VERSION 5.8 ;
BUSBITCHARS "[]" ;
DIVIDERCHAR "/" ;
UNITS
    DATABASE MICRONS 1000 ;
END UNITS

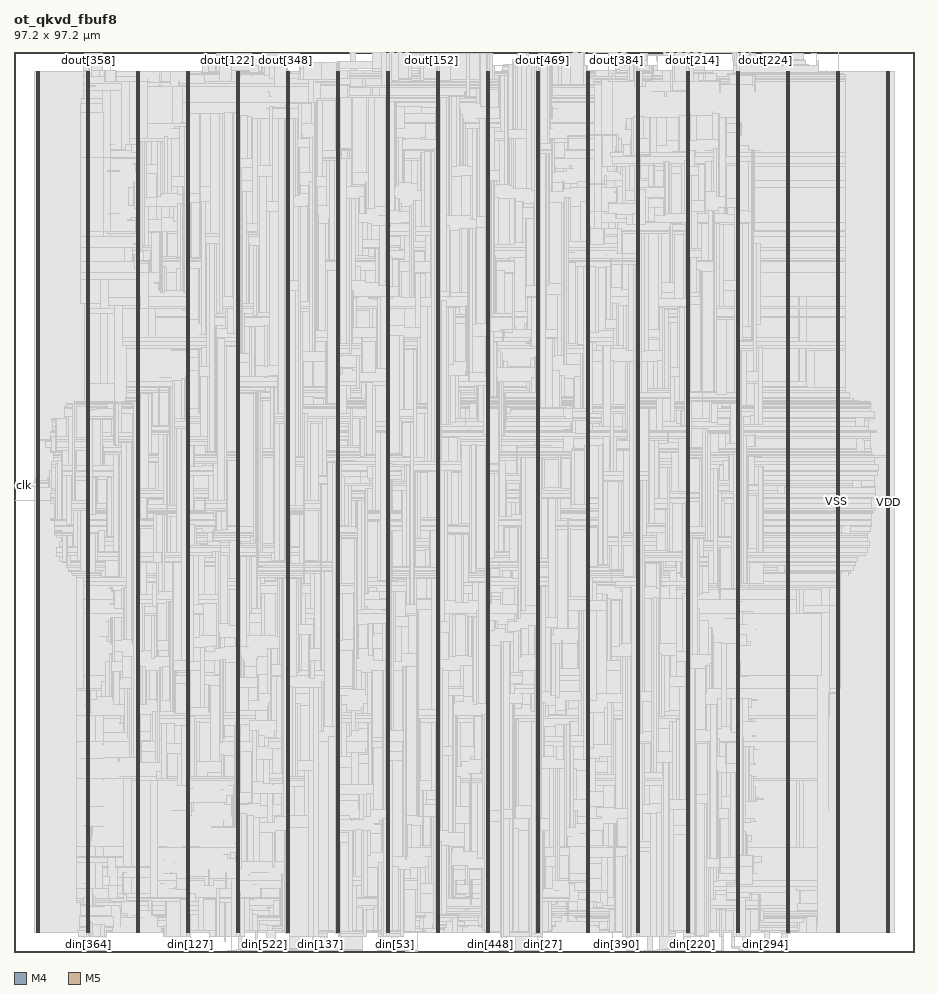
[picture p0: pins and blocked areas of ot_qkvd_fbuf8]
MACRO ot_qkvd_fbuf8
  FOREIGN ot_qkvd_fbuf8 0 0 ;
  CLASS BLOCK ;
  SIZE 97.2 BY 97.2 ;
  PIN clk
    DIRECTION INPUT ;
    USE SIGNAL ;
    PORT
      LAYER M4 ;
        RECT  0 50.352 0.084 50.376 ;
    END
  END clk
  PIN din[0]
    DIRECTION INPUT ;
    USE SIGNAL ;
    PORT
      LAYER M5 ;
        RECT  54.48 0 54.504 0.084 ;
    END
  END din[0]
  PIN din[100]
    DIRECTION INPUT ;
    USE SIGNAL ;
    PORT
      LAYER M5 ;
        RECT  16.464 0 16.488 0.084 ;
    END
  END din[100]
  PIN din[101]
    DIRECTION INPUT ;
    USE SIGNAL ;
    PORT
      LAYER M5 ;
        RECT  16.56 0 16.584 0.084 ;
    END
  END din[101]
  PIN din[102]
    DIRECTION INPUT ;
    USE SIGNAL ;
    PORT
      LAYER M5 ;
        RECT  16.656 0 16.68 0.084 ;
    END
  END din[102]
  PIN din[103]
    DIRECTION INPUT ;
    USE SIGNAL ;
    PORT
      LAYER M5 ;
        RECT  16.752 0 16.776 0.084 ;
    END
  END din[103]
  PIN din[104]
    DIRECTION INPUT ;
    USE SIGNAL ;
    PORT
      LAYER M5 ;
        RECT  16.848 0 16.872 0.084 ;
    END
  END din[104]
  PIN din[105]
    DIRECTION INPUT ;
    USE SIGNAL ;
    PORT
      LAYER M5 ;
        RECT  16.944 0 16.968 0.084 ;
    END
  END din[105]
  PIN din[106]
    DIRECTION INPUT ;
    USE SIGNAL ;
    PORT
      LAYER M5 ;
        RECT  17.04 0 17.064 0.084 ;
    END
  END din[106]
  PIN din[107]
    DIRECTION INPUT ;
    USE SIGNAL ;
    PORT
      LAYER M5 ;
        RECT  17.136 0 17.16 0.084 ;
    END
  END din[107]
  PIN din[108]
    DIRECTION INPUT ;
    USE SIGNAL ;
    PORT
      LAYER M5 ;
        RECT  17.232 0 17.256 0.084 ;
    END
  END din[108]
  PIN din[109]
    DIRECTION INPUT ;
    USE SIGNAL ;
    PORT
      LAYER M5 ;
        RECT  17.328 0 17.352 0.084 ;
    END
  END din[109]
  PIN din[10]
    DIRECTION INPUT ;
    USE SIGNAL ;
    PORT
      LAYER M5 ;
        RECT  55.44 0 55.464 0.084 ;
    END
  END din[10]
  PIN din[110]
    DIRECTION INPUT ;
    USE SIGNAL ;
    PORT
      LAYER M5 ;
        RECT  17.424 0 17.448 0.084 ;
    END
  END din[110]
  PIN din[111]
    DIRECTION INPUT ;
    USE SIGNAL ;
    PORT
      LAYER M5 ;
        RECT  17.52 0 17.544 0.084 ;
    END
  END din[111]
  PIN din[112]
    DIRECTION INPUT ;
    USE SIGNAL ;
    PORT
      LAYER M5 ;
        RECT  17.616 0 17.64 0.084 ;
    END
  END din[112]
  PIN din[113]
    DIRECTION INPUT ;
    USE SIGNAL ;
    PORT
      LAYER M5 ;
        RECT  17.712 0 17.736 0.084 ;
    END
  END din[113]
  PIN din[114]
    DIRECTION INPUT ;
    USE SIGNAL ;
    PORT
      LAYER M5 ;
        RECT  17.808 0 17.832 0.084 ;
    END
  END din[114]
  PIN din[115]
    DIRECTION INPUT ;
    USE SIGNAL ;
    PORT
      LAYER M5 ;
        RECT  17.904 0 17.928 0.084 ;
    END
  END din[115]
  PIN din[116]
    DIRECTION INPUT ;
    USE SIGNAL ;
    PORT
      LAYER M5 ;
        RECT  18 0 18.024 0.084 ;
    END
  END din[116]
  PIN din[117]
    DIRECTION INPUT ;
    USE SIGNAL ;
    PORT
      LAYER M5 ;
        RECT  18.096 0 18.12 0.084 ;
    END
  END din[117]
  PIN din[118]
    DIRECTION INPUT ;
    USE SIGNAL ;
    PORT
      LAYER M5 ;
        RECT  18.192 0 18.216 0.084 ;
    END
  END din[118]
  PIN din[119]
    DIRECTION INPUT ;
    USE SIGNAL ;
    PORT
      LAYER M5 ;
        RECT  18.288 0 18.312 0.084 ;
    END
  END din[119]
  PIN din[11]
    DIRECTION INPUT ;
    USE SIGNAL ;
    PORT
      LAYER M5 ;
        RECT  55.536 0 55.56 0.084 ;
    END
  END din[11]
  PIN din[120]
    DIRECTION INPUT ;
    USE SIGNAL ;
    PORT
      LAYER M5 ;
        RECT  18.384 0 18.408 0.084 ;
    END
  END din[120]
  PIN din[121]
    DIRECTION INPUT ;
    USE SIGNAL ;
    PORT
      LAYER M5 ;
        RECT  18.48 0 18.504 0.084 ;
    END
  END din[121]
  PIN din[122]
    DIRECTION INPUT ;
    USE SIGNAL ;
    PORT
      LAYER M5 ;
        RECT  18.576 0 18.6 0.084 ;
    END
  END din[122]
  PIN din[123]
    DIRECTION INPUT ;
    USE SIGNAL ;
    PORT
      LAYER M5 ;
        RECT  18.672 0 18.696 0.084 ;
    END
  END din[123]
  PIN din[124]
    DIRECTION INPUT ;
    USE SIGNAL ;
    PORT
      LAYER M5 ;
        RECT  18.768 0 18.792 0.084 ;
    END
  END din[124]
  PIN din[125]
    DIRECTION INPUT ;
    USE SIGNAL ;
    PORT
      LAYER M5 ;
        RECT  18.864 0 18.888 0.084 ;
    END
  END din[125]
  PIN din[126]
    DIRECTION INPUT ;
    USE SIGNAL ;
    PORT
      LAYER M5 ;
        RECT  18.96 0 18.984 0.084 ;
    END
  END din[126]
  PIN din[127]
    DIRECTION INPUT ;
    USE SIGNAL ;
    PORT
      LAYER M5 ;
        RECT  19.056 0 19.08 0.084 ;
    END
  END din[127]
  PIN din[128]
    DIRECTION INPUT ;
    USE SIGNAL ;
    PORT
      LAYER M5 ;
        RECT  32.208 0 32.232 0.084 ;
    END
  END din[128]
  PIN din[129]
    DIRECTION INPUT ;
    USE SIGNAL ;
    PORT
      LAYER M5 ;
        RECT  32.304 0 32.328 0.084 ;
    END
  END din[129]
  PIN din[12]
    DIRECTION INPUT ;
    USE SIGNAL ;
    PORT
      LAYER M5 ;
        RECT  55.632 0 55.656 0.084 ;
    END
  END din[12]
  PIN din[130]
    DIRECTION INPUT ;
    USE SIGNAL ;
    PORT
      LAYER M5 ;
        RECT  32.4 0 32.424 0.084 ;
    END
  END din[130]
  PIN din[131]
    DIRECTION INPUT ;
    USE SIGNAL ;
    PORT
      LAYER M5 ;
        RECT  32.496 0 32.52 0.084 ;
    END
  END din[131]
  PIN din[132]
    DIRECTION INPUT ;
    USE SIGNAL ;
    PORT
      LAYER M5 ;
        RECT  32.592 0 32.616 0.084 ;
    END
  END din[132]
  PIN din[133]
    DIRECTION INPUT ;
    USE SIGNAL ;
    PORT
      LAYER M5 ;
        RECT  32.688 0 32.712 0.084 ;
    END
  END din[133]
  PIN din[134]
    DIRECTION INPUT ;
    USE SIGNAL ;
    PORT
      LAYER M5 ;
        RECT  32.784 0 32.808 0.084 ;
    END
  END din[134]
  PIN din[135]
    DIRECTION INPUT ;
    USE SIGNAL ;
    PORT
      LAYER M5 ;
        RECT  32.88 0 32.904 0.084 ;
    END
  END din[135]
  PIN din[136]
    DIRECTION INPUT ;
    USE SIGNAL ;
    PORT
      LAYER M5 ;
        RECT  32.976 0 33 0.084 ;
    END
  END din[136]
  PIN din[137]
    DIRECTION INPUT ;
    USE SIGNAL ;
    PORT
      LAYER M5 ;
        RECT  33.072 0 33.096 0.084 ;
    END
  END din[137]
  PIN din[138]
    DIRECTION INPUT ;
    USE SIGNAL ;
    PORT
      LAYER M5 ;
        RECT  33.168 0 33.192 0.084 ;
    END
  END din[138]
  PIN din[139]
    DIRECTION INPUT ;
    USE SIGNAL ;
    PORT
      LAYER M5 ;
        RECT  33.264 0 33.288 0.084 ;
    END
  END din[139]
  PIN din[13]
    DIRECTION INPUT ;
    USE SIGNAL ;
    PORT
      LAYER M5 ;
        RECT  55.728 0 55.752 0.084 ;
    END
  END din[13]
  PIN din[140]
    DIRECTION INPUT ;
    USE SIGNAL ;
    PORT
      LAYER M5 ;
        RECT  33.36 0 33.384 0.084 ;
    END
  END din[140]
  PIN din[141]
    DIRECTION INPUT ;
    USE SIGNAL ;
    PORT
      LAYER M5 ;
        RECT  33.456 0 33.48 0.084 ;
    END
  END din[141]
  PIN din[142]
    DIRECTION INPUT ;
    USE SIGNAL ;
    PORT
      LAYER M5 ;
        RECT  33.552 0 33.576 0.084 ;
    END
  END din[142]
  PIN din[143]
    DIRECTION INPUT ;
    USE SIGNAL ;
    PORT
      LAYER M5 ;
        RECT  33.648 0 33.672 0.084 ;
    END
  END din[143]
  PIN din[144]
    DIRECTION INPUT ;
    USE SIGNAL ;
    PORT
      LAYER M5 ;
        RECT  33.744 0 33.768 0.084 ;
    END
  END din[144]
  PIN din[145]
    DIRECTION INPUT ;
    USE SIGNAL ;
    PORT
      LAYER M5 ;
        RECT  33.84 0 33.864 0.084 ;
    END
  END din[145]
  PIN din[146]
    DIRECTION INPUT ;
    USE SIGNAL ;
    PORT
      LAYER M5 ;
        RECT  33.936 0 33.96 0.084 ;
    END
  END din[146]
  PIN din[147]
    DIRECTION INPUT ;
    USE SIGNAL ;
    PORT
      LAYER M5 ;
        RECT  34.032 0 34.056 0.084 ;
    END
  END din[147]
  PIN din[148]
    DIRECTION INPUT ;
    USE SIGNAL ;
    PORT
      LAYER M5 ;
        RECT  34.128 0 34.152 0.084 ;
    END
  END din[148]
  PIN din[149]
    DIRECTION INPUT ;
    USE SIGNAL ;
    PORT
      LAYER M5 ;
        RECT  34.224 0 34.248 0.084 ;
    END
  END din[149]
  PIN din[14]
    DIRECTION INPUT ;
    USE SIGNAL ;
    PORT
      LAYER M5 ;
        RECT  55.824 0 55.848 0.084 ;
    END
  END din[14]
  PIN din[150]
    DIRECTION INPUT ;
    USE SIGNAL ;
    PORT
      LAYER M5 ;
        RECT  34.32 0 34.344 0.084 ;
    END
  END din[150]
  PIN din[151]
    DIRECTION INPUT ;
    USE SIGNAL ;
    PORT
      LAYER M5 ;
        RECT  34.416 0 34.44 0.084 ;
    END
  END din[151]
  PIN din[152]
    DIRECTION INPUT ;
    USE SIGNAL ;
    PORT
      LAYER M5 ;
        RECT  34.512 0 34.536 0.084 ;
    END
  END din[152]
  PIN din[153]
    DIRECTION INPUT ;
    USE SIGNAL ;
    PORT
      LAYER M5 ;
        RECT  34.608 0 34.632 0.084 ;
    END
  END din[153]
  PIN din[154]
    DIRECTION INPUT ;
    USE SIGNAL ;
    PORT
      LAYER M5 ;
        RECT  34.704 0 34.728 0.084 ;
    END
  END din[154]
  PIN din[155]
    DIRECTION INPUT ;
    USE SIGNAL ;
    PORT
      LAYER M5 ;
        RECT  34.8 0 34.824 0.084 ;
    END
  END din[155]
  PIN din[156]
    DIRECTION INPUT ;
    USE SIGNAL ;
    PORT
      LAYER M5 ;
        RECT  34.896 0 34.92 0.084 ;
    END
  END din[156]
  PIN din[157]
    DIRECTION INPUT ;
    USE SIGNAL ;
    PORT
      LAYER M5 ;
        RECT  34.992 0 35.016 0.084 ;
    END
  END din[157]
  PIN din[158]
    DIRECTION INPUT ;
    USE SIGNAL ;
    PORT
      LAYER M5 ;
        RECT  35.088 0 35.112 0.084 ;
    END
  END din[158]
  PIN din[159]
    DIRECTION INPUT ;
    USE SIGNAL ;
    PORT
      LAYER M5 ;
        RECT  35.184 0 35.208 0.084 ;
    END
  END din[159]
  PIN din[15]
    DIRECTION INPUT ;
    USE SIGNAL ;
    PORT
      LAYER M5 ;
        RECT  55.92 0 55.944 0.084 ;
    END
  END din[15]
  PIN din[160]
    DIRECTION INPUT ;
    USE SIGNAL ;
    PORT
      LAYER M5 ;
        RECT  19.92 0 19.944 0.084 ;
    END
  END din[160]
  PIN din[161]
    DIRECTION INPUT ;
    USE SIGNAL ;
    PORT
      LAYER M5 ;
        RECT  20.016 0 20.04 0.084 ;
    END
  END din[161]
  PIN din[162]
    DIRECTION INPUT ;
    USE SIGNAL ;
    PORT
      LAYER M5 ;
        RECT  20.112 0 20.136 0.084 ;
    END
  END din[162]
  PIN din[163]
    DIRECTION INPUT ;
    USE SIGNAL ;
    PORT
      LAYER M5 ;
        RECT  20.208 0 20.232 0.084 ;
    END
  END din[163]
  PIN din[164]
    DIRECTION INPUT ;
    USE SIGNAL ;
    PORT
      LAYER M5 ;
        RECT  20.304 0 20.328 0.084 ;
    END
  END din[164]
  PIN din[165]
    DIRECTION INPUT ;
    USE SIGNAL ;
    PORT
      LAYER M5 ;
        RECT  20.4 0 20.424 0.084 ;
    END
  END din[165]
  PIN din[166]
    DIRECTION INPUT ;
    USE SIGNAL ;
    PORT
      LAYER M5 ;
        RECT  20.496 0 20.52 0.084 ;
    END
  END din[166]
  PIN din[167]
    DIRECTION INPUT ;
    USE SIGNAL ;
    PORT
      LAYER M5 ;
        RECT  20.592 0 20.616 0.084 ;
    END
  END din[167]
  PIN din[168]
    DIRECTION INPUT ;
    USE SIGNAL ;
    PORT
      LAYER M5 ;
        RECT  20.688 0 20.712 0.084 ;
    END
  END din[168]
  PIN din[169]
    DIRECTION INPUT ;
    USE SIGNAL ;
    PORT
      LAYER M5 ;
        RECT  20.784 0 20.808 0.084 ;
    END
  END din[169]
  PIN din[16]
    DIRECTION INPUT ;
    USE SIGNAL ;
    PORT
      LAYER M5 ;
        RECT  56.016 0 56.04 0.084 ;
    END
  END din[16]
  PIN din[170]
    DIRECTION INPUT ;
    USE SIGNAL ;
    PORT
      LAYER M5 ;
        RECT  20.88 0 20.904 0.084 ;
    END
  END din[170]
  PIN din[171]
    DIRECTION INPUT ;
    USE SIGNAL ;
    PORT
      LAYER M5 ;
        RECT  20.976 0 21 0.084 ;
    END
  END din[171]
  PIN din[172]
    DIRECTION INPUT ;
    USE SIGNAL ;
    PORT
      LAYER M5 ;
        RECT  21.072 0 21.096 0.084 ;
    END
  END din[172]
  PIN din[173]
    DIRECTION INPUT ;
    USE SIGNAL ;
    PORT
      LAYER M5 ;
        RECT  21.168 0 21.192 0.084 ;
    END
  END din[173]
  PIN din[174]
    DIRECTION INPUT ;
    USE SIGNAL ;
    PORT
      LAYER M5 ;
        RECT  21.264 0 21.288 0.084 ;
    END
  END din[174]
  PIN din[175]
    DIRECTION INPUT ;
    USE SIGNAL ;
    PORT
      LAYER M5 ;
        RECT  21.36 0 21.384 0.084 ;
    END
  END din[175]
  PIN din[176]
    DIRECTION INPUT ;
    USE SIGNAL ;
    PORT
      LAYER M5 ;
        RECT  21.456 0 21.48 0.084 ;
    END
  END din[176]
  PIN din[177]
    DIRECTION INPUT ;
    USE SIGNAL ;
    PORT
      LAYER M5 ;
        RECT  21.552 0 21.576 0.084 ;
    END
  END din[177]
  PIN din[178]
    DIRECTION INPUT ;
    USE SIGNAL ;
    PORT
      LAYER M5 ;
        RECT  21.648 0 21.672 0.084 ;
    END
  END din[178]
  PIN din[179]
    DIRECTION INPUT ;
    USE SIGNAL ;
    PORT
      LAYER M5 ;
        RECT  21.744 0 21.768 0.084 ;
    END
  END din[179]
  PIN din[17]
    DIRECTION INPUT ;
    USE SIGNAL ;
    PORT
      LAYER M5 ;
        RECT  56.112 0 56.136 0.084 ;
    END
  END din[17]
  PIN din[180]
    DIRECTION INPUT ;
    USE SIGNAL ;
    PORT
      LAYER M5 ;
        RECT  21.84 0 21.864 0.084 ;
    END
  END din[180]
  PIN din[181]
    DIRECTION INPUT ;
    USE SIGNAL ;
    PORT
      LAYER M5 ;
        RECT  21.936 0 21.96 0.084 ;
    END
  END din[181]
  PIN din[182]
    DIRECTION INPUT ;
    USE SIGNAL ;
    PORT
      LAYER M5 ;
        RECT  22.032 0 22.056 0.084 ;
    END
  END din[182]
  PIN din[183]
    DIRECTION INPUT ;
    USE SIGNAL ;
    PORT
      LAYER M5 ;
        RECT  22.128 0 22.152 0.084 ;
    END
  END din[183]
  PIN din[184]
    DIRECTION INPUT ;
    USE SIGNAL ;
    PORT
      LAYER M5 ;
        RECT  22.224 0 22.248 0.084 ;
    END
  END din[184]
  PIN din[185]
    DIRECTION INPUT ;
    USE SIGNAL ;
    PORT
      LAYER M5 ;
        RECT  22.32 0 22.344 0.084 ;
    END
  END din[185]
  PIN din[186]
    DIRECTION INPUT ;
    USE SIGNAL ;
    PORT
      LAYER M5 ;
        RECT  22.416 0 22.44 0.084 ;
    END
  END din[186]
  PIN din[187]
    DIRECTION INPUT ;
    USE SIGNAL ;
    PORT
      LAYER M5 ;
        RECT  22.512 0 22.536 0.084 ;
    END
  END din[187]
  PIN din[188]
    DIRECTION INPUT ;
    USE SIGNAL ;
    PORT
      LAYER M5 ;
        RECT  22.608 0 22.632 0.084 ;
    END
  END din[188]
  PIN din[189]
    DIRECTION INPUT ;
    USE SIGNAL ;
    PORT
      LAYER M5 ;
        RECT  22.704 0 22.728 0.084 ;
    END
  END din[189]
  PIN din[18]
    DIRECTION INPUT ;
    USE SIGNAL ;
    PORT
      LAYER M5 ;
        RECT  56.208 0 56.232 0.084 ;
    END
  END din[18]
  PIN din[190]
    DIRECTION INPUT ;
    USE SIGNAL ;
    PORT
      LAYER M5 ;
        RECT  22.8 0 22.824 0.084 ;
    END
  END din[190]
  PIN din[191]
    DIRECTION INPUT ;
    USE SIGNAL ;
    PORT
      LAYER M5 ;
        RECT  22.896 0 22.92 0.084 ;
    END
  END din[191]
  PIN din[192]
    DIRECTION INPUT ;
    USE SIGNAL ;
    PORT
      LAYER M5 ;
        RECT  70.608 0 70.632 0.084 ;
    END
  END din[192]
  PIN din[193]
    DIRECTION INPUT ;
    USE SIGNAL ;
    PORT
      LAYER M5 ;
        RECT  70.704 0 70.728 0.084 ;
    END
  END din[193]
  PIN din[194]
    DIRECTION INPUT ;
    USE SIGNAL ;
    PORT
      LAYER M5 ;
        RECT  70.8 0 70.824 0.084 ;
    END
  END din[194]
  PIN din[195]
    DIRECTION INPUT ;
    USE SIGNAL ;
    PORT
      LAYER M5 ;
        RECT  70.896 0 70.92 0.084 ;
    END
  END din[195]
  PIN din[196]
    DIRECTION INPUT ;
    USE SIGNAL ;
    PORT
      LAYER M5 ;
        RECT  70.992 0 71.016 0.084 ;
    END
  END din[196]
  PIN din[197]
    DIRECTION INPUT ;
    USE SIGNAL ;
    PORT
      LAYER M5 ;
        RECT  71.088 0 71.112 0.084 ;
    END
  END din[197]
  PIN din[198]
    DIRECTION INPUT ;
    USE SIGNAL ;
    PORT
      LAYER M5 ;
        RECT  71.184 0 71.208 0.084 ;
    END
  END din[198]
  PIN din[199]
    DIRECTION INPUT ;
    USE SIGNAL ;
    PORT
      LAYER M5 ;
        RECT  71.28 0 71.304 0.084 ;
    END
  END din[199]
  PIN din[19]
    DIRECTION INPUT ;
    USE SIGNAL ;
    PORT
      LAYER M5 ;
        RECT  56.304 0 56.328 0.084 ;
    END
  END din[19]
  PIN din[1]
    DIRECTION INPUT ;
    USE SIGNAL ;
    PORT
      LAYER M5 ;
        RECT  54.576 0 54.6 0.084 ;
    END
  END din[1]
  PIN din[200]
    DIRECTION INPUT ;
    USE SIGNAL ;
    PORT
      LAYER M5 ;
        RECT  71.376 0 71.4 0.084 ;
    END
  END din[200]
  PIN din[201]
    DIRECTION INPUT ;
    USE SIGNAL ;
    PORT
      LAYER M5 ;
        RECT  71.472 0 71.496 0.084 ;
    END
  END din[201]
  PIN din[202]
    DIRECTION INPUT ;
    USE SIGNAL ;
    PORT
      LAYER M5 ;
        RECT  71.568 0 71.592 0.084 ;
    END
  END din[202]
  PIN din[203]
    DIRECTION INPUT ;
    USE SIGNAL ;
    PORT
      LAYER M5 ;
        RECT  71.664 0 71.688 0.084 ;
    END
  END din[203]
  PIN din[204]
    DIRECTION INPUT ;
    USE SIGNAL ;
    PORT
      LAYER M5 ;
        RECT  71.76 0 71.784 0.084 ;
    END
  END din[204]
  PIN din[205]
    DIRECTION INPUT ;
    USE SIGNAL ;
    PORT
      LAYER M5 ;
        RECT  71.856 0 71.88 0.084 ;
    END
  END din[205]
  PIN din[206]
    DIRECTION INPUT ;
    USE SIGNAL ;
    PORT
      LAYER M5 ;
        RECT  71.952 0 71.976 0.084 ;
    END
  END din[206]
  PIN din[207]
    DIRECTION INPUT ;
    USE SIGNAL ;
    PORT
      LAYER M5 ;
        RECT  72.048 0 72.072 0.084 ;
    END
  END din[207]
  PIN din[208]
    DIRECTION INPUT ;
    USE SIGNAL ;
    PORT
      LAYER M5 ;
        RECT  72.144 0 72.168 0.084 ;
    END
  END din[208]
  PIN din[209]
    DIRECTION INPUT ;
    USE SIGNAL ;
    PORT
      LAYER M5 ;
        RECT  72.24 0 72.264 0.084 ;
    END
  END din[209]
  PIN din[20]
    DIRECTION INPUT ;
    USE SIGNAL ;
    PORT
      LAYER M5 ;
        RECT  56.4 0 56.424 0.084 ;
    END
  END din[20]
  PIN din[210]
    DIRECTION INPUT ;
    USE SIGNAL ;
    PORT
      LAYER M5 ;
        RECT  72.336 0 72.36 0.084 ;
    END
  END din[210]
  PIN din[211]
    DIRECTION INPUT ;
    USE SIGNAL ;
    PORT
      LAYER M5 ;
        RECT  72.432 0 72.456 0.084 ;
    END
  END din[211]
  PIN din[212]
    DIRECTION INPUT ;
    USE SIGNAL ;
    PORT
      LAYER M5 ;
        RECT  72.528 0 72.552 0.084 ;
    END
  END din[212]
  PIN din[213]
    DIRECTION INPUT ;
    USE SIGNAL ;
    PORT
      LAYER M5 ;
        RECT  72.624 0 72.648 0.084 ;
    END
  END din[213]
  PIN din[214]
    DIRECTION INPUT ;
    USE SIGNAL ;
    PORT
      LAYER M5 ;
        RECT  72.72 0 72.744 0.084 ;
    END
  END din[214]
  PIN din[215]
    DIRECTION INPUT ;
    USE SIGNAL ;
    PORT
      LAYER M5 ;
        RECT  72.816 0 72.84 0.084 ;
    END
  END din[215]
  PIN din[216]
    DIRECTION INPUT ;
    USE SIGNAL ;
    PORT
      LAYER M5 ;
        RECT  72.912 0 72.936 0.084 ;
    END
  END din[216]
  PIN din[217]
    DIRECTION INPUT ;
    USE SIGNAL ;
    PORT
      LAYER M5 ;
        RECT  73.008 0 73.032 0.084 ;
    END
  END din[217]
  PIN din[218]
    DIRECTION INPUT ;
    USE SIGNAL ;
    PORT
      LAYER M5 ;
        RECT  73.104 0 73.128 0.084 ;
    END
  END din[218]
  PIN din[219]
    DIRECTION INPUT ;
    USE SIGNAL ;
    PORT
      LAYER M5 ;
        RECT  73.2 0 73.224 0.084 ;
    END
  END din[219]
  PIN din[21]
    DIRECTION INPUT ;
    USE SIGNAL ;
    PORT
      LAYER M5 ;
        RECT  56.496 0 56.52 0.084 ;
    END
  END din[21]
  PIN din[220]
    DIRECTION INPUT ;
    USE SIGNAL ;
    PORT
      LAYER M5 ;
        RECT  73.296 0 73.32 0.084 ;
    END
  END din[220]
  PIN din[221]
    DIRECTION INPUT ;
    USE SIGNAL ;
    PORT
      LAYER M5 ;
        RECT  73.392 0 73.416 0.084 ;
    END
  END din[221]
  PIN din[222]
    DIRECTION INPUT ;
    USE SIGNAL ;
    PORT
      LAYER M5 ;
        RECT  73.488 0 73.512 0.084 ;
    END
  END din[222]
  PIN din[223]
    DIRECTION INPUT ;
    USE SIGNAL ;
    PORT
      LAYER M5 ;
        RECT  73.584 0 73.608 0.084 ;
    END
  END din[223]
  PIN din[224]
    DIRECTION INPUT ;
    USE SIGNAL ;
    PORT
      LAYER M5 ;
        RECT  77.52 0 77.544 0.084 ;
    END
  END din[224]
  PIN din[225]
    DIRECTION INPUT ;
    USE SIGNAL ;
    PORT
      LAYER M5 ;
        RECT  77.616 0 77.64 0.084 ;
    END
  END din[225]
  PIN din[226]
    DIRECTION INPUT ;
    USE SIGNAL ;
    PORT
      LAYER M5 ;
        RECT  77.712 0 77.736 0.084 ;
    END
  END din[226]
  PIN din[227]
    DIRECTION INPUT ;
    USE SIGNAL ;
    PORT
      LAYER M5 ;
        RECT  77.808 0 77.832 0.084 ;
    END
  END din[227]
  PIN din[228]
    DIRECTION INPUT ;
    USE SIGNAL ;
    PORT
      LAYER M5 ;
        RECT  77.904 0 77.928 0.084 ;
    END
  END din[228]
  PIN din[229]
    DIRECTION INPUT ;
    USE SIGNAL ;
    PORT
      LAYER M5 ;
        RECT  78 0 78.024 0.084 ;
    END
  END din[229]
  PIN din[22]
    DIRECTION INPUT ;
    USE SIGNAL ;
    PORT
      LAYER M5 ;
        RECT  56.592 0 56.616 0.084 ;
    END
  END din[22]
  PIN din[230]
    DIRECTION INPUT ;
    USE SIGNAL ;
    PORT
      LAYER M5 ;
        RECT  78.096 0 78.12 0.084 ;
    END
  END din[230]
  PIN din[231]
    DIRECTION INPUT ;
    USE SIGNAL ;
    PORT
      LAYER M5 ;
        RECT  78.192 0 78.216 0.084 ;
    END
  END din[231]
  PIN din[232]
    DIRECTION INPUT ;
    USE SIGNAL ;
    PORT
      LAYER M5 ;
        RECT  78.288 0 78.312 0.084 ;
    END
  END din[232]
  PIN din[233]
    DIRECTION INPUT ;
    USE SIGNAL ;
    PORT
      LAYER M5 ;
        RECT  78.384 0 78.408 0.084 ;
    END
  END din[233]
  PIN din[234]
    DIRECTION INPUT ;
    USE SIGNAL ;
    PORT
      LAYER M5 ;
        RECT  78.48 0 78.504 0.084 ;
    END
  END din[234]
  PIN din[235]
    DIRECTION INPUT ;
    USE SIGNAL ;
    PORT
      LAYER M5 ;
        RECT  78.576 0 78.6 0.084 ;
    END
  END din[235]
  PIN din[236]
    DIRECTION INPUT ;
    USE SIGNAL ;
    PORT
      LAYER M5 ;
        RECT  78.672 0 78.696 0.084 ;
    END
  END din[236]
  PIN din[237]
    DIRECTION INPUT ;
    USE SIGNAL ;
    PORT
      LAYER M5 ;
        RECT  78.768 0 78.792 0.084 ;
    END
  END din[237]
  PIN din[238]
    DIRECTION INPUT ;
    USE SIGNAL ;
    PORT
      LAYER M5 ;
        RECT  78.864 0 78.888 0.084 ;
    END
  END din[238]
  PIN din[239]
    DIRECTION INPUT ;
    USE SIGNAL ;
    PORT
      LAYER M5 ;
        RECT  78.96 0 78.984 0.084 ;
    END
  END din[239]
  PIN din[23]
    DIRECTION INPUT ;
    USE SIGNAL ;
    PORT
      LAYER M5 ;
        RECT  56.688 0 56.712 0.084 ;
    END
  END din[23]
  PIN din[240]
    DIRECTION INPUT ;
    USE SIGNAL ;
    PORT
      LAYER M5 ;
        RECT  79.056 0 79.08 0.084 ;
    END
  END din[240]
  PIN din[241]
    DIRECTION INPUT ;
    USE SIGNAL ;
    PORT
      LAYER M5 ;
        RECT  79.152 0 79.176 0.084 ;
    END
  END din[241]
  PIN din[242]
    DIRECTION INPUT ;
    USE SIGNAL ;
    PORT
      LAYER M5 ;
        RECT  79.248 0 79.272 0.084 ;
    END
  END din[242]
  PIN din[243]
    DIRECTION INPUT ;
    USE SIGNAL ;
    PORT
      LAYER M5 ;
        RECT  79.344 0 79.368 0.084 ;
    END
  END din[243]
  PIN din[244]
    DIRECTION INPUT ;
    USE SIGNAL ;
    PORT
      LAYER M5 ;
        RECT  79.44 0 79.464 0.084 ;
    END
  END din[244]
  PIN din[245]
    DIRECTION INPUT ;
    USE SIGNAL ;
    PORT
      LAYER M5 ;
        RECT  79.536 0 79.56 0.084 ;
    END
  END din[245]
  PIN din[246]
    DIRECTION INPUT ;
    USE SIGNAL ;
    PORT
      LAYER M5 ;
        RECT  79.632 0 79.656 0.084 ;
    END
  END din[246]
  PIN din[247]
    DIRECTION INPUT ;
    USE SIGNAL ;
    PORT
      LAYER M5 ;
        RECT  79.728 0 79.752 0.084 ;
    END
  END din[247]
  PIN din[248]
    DIRECTION INPUT ;
    USE SIGNAL ;
    PORT
      LAYER M5 ;
        RECT  79.824 0 79.848 0.084 ;
    END
  END din[248]
  PIN din[249]
    DIRECTION INPUT ;
    USE SIGNAL ;
    PORT
      LAYER M5 ;
        RECT  79.92 0 79.944 0.084 ;
    END
  END din[249]
  PIN din[24]
    DIRECTION INPUT ;
    USE SIGNAL ;
    PORT
      LAYER M5 ;
        RECT  56.784 0 56.808 0.084 ;
    END
  END din[24]
  PIN din[250]
    DIRECTION INPUT ;
    USE SIGNAL ;
    PORT
      LAYER M5 ;
        RECT  80.016 0 80.04 0.084 ;
    END
  END din[250]
  PIN din[251]
    DIRECTION INPUT ;
    USE SIGNAL ;
    PORT
      LAYER M5 ;
        RECT  80.112 0 80.136 0.084 ;
    END
  END din[251]
  PIN din[252]
    DIRECTION INPUT ;
    USE SIGNAL ;
    PORT
      LAYER M5 ;
        RECT  80.208 0 80.232 0.084 ;
    END
  END din[252]
  PIN din[253]
    DIRECTION INPUT ;
    USE SIGNAL ;
    PORT
      LAYER M5 ;
        RECT  80.304 0 80.328 0.084 ;
    END
  END din[253]
  PIN din[254]
    DIRECTION INPUT ;
    USE SIGNAL ;
    PORT
      LAYER M5 ;
        RECT  80.4 0 80.424 0.084 ;
    END
  END din[254]
  PIN din[255]
    DIRECTION INPUT ;
    USE SIGNAL ;
    PORT
      LAYER M5 ;
        RECT  80.496 0 80.52 0.084 ;
    END
  END din[255]
  PIN din[256]
    DIRECTION INPUT ;
    USE SIGNAL ;
    PORT
      LAYER M5 ;
        RECT  73.68 0 73.704 0.084 ;
    END
  END din[256]
  PIN din[257]
    DIRECTION INPUT ;
    USE SIGNAL ;
    PORT
      LAYER M5 ;
        RECT  73.776 0 73.8 0.084 ;
    END
  END din[257]
  PIN din[258]
    DIRECTION INPUT ;
    USE SIGNAL ;
    PORT
      LAYER M5 ;
        RECT  73.872 0 73.896 0.084 ;
    END
  END din[258]
  PIN din[259]
    DIRECTION INPUT ;
    USE SIGNAL ;
    PORT
      LAYER M5 ;
        RECT  73.968 0 73.992 0.084 ;
    END
  END din[259]
  PIN din[25]
    DIRECTION INPUT ;
    USE SIGNAL ;
    PORT
      LAYER M5 ;
        RECT  56.88 0 56.904 0.084 ;
    END
  END din[25]
  PIN din[260]
    DIRECTION INPUT ;
    USE SIGNAL ;
    PORT
      LAYER M5 ;
        RECT  74.064 0 74.088 0.084 ;
    END
  END din[260]
  PIN din[261]
    DIRECTION INPUT ;
    USE SIGNAL ;
    PORT
      LAYER M5 ;
        RECT  74.16 0 74.184 0.084 ;
    END
  END din[261]
  PIN din[262]
    DIRECTION INPUT ;
    USE SIGNAL ;
    PORT
      LAYER M5 ;
        RECT  74.256 0 74.28 0.084 ;
    END
  END din[262]
  PIN din[263]
    DIRECTION INPUT ;
    USE SIGNAL ;
    PORT
      LAYER M5 ;
        RECT  74.352 0 74.376 0.084 ;
    END
  END din[263]
  PIN din[264]
    DIRECTION INPUT ;
    USE SIGNAL ;
    PORT
      LAYER M5 ;
        RECT  74.448 0 74.472 0.084 ;
    END
  END din[264]
  PIN din[265]
    DIRECTION INPUT ;
    USE SIGNAL ;
    PORT
      LAYER M5 ;
        RECT  74.544 0 74.568 0.084 ;
    END
  END din[265]
  PIN din[266]
    DIRECTION INPUT ;
    USE SIGNAL ;
    PORT
      LAYER M5 ;
        RECT  74.64 0 74.664 0.084 ;
    END
  END din[266]
  PIN din[267]
    DIRECTION INPUT ;
    USE SIGNAL ;
    PORT
      LAYER M5 ;
        RECT  74.736 0 74.76 0.084 ;
    END
  END din[267]
  PIN din[268]
    DIRECTION INPUT ;
    USE SIGNAL ;
    PORT
      LAYER M5 ;
        RECT  74.832 0 74.856 0.084 ;
    END
  END din[268]
  PIN din[269]
    DIRECTION INPUT ;
    USE SIGNAL ;
    PORT
      LAYER M5 ;
        RECT  74.928 0 74.952 0.084 ;
    END
  END din[269]
  PIN din[26]
    DIRECTION INPUT ;
    USE SIGNAL ;
    PORT
      LAYER M5 ;
        RECT  56.976 0 57 0.084 ;
    END
  END din[26]
  PIN din[270]
    DIRECTION INPUT ;
    USE SIGNAL ;
    PORT
      LAYER M5 ;
        RECT  75.024 0 75.048 0.084 ;
    END
  END din[270]
  PIN din[271]
    DIRECTION INPUT ;
    USE SIGNAL ;
    PORT
      LAYER M5 ;
        RECT  75.12 0 75.144 0.084 ;
    END
  END din[271]
  PIN din[272]
    DIRECTION INPUT ;
    USE SIGNAL ;
    PORT
      LAYER M5 ;
        RECT  75.216 0 75.24 0.084 ;
    END
  END din[272]
  PIN din[273]
    DIRECTION INPUT ;
    USE SIGNAL ;
    PORT
      LAYER M5 ;
        RECT  75.312 0 75.336 0.084 ;
    END
  END din[273]
  PIN din[274]
    DIRECTION INPUT ;
    USE SIGNAL ;
    PORT
      LAYER M5 ;
        RECT  75.408 0 75.432 0.084 ;
    END
  END din[274]
  PIN din[275]
    DIRECTION INPUT ;
    USE SIGNAL ;
    PORT
      LAYER M5 ;
        RECT  75.504 0 75.528 0.084 ;
    END
  END din[275]
  PIN din[276]
    DIRECTION INPUT ;
    USE SIGNAL ;
    PORT
      LAYER M5 ;
        RECT  75.6 0 75.624 0.084 ;
    END
  END din[276]
  PIN din[277]
    DIRECTION INPUT ;
    USE SIGNAL ;
    PORT
      LAYER M5 ;
        RECT  75.696 0 75.72 0.084 ;
    END
  END din[277]
  PIN din[278]
    DIRECTION INPUT ;
    USE SIGNAL ;
    PORT
      LAYER M5 ;
        RECT  75.792 0 75.816 0.084 ;
    END
  END din[278]
  PIN din[279]
    DIRECTION INPUT ;
    USE SIGNAL ;
    PORT
      LAYER M5 ;
        RECT  75.888 0 75.912 0.084 ;
    END
  END din[279]
  PIN din[27]
    DIRECTION INPUT ;
    USE SIGNAL ;
    PORT
      LAYER M5 ;
        RECT  57.072 0 57.096 0.084 ;
    END
  END din[27]
  PIN din[280]
    DIRECTION INPUT ;
    USE SIGNAL ;
    PORT
      LAYER M5 ;
        RECT  75.984 0 76.008 0.084 ;
    END
  END din[280]
  PIN din[281]
    DIRECTION INPUT ;
    USE SIGNAL ;
    PORT
      LAYER M5 ;
        RECT  76.08 0 76.104 0.084 ;
    END
  END din[281]
  PIN din[282]
    DIRECTION INPUT ;
    USE SIGNAL ;
    PORT
      LAYER M5 ;
        RECT  76.176 0 76.2 0.084 ;
    END
  END din[282]
  PIN din[283]
    DIRECTION INPUT ;
    USE SIGNAL ;
    PORT
      LAYER M5 ;
        RECT  76.272 0 76.296 0.084 ;
    END
  END din[283]
  PIN din[284]
    DIRECTION INPUT ;
    USE SIGNAL ;
    PORT
      LAYER M5 ;
        RECT  76.368 0 76.392 0.084 ;
    END
  END din[284]
  PIN din[285]
    DIRECTION INPUT ;
    USE SIGNAL ;
    PORT
      LAYER M5 ;
        RECT  76.464 0 76.488 0.084 ;
    END
  END din[285]
  PIN din[286]
    DIRECTION INPUT ;
    USE SIGNAL ;
    PORT
      LAYER M5 ;
        RECT  76.56 0 76.584 0.084 ;
    END
  END din[286]
  PIN din[287]
    DIRECTION INPUT ;
    USE SIGNAL ;
    PORT
      LAYER M5 ;
        RECT  76.656 0 76.68 0.084 ;
    END
  END din[287]
  PIN din[288]
    DIRECTION INPUT ;
    USE SIGNAL ;
    PORT
      LAYER M5 ;
        RECT  80.592 0 80.616 0.084 ;
    END
  END din[288]
  PIN din[289]
    DIRECTION INPUT ;
    USE SIGNAL ;
    PORT
      LAYER M5 ;
        RECT  80.688 0 80.712 0.084 ;
    END
  END din[289]
  PIN din[28]
    DIRECTION INPUT ;
    USE SIGNAL ;
    PORT
      LAYER M5 ;
        RECT  57.168 0 57.192 0.084 ;
    END
  END din[28]
  PIN din[290]
    DIRECTION INPUT ;
    USE SIGNAL ;
    PORT
      LAYER M5 ;
        RECT  80.784 0 80.808 0.084 ;
    END
  END din[290]
  PIN din[291]
    DIRECTION INPUT ;
    USE SIGNAL ;
    PORT
      LAYER M5 ;
        RECT  80.88 0 80.904 0.084 ;
    END
  END din[291]
  PIN din[292]
    DIRECTION INPUT ;
    USE SIGNAL ;
    PORT
      LAYER M5 ;
        RECT  80.976 0 81 0.084 ;
    END
  END din[292]
  PIN din[293]
    DIRECTION INPUT ;
    USE SIGNAL ;
    PORT
      LAYER M5 ;
        RECT  81.072 0 81.096 0.084 ;
    END
  END din[293]
  PIN din[294]
    DIRECTION INPUT ;
    USE SIGNAL ;
    PORT
      LAYER M5 ;
        RECT  81.168 0 81.192 0.084 ;
    END
  END din[294]
  PIN din[295]
    DIRECTION INPUT ;
    USE SIGNAL ;
    PORT
      LAYER M5 ;
        RECT  81.264 0 81.288 0.084 ;
    END
  END din[295]
  PIN din[296]
    DIRECTION INPUT ;
    USE SIGNAL ;
    PORT
      LAYER M5 ;
        RECT  81.36 0 81.384 0.084 ;
    END
  END din[296]
  PIN din[297]
    DIRECTION INPUT ;
    USE SIGNAL ;
    PORT
      LAYER M5 ;
        RECT  81.456 0 81.48 0.084 ;
    END
  END din[297]
  PIN din[298]
    DIRECTION INPUT ;
    USE SIGNAL ;
    PORT
      LAYER M5 ;
        RECT  81.552 0 81.576 0.084 ;
    END
  END din[298]
  PIN din[299]
    DIRECTION INPUT ;
    USE SIGNAL ;
    PORT
      LAYER M5 ;
        RECT  81.648 0 81.672 0.084 ;
    END
  END din[299]
  PIN din[29]
    DIRECTION INPUT ;
    USE SIGNAL ;
    PORT
      LAYER M5 ;
        RECT  57.264 0 57.288 0.084 ;
    END
  END din[29]
  PIN din[2]
    DIRECTION INPUT ;
    USE SIGNAL ;
    PORT
      LAYER M5 ;
        RECT  54.672 0 54.696 0.084 ;
    END
  END din[2]
  PIN din[300]
    DIRECTION INPUT ;
    USE SIGNAL ;
    PORT
      LAYER M5 ;
        RECT  81.744 0 81.768 0.084 ;
    END
  END din[300]
  PIN din[301]
    DIRECTION INPUT ;
    USE SIGNAL ;
    PORT
      LAYER M5 ;
        RECT  81.84 0 81.864 0.084 ;
    END
  END din[301]
  PIN din[302]
    DIRECTION INPUT ;
    USE SIGNAL ;
    PORT
      LAYER M5 ;
        RECT  81.936 0 81.96 0.084 ;
    END
  END din[302]
  PIN din[303]
    DIRECTION INPUT ;
    USE SIGNAL ;
    PORT
      LAYER M5 ;
        RECT  82.032 0 82.056 0.084 ;
    END
  END din[303]
  PIN din[304]
    DIRECTION INPUT ;
    USE SIGNAL ;
    PORT
      LAYER M5 ;
        RECT  82.128 0 82.152 0.084 ;
    END
  END din[304]
  PIN din[305]
    DIRECTION INPUT ;
    USE SIGNAL ;
    PORT
      LAYER M5 ;
        RECT  82.224 0 82.248 0.084 ;
    END
  END din[305]
  PIN din[306]
    DIRECTION INPUT ;
    USE SIGNAL ;
    PORT
      LAYER M5 ;
        RECT  82.32 0 82.344 0.084 ;
    END
  END din[306]
  PIN din[307]
    DIRECTION INPUT ;
    USE SIGNAL ;
    PORT
      LAYER M5 ;
        RECT  82.416 0 82.44 0.084 ;
    END
  END din[307]
  PIN din[308]
    DIRECTION INPUT ;
    USE SIGNAL ;
    PORT
      LAYER M5 ;
        RECT  82.512 0 82.536 0.084 ;
    END
  END din[308]
  PIN din[309]
    DIRECTION INPUT ;
    USE SIGNAL ;
    PORT
      LAYER M5 ;
        RECT  82.608 0 82.632 0.084 ;
    END
  END din[309]
  PIN din[30]
    DIRECTION INPUT ;
    USE SIGNAL ;
    PORT
      LAYER M5 ;
        RECT  57.36 0 57.384 0.084 ;
    END
  END din[30]
  PIN din[310]
    DIRECTION INPUT ;
    USE SIGNAL ;
    PORT
      LAYER M5 ;
        RECT  82.704 0 82.728 0.084 ;
    END
  END din[310]
  PIN din[311]
    DIRECTION INPUT ;
    USE SIGNAL ;
    PORT
      LAYER M5 ;
        RECT  82.8 0 82.824 0.084 ;
    END
  END din[311]
  PIN din[312]
    DIRECTION INPUT ;
    USE SIGNAL ;
    PORT
      LAYER M5 ;
        RECT  82.896 0 82.92 0.084 ;
    END
  END din[312]
  PIN din[313]
    DIRECTION INPUT ;
    USE SIGNAL ;
    PORT
      LAYER M5 ;
        RECT  82.992 0 83.016 0.084 ;
    END
  END din[313]
  PIN din[314]
    DIRECTION INPUT ;
    USE SIGNAL ;
    PORT
      LAYER M5 ;
        RECT  83.088 0 83.112 0.084 ;
    END
  END din[314]
  PIN din[315]
    DIRECTION INPUT ;
    USE SIGNAL ;
    PORT
      LAYER M5 ;
        RECT  83.184 0 83.208 0.084 ;
    END
  END din[315]
  PIN din[316]
    DIRECTION INPUT ;
    USE SIGNAL ;
    PORT
      LAYER M5 ;
        RECT  83.28 0 83.304 0.084 ;
    END
  END din[316]
  PIN din[317]
    DIRECTION INPUT ;
    USE SIGNAL ;
    PORT
      LAYER M5 ;
        RECT  83.376 0 83.4 0.084 ;
    END
  END din[317]
  PIN din[318]
    DIRECTION INPUT ;
    USE SIGNAL ;
    PORT
      LAYER M5 ;
        RECT  83.472 0 83.496 0.084 ;
    END
  END din[318]
  PIN din[319]
    DIRECTION INPUT ;
    USE SIGNAL ;
    PORT
      LAYER M5 ;
        RECT  83.568 0 83.592 0.084 ;
    END
  END din[319]
  PIN din[31]
    DIRECTION INPUT ;
    USE SIGNAL ;
    PORT
      LAYER M5 ;
        RECT  57.456 0 57.48 0.084 ;
    END
  END din[31]
  PIN din[320]
    DIRECTION INPUT ;
    USE SIGNAL ;
    PORT
      LAYER M5 ;
        RECT  22.992 0 23.016 0.084 ;
    END
  END din[320]
  PIN din[321]
    DIRECTION INPUT ;
    USE SIGNAL ;
    PORT
      LAYER M5 ;
        RECT  23.088 0 23.112 0.084 ;
    END
  END din[321]
  PIN din[322]
    DIRECTION INPUT ;
    USE SIGNAL ;
    PORT
      LAYER M5 ;
        RECT  23.184 0 23.208 0.084 ;
    END
  END din[322]
  PIN din[323]
    DIRECTION INPUT ;
    USE SIGNAL ;
    PORT
      LAYER M5 ;
        RECT  23.28 0 23.304 0.084 ;
    END
  END din[323]
  PIN din[324]
    DIRECTION INPUT ;
    USE SIGNAL ;
    PORT
      LAYER M5 ;
        RECT  23.376 0 23.4 0.084 ;
    END
  END din[324]
  PIN din[325]
    DIRECTION INPUT ;
    USE SIGNAL ;
    PORT
      LAYER M5 ;
        RECT  23.472 0 23.496 0.084 ;
    END
  END din[325]
  PIN din[326]
    DIRECTION INPUT ;
    USE SIGNAL ;
    PORT
      LAYER M5 ;
        RECT  23.568 0 23.592 0.084 ;
    END
  END din[326]
  PIN din[327]
    DIRECTION INPUT ;
    USE SIGNAL ;
    PORT
      LAYER M5 ;
        RECT  23.664 0 23.688 0.084 ;
    END
  END din[327]
  PIN din[328]
    DIRECTION INPUT ;
    USE SIGNAL ;
    PORT
      LAYER M5 ;
        RECT  23.76 0 23.784 0.084 ;
    END
  END din[328]
  PIN din[329]
    DIRECTION INPUT ;
    USE SIGNAL ;
    PORT
      LAYER M5 ;
        RECT  23.856 0 23.88 0.084 ;
    END
  END din[329]
  PIN din[32]
    DIRECTION INPUT ;
    USE SIGNAL ;
    PORT
      LAYER M5 ;
        RECT  39.12 0 39.144 0.084 ;
    END
  END din[32]
  PIN din[330]
    DIRECTION INPUT ;
    USE SIGNAL ;
    PORT
      LAYER M5 ;
        RECT  23.952 0 23.976 0.084 ;
    END
  END din[330]
  PIN din[331]
    DIRECTION INPUT ;
    USE SIGNAL ;
    PORT
      LAYER M5 ;
        RECT  24.048 0 24.072 0.084 ;
    END
  END din[331]
  PIN din[332]
    DIRECTION INPUT ;
    USE SIGNAL ;
    PORT
      LAYER M5 ;
        RECT  24.144 0 24.168 0.084 ;
    END
  END din[332]
  PIN din[333]
    DIRECTION INPUT ;
    USE SIGNAL ;
    PORT
      LAYER M5 ;
        RECT  24.24 0 24.264 0.084 ;
    END
  END din[333]
  PIN din[334]
    DIRECTION INPUT ;
    USE SIGNAL ;
    PORT
      LAYER M5 ;
        RECT  24.336 0 24.36 0.084 ;
    END
  END din[334]
  PIN din[335]
    DIRECTION INPUT ;
    USE SIGNAL ;
    PORT
      LAYER M5 ;
        RECT  24.432 0 24.456 0.084 ;
    END
  END din[335]
  PIN din[336]
    DIRECTION INPUT ;
    USE SIGNAL ;
    PORT
      LAYER M5 ;
        RECT  24.528 0 24.552 0.084 ;
    END
  END din[336]
  PIN din[337]
    DIRECTION INPUT ;
    USE SIGNAL ;
    PORT
      LAYER M5 ;
        RECT  24.624 0 24.648 0.084 ;
    END
  END din[337]
  PIN din[338]
    DIRECTION INPUT ;
    USE SIGNAL ;
    PORT
      LAYER M5 ;
        RECT  24.72 0 24.744 0.084 ;
    END
  END din[338]
  PIN din[339]
    DIRECTION INPUT ;
    USE SIGNAL ;
    PORT
      LAYER M5 ;
        RECT  24.816 0 24.84 0.084 ;
    END
  END din[339]
  PIN din[33]
    DIRECTION INPUT ;
    USE SIGNAL ;
    PORT
      LAYER M5 ;
        RECT  39.216 0 39.24 0.084 ;
    END
  END din[33]
  PIN din[340]
    DIRECTION INPUT ;
    USE SIGNAL ;
    PORT
      LAYER M5 ;
        RECT  24.912 0 24.936 0.084 ;
    END
  END din[340]
  PIN din[341]
    DIRECTION INPUT ;
    USE SIGNAL ;
    PORT
      LAYER M5 ;
        RECT  25.008 0 25.032 0.084 ;
    END
  END din[341]
  PIN din[342]
    DIRECTION INPUT ;
    USE SIGNAL ;
    PORT
      LAYER M5 ;
        RECT  25.104 0 25.128 0.084 ;
    END
  END din[342]
  PIN din[343]
    DIRECTION INPUT ;
    USE SIGNAL ;
    PORT
      LAYER M5 ;
        RECT  25.2 0 25.224 0.084 ;
    END
  END din[343]
  PIN din[344]
    DIRECTION INPUT ;
    USE SIGNAL ;
    PORT
      LAYER M5 ;
        RECT  25.296 0 25.32 0.084 ;
    END
  END din[344]
  PIN din[345]
    DIRECTION INPUT ;
    USE SIGNAL ;
    PORT
      LAYER M5 ;
        RECT  25.392 0 25.416 0.084 ;
    END
  END din[345]
  PIN din[346]
    DIRECTION INPUT ;
    USE SIGNAL ;
    PORT
      LAYER M5 ;
        RECT  25.488 0 25.512 0.084 ;
    END
  END din[346]
  PIN din[347]
    DIRECTION INPUT ;
    USE SIGNAL ;
    PORT
      LAYER M5 ;
        RECT  25.584 0 25.608 0.084 ;
    END
  END din[347]
  PIN din[348]
    DIRECTION INPUT ;
    USE SIGNAL ;
    PORT
      LAYER M5 ;
        RECT  25.68 0 25.704 0.084 ;
    END
  END din[348]
  PIN din[349]
    DIRECTION INPUT ;
    USE SIGNAL ;
    PORT
      LAYER M5 ;
        RECT  25.776 0 25.8 0.084 ;
    END
  END din[349]
  PIN din[34]
    DIRECTION INPUT ;
    USE SIGNAL ;
    PORT
      LAYER M5 ;
        RECT  39.312 0 39.336 0.084 ;
    END
  END din[34]
  PIN din[350]
    DIRECTION INPUT ;
    USE SIGNAL ;
    PORT
      LAYER M5 ;
        RECT  25.872 0 25.896 0.084 ;
    END
  END din[350]
  PIN din[351]
    DIRECTION INPUT ;
    USE SIGNAL ;
    PORT
      LAYER M5 ;
        RECT  25.968 0 25.992 0.084 ;
    END
  END din[351]
  PIN din[352]
    DIRECTION INPUT ;
    USE SIGNAL ;
    PORT
      LAYER M5 ;
        RECT  6.864 0 6.888 0.084 ;
    END
  END din[352]
  PIN din[353]
    DIRECTION INPUT ;
    USE SIGNAL ;
    PORT
      LAYER M5 ;
        RECT  6.96 0 6.984 0.084 ;
    END
  END din[353]
  PIN din[354]
    DIRECTION INPUT ;
    USE SIGNAL ;
    PORT
      LAYER M5 ;
        RECT  7.056 0 7.08 0.084 ;
    END
  END din[354]
  PIN din[355]
    DIRECTION INPUT ;
    USE SIGNAL ;
    PORT
      LAYER M5 ;
        RECT  7.152 0 7.176 0.084 ;
    END
  END din[355]
  PIN din[356]
    DIRECTION INPUT ;
    USE SIGNAL ;
    PORT
      LAYER M5 ;
        RECT  7.248 0 7.272 0.084 ;
    END
  END din[356]
  PIN din[357]
    DIRECTION INPUT ;
    USE SIGNAL ;
    PORT
      LAYER M5 ;
        RECT  7.344 0 7.368 0.084 ;
    END
  END din[357]
  PIN din[358]
    DIRECTION INPUT ;
    USE SIGNAL ;
    PORT
      LAYER M5 ;
        RECT  7.44 0 7.464 0.084 ;
    END
  END din[358]
  PIN din[359]
    DIRECTION INPUT ;
    USE SIGNAL ;
    PORT
      LAYER M5 ;
        RECT  7.536 0 7.56 0.084 ;
    END
  END din[359]
  PIN din[35]
    DIRECTION INPUT ;
    USE SIGNAL ;
    PORT
      LAYER M5 ;
        RECT  39.408 0 39.432 0.084 ;
    END
  END din[35]
  PIN din[360]
    DIRECTION INPUT ;
    USE SIGNAL ;
    PORT
      LAYER M5 ;
        RECT  7.632 0 7.656 0.084 ;
    END
  END din[360]
  PIN din[361]
    DIRECTION INPUT ;
    USE SIGNAL ;
    PORT
      LAYER M5 ;
        RECT  7.728 0 7.752 0.084 ;
    END
  END din[361]
  PIN din[362]
    DIRECTION INPUT ;
    USE SIGNAL ;
    PORT
      LAYER M5 ;
        RECT  7.824 0 7.848 0.084 ;
    END
  END din[362]
  PIN din[363]
    DIRECTION INPUT ;
    USE SIGNAL ;
    PORT
      LAYER M5 ;
        RECT  7.92 0 7.944 0.084 ;
    END
  END din[363]
  PIN din[364]
    DIRECTION INPUT ;
    USE SIGNAL ;
    PORT
      LAYER M5 ;
        RECT  8.016 0 8.04 0.084 ;
    END
  END din[364]
  PIN din[365]
    DIRECTION INPUT ;
    USE SIGNAL ;
    PORT
      LAYER M5 ;
        RECT  8.112 0 8.136 0.084 ;
    END
  END din[365]
  PIN din[366]
    DIRECTION INPUT ;
    USE SIGNAL ;
    PORT
      LAYER M5 ;
        RECT  8.208 0 8.232 0.084 ;
    END
  END din[366]
  PIN din[367]
    DIRECTION INPUT ;
    USE SIGNAL ;
    PORT
      LAYER M5 ;
        RECT  8.304 0 8.328 0.084 ;
    END
  END din[367]
  PIN din[368]
    DIRECTION INPUT ;
    USE SIGNAL ;
    PORT
      LAYER M5 ;
        RECT  8.4 0 8.424 0.084 ;
    END
  END din[368]
  PIN din[369]
    DIRECTION INPUT ;
    USE SIGNAL ;
    PORT
      LAYER M5 ;
        RECT  8.496 0 8.52 0.084 ;
    END
  END din[369]
  PIN din[36]
    DIRECTION INPUT ;
    USE SIGNAL ;
    PORT
      LAYER M5 ;
        RECT  39.504 0 39.528 0.084 ;
    END
  END din[36]
  PIN din[370]
    DIRECTION INPUT ;
    USE SIGNAL ;
    PORT
      LAYER M5 ;
        RECT  8.592 0 8.616 0.084 ;
    END
  END din[370]
  PIN din[371]
    DIRECTION INPUT ;
    USE SIGNAL ;
    PORT
      LAYER M5 ;
        RECT  8.688 0 8.712 0.084 ;
    END
  END din[371]
  PIN din[372]
    DIRECTION INPUT ;
    USE SIGNAL ;
    PORT
      LAYER M5 ;
        RECT  8.784 0 8.808 0.084 ;
    END
  END din[372]
  PIN din[373]
    DIRECTION INPUT ;
    USE SIGNAL ;
    PORT
      LAYER M5 ;
        RECT  8.88 0 8.904 0.084 ;
    END
  END din[373]
  PIN din[374]
    DIRECTION INPUT ;
    USE SIGNAL ;
    PORT
      LAYER M5 ;
        RECT  8.976 0 9 0.084 ;
    END
  END din[374]
  PIN din[375]
    DIRECTION INPUT ;
    USE SIGNAL ;
    PORT
      LAYER M5 ;
        RECT  9.072 0 9.096 0.084 ;
    END
  END din[375]
  PIN din[376]
    DIRECTION INPUT ;
    USE SIGNAL ;
    PORT
      LAYER M5 ;
        RECT  9.168 0 9.192 0.084 ;
    END
  END din[376]
  PIN din[377]
    DIRECTION INPUT ;
    USE SIGNAL ;
    PORT
      LAYER M5 ;
        RECT  9.264 0 9.288 0.084 ;
    END
  END din[377]
  PIN din[378]
    DIRECTION INPUT ;
    USE SIGNAL ;
    PORT
      LAYER M5 ;
        RECT  9.36 0 9.384 0.084 ;
    END
  END din[378]
  PIN din[379]
    DIRECTION INPUT ;
    USE SIGNAL ;
    PORT
      LAYER M5 ;
        RECT  9.456 0 9.48 0.084 ;
    END
  END din[379]
  PIN din[37]
    DIRECTION INPUT ;
    USE SIGNAL ;
    PORT
      LAYER M5 ;
        RECT  39.6 0 39.624 0.084 ;
    END
  END din[37]
  PIN din[380]
    DIRECTION INPUT ;
    USE SIGNAL ;
    PORT
      LAYER M5 ;
        RECT  9.552 0 9.576 0.084 ;
    END
  END din[380]
  PIN din[381]
    DIRECTION INPUT ;
    USE SIGNAL ;
    PORT
      LAYER M5 ;
        RECT  9.648 0 9.672 0.084 ;
    END
  END din[381]
  PIN din[382]
    DIRECTION INPUT ;
    USE SIGNAL ;
    PORT
      LAYER M5 ;
        RECT  9.744 0 9.768 0.084 ;
    END
  END din[382]
  PIN din[383]
    DIRECTION INPUT ;
    USE SIGNAL ;
    PORT
      LAYER M5 ;
        RECT  9.84 0 9.864 0.084 ;
    END
  END din[383]
  PIN din[384]
    DIRECTION INPUT ;
    USE SIGNAL ;
    PORT
      LAYER M5 ;
        RECT  64.464 0 64.488 0.084 ;
    END
  END din[384]
  PIN din[385]
    DIRECTION INPUT ;
    USE SIGNAL ;
    PORT
      LAYER M5 ;
        RECT  64.56 0 64.584 0.084 ;
    END
  END din[385]
  PIN din[386]
    DIRECTION INPUT ;
    USE SIGNAL ;
    PORT
      LAYER M5 ;
        RECT  64.656 0 64.68 0.084 ;
    END
  END din[386]
  PIN din[387]
    DIRECTION INPUT ;
    USE SIGNAL ;
    PORT
      LAYER M5 ;
        RECT  64.752 0 64.776 0.084 ;
    END
  END din[387]
  PIN din[388]
    DIRECTION INPUT ;
    USE SIGNAL ;
    PORT
      LAYER M5 ;
        RECT  64.848 0 64.872 0.084 ;
    END
  END din[388]
  PIN din[389]
    DIRECTION INPUT ;
    USE SIGNAL ;
    PORT
      LAYER M5 ;
        RECT  64.944 0 64.968 0.084 ;
    END
  END din[389]
  PIN din[38]
    DIRECTION INPUT ;
    USE SIGNAL ;
    PORT
      LAYER M5 ;
        RECT  39.696 0 39.72 0.084 ;
    END
  END din[38]
  PIN din[390]
    DIRECTION INPUT ;
    USE SIGNAL ;
    PORT
      LAYER M5 ;
        RECT  65.04 0 65.064 0.084 ;
    END
  END din[390]
  PIN din[391]
    DIRECTION INPUT ;
    USE SIGNAL ;
    PORT
      LAYER M5 ;
        RECT  65.136 0 65.16 0.084 ;
    END
  END din[391]
  PIN din[392]
    DIRECTION INPUT ;
    USE SIGNAL ;
    PORT
      LAYER M5 ;
        RECT  65.232 0 65.256 0.084 ;
    END
  END din[392]
  PIN din[393]
    DIRECTION INPUT ;
    USE SIGNAL ;
    PORT
      LAYER M5 ;
        RECT  65.328 0 65.352 0.084 ;
    END
  END din[393]
  PIN din[394]
    DIRECTION INPUT ;
    USE SIGNAL ;
    PORT
      LAYER M5 ;
        RECT  65.424 0 65.448 0.084 ;
    END
  END din[394]
  PIN din[395]
    DIRECTION INPUT ;
    USE SIGNAL ;
    PORT
      LAYER M5 ;
        RECT  65.52 0 65.544 0.084 ;
    END
  END din[395]
  PIN din[396]
    DIRECTION INPUT ;
    USE SIGNAL ;
    PORT
      LAYER M5 ;
        RECT  65.616 0 65.64 0.084 ;
    END
  END din[396]
  PIN din[397]
    DIRECTION INPUT ;
    USE SIGNAL ;
    PORT
      LAYER M5 ;
        RECT  65.712 0 65.736 0.084 ;
    END
  END din[397]
  PIN din[398]
    DIRECTION INPUT ;
    USE SIGNAL ;
    PORT
      LAYER M5 ;
        RECT  65.808 0 65.832 0.084 ;
    END
  END din[398]
  PIN din[399]
    DIRECTION INPUT ;
    USE SIGNAL ;
    PORT
      LAYER M5 ;
        RECT  65.904 0 65.928 0.084 ;
    END
  END din[399]
  PIN din[39]
    DIRECTION INPUT ;
    USE SIGNAL ;
    PORT
      LAYER M5 ;
        RECT  39.792 0 39.816 0.084 ;
    END
  END din[39]
  PIN din[3]
    DIRECTION INPUT ;
    USE SIGNAL ;
    PORT
      LAYER M5 ;
        RECT  54.768 0 54.792 0.084 ;
    END
  END din[3]
  PIN din[400]
    DIRECTION INPUT ;
    USE SIGNAL ;
    PORT
      LAYER M5 ;
        RECT  66 0 66.024 0.084 ;
    END
  END din[400]
  PIN din[401]
    DIRECTION INPUT ;
    USE SIGNAL ;
    PORT
      LAYER M5 ;
        RECT  66.096 0 66.12 0.084 ;
    END
  END din[401]
  PIN din[402]
    DIRECTION INPUT ;
    USE SIGNAL ;
    PORT
      LAYER M5 ;
        RECT  66.192 0 66.216 0.084 ;
    END
  END din[402]
  PIN din[403]
    DIRECTION INPUT ;
    USE SIGNAL ;
    PORT
      LAYER M5 ;
        RECT  66.288 0 66.312 0.084 ;
    END
  END din[403]
  PIN din[404]
    DIRECTION INPUT ;
    USE SIGNAL ;
    PORT
      LAYER M5 ;
        RECT  66.384 0 66.408 0.084 ;
    END
  END din[404]
  PIN din[405]
    DIRECTION INPUT ;
    USE SIGNAL ;
    PORT
      LAYER M5 ;
        RECT  66.48 0 66.504 0.084 ;
    END
  END din[405]
  PIN din[406]
    DIRECTION INPUT ;
    USE SIGNAL ;
    PORT
      LAYER M5 ;
        RECT  66.576 0 66.6 0.084 ;
    END
  END din[406]
  PIN din[407]
    DIRECTION INPUT ;
    USE SIGNAL ;
    PORT
      LAYER M5 ;
        RECT  66.672 0 66.696 0.084 ;
    END
  END din[407]
  PIN din[408]
    DIRECTION INPUT ;
    USE SIGNAL ;
    PORT
      LAYER M5 ;
        RECT  66.768 0 66.792 0.084 ;
    END
  END din[408]
  PIN din[409]
    DIRECTION INPUT ;
    USE SIGNAL ;
    PORT
      LAYER M5 ;
        RECT  66.864 0 66.888 0.084 ;
    END
  END din[409]
  PIN din[40]
    DIRECTION INPUT ;
    USE SIGNAL ;
    PORT
      LAYER M5 ;
        RECT  39.888 0 39.912 0.084 ;
    END
  END din[40]
  PIN din[410]
    DIRECTION INPUT ;
    USE SIGNAL ;
    PORT
      LAYER M5 ;
        RECT  66.96 0 66.984 0.084 ;
    END
  END din[410]
  PIN din[411]
    DIRECTION INPUT ;
    USE SIGNAL ;
    PORT
      LAYER M5 ;
        RECT  67.056 0 67.08 0.084 ;
    END
  END din[411]
  PIN din[412]
    DIRECTION INPUT ;
    USE SIGNAL ;
    PORT
      LAYER M5 ;
        RECT  67.152 0 67.176 0.084 ;
    END
  END din[412]
  PIN din[413]
    DIRECTION INPUT ;
    USE SIGNAL ;
    PORT
      LAYER M5 ;
        RECT  67.248 0 67.272 0.084 ;
    END
  END din[413]
  PIN din[414]
    DIRECTION INPUT ;
    USE SIGNAL ;
    PORT
      LAYER M5 ;
        RECT  67.344 0 67.368 0.084 ;
    END
  END din[414]
  PIN din[415]
    DIRECTION INPUT ;
    USE SIGNAL ;
    PORT
      LAYER M5 ;
        RECT  67.44 0 67.464 0.084 ;
    END
  END din[415]
  PIN din[416]
    DIRECTION INPUT ;
    USE SIGNAL ;
    PORT
      LAYER M5 ;
        RECT  67.536 0 67.56 0.084 ;
    END
  END din[416]
  PIN din[417]
    DIRECTION INPUT ;
    USE SIGNAL ;
    PORT
      LAYER M5 ;
        RECT  67.632 0 67.656 0.084 ;
    END
  END din[417]
  PIN din[418]
    DIRECTION INPUT ;
    USE SIGNAL ;
    PORT
      LAYER M5 ;
        RECT  67.728 0 67.752 0.084 ;
    END
  END din[418]
  PIN din[419]
    DIRECTION INPUT ;
    USE SIGNAL ;
    PORT
      LAYER M5 ;
        RECT  67.824 0 67.848 0.084 ;
    END
  END din[419]
  PIN din[41]
    DIRECTION INPUT ;
    USE SIGNAL ;
    PORT
      LAYER M5 ;
        RECT  39.984 0 40.008 0.084 ;
    END
  END din[41]
  PIN din[420]
    DIRECTION INPUT ;
    USE SIGNAL ;
    PORT
      LAYER M5 ;
        RECT  67.92 0 67.944 0.084 ;
    END
  END din[420]
  PIN din[421]
    DIRECTION INPUT ;
    USE SIGNAL ;
    PORT
      LAYER M5 ;
        RECT  68.016 0 68.04 0.084 ;
    END
  END din[421]
  PIN din[422]
    DIRECTION INPUT ;
    USE SIGNAL ;
    PORT
      LAYER M5 ;
        RECT  68.112 0 68.136 0.084 ;
    END
  END din[422]
  PIN din[423]
    DIRECTION INPUT ;
    USE SIGNAL ;
    PORT
      LAYER M5 ;
        RECT  68.208 0 68.232 0.084 ;
    END
  END din[423]
  PIN din[424]
    DIRECTION INPUT ;
    USE SIGNAL ;
    PORT
      LAYER M5 ;
        RECT  68.304 0 68.328 0.084 ;
    END
  END din[424]
  PIN din[425]
    DIRECTION INPUT ;
    USE SIGNAL ;
    PORT
      LAYER M5 ;
        RECT  68.4 0 68.424 0.084 ;
    END
  END din[425]
  PIN din[426]
    DIRECTION INPUT ;
    USE SIGNAL ;
    PORT
      LAYER M5 ;
        RECT  68.496 0 68.52 0.084 ;
    END
  END din[426]
  PIN din[427]
    DIRECTION INPUT ;
    USE SIGNAL ;
    PORT
      LAYER M5 ;
        RECT  68.592 0 68.616 0.084 ;
    END
  END din[427]
  PIN din[428]
    DIRECTION INPUT ;
    USE SIGNAL ;
    PORT
      LAYER M5 ;
        RECT  68.688 0 68.712 0.084 ;
    END
  END din[428]
  PIN din[429]
    DIRECTION INPUT ;
    USE SIGNAL ;
    PORT
      LAYER M5 ;
        RECT  68.784 0 68.808 0.084 ;
    END
  END din[429]
  PIN din[42]
    DIRECTION INPUT ;
    USE SIGNAL ;
    PORT
      LAYER M5 ;
        RECT  40.08 0 40.104 0.084 ;
    END
  END din[42]
  PIN din[430]
    DIRECTION INPUT ;
    USE SIGNAL ;
    PORT
      LAYER M5 ;
        RECT  68.88 0 68.904 0.084 ;
    END
  END din[430]
  PIN din[431]
    DIRECTION INPUT ;
    USE SIGNAL ;
    PORT
      LAYER M5 ;
        RECT  68.976 0 69 0.084 ;
    END
  END din[431]
  PIN din[432]
    DIRECTION INPUT ;
    USE SIGNAL ;
    PORT
      LAYER M5 ;
        RECT  69.072 0 69.096 0.084 ;
    END
  END din[432]
  PIN din[433]
    DIRECTION INPUT ;
    USE SIGNAL ;
    PORT
      LAYER M5 ;
        RECT  69.168 0 69.192 0.084 ;
    END
  END din[433]
  PIN din[434]
    DIRECTION INPUT ;
    USE SIGNAL ;
    PORT
      LAYER M5 ;
        RECT  69.264 0 69.288 0.084 ;
    END
  END din[434]
  PIN din[435]
    DIRECTION INPUT ;
    USE SIGNAL ;
    PORT
      LAYER M5 ;
        RECT  69.36 0 69.384 0.084 ;
    END
  END din[435]
  PIN din[436]
    DIRECTION INPUT ;
    USE SIGNAL ;
    PORT
      LAYER M5 ;
        RECT  69.456 0 69.48 0.084 ;
    END
  END din[436]
  PIN din[437]
    DIRECTION INPUT ;
    USE SIGNAL ;
    PORT
      LAYER M5 ;
        RECT  69.552 0 69.576 0.084 ;
    END
  END din[437]
  PIN din[438]
    DIRECTION INPUT ;
    USE SIGNAL ;
    PORT
      LAYER M5 ;
        RECT  69.648 0 69.672 0.084 ;
    END
  END din[438]
  PIN din[439]
    DIRECTION INPUT ;
    USE SIGNAL ;
    PORT
      LAYER M5 ;
        RECT  69.744 0 69.768 0.084 ;
    END
  END din[439]
  PIN din[43]
    DIRECTION INPUT ;
    USE SIGNAL ;
    PORT
      LAYER M5 ;
        RECT  40.176 0 40.2 0.084 ;
    END
  END din[43]
  PIN din[440]
    DIRECTION INPUT ;
    USE SIGNAL ;
    PORT
      LAYER M5 ;
        RECT  69.84 0 69.864 0.084 ;
    END
  END din[440]
  PIN din[441]
    DIRECTION INPUT ;
    USE SIGNAL ;
    PORT
      LAYER M5 ;
        RECT  69.936 0 69.96 0.084 ;
    END
  END din[441]
  PIN din[442]
    DIRECTION INPUT ;
    USE SIGNAL ;
    PORT
      LAYER M5 ;
        RECT  70.032 0 70.056 0.084 ;
    END
  END din[442]
  PIN din[443]
    DIRECTION INPUT ;
    USE SIGNAL ;
    PORT
      LAYER M5 ;
        RECT  70.128 0 70.152 0.084 ;
    END
  END din[443]
  PIN din[444]
    DIRECTION INPUT ;
    USE SIGNAL ;
    PORT
      LAYER M5 ;
        RECT  70.224 0 70.248 0.084 ;
    END
  END din[444]
  PIN din[445]
    DIRECTION INPUT ;
    USE SIGNAL ;
    PORT
      LAYER M5 ;
        RECT  70.32 0 70.344 0.084 ;
    END
  END din[445]
  PIN din[446]
    DIRECTION INPUT ;
    USE SIGNAL ;
    PORT
      LAYER M5 ;
        RECT  70.416 0 70.44 0.084 ;
    END
  END din[446]
  PIN din[447]
    DIRECTION INPUT ;
    USE SIGNAL ;
    PORT
      LAYER M5 ;
        RECT  70.512 0 70.536 0.084 ;
    END
  END din[447]
  PIN din[448]
    DIRECTION INPUT ;
    USE SIGNAL ;
    PORT
      LAYER M5 ;
        RECT  51.408 0 51.432 0.084 ;
    END
  END din[448]
  PIN din[449]
    DIRECTION INPUT ;
    USE SIGNAL ;
    PORT
      LAYER M5 ;
        RECT  51.504 0 51.528 0.084 ;
    END
  END din[449]
  PIN din[44]
    DIRECTION INPUT ;
    USE SIGNAL ;
    PORT
      LAYER M5 ;
        RECT  40.272 0 40.296 0.084 ;
    END
  END din[44]
  PIN din[450]
    DIRECTION INPUT ;
    USE SIGNAL ;
    PORT
      LAYER M5 ;
        RECT  51.6 0 51.624 0.084 ;
    END
  END din[450]
  PIN din[451]
    DIRECTION INPUT ;
    USE SIGNAL ;
    PORT
      LAYER M5 ;
        RECT  51.696 0 51.72 0.084 ;
    END
  END din[451]
  PIN din[452]
    DIRECTION INPUT ;
    USE SIGNAL ;
    PORT
      LAYER M5 ;
        RECT  51.792 0 51.816 0.084 ;
    END
  END din[452]
  PIN din[453]
    DIRECTION INPUT ;
    USE SIGNAL ;
    PORT
      LAYER M5 ;
        RECT  51.888 0 51.912 0.084 ;
    END
  END din[453]
  PIN din[454]
    DIRECTION INPUT ;
    USE SIGNAL ;
    PORT
      LAYER M5 ;
        RECT  51.984 0 52.008 0.084 ;
    END
  END din[454]
  PIN din[455]
    DIRECTION INPUT ;
    USE SIGNAL ;
    PORT
      LAYER M5 ;
        RECT  52.08 0 52.104 0.084 ;
    END
  END din[455]
  PIN din[456]
    DIRECTION INPUT ;
    USE SIGNAL ;
    PORT
      LAYER M5 ;
        RECT  52.176 0 52.2 0.084 ;
    END
  END din[456]
  PIN din[457]
    DIRECTION INPUT ;
    USE SIGNAL ;
    PORT
      LAYER M5 ;
        RECT  52.272 0 52.296 0.084 ;
    END
  END din[457]
  PIN din[458]
    DIRECTION INPUT ;
    USE SIGNAL ;
    PORT
      LAYER M5 ;
        RECT  52.368 0 52.392 0.084 ;
    END
  END din[458]
  PIN din[459]
    DIRECTION INPUT ;
    USE SIGNAL ;
    PORT
      LAYER M5 ;
        RECT  52.464 0 52.488 0.084 ;
    END
  END din[459]
  PIN din[45]
    DIRECTION INPUT ;
    USE SIGNAL ;
    PORT
      LAYER M5 ;
        RECT  40.368 0 40.392 0.084 ;
    END
  END din[45]
  PIN din[460]
    DIRECTION INPUT ;
    USE SIGNAL ;
    PORT
      LAYER M5 ;
        RECT  52.56 0 52.584 0.084 ;
    END
  END din[460]
  PIN din[461]
    DIRECTION INPUT ;
    USE SIGNAL ;
    PORT
      LAYER M5 ;
        RECT  52.656 0 52.68 0.084 ;
    END
  END din[461]
  PIN din[462]
    DIRECTION INPUT ;
    USE SIGNAL ;
    PORT
      LAYER M5 ;
        RECT  52.752 0 52.776 0.084 ;
    END
  END din[462]
  PIN din[463]
    DIRECTION INPUT ;
    USE SIGNAL ;
    PORT
      LAYER M5 ;
        RECT  52.848 0 52.872 0.084 ;
    END
  END din[463]
  PIN din[464]
    DIRECTION INPUT ;
    USE SIGNAL ;
    PORT
      LAYER M5 ;
        RECT  52.944 0 52.968 0.084 ;
    END
  END din[464]
  PIN din[465]
    DIRECTION INPUT ;
    USE SIGNAL ;
    PORT
      LAYER M5 ;
        RECT  53.04 0 53.064 0.084 ;
    END
  END din[465]
  PIN din[466]
    DIRECTION INPUT ;
    USE SIGNAL ;
    PORT
      LAYER M5 ;
        RECT  53.136 0 53.16 0.084 ;
    END
  END din[466]
  PIN din[467]
    DIRECTION INPUT ;
    USE SIGNAL ;
    PORT
      LAYER M5 ;
        RECT  53.232 0 53.256 0.084 ;
    END
  END din[467]
  PIN din[468]
    DIRECTION INPUT ;
    USE SIGNAL ;
    PORT
      LAYER M5 ;
        RECT  53.328 0 53.352 0.084 ;
    END
  END din[468]
  PIN din[469]
    DIRECTION INPUT ;
    USE SIGNAL ;
    PORT
      LAYER M5 ;
        RECT  53.424 0 53.448 0.084 ;
    END
  END din[469]
  PIN din[46]
    DIRECTION INPUT ;
    USE SIGNAL ;
    PORT
      LAYER M5 ;
        RECT  40.464 0 40.488 0.084 ;
    END
  END din[46]
  PIN din[470]
    DIRECTION INPUT ;
    USE SIGNAL ;
    PORT
      LAYER M5 ;
        RECT  53.52 0 53.544 0.084 ;
    END
  END din[470]
  PIN din[471]
    DIRECTION INPUT ;
    USE SIGNAL ;
    PORT
      LAYER M5 ;
        RECT  53.616 0 53.64 0.084 ;
    END
  END din[471]
  PIN din[472]
    DIRECTION INPUT ;
    USE SIGNAL ;
    PORT
      LAYER M5 ;
        RECT  53.712 0 53.736 0.084 ;
    END
  END din[472]
  PIN din[473]
    DIRECTION INPUT ;
    USE SIGNAL ;
    PORT
      LAYER M5 ;
        RECT  53.808 0 53.832 0.084 ;
    END
  END din[473]
  PIN din[474]
    DIRECTION INPUT ;
    USE SIGNAL ;
    PORT
      LAYER M5 ;
        RECT  53.904 0 53.928 0.084 ;
    END
  END din[474]
  PIN din[475]
    DIRECTION INPUT ;
    USE SIGNAL ;
    PORT
      LAYER M5 ;
        RECT  54 0 54.024 0.084 ;
    END
  END din[475]
  PIN din[476]
    DIRECTION INPUT ;
    USE SIGNAL ;
    PORT
      LAYER M5 ;
        RECT  54.096 0 54.12 0.084 ;
    END
  END din[476]
  PIN din[477]
    DIRECTION INPUT ;
    USE SIGNAL ;
    PORT
      LAYER M5 ;
        RECT  54.192 0 54.216 0.084 ;
    END
  END din[477]
  PIN din[478]
    DIRECTION INPUT ;
    USE SIGNAL ;
    PORT
      LAYER M5 ;
        RECT  54.288 0 54.312 0.084 ;
    END
  END din[478]
  PIN din[479]
    DIRECTION INPUT ;
    USE SIGNAL ;
    PORT
      LAYER M5 ;
        RECT  54.384 0 54.408 0.084 ;
    END
  END din[479]
  PIN din[47]
    DIRECTION INPUT ;
    USE SIGNAL ;
    PORT
      LAYER M5 ;
        RECT  40.56 0 40.584 0.084 ;
    END
  END din[47]
  PIN din[480]
    DIRECTION INPUT ;
    USE SIGNAL ;
    PORT
      LAYER M5 ;
        RECT  29.136 0 29.16 0.084 ;
    END
  END din[480]
  PIN din[481]
    DIRECTION INPUT ;
    USE SIGNAL ;
    PORT
      LAYER M5 ;
        RECT  29.232 0 29.256 0.084 ;
    END
  END din[481]
  PIN din[482]
    DIRECTION INPUT ;
    USE SIGNAL ;
    PORT
      LAYER M5 ;
        RECT  29.328 0 29.352 0.084 ;
    END
  END din[482]
  PIN din[483]
    DIRECTION INPUT ;
    USE SIGNAL ;
    PORT
      LAYER M5 ;
        RECT  29.424 0 29.448 0.084 ;
    END
  END din[483]
  PIN din[484]
    DIRECTION INPUT ;
    USE SIGNAL ;
    PORT
      LAYER M5 ;
        RECT  29.52 0 29.544 0.084 ;
    END
  END din[484]
  PIN din[485]
    DIRECTION INPUT ;
    USE SIGNAL ;
    PORT
      LAYER M5 ;
        RECT  29.616 0 29.64 0.084 ;
    END
  END din[485]
  PIN din[486]
    DIRECTION INPUT ;
    USE SIGNAL ;
    PORT
      LAYER M5 ;
        RECT  29.712 0 29.736 0.084 ;
    END
  END din[486]
  PIN din[487]
    DIRECTION INPUT ;
    USE SIGNAL ;
    PORT
      LAYER M5 ;
        RECT  29.808 0 29.832 0.084 ;
    END
  END din[487]
  PIN din[488]
    DIRECTION INPUT ;
    USE SIGNAL ;
    PORT
      LAYER M5 ;
        RECT  29.904 0 29.928 0.084 ;
    END
  END din[488]
  PIN din[489]
    DIRECTION INPUT ;
    USE SIGNAL ;
    PORT
      LAYER M5 ;
        RECT  30 0 30.024 0.084 ;
    END
  END din[489]
  PIN din[48]
    DIRECTION INPUT ;
    USE SIGNAL ;
    PORT
      LAYER M5 ;
        RECT  40.656 0 40.68 0.084 ;
    END
  END din[48]
  PIN din[490]
    DIRECTION INPUT ;
    USE SIGNAL ;
    PORT
      LAYER M5 ;
        RECT  30.096 0 30.12 0.084 ;
    END
  END din[490]
  PIN din[491]
    DIRECTION INPUT ;
    USE SIGNAL ;
    PORT
      LAYER M5 ;
        RECT  30.192 0 30.216 0.084 ;
    END
  END din[491]
  PIN din[492]
    DIRECTION INPUT ;
    USE SIGNAL ;
    PORT
      LAYER M5 ;
        RECT  30.288 0 30.312 0.084 ;
    END
  END din[492]
  PIN din[493]
    DIRECTION INPUT ;
    USE SIGNAL ;
    PORT
      LAYER M5 ;
        RECT  30.384 0 30.408 0.084 ;
    END
  END din[493]
  PIN din[494]
    DIRECTION INPUT ;
    USE SIGNAL ;
    PORT
      LAYER M5 ;
        RECT  30.48 0 30.504 0.084 ;
    END
  END din[494]
  PIN din[495]
    DIRECTION INPUT ;
    USE SIGNAL ;
    PORT
      LAYER M5 ;
        RECT  30.576 0 30.6 0.084 ;
    END
  END din[495]
  PIN din[496]
    DIRECTION INPUT ;
    USE SIGNAL ;
    PORT
      LAYER M5 ;
        RECT  30.672 0 30.696 0.084 ;
    END
  END din[496]
  PIN din[497]
    DIRECTION INPUT ;
    USE SIGNAL ;
    PORT
      LAYER M5 ;
        RECT  30.768 0 30.792 0.084 ;
    END
  END din[497]
  PIN din[498]
    DIRECTION INPUT ;
    USE SIGNAL ;
    PORT
      LAYER M5 ;
        RECT  30.864 0 30.888 0.084 ;
    END
  END din[498]
  PIN din[499]
    DIRECTION INPUT ;
    USE SIGNAL ;
    PORT
      LAYER M5 ;
        RECT  30.96 0 30.984 0.084 ;
    END
  END din[499]
  PIN din[49]
    DIRECTION INPUT ;
    USE SIGNAL ;
    PORT
      LAYER M5 ;
        RECT  40.752 0 40.776 0.084 ;
    END
  END din[49]
  PIN din[4]
    DIRECTION INPUT ;
    USE SIGNAL ;
    PORT
      LAYER M5 ;
        RECT  54.864 0 54.888 0.084 ;
    END
  END din[4]
  PIN din[500]
    DIRECTION INPUT ;
    USE SIGNAL ;
    PORT
      LAYER M5 ;
        RECT  31.056 0 31.08 0.084 ;
    END
  END din[500]
  PIN din[501]
    DIRECTION INPUT ;
    USE SIGNAL ;
    PORT
      LAYER M5 ;
        RECT  31.152 0 31.176 0.084 ;
    END
  END din[501]
  PIN din[502]
    DIRECTION INPUT ;
    USE SIGNAL ;
    PORT
      LAYER M5 ;
        RECT  31.248 0 31.272 0.084 ;
    END
  END din[502]
  PIN din[503]
    DIRECTION INPUT ;
    USE SIGNAL ;
    PORT
      LAYER M5 ;
        RECT  31.344 0 31.368 0.084 ;
    END
  END din[503]
  PIN din[504]
    DIRECTION INPUT ;
    USE SIGNAL ;
    PORT
      LAYER M5 ;
        RECT  31.44 0 31.464 0.084 ;
    END
  END din[504]
  PIN din[505]
    DIRECTION INPUT ;
    USE SIGNAL ;
    PORT
      LAYER M5 ;
        RECT  31.536 0 31.56 0.084 ;
    END
  END din[505]
  PIN din[506]
    DIRECTION INPUT ;
    USE SIGNAL ;
    PORT
      LAYER M5 ;
        RECT  31.632 0 31.656 0.084 ;
    END
  END din[506]
  PIN din[507]
    DIRECTION INPUT ;
    USE SIGNAL ;
    PORT
      LAYER M5 ;
        RECT  31.728 0 31.752 0.084 ;
    END
  END din[507]
  PIN din[508]
    DIRECTION INPUT ;
    USE SIGNAL ;
    PORT
      LAYER M5 ;
        RECT  31.824 0 31.848 0.084 ;
    END
  END din[508]
  PIN din[509]
    DIRECTION INPUT ;
    USE SIGNAL ;
    PORT
      LAYER M5 ;
        RECT  31.92 0 31.944 0.084 ;
    END
  END din[509]
  PIN din[50]
    DIRECTION INPUT ;
    USE SIGNAL ;
    PORT
      LAYER M5 ;
        RECT  40.848 0 40.872 0.084 ;
    END
  END din[50]
  PIN din[510]
    DIRECTION INPUT ;
    USE SIGNAL ;
    PORT
      LAYER M5 ;
        RECT  32.016 0 32.04 0.084 ;
    END
  END din[510]
  PIN din[511]
    DIRECTION INPUT ;
    USE SIGNAL ;
    PORT
      LAYER M5 ;
        RECT  32.112 0 32.136 0.084 ;
    END
  END din[511]
  PIN din[512]
    DIRECTION INPUT ;
    USE SIGNAL ;
    PORT
      LAYER M5 ;
        RECT  26.064 0 26.088 0.084 ;
    END
  END din[512]
  PIN din[513]
    DIRECTION INPUT ;
    USE SIGNAL ;
    PORT
      LAYER M5 ;
        RECT  26.16 0 26.184 0.084 ;
    END
  END din[513]
  PIN din[514]
    DIRECTION INPUT ;
    USE SIGNAL ;
    PORT
      LAYER M5 ;
        RECT  26.256 0 26.28 0.084 ;
    END
  END din[514]
  PIN din[515]
    DIRECTION INPUT ;
    USE SIGNAL ;
    PORT
      LAYER M5 ;
        RECT  26.352 0 26.376 0.084 ;
    END
  END din[515]
  PIN din[516]
    DIRECTION INPUT ;
    USE SIGNAL ;
    PORT
      LAYER M5 ;
        RECT  26.448 0 26.472 0.084 ;
    END
  END din[516]
  PIN din[517]
    DIRECTION INPUT ;
    USE SIGNAL ;
    PORT
      LAYER M5 ;
        RECT  26.544 0 26.568 0.084 ;
    END
  END din[517]
  PIN din[518]
    DIRECTION INPUT ;
    USE SIGNAL ;
    PORT
      LAYER M5 ;
        RECT  26.64 0 26.664 0.084 ;
    END
  END din[518]
  PIN din[519]
    DIRECTION INPUT ;
    USE SIGNAL ;
    PORT
      LAYER M5 ;
        RECT  26.736 0 26.76 0.084 ;
    END
  END din[519]
  PIN din[51]
    DIRECTION INPUT ;
    USE SIGNAL ;
    PORT
      LAYER M5 ;
        RECT  40.944 0 40.968 0.084 ;
    END
  END din[51]
  PIN din[520]
    DIRECTION INPUT ;
    USE SIGNAL ;
    PORT
      LAYER M5 ;
        RECT  26.832 0 26.856 0.084 ;
    END
  END din[520]
  PIN din[521]
    DIRECTION INPUT ;
    USE SIGNAL ;
    PORT
      LAYER M5 ;
        RECT  26.928 0 26.952 0.084 ;
    END
  END din[521]
  PIN din[522]
    DIRECTION INPUT ;
    USE SIGNAL ;
    PORT
      LAYER M5 ;
        RECT  27.024 0 27.048 0.084 ;
    END
  END din[522]
  PIN din[523]
    DIRECTION INPUT ;
    USE SIGNAL ;
    PORT
      LAYER M5 ;
        RECT  27.12 0 27.144 0.084 ;
    END
  END din[523]
  PIN din[524]
    DIRECTION INPUT ;
    USE SIGNAL ;
    PORT
      LAYER M5 ;
        RECT  27.216 0 27.24 0.084 ;
    END
  END din[524]
  PIN din[525]
    DIRECTION INPUT ;
    USE SIGNAL ;
    PORT
      LAYER M5 ;
        RECT  27.312 0 27.336 0.084 ;
    END
  END din[525]
  PIN din[526]
    DIRECTION INPUT ;
    USE SIGNAL ;
    PORT
      LAYER M5 ;
        RECT  27.408 0 27.432 0.084 ;
    END
  END din[526]
  PIN din[527]
    DIRECTION INPUT ;
    USE SIGNAL ;
    PORT
      LAYER M5 ;
        RECT  27.504 0 27.528 0.084 ;
    END
  END din[527]
  PIN din[52]
    DIRECTION INPUT ;
    USE SIGNAL ;
    PORT
      LAYER M5 ;
        RECT  41.04 0 41.064 0.084 ;
    END
  END din[52]
  PIN din[53]
    DIRECTION INPUT ;
    USE SIGNAL ;
    PORT
      LAYER M5 ;
        RECT  41.136 0 41.16 0.084 ;
    END
  END din[53]
  PIN din[54]
    DIRECTION INPUT ;
    USE SIGNAL ;
    PORT
      LAYER M5 ;
        RECT  41.232 0 41.256 0.084 ;
    END
  END din[54]
  PIN din[55]
    DIRECTION INPUT ;
    USE SIGNAL ;
    PORT
      LAYER M5 ;
        RECT  41.328 0 41.352 0.084 ;
    END
  END din[55]
  PIN din[56]
    DIRECTION INPUT ;
    USE SIGNAL ;
    PORT
      LAYER M5 ;
        RECT  41.424 0 41.448 0.084 ;
    END
  END din[56]
  PIN din[57]
    DIRECTION INPUT ;
    USE SIGNAL ;
    PORT
      LAYER M5 ;
        RECT  41.52 0 41.544 0.084 ;
    END
  END din[57]
  PIN din[58]
    DIRECTION INPUT ;
    USE SIGNAL ;
    PORT
      LAYER M5 ;
        RECT  41.616 0 41.64 0.084 ;
    END
  END din[58]
  PIN din[59]
    DIRECTION INPUT ;
    USE SIGNAL ;
    PORT
      LAYER M5 ;
        RECT  41.712 0 41.736 0.084 ;
    END
  END din[59]
  PIN din[5]
    DIRECTION INPUT ;
    USE SIGNAL ;
    PORT
      LAYER M5 ;
        RECT  54.96 0 54.984 0.084 ;
    END
  END din[5]
  PIN din[60]
    DIRECTION INPUT ;
    USE SIGNAL ;
    PORT
      LAYER M5 ;
        RECT  41.808 0 41.832 0.084 ;
    END
  END din[60]
  PIN din[61]
    DIRECTION INPUT ;
    USE SIGNAL ;
    PORT
      LAYER M5 ;
        RECT  41.904 0 41.928 0.084 ;
    END
  END din[61]
  PIN din[62]
    DIRECTION INPUT ;
    USE SIGNAL ;
    PORT
      LAYER M5 ;
        RECT  42 0 42.024 0.084 ;
    END
  END din[62]
  PIN din[63]
    DIRECTION INPUT ;
    USE SIGNAL ;
    PORT
      LAYER M5 ;
        RECT  42.096 0 42.12 0.084 ;
    END
  END din[63]
  PIN din[64]
    DIRECTION INPUT ;
    USE SIGNAL ;
    PORT
      LAYER M5 ;
        RECT  35.28 0 35.304 0.084 ;
    END
  END din[64]
  PIN din[65]
    DIRECTION INPUT ;
    USE SIGNAL ;
    PORT
      LAYER M5 ;
        RECT  35.376 0 35.4 0.084 ;
    END
  END din[65]
  PIN din[66]
    DIRECTION INPUT ;
    USE SIGNAL ;
    PORT
      LAYER M5 ;
        RECT  35.472 0 35.496 0.084 ;
    END
  END din[66]
  PIN din[67]
    DIRECTION INPUT ;
    USE SIGNAL ;
    PORT
      LAYER M5 ;
        RECT  35.568 0 35.592 0.084 ;
    END
  END din[67]
  PIN din[68]
    DIRECTION INPUT ;
    USE SIGNAL ;
    PORT
      LAYER M5 ;
        RECT  35.664 0 35.688 0.084 ;
    END
  END din[68]
  PIN din[69]
    DIRECTION INPUT ;
    USE SIGNAL ;
    PORT
      LAYER M5 ;
        RECT  35.76 0 35.784 0.084 ;
    END
  END din[69]
  PIN din[6]
    DIRECTION INPUT ;
    USE SIGNAL ;
    PORT
      LAYER M5 ;
        RECT  55.056 0 55.08 0.084 ;
    END
  END din[6]
  PIN din[70]
    DIRECTION INPUT ;
    USE SIGNAL ;
    PORT
      LAYER M5 ;
        RECT  35.856 0 35.88 0.084 ;
    END
  END din[70]
  PIN din[71]
    DIRECTION INPUT ;
    USE SIGNAL ;
    PORT
      LAYER M5 ;
        RECT  35.952 0 35.976 0.084 ;
    END
  END din[71]
  PIN din[72]
    DIRECTION INPUT ;
    USE SIGNAL ;
    PORT
      LAYER M5 ;
        RECT  36.048 0 36.072 0.084 ;
    END
  END din[72]
  PIN din[73]
    DIRECTION INPUT ;
    USE SIGNAL ;
    PORT
      LAYER M5 ;
        RECT  36.144 0 36.168 0.084 ;
    END
  END din[73]
  PIN din[74]
    DIRECTION INPUT ;
    USE SIGNAL ;
    PORT
      LAYER M5 ;
        RECT  36.24 0 36.264 0.084 ;
    END
  END din[74]
  PIN din[75]
    DIRECTION INPUT ;
    USE SIGNAL ;
    PORT
      LAYER M5 ;
        RECT  36.336 0 36.36 0.084 ;
    END
  END din[75]
  PIN din[76]
    DIRECTION INPUT ;
    USE SIGNAL ;
    PORT
      LAYER M5 ;
        RECT  36.432 0 36.456 0.084 ;
    END
  END din[76]
  PIN din[77]
    DIRECTION INPUT ;
    USE SIGNAL ;
    PORT
      LAYER M5 ;
        RECT  36.528 0 36.552 0.084 ;
    END
  END din[77]
  PIN din[78]
    DIRECTION INPUT ;
    USE SIGNAL ;
    PORT
      LAYER M5 ;
        RECT  36.624 0 36.648 0.084 ;
    END
  END din[78]
  PIN din[79]
    DIRECTION INPUT ;
    USE SIGNAL ;
    PORT
      LAYER M5 ;
        RECT  36.72 0 36.744 0.084 ;
    END
  END din[79]
  PIN din[7]
    DIRECTION INPUT ;
    USE SIGNAL ;
    PORT
      LAYER M5 ;
        RECT  55.152 0 55.176 0.084 ;
    END
  END din[7]
  PIN din[80]
    DIRECTION INPUT ;
    USE SIGNAL ;
    PORT
      LAYER M5 ;
        RECT  36.816 0 36.84 0.084 ;
    END
  END din[80]
  PIN din[81]
    DIRECTION INPUT ;
    USE SIGNAL ;
    PORT
      LAYER M5 ;
        RECT  36.912 0 36.936 0.084 ;
    END
  END din[81]
  PIN din[82]
    DIRECTION INPUT ;
    USE SIGNAL ;
    PORT
      LAYER M5 ;
        RECT  37.008 0 37.032 0.084 ;
    END
  END din[82]
  PIN din[83]
    DIRECTION INPUT ;
    USE SIGNAL ;
    PORT
      LAYER M5 ;
        RECT  37.104 0 37.128 0.084 ;
    END
  END din[83]
  PIN din[84]
    DIRECTION INPUT ;
    USE SIGNAL ;
    PORT
      LAYER M5 ;
        RECT  37.2 0 37.224 0.084 ;
    END
  END din[84]
  PIN din[85]
    DIRECTION INPUT ;
    USE SIGNAL ;
    PORT
      LAYER M5 ;
        RECT  37.296 0 37.32 0.084 ;
    END
  END din[85]
  PIN din[86]
    DIRECTION INPUT ;
    USE SIGNAL ;
    PORT
      LAYER M5 ;
        RECT  37.392 0 37.416 0.084 ;
    END
  END din[86]
  PIN din[87]
    DIRECTION INPUT ;
    USE SIGNAL ;
    PORT
      LAYER M5 ;
        RECT  37.488 0 37.512 0.084 ;
    END
  END din[87]
  PIN din[88]
    DIRECTION INPUT ;
    USE SIGNAL ;
    PORT
      LAYER M5 ;
        RECT  37.584 0 37.608 0.084 ;
    END
  END din[88]
  PIN din[89]
    DIRECTION INPUT ;
    USE SIGNAL ;
    PORT
      LAYER M5 ;
        RECT  37.68 0 37.704 0.084 ;
    END
  END din[89]
  PIN din[8]
    DIRECTION INPUT ;
    USE SIGNAL ;
    PORT
      LAYER M5 ;
        RECT  55.248 0 55.272 0.084 ;
    END
  END din[8]
  PIN din[90]
    DIRECTION INPUT ;
    USE SIGNAL ;
    PORT
      LAYER M5 ;
        RECT  37.776 0 37.8 0.084 ;
    END
  END din[90]
  PIN din[91]
    DIRECTION INPUT ;
    USE SIGNAL ;
    PORT
      LAYER M5 ;
        RECT  37.872 0 37.896 0.084 ;
    END
  END din[91]
  PIN din[92]
    DIRECTION INPUT ;
    USE SIGNAL ;
    PORT
      LAYER M5 ;
        RECT  37.968 0 37.992 0.084 ;
    END
  END din[92]
  PIN din[93]
    DIRECTION INPUT ;
    USE SIGNAL ;
    PORT
      LAYER M5 ;
        RECT  38.064 0 38.088 0.084 ;
    END
  END din[93]
  PIN din[94]
    DIRECTION INPUT ;
    USE SIGNAL ;
    PORT
      LAYER M5 ;
        RECT  38.16 0 38.184 0.084 ;
    END
  END din[94]
  PIN din[95]
    DIRECTION INPUT ;
    USE SIGNAL ;
    PORT
      LAYER M5 ;
        RECT  38.256 0 38.28 0.084 ;
    END
  END din[95]
  PIN din[96]
    DIRECTION INPUT ;
    USE SIGNAL ;
    PORT
      LAYER M5 ;
        RECT  16.08 0 16.104 0.084 ;
    END
  END din[96]
  PIN din[97]
    DIRECTION INPUT ;
    USE SIGNAL ;
    PORT
      LAYER M5 ;
        RECT  16.176 0 16.2 0.084 ;
    END
  END din[97]
  PIN din[98]
    DIRECTION INPUT ;
    USE SIGNAL ;
    PORT
      LAYER M5 ;
        RECT  16.272 0 16.296 0.084 ;
    END
  END din[98]
  PIN din[99]
    DIRECTION INPUT ;
    USE SIGNAL ;
    PORT
      LAYER M5 ;
        RECT  16.368 0 16.392 0.084 ;
    END
  END din[99]
  PIN din[9]
    DIRECTION INPUT ;
    USE SIGNAL ;
    PORT
      LAYER M5 ;
        RECT  55.344 0 55.368 0.084 ;
    END
  END din[9]
  PIN dout[0]
    DIRECTION OUTPUT ;
    USE SIGNAL ;
    PORT
      LAYER M5 ;
        RECT  58.896 97.116 58.92 97.2 ;
    END
  END dout[0]
  PIN dout[100]
    DIRECTION OUTPUT ;
    USE SIGNAL ;
    PORT
      LAYER M5 ;
        RECT  20.88 97.116 20.904 97.2 ;
    END
  END dout[100]
  PIN dout[101]
    DIRECTION OUTPUT ;
    USE SIGNAL ;
    PORT
      LAYER M5 ;
        RECT  20.976 97.116 21 97.2 ;
    END
  END dout[101]
  PIN dout[102]
    DIRECTION OUTPUT ;
    USE SIGNAL ;
    PORT
      LAYER M5 ;
        RECT  21.072 97.116 21.096 97.2 ;
    END
  END dout[102]
  PIN dout[103]
    DIRECTION OUTPUT ;
    USE SIGNAL ;
    PORT
      LAYER M5 ;
        RECT  21.168 97.116 21.192 97.2 ;
    END
  END dout[103]
  PIN dout[104]
    DIRECTION OUTPUT ;
    USE SIGNAL ;
    PORT
      LAYER M5 ;
        RECT  21.264 97.116 21.288 97.2 ;
    END
  END dout[104]
  PIN dout[105]
    DIRECTION OUTPUT ;
    USE SIGNAL ;
    PORT
      LAYER M5 ;
        RECT  21.36 97.116 21.384 97.2 ;
    END
  END dout[105]
  PIN dout[106]
    DIRECTION OUTPUT ;
    USE SIGNAL ;
    PORT
      LAYER M5 ;
        RECT  21.456 97.116 21.48 97.2 ;
    END
  END dout[106]
  PIN dout[107]
    DIRECTION OUTPUT ;
    USE SIGNAL ;
    PORT
      LAYER M5 ;
        RECT  21.552 97.116 21.576 97.2 ;
    END
  END dout[107]
  PIN dout[108]
    DIRECTION OUTPUT ;
    USE SIGNAL ;
    PORT
      LAYER M5 ;
        RECT  21.648 97.116 21.672 97.2 ;
    END
  END dout[108]
  PIN dout[109]
    DIRECTION OUTPUT ;
    USE SIGNAL ;
    PORT
      LAYER M5 ;
        RECT  21.744 97.116 21.768 97.2 ;
    END
  END dout[109]
  PIN dout[10]
    DIRECTION OUTPUT ;
    USE SIGNAL ;
    PORT
      LAYER M5 ;
        RECT  59.856 97.116 59.88 97.2 ;
    END
  END dout[10]
  PIN dout[110]
    DIRECTION OUTPUT ;
    USE SIGNAL ;
    PORT
      LAYER M5 ;
        RECT  21.84 97.116 21.864 97.2 ;
    END
  END dout[110]
  PIN dout[111]
    DIRECTION OUTPUT ;
    USE SIGNAL ;
    PORT
      LAYER M5 ;
        RECT  21.936 97.116 21.96 97.2 ;
    END
  END dout[111]
  PIN dout[112]
    DIRECTION OUTPUT ;
    USE SIGNAL ;
    PORT
      LAYER M5 ;
        RECT  22.032 97.116 22.056 97.2 ;
    END
  END dout[112]
  PIN dout[113]
    DIRECTION OUTPUT ;
    USE SIGNAL ;
    PORT
      LAYER M5 ;
        RECT  22.128 97.116 22.152 97.2 ;
    END
  END dout[113]
  PIN dout[114]
    DIRECTION OUTPUT ;
    USE SIGNAL ;
    PORT
      LAYER M5 ;
        RECT  22.224 97.116 22.248 97.2 ;
    END
  END dout[114]
  PIN dout[115]
    DIRECTION OUTPUT ;
    USE SIGNAL ;
    PORT
      LAYER M5 ;
        RECT  22.32 97.116 22.344 97.2 ;
    END
  END dout[115]
  PIN dout[116]
    DIRECTION OUTPUT ;
    USE SIGNAL ;
    PORT
      LAYER M5 ;
        RECT  22.416 97.116 22.44 97.2 ;
    END
  END dout[116]
  PIN dout[117]
    DIRECTION OUTPUT ;
    USE SIGNAL ;
    PORT
      LAYER M5 ;
        RECT  22.512 97.116 22.536 97.2 ;
    END
  END dout[117]
  PIN dout[118]
    DIRECTION OUTPUT ;
    USE SIGNAL ;
    PORT
      LAYER M5 ;
        RECT  22.608 97.116 22.632 97.2 ;
    END
  END dout[118]
  PIN dout[119]
    DIRECTION OUTPUT ;
    USE SIGNAL ;
    PORT
      LAYER M5 ;
        RECT  22.704 97.116 22.728 97.2 ;
    END
  END dout[119]
  PIN dout[11]
    DIRECTION OUTPUT ;
    USE SIGNAL ;
    PORT
      LAYER M5 ;
        RECT  59.952 97.116 59.976 97.2 ;
    END
  END dout[11]
  PIN dout[120]
    DIRECTION OUTPUT ;
    USE SIGNAL ;
    PORT
      LAYER M5 ;
        RECT  22.8 97.116 22.824 97.2 ;
    END
  END dout[120]
  PIN dout[121]
    DIRECTION OUTPUT ;
    USE SIGNAL ;
    PORT
      LAYER M5 ;
        RECT  22.896 97.116 22.92 97.2 ;
    END
  END dout[121]
  PIN dout[122]
    DIRECTION OUTPUT ;
    USE SIGNAL ;
    PORT
      LAYER M5 ;
        RECT  22.992 97.116 23.016 97.2 ;
    END
  END dout[122]
  PIN dout[123]
    DIRECTION OUTPUT ;
    USE SIGNAL ;
    PORT
      LAYER M5 ;
        RECT  23.088 97.116 23.112 97.2 ;
    END
  END dout[123]
  PIN dout[124]
    DIRECTION OUTPUT ;
    USE SIGNAL ;
    PORT
      LAYER M5 ;
        RECT  23.184 97.116 23.208 97.2 ;
    END
  END dout[124]
  PIN dout[125]
    DIRECTION OUTPUT ;
    USE SIGNAL ;
    PORT
      LAYER M5 ;
        RECT  23.28 97.116 23.304 97.2 ;
    END
  END dout[125]
  PIN dout[126]
    DIRECTION OUTPUT ;
    USE SIGNAL ;
    PORT
      LAYER M5 ;
        RECT  23.376 97.116 23.4 97.2 ;
    END
  END dout[126]
  PIN dout[127]
    DIRECTION OUTPUT ;
    USE SIGNAL ;
    PORT
      LAYER M5 ;
        RECT  23.472 97.116 23.496 97.2 ;
    END
  END dout[127]
  PIN dout[128]
    DIRECTION OUTPUT ;
    USE SIGNAL ;
    PORT
      LAYER M5 ;
        RECT  42.768 97.116 42.792 97.2 ;
    END
  END dout[128]
  PIN dout[129]
    DIRECTION OUTPUT ;
    USE SIGNAL ;
    PORT
      LAYER M5 ;
        RECT  42.864 97.116 42.888 97.2 ;
    END
  END dout[129]
  PIN dout[12]
    DIRECTION OUTPUT ;
    USE SIGNAL ;
    PORT
      LAYER M5 ;
        RECT  60.048 97.116 60.072 97.2 ;
    END
  END dout[12]
  PIN dout[130]
    DIRECTION OUTPUT ;
    USE SIGNAL ;
    PORT
      LAYER M5 ;
        RECT  42.96 97.116 42.984 97.2 ;
    END
  END dout[130]
  PIN dout[131]
    DIRECTION OUTPUT ;
    USE SIGNAL ;
    PORT
      LAYER M5 ;
        RECT  43.056 97.116 43.08 97.2 ;
    END
  END dout[131]
  PIN dout[132]
    DIRECTION OUTPUT ;
    USE SIGNAL ;
    PORT
      LAYER M5 ;
        RECT  43.152 97.116 43.176 97.2 ;
    END
  END dout[132]
  PIN dout[133]
    DIRECTION OUTPUT ;
    USE SIGNAL ;
    PORT
      LAYER M5 ;
        RECT  43.248 97.116 43.272 97.2 ;
    END
  END dout[133]
  PIN dout[134]
    DIRECTION OUTPUT ;
    USE SIGNAL ;
    PORT
      LAYER M5 ;
        RECT  43.344 97.116 43.368 97.2 ;
    END
  END dout[134]
  PIN dout[135]
    DIRECTION OUTPUT ;
    USE SIGNAL ;
    PORT
      LAYER M5 ;
        RECT  43.44 97.116 43.464 97.2 ;
    END
  END dout[135]
  PIN dout[136]
    DIRECTION OUTPUT ;
    USE SIGNAL ;
    PORT
      LAYER M5 ;
        RECT  43.536 97.116 43.56 97.2 ;
    END
  END dout[136]
  PIN dout[137]
    DIRECTION OUTPUT ;
    USE SIGNAL ;
    PORT
      LAYER M5 ;
        RECT  43.632 97.116 43.656 97.2 ;
    END
  END dout[137]
  PIN dout[138]
    DIRECTION OUTPUT ;
    USE SIGNAL ;
    PORT
      LAYER M5 ;
        RECT  43.728 97.116 43.752 97.2 ;
    END
  END dout[138]
  PIN dout[139]
    DIRECTION OUTPUT ;
    USE SIGNAL ;
    PORT
      LAYER M5 ;
        RECT  43.824 97.116 43.848 97.2 ;
    END
  END dout[139]
  PIN dout[13]
    DIRECTION OUTPUT ;
    USE SIGNAL ;
    PORT
      LAYER M5 ;
        RECT  60.144 97.116 60.168 97.2 ;
    END
  END dout[13]
  PIN dout[140]
    DIRECTION OUTPUT ;
    USE SIGNAL ;
    PORT
      LAYER M5 ;
        RECT  43.92 97.116 43.944 97.2 ;
    END
  END dout[140]
  PIN dout[141]
    DIRECTION OUTPUT ;
    USE SIGNAL ;
    PORT
      LAYER M5 ;
        RECT  44.016 97.116 44.04 97.2 ;
    END
  END dout[141]
  PIN dout[142]
    DIRECTION OUTPUT ;
    USE SIGNAL ;
    PORT
      LAYER M5 ;
        RECT  44.112 97.116 44.136 97.2 ;
    END
  END dout[142]
  PIN dout[143]
    DIRECTION OUTPUT ;
    USE SIGNAL ;
    PORT
      LAYER M5 ;
        RECT  44.208 97.116 44.232 97.2 ;
    END
  END dout[143]
  PIN dout[144]
    DIRECTION OUTPUT ;
    USE SIGNAL ;
    PORT
      LAYER M5 ;
        RECT  44.304 97.116 44.328 97.2 ;
    END
  END dout[144]
  PIN dout[145]
    DIRECTION OUTPUT ;
    USE SIGNAL ;
    PORT
      LAYER M5 ;
        RECT  44.4 97.116 44.424 97.2 ;
    END
  END dout[145]
  PIN dout[146]
    DIRECTION OUTPUT ;
    USE SIGNAL ;
    PORT
      LAYER M5 ;
        RECT  44.496 97.116 44.52 97.2 ;
    END
  END dout[146]
  PIN dout[147]
    DIRECTION OUTPUT ;
    USE SIGNAL ;
    PORT
      LAYER M5 ;
        RECT  44.592 97.116 44.616 97.2 ;
    END
  END dout[147]
  PIN dout[148]
    DIRECTION OUTPUT ;
    USE SIGNAL ;
    PORT
      LAYER M5 ;
        RECT  44.688 97.116 44.712 97.2 ;
    END
  END dout[148]
  PIN dout[149]
    DIRECTION OUTPUT ;
    USE SIGNAL ;
    PORT
      LAYER M5 ;
        RECT  44.784 97.116 44.808 97.2 ;
    END
  END dout[149]
  PIN dout[14]
    DIRECTION OUTPUT ;
    USE SIGNAL ;
    PORT
      LAYER M5 ;
        RECT  60.24 97.116 60.264 97.2 ;
    END
  END dout[14]
  PIN dout[150]
    DIRECTION OUTPUT ;
    USE SIGNAL ;
    PORT
      LAYER M5 ;
        RECT  44.88 97.116 44.904 97.2 ;
    END
  END dout[150]
  PIN dout[151]
    DIRECTION OUTPUT ;
    USE SIGNAL ;
    PORT
      LAYER M5 ;
        RECT  44.976 97.116 45 97.2 ;
    END
  END dout[151]
  PIN dout[152]
    DIRECTION OUTPUT ;
    USE SIGNAL ;
    PORT
      LAYER M5 ;
        RECT  45.072 97.116 45.096 97.2 ;
    END
  END dout[152]
  PIN dout[153]
    DIRECTION OUTPUT ;
    USE SIGNAL ;
    PORT
      LAYER M5 ;
        RECT  45.168 97.116 45.192 97.2 ;
    END
  END dout[153]
  PIN dout[154]
    DIRECTION OUTPUT ;
    USE SIGNAL ;
    PORT
      LAYER M5 ;
        RECT  45.264 97.116 45.288 97.2 ;
    END
  END dout[154]
  PIN dout[155]
    DIRECTION OUTPUT ;
    USE SIGNAL ;
    PORT
      LAYER M5 ;
        RECT  45.36 97.116 45.384 97.2 ;
    END
  END dout[155]
  PIN dout[156]
    DIRECTION OUTPUT ;
    USE SIGNAL ;
    PORT
      LAYER M5 ;
        RECT  45.456 97.116 45.48 97.2 ;
    END
  END dout[156]
  PIN dout[157]
    DIRECTION OUTPUT ;
    USE SIGNAL ;
    PORT
      LAYER M5 ;
        RECT  45.552 97.116 45.576 97.2 ;
    END
  END dout[157]
  PIN dout[158]
    DIRECTION OUTPUT ;
    USE SIGNAL ;
    PORT
      LAYER M5 ;
        RECT  45.648 97.116 45.672 97.2 ;
    END
  END dout[158]
  PIN dout[159]
    DIRECTION OUTPUT ;
    USE SIGNAL ;
    PORT
      LAYER M5 ;
        RECT  45.744 97.116 45.768 97.2 ;
    END
  END dout[159]
  PIN dout[15]
    DIRECTION OUTPUT ;
    USE SIGNAL ;
    PORT
      LAYER M5 ;
        RECT  60.336 97.116 60.36 97.2 ;
    END
  END dout[15]
  PIN dout[160]
    DIRECTION OUTPUT ;
    USE SIGNAL ;
    PORT
      LAYER M5 ;
        RECT  23.568 97.116 23.592 97.2 ;
    END
  END dout[160]
  PIN dout[161]
    DIRECTION OUTPUT ;
    USE SIGNAL ;
    PORT
      LAYER M5 ;
        RECT  23.664 97.116 23.688 97.2 ;
    END
  END dout[161]
  PIN dout[162]
    DIRECTION OUTPUT ;
    USE SIGNAL ;
    PORT
      LAYER M5 ;
        RECT  23.76 97.116 23.784 97.2 ;
    END
  END dout[162]
  PIN dout[163]
    DIRECTION OUTPUT ;
    USE SIGNAL ;
    PORT
      LAYER M5 ;
        RECT  23.856 97.116 23.88 97.2 ;
    END
  END dout[163]
  PIN dout[164]
    DIRECTION OUTPUT ;
    USE SIGNAL ;
    PORT
      LAYER M5 ;
        RECT  23.952 97.116 23.976 97.2 ;
    END
  END dout[164]
  PIN dout[165]
    DIRECTION OUTPUT ;
    USE SIGNAL ;
    PORT
      LAYER M5 ;
        RECT  24.048 97.116 24.072 97.2 ;
    END
  END dout[165]
  PIN dout[166]
    DIRECTION OUTPUT ;
    USE SIGNAL ;
    PORT
      LAYER M5 ;
        RECT  24.144 97.116 24.168 97.2 ;
    END
  END dout[166]
  PIN dout[167]
    DIRECTION OUTPUT ;
    USE SIGNAL ;
    PORT
      LAYER M5 ;
        RECT  24.24 97.116 24.264 97.2 ;
    END
  END dout[167]
  PIN dout[168]
    DIRECTION OUTPUT ;
    USE SIGNAL ;
    PORT
      LAYER M5 ;
        RECT  24.336 97.116 24.36 97.2 ;
    END
  END dout[168]
  PIN dout[169]
    DIRECTION OUTPUT ;
    USE SIGNAL ;
    PORT
      LAYER M5 ;
        RECT  24.432 97.116 24.456 97.2 ;
    END
  END dout[169]
  PIN dout[16]
    DIRECTION OUTPUT ;
    USE SIGNAL ;
    PORT
      LAYER M5 ;
        RECT  60.432 97.116 60.456 97.2 ;
    END
  END dout[16]
  PIN dout[170]
    DIRECTION OUTPUT ;
    USE SIGNAL ;
    PORT
      LAYER M5 ;
        RECT  24.528 97.116 24.552 97.2 ;
    END
  END dout[170]
  PIN dout[171]
    DIRECTION OUTPUT ;
    USE SIGNAL ;
    PORT
      LAYER M5 ;
        RECT  24.624 97.116 24.648 97.2 ;
    END
  END dout[171]
  PIN dout[172]
    DIRECTION OUTPUT ;
    USE SIGNAL ;
    PORT
      LAYER M5 ;
        RECT  24.72 97.116 24.744 97.2 ;
    END
  END dout[172]
  PIN dout[173]
    DIRECTION OUTPUT ;
    USE SIGNAL ;
    PORT
      LAYER M5 ;
        RECT  24.816 97.116 24.84 97.2 ;
    END
  END dout[173]
  PIN dout[174]
    DIRECTION OUTPUT ;
    USE SIGNAL ;
    PORT
      LAYER M5 ;
        RECT  24.912 97.116 24.936 97.2 ;
    END
  END dout[174]
  PIN dout[175]
    DIRECTION OUTPUT ;
    USE SIGNAL ;
    PORT
      LAYER M5 ;
        RECT  25.008 97.116 25.032 97.2 ;
    END
  END dout[175]
  PIN dout[176]
    DIRECTION OUTPUT ;
    USE SIGNAL ;
    PORT
      LAYER M5 ;
        RECT  25.104 97.116 25.128 97.2 ;
    END
  END dout[176]
  PIN dout[177]
    DIRECTION OUTPUT ;
    USE SIGNAL ;
    PORT
      LAYER M5 ;
        RECT  25.2 97.116 25.224 97.2 ;
    END
  END dout[177]
  PIN dout[178]
    DIRECTION OUTPUT ;
    USE SIGNAL ;
    PORT
      LAYER M5 ;
        RECT  25.296 97.116 25.32 97.2 ;
    END
  END dout[178]
  PIN dout[179]
    DIRECTION OUTPUT ;
    USE SIGNAL ;
    PORT
      LAYER M5 ;
        RECT  25.392 97.116 25.416 97.2 ;
    END
  END dout[179]
  PIN dout[17]
    DIRECTION OUTPUT ;
    USE SIGNAL ;
    PORT
      LAYER M5 ;
        RECT  60.528 97.116 60.552 97.2 ;
    END
  END dout[17]
  PIN dout[180]
    DIRECTION OUTPUT ;
    USE SIGNAL ;
    PORT
      LAYER M5 ;
        RECT  25.488 97.116 25.512 97.2 ;
    END
  END dout[180]
  PIN dout[181]
    DIRECTION OUTPUT ;
    USE SIGNAL ;
    PORT
      LAYER M5 ;
        RECT  25.584 97.116 25.608 97.2 ;
    END
  END dout[181]
  PIN dout[182]
    DIRECTION OUTPUT ;
    USE SIGNAL ;
    PORT
      LAYER M5 ;
        RECT  25.68 97.116 25.704 97.2 ;
    END
  END dout[182]
  PIN dout[183]
    DIRECTION OUTPUT ;
    USE SIGNAL ;
    PORT
      LAYER M5 ;
        RECT  25.776 97.116 25.8 97.2 ;
    END
  END dout[183]
  PIN dout[184]
    DIRECTION OUTPUT ;
    USE SIGNAL ;
    PORT
      LAYER M5 ;
        RECT  25.872 97.116 25.896 97.2 ;
    END
  END dout[184]
  PIN dout[185]
    DIRECTION OUTPUT ;
    USE SIGNAL ;
    PORT
      LAYER M5 ;
        RECT  25.968 97.116 25.992 97.2 ;
    END
  END dout[185]
  PIN dout[186]
    DIRECTION OUTPUT ;
    USE SIGNAL ;
    PORT
      LAYER M5 ;
        RECT  26.064 97.116 26.088 97.2 ;
    END
  END dout[186]
  PIN dout[187]
    DIRECTION OUTPUT ;
    USE SIGNAL ;
    PORT
      LAYER M5 ;
        RECT  26.16 97.116 26.184 97.2 ;
    END
  END dout[187]
  PIN dout[188]
    DIRECTION OUTPUT ;
    USE SIGNAL ;
    PORT
      LAYER M5 ;
        RECT  26.256 97.116 26.28 97.2 ;
    END
  END dout[188]
  PIN dout[189]
    DIRECTION OUTPUT ;
    USE SIGNAL ;
    PORT
      LAYER M5 ;
        RECT  26.352 97.116 26.376 97.2 ;
    END
  END dout[189]
  PIN dout[18]
    DIRECTION OUTPUT ;
    USE SIGNAL ;
    PORT
      LAYER M5 ;
        RECT  60.624 97.116 60.648 97.2 ;
    END
  END dout[18]
  PIN dout[190]
    DIRECTION OUTPUT ;
    USE SIGNAL ;
    PORT
      LAYER M5 ;
        RECT  26.448 97.116 26.472 97.2 ;
    END
  END dout[190]
  PIN dout[191]
    DIRECTION OUTPUT ;
    USE SIGNAL ;
    PORT
      LAYER M5 ;
        RECT  26.544 97.116 26.568 97.2 ;
    END
  END dout[191]
  PIN dout[192]
    DIRECTION OUTPUT ;
    USE SIGNAL ;
    PORT
      LAYER M5 ;
        RECT  71.184 97.116 71.208 97.2 ;
    END
  END dout[192]
  PIN dout[193]
    DIRECTION OUTPUT ;
    USE SIGNAL ;
    PORT
      LAYER M5 ;
        RECT  71.28 97.116 71.304 97.2 ;
    END
  END dout[193]
  PIN dout[194]
    DIRECTION OUTPUT ;
    USE SIGNAL ;
    PORT
      LAYER M5 ;
        RECT  71.376 97.116 71.4 97.2 ;
    END
  END dout[194]
  PIN dout[195]
    DIRECTION OUTPUT ;
    USE SIGNAL ;
    PORT
      LAYER M5 ;
        RECT  71.472 97.116 71.496 97.2 ;
    END
  END dout[195]
  PIN dout[196]
    DIRECTION OUTPUT ;
    USE SIGNAL ;
    PORT
      LAYER M5 ;
        RECT  71.568 97.116 71.592 97.2 ;
    END
  END dout[196]
  PIN dout[197]
    DIRECTION OUTPUT ;
    USE SIGNAL ;
    PORT
      LAYER M5 ;
        RECT  71.664 97.116 71.688 97.2 ;
    END
  END dout[197]
  PIN dout[198]
    DIRECTION OUTPUT ;
    USE SIGNAL ;
    PORT
      LAYER M5 ;
        RECT  71.76 97.116 71.784 97.2 ;
    END
  END dout[198]
  PIN dout[199]
    DIRECTION OUTPUT ;
    USE SIGNAL ;
    PORT
      LAYER M5 ;
        RECT  71.856 97.116 71.88 97.2 ;
    END
  END dout[199]
  PIN dout[19]
    DIRECTION OUTPUT ;
    USE SIGNAL ;
    PORT
      LAYER M5 ;
        RECT  60.72 97.116 60.744 97.2 ;
    END
  END dout[19]
  PIN dout[1]
    DIRECTION OUTPUT ;
    USE SIGNAL ;
    PORT
      LAYER M5 ;
        RECT  58.992 97.116 59.016 97.2 ;
    END
  END dout[1]
  PIN dout[200]
    DIRECTION OUTPUT ;
    USE SIGNAL ;
    PORT
      LAYER M5 ;
        RECT  71.952 97.116 71.976 97.2 ;
    END
  END dout[200]
  PIN dout[201]
    DIRECTION OUTPUT ;
    USE SIGNAL ;
    PORT
      LAYER M5 ;
        RECT  72.048 97.116 72.072 97.2 ;
    END
  END dout[201]
  PIN dout[202]
    DIRECTION OUTPUT ;
    USE SIGNAL ;
    PORT
      LAYER M5 ;
        RECT  72.144 97.116 72.168 97.2 ;
    END
  END dout[202]
  PIN dout[203]
    DIRECTION OUTPUT ;
    USE SIGNAL ;
    PORT
      LAYER M5 ;
        RECT  72.24 97.116 72.264 97.2 ;
    END
  END dout[203]
  PIN dout[204]
    DIRECTION OUTPUT ;
    USE SIGNAL ;
    PORT
      LAYER M5 ;
        RECT  72.336 97.116 72.36 97.2 ;
    END
  END dout[204]
  PIN dout[205]
    DIRECTION OUTPUT ;
    USE SIGNAL ;
    PORT
      LAYER M5 ;
        RECT  72.432 97.116 72.456 97.2 ;
    END
  END dout[205]
  PIN dout[206]
    DIRECTION OUTPUT ;
    USE SIGNAL ;
    PORT
      LAYER M5 ;
        RECT  72.528 97.116 72.552 97.2 ;
    END
  END dout[206]
  PIN dout[207]
    DIRECTION OUTPUT ;
    USE SIGNAL ;
    PORT
      LAYER M5 ;
        RECT  72.624 97.116 72.648 97.2 ;
    END
  END dout[207]
  PIN dout[208]
    DIRECTION OUTPUT ;
    USE SIGNAL ;
    PORT
      LAYER M5 ;
        RECT  72.72 97.116 72.744 97.2 ;
    END
  END dout[208]
  PIN dout[209]
    DIRECTION OUTPUT ;
    USE SIGNAL ;
    PORT
      LAYER M5 ;
        RECT  72.816 97.116 72.84 97.2 ;
    END
  END dout[209]
  PIN dout[20]
    DIRECTION OUTPUT ;
    USE SIGNAL ;
    PORT
      LAYER M5 ;
        RECT  60.816 97.116 60.84 97.2 ;
    END
  END dout[20]
  PIN dout[210]
    DIRECTION OUTPUT ;
    USE SIGNAL ;
    PORT
      LAYER M5 ;
        RECT  72.912 97.116 72.936 97.2 ;
    END
  END dout[210]
  PIN dout[211]
    DIRECTION OUTPUT ;
    USE SIGNAL ;
    PORT
      LAYER M5 ;
        RECT  73.008 97.116 73.032 97.2 ;
    END
  END dout[211]
  PIN dout[212]
    DIRECTION OUTPUT ;
    USE SIGNAL ;
    PORT
      LAYER M5 ;
        RECT  73.104 97.116 73.128 97.2 ;
    END
  END dout[212]
  PIN dout[213]
    DIRECTION OUTPUT ;
    USE SIGNAL ;
    PORT
      LAYER M5 ;
        RECT  73.2 97.116 73.224 97.2 ;
    END
  END dout[213]
  PIN dout[214]
    DIRECTION OUTPUT ;
    USE SIGNAL ;
    PORT
      LAYER M5 ;
        RECT  73.296 97.116 73.32 97.2 ;
    END
  END dout[214]
  PIN dout[215]
    DIRECTION OUTPUT ;
    USE SIGNAL ;
    PORT
      LAYER M5 ;
        RECT  73.392 97.116 73.416 97.2 ;
    END
  END dout[215]
  PIN dout[216]
    DIRECTION OUTPUT ;
    USE SIGNAL ;
    PORT
      LAYER M5 ;
        RECT  73.488 97.116 73.512 97.2 ;
    END
  END dout[216]
  PIN dout[217]
    DIRECTION OUTPUT ;
    USE SIGNAL ;
    PORT
      LAYER M5 ;
        RECT  73.584 97.116 73.608 97.2 ;
    END
  END dout[217]
  PIN dout[218]
    DIRECTION OUTPUT ;
    USE SIGNAL ;
    PORT
      LAYER M5 ;
        RECT  73.68 97.116 73.704 97.2 ;
    END
  END dout[218]
  PIN dout[219]
    DIRECTION OUTPUT ;
    USE SIGNAL ;
    PORT
      LAYER M5 ;
        RECT  73.776 97.116 73.8 97.2 ;
    END
  END dout[219]
  PIN dout[21]
    DIRECTION OUTPUT ;
    USE SIGNAL ;
    PORT
      LAYER M5 ;
        RECT  60.912 97.116 60.936 97.2 ;
    END
  END dout[21]
  PIN dout[220]
    DIRECTION OUTPUT ;
    USE SIGNAL ;
    PORT
      LAYER M5 ;
        RECT  73.872 97.116 73.896 97.2 ;
    END
  END dout[220]
  PIN dout[221]
    DIRECTION OUTPUT ;
    USE SIGNAL ;
    PORT
      LAYER M5 ;
        RECT  73.968 97.116 73.992 97.2 ;
    END
  END dout[221]
  PIN dout[222]
    DIRECTION OUTPUT ;
    USE SIGNAL ;
    PORT
      LAYER M5 ;
        RECT  74.064 97.116 74.088 97.2 ;
    END
  END dout[222]
  PIN dout[223]
    DIRECTION OUTPUT ;
    USE SIGNAL ;
    PORT
      LAYER M5 ;
        RECT  74.16 97.116 74.184 97.2 ;
    END
  END dout[223]
  PIN dout[224]
    DIRECTION OUTPUT ;
    USE SIGNAL ;
    PORT
      LAYER M5 ;
        RECT  81.168 97.116 81.192 97.2 ;
    END
  END dout[224]
  PIN dout[225]
    DIRECTION OUTPUT ;
    USE SIGNAL ;
    PORT
      LAYER M5 ;
        RECT  81.264 97.116 81.288 97.2 ;
    END
  END dout[225]
  PIN dout[226]
    DIRECTION OUTPUT ;
    USE SIGNAL ;
    PORT
      LAYER M5 ;
        RECT  81.36 97.116 81.384 97.2 ;
    END
  END dout[226]
  PIN dout[227]
    DIRECTION OUTPUT ;
    USE SIGNAL ;
    PORT
      LAYER M5 ;
        RECT  81.456 97.116 81.48 97.2 ;
    END
  END dout[227]
  PIN dout[228]
    DIRECTION OUTPUT ;
    USE SIGNAL ;
    PORT
      LAYER M5 ;
        RECT  81.552 97.116 81.576 97.2 ;
    END
  END dout[228]
  PIN dout[229]
    DIRECTION OUTPUT ;
    USE SIGNAL ;
    PORT
      LAYER M5 ;
        RECT  81.648 97.116 81.672 97.2 ;
    END
  END dout[229]
  PIN dout[22]
    DIRECTION OUTPUT ;
    USE SIGNAL ;
    PORT
      LAYER M5 ;
        RECT  61.008 97.116 61.032 97.2 ;
    END
  END dout[22]
  PIN dout[230]
    DIRECTION OUTPUT ;
    USE SIGNAL ;
    PORT
      LAYER M5 ;
        RECT  81.744 97.116 81.768 97.2 ;
    END
  END dout[230]
  PIN dout[231]
    DIRECTION OUTPUT ;
    USE SIGNAL ;
    PORT
      LAYER M5 ;
        RECT  81.84 97.116 81.864 97.2 ;
    END
  END dout[231]
  PIN dout[232]
    DIRECTION OUTPUT ;
    USE SIGNAL ;
    PORT
      LAYER M5 ;
        RECT  81.936 97.116 81.96 97.2 ;
    END
  END dout[232]
  PIN dout[233]
    DIRECTION OUTPUT ;
    USE SIGNAL ;
    PORT
      LAYER M5 ;
        RECT  82.032 97.116 82.056 97.2 ;
    END
  END dout[233]
  PIN dout[234]
    DIRECTION OUTPUT ;
    USE SIGNAL ;
    PORT
      LAYER M5 ;
        RECT  82.128 97.116 82.152 97.2 ;
    END
  END dout[234]
  PIN dout[235]
    DIRECTION OUTPUT ;
    USE SIGNAL ;
    PORT
      LAYER M5 ;
        RECT  82.224 97.116 82.248 97.2 ;
    END
  END dout[235]
  PIN dout[236]
    DIRECTION OUTPUT ;
    USE SIGNAL ;
    PORT
      LAYER M5 ;
        RECT  82.32 97.116 82.344 97.2 ;
    END
  END dout[236]
  PIN dout[237]
    DIRECTION OUTPUT ;
    USE SIGNAL ;
    PORT
      LAYER M5 ;
        RECT  82.416 97.116 82.44 97.2 ;
    END
  END dout[237]
  PIN dout[238]
    DIRECTION OUTPUT ;
    USE SIGNAL ;
    PORT
      LAYER M5 ;
        RECT  82.512 97.116 82.536 97.2 ;
    END
  END dout[238]
  PIN dout[239]
    DIRECTION OUTPUT ;
    USE SIGNAL ;
    PORT
      LAYER M5 ;
        RECT  82.608 97.116 82.632 97.2 ;
    END
  END dout[239]
  PIN dout[23]
    DIRECTION OUTPUT ;
    USE SIGNAL ;
    PORT
      LAYER M5 ;
        RECT  61.104 97.116 61.128 97.2 ;
    END
  END dout[23]
  PIN dout[240]
    DIRECTION OUTPUT ;
    USE SIGNAL ;
    PORT
      LAYER M5 ;
        RECT  82.704 97.116 82.728 97.2 ;
    END
  END dout[240]
  PIN dout[241]
    DIRECTION OUTPUT ;
    USE SIGNAL ;
    PORT
      LAYER M5 ;
        RECT  82.8 97.116 82.824 97.2 ;
    END
  END dout[241]
  PIN dout[242]
    DIRECTION OUTPUT ;
    USE SIGNAL ;
    PORT
      LAYER M5 ;
        RECT  82.896 97.116 82.92 97.2 ;
    END
  END dout[242]
  PIN dout[243]
    DIRECTION OUTPUT ;
    USE SIGNAL ;
    PORT
      LAYER M5 ;
        RECT  82.992 97.116 83.016 97.2 ;
    END
  END dout[243]
  PIN dout[244]
    DIRECTION OUTPUT ;
    USE SIGNAL ;
    PORT
      LAYER M5 ;
        RECT  83.088 97.116 83.112 97.2 ;
    END
  END dout[244]
  PIN dout[245]
    DIRECTION OUTPUT ;
    USE SIGNAL ;
    PORT
      LAYER M5 ;
        RECT  83.184 97.116 83.208 97.2 ;
    END
  END dout[245]
  PIN dout[246]
    DIRECTION OUTPUT ;
    USE SIGNAL ;
    PORT
      LAYER M5 ;
        RECT  83.28 97.116 83.304 97.2 ;
    END
  END dout[246]
  PIN dout[247]
    DIRECTION OUTPUT ;
    USE SIGNAL ;
    PORT
      LAYER M5 ;
        RECT  83.376 97.116 83.4 97.2 ;
    END
  END dout[247]
  PIN dout[248]
    DIRECTION OUTPUT ;
    USE SIGNAL ;
    PORT
      LAYER M5 ;
        RECT  83.472 97.116 83.496 97.2 ;
    END
  END dout[248]
  PIN dout[249]
    DIRECTION OUTPUT ;
    USE SIGNAL ;
    PORT
      LAYER M5 ;
        RECT  83.568 97.116 83.592 97.2 ;
    END
  END dout[249]
  PIN dout[24]
    DIRECTION OUTPUT ;
    USE SIGNAL ;
    PORT
      LAYER M5 ;
        RECT  61.2 97.116 61.224 97.2 ;
    END
  END dout[24]
  PIN dout[250]
    DIRECTION OUTPUT ;
    USE SIGNAL ;
    PORT
      LAYER M5 ;
        RECT  83.664 97.116 83.688 97.2 ;
    END
  END dout[250]
  PIN dout[251]
    DIRECTION OUTPUT ;
    USE SIGNAL ;
    PORT
      LAYER M5 ;
        RECT  83.76 97.116 83.784 97.2 ;
    END
  END dout[251]
  PIN dout[252]
    DIRECTION OUTPUT ;
    USE SIGNAL ;
    PORT
      LAYER M5 ;
        RECT  83.856 97.116 83.88 97.2 ;
    END
  END dout[252]
  PIN dout[253]
    DIRECTION OUTPUT ;
    USE SIGNAL ;
    PORT
      LAYER M5 ;
        RECT  83.952 97.116 83.976 97.2 ;
    END
  END dout[253]
  PIN dout[254]
    DIRECTION OUTPUT ;
    USE SIGNAL ;
    PORT
      LAYER M5 ;
        RECT  84.048 97.116 84.072 97.2 ;
    END
  END dout[254]
  PIN dout[255]
    DIRECTION OUTPUT ;
    USE SIGNAL ;
    PORT
      LAYER M5 ;
        RECT  84.144 97.116 84.168 97.2 ;
    END
  END dout[255]
  PIN dout[256]
    DIRECTION OUTPUT ;
    USE SIGNAL ;
    PORT
      LAYER M5 ;
        RECT  78.096 97.116 78.12 97.2 ;
    END
  END dout[256]
  PIN dout[257]
    DIRECTION OUTPUT ;
    USE SIGNAL ;
    PORT
      LAYER M5 ;
        RECT  78.192 97.116 78.216 97.2 ;
    END
  END dout[257]
  PIN dout[258]
    DIRECTION OUTPUT ;
    USE SIGNAL ;
    PORT
      LAYER M5 ;
        RECT  78.288 97.116 78.312 97.2 ;
    END
  END dout[258]
  PIN dout[259]
    DIRECTION OUTPUT ;
    USE SIGNAL ;
    PORT
      LAYER M5 ;
        RECT  78.384 97.116 78.408 97.2 ;
    END
  END dout[259]
  PIN dout[25]
    DIRECTION OUTPUT ;
    USE SIGNAL ;
    PORT
      LAYER M5 ;
        RECT  61.296 97.116 61.32 97.2 ;
    END
  END dout[25]
  PIN dout[260]
    DIRECTION OUTPUT ;
    USE SIGNAL ;
    PORT
      LAYER M5 ;
        RECT  78.48 97.116 78.504 97.2 ;
    END
  END dout[260]
  PIN dout[261]
    DIRECTION OUTPUT ;
    USE SIGNAL ;
    PORT
      LAYER M5 ;
        RECT  78.576 97.116 78.6 97.2 ;
    END
  END dout[261]
  PIN dout[262]
    DIRECTION OUTPUT ;
    USE SIGNAL ;
    PORT
      LAYER M5 ;
        RECT  78.672 97.116 78.696 97.2 ;
    END
  END dout[262]
  PIN dout[263]
    DIRECTION OUTPUT ;
    USE SIGNAL ;
    PORT
      LAYER M5 ;
        RECT  78.768 97.116 78.792 97.2 ;
    END
  END dout[263]
  PIN dout[264]
    DIRECTION OUTPUT ;
    USE SIGNAL ;
    PORT
      LAYER M5 ;
        RECT  78.864 97.116 78.888 97.2 ;
    END
  END dout[264]
  PIN dout[265]
    DIRECTION OUTPUT ;
    USE SIGNAL ;
    PORT
      LAYER M5 ;
        RECT  78.96 97.116 78.984 97.2 ;
    END
  END dout[265]
  PIN dout[266]
    DIRECTION OUTPUT ;
    USE SIGNAL ;
    PORT
      LAYER M5 ;
        RECT  79.056 97.116 79.08 97.2 ;
    END
  END dout[266]
  PIN dout[267]
    DIRECTION OUTPUT ;
    USE SIGNAL ;
    PORT
      LAYER M5 ;
        RECT  79.152 97.116 79.176 97.2 ;
    END
  END dout[267]
  PIN dout[268]
    DIRECTION OUTPUT ;
    USE SIGNAL ;
    PORT
      LAYER M5 ;
        RECT  79.248 97.116 79.272 97.2 ;
    END
  END dout[268]
  PIN dout[269]
    DIRECTION OUTPUT ;
    USE SIGNAL ;
    PORT
      LAYER M5 ;
        RECT  79.344 97.116 79.368 97.2 ;
    END
  END dout[269]
  PIN dout[26]
    DIRECTION OUTPUT ;
    USE SIGNAL ;
    PORT
      LAYER M5 ;
        RECT  61.392 97.116 61.416 97.2 ;
    END
  END dout[26]
  PIN dout[270]
    DIRECTION OUTPUT ;
    USE SIGNAL ;
    PORT
      LAYER M5 ;
        RECT  79.44 97.116 79.464 97.2 ;
    END
  END dout[270]
  PIN dout[271]
    DIRECTION OUTPUT ;
    USE SIGNAL ;
    PORT
      LAYER M5 ;
        RECT  79.536 97.116 79.56 97.2 ;
    END
  END dout[271]
  PIN dout[272]
    DIRECTION OUTPUT ;
    USE SIGNAL ;
    PORT
      LAYER M5 ;
        RECT  79.632 97.116 79.656 97.2 ;
    END
  END dout[272]
  PIN dout[273]
    DIRECTION OUTPUT ;
    USE SIGNAL ;
    PORT
      LAYER M5 ;
        RECT  79.728 97.116 79.752 97.2 ;
    END
  END dout[273]
  PIN dout[274]
    DIRECTION OUTPUT ;
    USE SIGNAL ;
    PORT
      LAYER M5 ;
        RECT  79.824 97.116 79.848 97.2 ;
    END
  END dout[274]
  PIN dout[275]
    DIRECTION OUTPUT ;
    USE SIGNAL ;
    PORT
      LAYER M5 ;
        RECT  79.92 97.116 79.944 97.2 ;
    END
  END dout[275]
  PIN dout[276]
    DIRECTION OUTPUT ;
    USE SIGNAL ;
    PORT
      LAYER M5 ;
        RECT  80.016 97.116 80.04 97.2 ;
    END
  END dout[276]
  PIN dout[277]
    DIRECTION OUTPUT ;
    USE SIGNAL ;
    PORT
      LAYER M5 ;
        RECT  80.112 97.116 80.136 97.2 ;
    END
  END dout[277]
  PIN dout[278]
    DIRECTION OUTPUT ;
    USE SIGNAL ;
    PORT
      LAYER M5 ;
        RECT  80.208 97.116 80.232 97.2 ;
    END
  END dout[278]
  PIN dout[279]
    DIRECTION OUTPUT ;
    USE SIGNAL ;
    PORT
      LAYER M5 ;
        RECT  80.304 97.116 80.328 97.2 ;
    END
  END dout[279]
  PIN dout[27]
    DIRECTION OUTPUT ;
    USE SIGNAL ;
    PORT
      LAYER M5 ;
        RECT  61.488 97.116 61.512 97.2 ;
    END
  END dout[27]
  PIN dout[280]
    DIRECTION OUTPUT ;
    USE SIGNAL ;
    PORT
      LAYER M5 ;
        RECT  80.4 97.116 80.424 97.2 ;
    END
  END dout[280]
  PIN dout[281]
    DIRECTION OUTPUT ;
    USE SIGNAL ;
    PORT
      LAYER M5 ;
        RECT  80.496 97.116 80.52 97.2 ;
    END
  END dout[281]
  PIN dout[282]
    DIRECTION OUTPUT ;
    USE SIGNAL ;
    PORT
      LAYER M5 ;
        RECT  80.592 97.116 80.616 97.2 ;
    END
  END dout[282]
  PIN dout[283]
    DIRECTION OUTPUT ;
    USE SIGNAL ;
    PORT
      LAYER M5 ;
        RECT  80.688 97.116 80.712 97.2 ;
    END
  END dout[283]
  PIN dout[284]
    DIRECTION OUTPUT ;
    USE SIGNAL ;
    PORT
      LAYER M5 ;
        RECT  80.784 97.116 80.808 97.2 ;
    END
  END dout[284]
  PIN dout[285]
    DIRECTION OUTPUT ;
    USE SIGNAL ;
    PORT
      LAYER M5 ;
        RECT  80.88 97.116 80.904 97.2 ;
    END
  END dout[285]
  PIN dout[286]
    DIRECTION OUTPUT ;
    USE SIGNAL ;
    PORT
      LAYER M5 ;
        RECT  80.976 97.116 81 97.2 ;
    END
  END dout[286]
  PIN dout[287]
    DIRECTION OUTPUT ;
    USE SIGNAL ;
    PORT
      LAYER M5 ;
        RECT  81.072 97.116 81.096 97.2 ;
    END
  END dout[287]
  PIN dout[288]
    DIRECTION OUTPUT ;
    USE SIGNAL ;
    PORT
      LAYER M5 ;
        RECT  84.24 97.116 84.264 97.2 ;
    END
  END dout[288]
  PIN dout[289]
    DIRECTION OUTPUT ;
    USE SIGNAL ;
    PORT
      LAYER M5 ;
        RECT  84.336 97.116 84.36 97.2 ;
    END
  END dout[289]
  PIN dout[28]
    DIRECTION OUTPUT ;
    USE SIGNAL ;
    PORT
      LAYER M5 ;
        RECT  61.584 97.116 61.608 97.2 ;
    END
  END dout[28]
  PIN dout[290]
    DIRECTION OUTPUT ;
    USE SIGNAL ;
    PORT
      LAYER M5 ;
        RECT  84.432 97.116 84.456 97.2 ;
    END
  END dout[290]
  PIN dout[291]
    DIRECTION OUTPUT ;
    USE SIGNAL ;
    PORT
      LAYER M5 ;
        RECT  84.528 97.116 84.552 97.2 ;
    END
  END dout[291]
  PIN dout[292]
    DIRECTION OUTPUT ;
    USE SIGNAL ;
    PORT
      LAYER M5 ;
        RECT  84.624 97.116 84.648 97.2 ;
    END
  END dout[292]
  PIN dout[293]
    DIRECTION OUTPUT ;
    USE SIGNAL ;
    PORT
      LAYER M5 ;
        RECT  84.72 97.116 84.744 97.2 ;
    END
  END dout[293]
  PIN dout[294]
    DIRECTION OUTPUT ;
    USE SIGNAL ;
    PORT
      LAYER M5 ;
        RECT  84.816 97.116 84.84 97.2 ;
    END
  END dout[294]
  PIN dout[295]
    DIRECTION OUTPUT ;
    USE SIGNAL ;
    PORT
      LAYER M5 ;
        RECT  84.912 97.116 84.936 97.2 ;
    END
  END dout[295]
  PIN dout[296]
    DIRECTION OUTPUT ;
    USE SIGNAL ;
    PORT
      LAYER M5 ;
        RECT  85.008 97.116 85.032 97.2 ;
    END
  END dout[296]
  PIN dout[297]
    DIRECTION OUTPUT ;
    USE SIGNAL ;
    PORT
      LAYER M5 ;
        RECT  85.104 97.116 85.128 97.2 ;
    END
  END dout[297]
  PIN dout[298]
    DIRECTION OUTPUT ;
    USE SIGNAL ;
    PORT
      LAYER M5 ;
        RECT  85.2 97.116 85.224 97.2 ;
    END
  END dout[298]
  PIN dout[299]
    DIRECTION OUTPUT ;
    USE SIGNAL ;
    PORT
      LAYER M5 ;
        RECT  85.296 97.116 85.32 97.2 ;
    END
  END dout[299]
  PIN dout[29]
    DIRECTION OUTPUT ;
    USE SIGNAL ;
    PORT
      LAYER M5 ;
        RECT  61.68 97.116 61.704 97.2 ;
    END
  END dout[29]
  PIN dout[2]
    DIRECTION OUTPUT ;
    USE SIGNAL ;
    PORT
      LAYER M5 ;
        RECT  59.088 97.116 59.112 97.2 ;
    END
  END dout[2]
  PIN dout[300]
    DIRECTION OUTPUT ;
    USE SIGNAL ;
    PORT
      LAYER M5 ;
        RECT  85.392 97.116 85.416 97.2 ;
    END
  END dout[300]
  PIN dout[301]
    DIRECTION OUTPUT ;
    USE SIGNAL ;
    PORT
      LAYER M5 ;
        RECT  85.488 97.116 85.512 97.2 ;
    END
  END dout[301]
  PIN dout[302]
    DIRECTION OUTPUT ;
    USE SIGNAL ;
    PORT
      LAYER M5 ;
        RECT  85.584 97.116 85.608 97.2 ;
    END
  END dout[302]
  PIN dout[303]
    DIRECTION OUTPUT ;
    USE SIGNAL ;
    PORT
      LAYER M5 ;
        RECT  85.68 97.116 85.704 97.2 ;
    END
  END dout[303]
  PIN dout[304]
    DIRECTION OUTPUT ;
    USE SIGNAL ;
    PORT
      LAYER M5 ;
        RECT  85.776 97.116 85.8 97.2 ;
    END
  END dout[304]
  PIN dout[305]
    DIRECTION OUTPUT ;
    USE SIGNAL ;
    PORT
      LAYER M5 ;
        RECT  85.872 97.116 85.896 97.2 ;
    END
  END dout[305]
  PIN dout[306]
    DIRECTION OUTPUT ;
    USE SIGNAL ;
    PORT
      LAYER M5 ;
        RECT  85.968 97.116 85.992 97.2 ;
    END
  END dout[306]
  PIN dout[307]
    DIRECTION OUTPUT ;
    USE SIGNAL ;
    PORT
      LAYER M5 ;
        RECT  86.064 97.116 86.088 97.2 ;
    END
  END dout[307]
  PIN dout[308]
    DIRECTION OUTPUT ;
    USE SIGNAL ;
    PORT
      LAYER M5 ;
        RECT  86.16 97.116 86.184 97.2 ;
    END
  END dout[308]
  PIN dout[309]
    DIRECTION OUTPUT ;
    USE SIGNAL ;
    PORT
      LAYER M5 ;
        RECT  86.256 97.116 86.28 97.2 ;
    END
  END dout[309]
  PIN dout[30]
    DIRECTION OUTPUT ;
    USE SIGNAL ;
    PORT
      LAYER M5 ;
        RECT  61.776 97.116 61.8 97.2 ;
    END
  END dout[30]
  PIN dout[310]
    DIRECTION OUTPUT ;
    USE SIGNAL ;
    PORT
      LAYER M5 ;
        RECT  86.352 97.116 86.376 97.2 ;
    END
  END dout[310]
  PIN dout[311]
    DIRECTION OUTPUT ;
    USE SIGNAL ;
    PORT
      LAYER M5 ;
        RECT  86.448 97.116 86.472 97.2 ;
    END
  END dout[311]
  PIN dout[312]
    DIRECTION OUTPUT ;
    USE SIGNAL ;
    PORT
      LAYER M5 ;
        RECT  86.544 97.116 86.568 97.2 ;
    END
  END dout[312]
  PIN dout[313]
    DIRECTION OUTPUT ;
    USE SIGNAL ;
    PORT
      LAYER M5 ;
        RECT  86.64 97.116 86.664 97.2 ;
    END
  END dout[313]
  PIN dout[314]
    DIRECTION OUTPUT ;
    USE SIGNAL ;
    PORT
      LAYER M5 ;
        RECT  86.736 97.116 86.76 97.2 ;
    END
  END dout[314]
  PIN dout[315]
    DIRECTION OUTPUT ;
    USE SIGNAL ;
    PORT
      LAYER M5 ;
        RECT  86.832 97.116 86.856 97.2 ;
    END
  END dout[315]
  PIN dout[316]
    DIRECTION OUTPUT ;
    USE SIGNAL ;
    PORT
      LAYER M5 ;
        RECT  86.928 97.116 86.952 97.2 ;
    END
  END dout[316]
  PIN dout[317]
    DIRECTION OUTPUT ;
    USE SIGNAL ;
    PORT
      LAYER M5 ;
        RECT  87.024 97.116 87.048 97.2 ;
    END
  END dout[317]
  PIN dout[318]
    DIRECTION OUTPUT ;
    USE SIGNAL ;
    PORT
      LAYER M5 ;
        RECT  87.12 97.116 87.144 97.2 ;
    END
  END dout[318]
  PIN dout[319]
    DIRECTION OUTPUT ;
    USE SIGNAL ;
    PORT
      LAYER M5 ;
        RECT  87.216 97.116 87.24 97.2 ;
    END
  END dout[319]
  PIN dout[31]
    DIRECTION OUTPUT ;
    USE SIGNAL ;
    PORT
      LAYER M5 ;
        RECT  61.872 97.116 61.896 97.2 ;
    END
  END dout[31]
  PIN dout[320]
    DIRECTION OUTPUT ;
    USE SIGNAL ;
    PORT
      LAYER M5 ;
        RECT  26.64 97.116 26.664 97.2 ;
    END
  END dout[320]
  PIN dout[321]
    DIRECTION OUTPUT ;
    USE SIGNAL ;
    PORT
      LAYER M5 ;
        RECT  26.736 97.116 26.76 97.2 ;
    END
  END dout[321]
  PIN dout[322]
    DIRECTION OUTPUT ;
    USE SIGNAL ;
    PORT
      LAYER M5 ;
        RECT  26.832 97.116 26.856 97.2 ;
    END
  END dout[322]
  PIN dout[323]
    DIRECTION OUTPUT ;
    USE SIGNAL ;
    PORT
      LAYER M5 ;
        RECT  26.928 97.116 26.952 97.2 ;
    END
  END dout[323]
  PIN dout[324]
    DIRECTION OUTPUT ;
    USE SIGNAL ;
    PORT
      LAYER M5 ;
        RECT  27.024 97.116 27.048 97.2 ;
    END
  END dout[324]
  PIN dout[325]
    DIRECTION OUTPUT ;
    USE SIGNAL ;
    PORT
      LAYER M5 ;
        RECT  27.12 97.116 27.144 97.2 ;
    END
  END dout[325]
  PIN dout[326]
    DIRECTION OUTPUT ;
    USE SIGNAL ;
    PORT
      LAYER M5 ;
        RECT  27.216 97.116 27.24 97.2 ;
    END
  END dout[326]
  PIN dout[327]
    DIRECTION OUTPUT ;
    USE SIGNAL ;
    PORT
      LAYER M5 ;
        RECT  27.312 97.116 27.336 97.2 ;
    END
  END dout[327]
  PIN dout[328]
    DIRECTION OUTPUT ;
    USE SIGNAL ;
    PORT
      LAYER M5 ;
        RECT  27.408 97.116 27.432 97.2 ;
    END
  END dout[328]
  PIN dout[329]
    DIRECTION OUTPUT ;
    USE SIGNAL ;
    PORT
      LAYER M5 ;
        RECT  27.504 97.116 27.528 97.2 ;
    END
  END dout[329]
  PIN dout[32]
    DIRECTION OUTPUT ;
    USE SIGNAL ;
    PORT
      LAYER M5 ;
        RECT  45.84 97.116 45.864 97.2 ;
    END
  END dout[32]
  PIN dout[330]
    DIRECTION OUTPUT ;
    USE SIGNAL ;
    PORT
      LAYER M5 ;
        RECT  27.6 97.116 27.624 97.2 ;
    END
  END dout[330]
  PIN dout[331]
    DIRECTION OUTPUT ;
    USE SIGNAL ;
    PORT
      LAYER M5 ;
        RECT  27.696 97.116 27.72 97.2 ;
    END
  END dout[331]
  PIN dout[332]
    DIRECTION OUTPUT ;
    USE SIGNAL ;
    PORT
      LAYER M5 ;
        RECT  27.792 97.116 27.816 97.2 ;
    END
  END dout[332]
  PIN dout[333]
    DIRECTION OUTPUT ;
    USE SIGNAL ;
    PORT
      LAYER M5 ;
        RECT  27.888 97.116 27.912 97.2 ;
    END
  END dout[333]
  PIN dout[334]
    DIRECTION OUTPUT ;
    USE SIGNAL ;
    PORT
      LAYER M5 ;
        RECT  27.984 97.116 28.008 97.2 ;
    END
  END dout[334]
  PIN dout[335]
    DIRECTION OUTPUT ;
    USE SIGNAL ;
    PORT
      LAYER M5 ;
        RECT  28.08 97.116 28.104 97.2 ;
    END
  END dout[335]
  PIN dout[336]
    DIRECTION OUTPUT ;
    USE SIGNAL ;
    PORT
      LAYER M5 ;
        RECT  28.176 97.116 28.2 97.2 ;
    END
  END dout[336]
  PIN dout[337]
    DIRECTION OUTPUT ;
    USE SIGNAL ;
    PORT
      LAYER M5 ;
        RECT  28.272 97.116 28.296 97.2 ;
    END
  END dout[337]
  PIN dout[338]
    DIRECTION OUTPUT ;
    USE SIGNAL ;
    PORT
      LAYER M5 ;
        RECT  28.368 97.116 28.392 97.2 ;
    END
  END dout[338]
  PIN dout[339]
    DIRECTION OUTPUT ;
    USE SIGNAL ;
    PORT
      LAYER M5 ;
        RECT  28.464 97.116 28.488 97.2 ;
    END
  END dout[339]
  PIN dout[33]
    DIRECTION OUTPUT ;
    USE SIGNAL ;
    PORT
      LAYER M5 ;
        RECT  45.936 97.116 45.96 97.2 ;
    END
  END dout[33]
  PIN dout[340]
    DIRECTION OUTPUT ;
    USE SIGNAL ;
    PORT
      LAYER M5 ;
        RECT  28.56 97.116 28.584 97.2 ;
    END
  END dout[340]
  PIN dout[341]
    DIRECTION OUTPUT ;
    USE SIGNAL ;
    PORT
      LAYER M5 ;
        RECT  28.656 97.116 28.68 97.2 ;
    END
  END dout[341]
  PIN dout[342]
    DIRECTION OUTPUT ;
    USE SIGNAL ;
    PORT
      LAYER M5 ;
        RECT  28.752 97.116 28.776 97.2 ;
    END
  END dout[342]
  PIN dout[343]
    DIRECTION OUTPUT ;
    USE SIGNAL ;
    PORT
      LAYER M5 ;
        RECT  28.848 97.116 28.872 97.2 ;
    END
  END dout[343]
  PIN dout[344]
    DIRECTION OUTPUT ;
    USE SIGNAL ;
    PORT
      LAYER M5 ;
        RECT  28.944 97.116 28.968 97.2 ;
    END
  END dout[344]
  PIN dout[345]
    DIRECTION OUTPUT ;
    USE SIGNAL ;
    PORT
      LAYER M5 ;
        RECT  29.04 97.116 29.064 97.2 ;
    END
  END dout[345]
  PIN dout[346]
    DIRECTION OUTPUT ;
    USE SIGNAL ;
    PORT
      LAYER M5 ;
        RECT  29.136 97.116 29.16 97.2 ;
    END
  END dout[346]
  PIN dout[347]
    DIRECTION OUTPUT ;
    USE SIGNAL ;
    PORT
      LAYER M5 ;
        RECT  29.232 97.116 29.256 97.2 ;
    END
  END dout[347]
  PIN dout[348]
    DIRECTION OUTPUT ;
    USE SIGNAL ;
    PORT
      LAYER M5 ;
        RECT  29.328 97.116 29.352 97.2 ;
    END
  END dout[348]
  PIN dout[349]
    DIRECTION OUTPUT ;
    USE SIGNAL ;
    PORT
      LAYER M5 ;
        RECT  29.424 97.116 29.448 97.2 ;
    END
  END dout[349]
  PIN dout[34]
    DIRECTION OUTPUT ;
    USE SIGNAL ;
    PORT
      LAYER M5 ;
        RECT  46.032 97.116 46.056 97.2 ;
    END
  END dout[34]
  PIN dout[350]
    DIRECTION OUTPUT ;
    USE SIGNAL ;
    PORT
      LAYER M5 ;
        RECT  29.52 97.116 29.544 97.2 ;
    END
  END dout[350]
  PIN dout[351]
    DIRECTION OUTPUT ;
    USE SIGNAL ;
    PORT
      LAYER M5 ;
        RECT  29.616 97.116 29.64 97.2 ;
    END
  END dout[351]
  PIN dout[352]
    DIRECTION OUTPUT ;
    USE SIGNAL ;
    PORT
      LAYER M5 ;
        RECT  7.44 97.116 7.464 97.2 ;
    END
  END dout[352]
  PIN dout[353]
    DIRECTION OUTPUT ;
    USE SIGNAL ;
    PORT
      LAYER M5 ;
        RECT  7.536 97.116 7.56 97.2 ;
    END
  END dout[353]
  PIN dout[354]
    DIRECTION OUTPUT ;
    USE SIGNAL ;
    PORT
      LAYER M5 ;
        RECT  7.632 97.116 7.656 97.2 ;
    END
  END dout[354]
  PIN dout[355]
    DIRECTION OUTPUT ;
    USE SIGNAL ;
    PORT
      LAYER M5 ;
        RECT  7.728 97.116 7.752 97.2 ;
    END
  END dout[355]
  PIN dout[356]
    DIRECTION OUTPUT ;
    USE SIGNAL ;
    PORT
      LAYER M5 ;
        RECT  7.824 97.116 7.848 97.2 ;
    END
  END dout[356]
  PIN dout[357]
    DIRECTION OUTPUT ;
    USE SIGNAL ;
    PORT
      LAYER M5 ;
        RECT  7.92 97.116 7.944 97.2 ;
    END
  END dout[357]
  PIN dout[358]
    DIRECTION OUTPUT ;
    USE SIGNAL ;
    PORT
      LAYER M5 ;
        RECT  8.016 97.116 8.04 97.2 ;
    END
  END dout[358]
  PIN dout[359]
    DIRECTION OUTPUT ;
    USE SIGNAL ;
    PORT
      LAYER M5 ;
        RECT  8.112 97.116 8.136 97.2 ;
    END
  END dout[359]
  PIN dout[35]
    DIRECTION OUTPUT ;
    USE SIGNAL ;
    PORT
      LAYER M5 ;
        RECT  46.128 97.116 46.152 97.2 ;
    END
  END dout[35]
  PIN dout[360]
    DIRECTION OUTPUT ;
    USE SIGNAL ;
    PORT
      LAYER M5 ;
        RECT  8.208 97.116 8.232 97.2 ;
    END
  END dout[360]
  PIN dout[361]
    DIRECTION OUTPUT ;
    USE SIGNAL ;
    PORT
      LAYER M5 ;
        RECT  8.304 97.116 8.328 97.2 ;
    END
  END dout[361]
  PIN dout[362]
    DIRECTION OUTPUT ;
    USE SIGNAL ;
    PORT
      LAYER M5 ;
        RECT  8.4 97.116 8.424 97.2 ;
    END
  END dout[362]
  PIN dout[363]
    DIRECTION OUTPUT ;
    USE SIGNAL ;
    PORT
      LAYER M5 ;
        RECT  8.496 97.116 8.52 97.2 ;
    END
  END dout[363]
  PIN dout[364]
    DIRECTION OUTPUT ;
    USE SIGNAL ;
    PORT
      LAYER M5 ;
        RECT  8.592 97.116 8.616 97.2 ;
    END
  END dout[364]
  PIN dout[365]
    DIRECTION OUTPUT ;
    USE SIGNAL ;
    PORT
      LAYER M5 ;
        RECT  8.688 97.116 8.712 97.2 ;
    END
  END dout[365]
  PIN dout[366]
    DIRECTION OUTPUT ;
    USE SIGNAL ;
    PORT
      LAYER M5 ;
        RECT  8.784 97.116 8.808 97.2 ;
    END
  END dout[366]
  PIN dout[367]
    DIRECTION OUTPUT ;
    USE SIGNAL ;
    PORT
      LAYER M5 ;
        RECT  8.88 97.116 8.904 97.2 ;
    END
  END dout[367]
  PIN dout[368]
    DIRECTION OUTPUT ;
    USE SIGNAL ;
    PORT
      LAYER M5 ;
        RECT  8.976 97.116 9 97.2 ;
    END
  END dout[368]
  PIN dout[369]
    DIRECTION OUTPUT ;
    USE SIGNAL ;
    PORT
      LAYER M5 ;
        RECT  9.072 97.116 9.096 97.2 ;
    END
  END dout[369]
  PIN dout[36]
    DIRECTION OUTPUT ;
    USE SIGNAL ;
    PORT
      LAYER M5 ;
        RECT  46.224 97.116 46.248 97.2 ;
    END
  END dout[36]
  PIN dout[370]
    DIRECTION OUTPUT ;
    USE SIGNAL ;
    PORT
      LAYER M5 ;
        RECT  9.168 97.116 9.192 97.2 ;
    END
  END dout[370]
  PIN dout[371]
    DIRECTION OUTPUT ;
    USE SIGNAL ;
    PORT
      LAYER M5 ;
        RECT  9.264 97.116 9.288 97.2 ;
    END
  END dout[371]
  PIN dout[372]
    DIRECTION OUTPUT ;
    USE SIGNAL ;
    PORT
      LAYER M5 ;
        RECT  9.36 97.116 9.384 97.2 ;
    END
  END dout[372]
  PIN dout[373]
    DIRECTION OUTPUT ;
    USE SIGNAL ;
    PORT
      LAYER M5 ;
        RECT  9.456 97.116 9.48 97.2 ;
    END
  END dout[373]
  PIN dout[374]
    DIRECTION OUTPUT ;
    USE SIGNAL ;
    PORT
      LAYER M5 ;
        RECT  9.552 97.116 9.576 97.2 ;
    END
  END dout[374]
  PIN dout[375]
    DIRECTION OUTPUT ;
    USE SIGNAL ;
    PORT
      LAYER M5 ;
        RECT  9.648 97.116 9.672 97.2 ;
    END
  END dout[375]
  PIN dout[376]
    DIRECTION OUTPUT ;
    USE SIGNAL ;
    PORT
      LAYER M5 ;
        RECT  9.744 97.116 9.768 97.2 ;
    END
  END dout[376]
  PIN dout[377]
    DIRECTION OUTPUT ;
    USE SIGNAL ;
    PORT
      LAYER M5 ;
        RECT  9.84 97.116 9.864 97.2 ;
    END
  END dout[377]
  PIN dout[378]
    DIRECTION OUTPUT ;
    USE SIGNAL ;
    PORT
      LAYER M5 ;
        RECT  9.936 97.116 9.96 97.2 ;
    END
  END dout[378]
  PIN dout[379]
    DIRECTION OUTPUT ;
    USE SIGNAL ;
    PORT
      LAYER M5 ;
        RECT  10.032 97.116 10.056 97.2 ;
    END
  END dout[379]
  PIN dout[37]
    DIRECTION OUTPUT ;
    USE SIGNAL ;
    PORT
      LAYER M5 ;
        RECT  46.32 97.116 46.344 97.2 ;
    END
  END dout[37]
  PIN dout[380]
    DIRECTION OUTPUT ;
    USE SIGNAL ;
    PORT
      LAYER M5 ;
        RECT  10.128 97.116 10.152 97.2 ;
    END
  END dout[380]
  PIN dout[381]
    DIRECTION OUTPUT ;
    USE SIGNAL ;
    PORT
      LAYER M5 ;
        RECT  10.224 97.116 10.248 97.2 ;
    END
  END dout[381]
  PIN dout[382]
    DIRECTION OUTPUT ;
    USE SIGNAL ;
    PORT
      LAYER M5 ;
        RECT  10.32 97.116 10.344 97.2 ;
    END
  END dout[382]
  PIN dout[383]
    DIRECTION OUTPUT ;
    USE SIGNAL ;
    PORT
      LAYER M5 ;
        RECT  10.416 97.116 10.44 97.2 ;
    END
  END dout[383]
  PIN dout[384]
    DIRECTION OUTPUT ;
    USE SIGNAL ;
    PORT
      LAYER M5 ;
        RECT  65.04 97.116 65.064 97.2 ;
    END
  END dout[384]
  PIN dout[385]
    DIRECTION OUTPUT ;
    USE SIGNAL ;
    PORT
      LAYER M5 ;
        RECT  65.136 97.116 65.16 97.2 ;
    END
  END dout[385]
  PIN dout[386]
    DIRECTION OUTPUT ;
    USE SIGNAL ;
    PORT
      LAYER M5 ;
        RECT  65.232 97.116 65.256 97.2 ;
    END
  END dout[386]
  PIN dout[387]
    DIRECTION OUTPUT ;
    USE SIGNAL ;
    PORT
      LAYER M5 ;
        RECT  65.328 97.116 65.352 97.2 ;
    END
  END dout[387]
  PIN dout[388]
    DIRECTION OUTPUT ;
    USE SIGNAL ;
    PORT
      LAYER M5 ;
        RECT  65.424 97.116 65.448 97.2 ;
    END
  END dout[388]
  PIN dout[389]
    DIRECTION OUTPUT ;
    USE SIGNAL ;
    PORT
      LAYER M5 ;
        RECT  65.52 97.116 65.544 97.2 ;
    END
  END dout[389]
  PIN dout[38]
    DIRECTION OUTPUT ;
    USE SIGNAL ;
    PORT
      LAYER M5 ;
        RECT  46.416 97.116 46.44 97.2 ;
    END
  END dout[38]
  PIN dout[390]
    DIRECTION OUTPUT ;
    USE SIGNAL ;
    PORT
      LAYER M5 ;
        RECT  65.616 97.116 65.64 97.2 ;
    END
  END dout[390]
  PIN dout[391]
    DIRECTION OUTPUT ;
    USE SIGNAL ;
    PORT
      LAYER M5 ;
        RECT  65.712 97.116 65.736 97.2 ;
    END
  END dout[391]
  PIN dout[392]
    DIRECTION OUTPUT ;
    USE SIGNAL ;
    PORT
      LAYER M5 ;
        RECT  65.808 97.116 65.832 97.2 ;
    END
  END dout[392]
  PIN dout[393]
    DIRECTION OUTPUT ;
    USE SIGNAL ;
    PORT
      LAYER M5 ;
        RECT  65.904 97.116 65.928 97.2 ;
    END
  END dout[393]
  PIN dout[394]
    DIRECTION OUTPUT ;
    USE SIGNAL ;
    PORT
      LAYER M5 ;
        RECT  66 97.116 66.024 97.2 ;
    END
  END dout[394]
  PIN dout[395]
    DIRECTION OUTPUT ;
    USE SIGNAL ;
    PORT
      LAYER M5 ;
        RECT  66.096 97.116 66.12 97.2 ;
    END
  END dout[395]
  PIN dout[396]
    DIRECTION OUTPUT ;
    USE SIGNAL ;
    PORT
      LAYER M5 ;
        RECT  66.192 97.116 66.216 97.2 ;
    END
  END dout[396]
  PIN dout[397]
    DIRECTION OUTPUT ;
    USE SIGNAL ;
    PORT
      LAYER M5 ;
        RECT  66.288 97.116 66.312 97.2 ;
    END
  END dout[397]
  PIN dout[398]
    DIRECTION OUTPUT ;
    USE SIGNAL ;
    PORT
      LAYER M5 ;
        RECT  66.384 97.116 66.408 97.2 ;
    END
  END dout[398]
  PIN dout[399]
    DIRECTION OUTPUT ;
    USE SIGNAL ;
    PORT
      LAYER M5 ;
        RECT  66.48 97.116 66.504 97.2 ;
    END
  END dout[399]
  PIN dout[39]
    DIRECTION OUTPUT ;
    USE SIGNAL ;
    PORT
      LAYER M5 ;
        RECT  46.512 97.116 46.536 97.2 ;
    END
  END dout[39]
  PIN dout[3]
    DIRECTION OUTPUT ;
    USE SIGNAL ;
    PORT
      LAYER M5 ;
        RECT  59.184 97.116 59.208 97.2 ;
    END
  END dout[3]
  PIN dout[400]
    DIRECTION OUTPUT ;
    USE SIGNAL ;
    PORT
      LAYER M5 ;
        RECT  66.576 97.116 66.6 97.2 ;
    END
  END dout[400]
  PIN dout[401]
    DIRECTION OUTPUT ;
    USE SIGNAL ;
    PORT
      LAYER M5 ;
        RECT  66.672 97.116 66.696 97.2 ;
    END
  END dout[401]
  PIN dout[402]
    DIRECTION OUTPUT ;
    USE SIGNAL ;
    PORT
      LAYER M5 ;
        RECT  66.768 97.116 66.792 97.2 ;
    END
  END dout[402]
  PIN dout[403]
    DIRECTION OUTPUT ;
    USE SIGNAL ;
    PORT
      LAYER M5 ;
        RECT  66.864 97.116 66.888 97.2 ;
    END
  END dout[403]
  PIN dout[404]
    DIRECTION OUTPUT ;
    USE SIGNAL ;
    PORT
      LAYER M5 ;
        RECT  66.96 97.116 66.984 97.2 ;
    END
  END dout[404]
  PIN dout[405]
    DIRECTION OUTPUT ;
    USE SIGNAL ;
    PORT
      LAYER M5 ;
        RECT  67.056 97.116 67.08 97.2 ;
    END
  END dout[405]
  PIN dout[406]
    DIRECTION OUTPUT ;
    USE SIGNAL ;
    PORT
      LAYER M5 ;
        RECT  67.152 97.116 67.176 97.2 ;
    END
  END dout[406]
  PIN dout[407]
    DIRECTION OUTPUT ;
    USE SIGNAL ;
    PORT
      LAYER M5 ;
        RECT  67.248 97.116 67.272 97.2 ;
    END
  END dout[407]
  PIN dout[408]
    DIRECTION OUTPUT ;
    USE SIGNAL ;
    PORT
      LAYER M5 ;
        RECT  67.344 97.116 67.368 97.2 ;
    END
  END dout[408]
  PIN dout[409]
    DIRECTION OUTPUT ;
    USE SIGNAL ;
    PORT
      LAYER M5 ;
        RECT  67.44 97.116 67.464 97.2 ;
    END
  END dout[409]
  PIN dout[40]
    DIRECTION OUTPUT ;
    USE SIGNAL ;
    PORT
      LAYER M5 ;
        RECT  46.608 97.116 46.632 97.2 ;
    END
  END dout[40]
  PIN dout[410]
    DIRECTION OUTPUT ;
    USE SIGNAL ;
    PORT
      LAYER M5 ;
        RECT  67.536 97.116 67.56 97.2 ;
    END
  END dout[410]
  PIN dout[411]
    DIRECTION OUTPUT ;
    USE SIGNAL ;
    PORT
      LAYER M5 ;
        RECT  67.632 97.116 67.656 97.2 ;
    END
  END dout[411]
  PIN dout[412]
    DIRECTION OUTPUT ;
    USE SIGNAL ;
    PORT
      LAYER M5 ;
        RECT  67.728 97.116 67.752 97.2 ;
    END
  END dout[412]
  PIN dout[413]
    DIRECTION OUTPUT ;
    USE SIGNAL ;
    PORT
      LAYER M5 ;
        RECT  67.824 97.116 67.848 97.2 ;
    END
  END dout[413]
  PIN dout[414]
    DIRECTION OUTPUT ;
    USE SIGNAL ;
    PORT
      LAYER M5 ;
        RECT  67.92 97.116 67.944 97.2 ;
    END
  END dout[414]
  PIN dout[415]
    DIRECTION OUTPUT ;
    USE SIGNAL ;
    PORT
      LAYER M5 ;
        RECT  68.016 97.116 68.04 97.2 ;
    END
  END dout[415]
  PIN dout[416]
    DIRECTION OUTPUT ;
    USE SIGNAL ;
    PORT
      LAYER M5 ;
        RECT  68.112 97.116 68.136 97.2 ;
    END
  END dout[416]
  PIN dout[417]
    DIRECTION OUTPUT ;
    USE SIGNAL ;
    PORT
      LAYER M5 ;
        RECT  68.208 97.116 68.232 97.2 ;
    END
  END dout[417]
  PIN dout[418]
    DIRECTION OUTPUT ;
    USE SIGNAL ;
    PORT
      LAYER M5 ;
        RECT  68.304 97.116 68.328 97.2 ;
    END
  END dout[418]
  PIN dout[419]
    DIRECTION OUTPUT ;
    USE SIGNAL ;
    PORT
      LAYER M5 ;
        RECT  68.4 97.116 68.424 97.2 ;
    END
  END dout[419]
  PIN dout[41]
    DIRECTION OUTPUT ;
    USE SIGNAL ;
    PORT
      LAYER M5 ;
        RECT  46.704 97.116 46.728 97.2 ;
    END
  END dout[41]
  PIN dout[420]
    DIRECTION OUTPUT ;
    USE SIGNAL ;
    PORT
      LAYER M5 ;
        RECT  68.496 97.116 68.52 97.2 ;
    END
  END dout[420]
  PIN dout[421]
    DIRECTION OUTPUT ;
    USE SIGNAL ;
    PORT
      LAYER M5 ;
        RECT  68.592 97.116 68.616 97.2 ;
    END
  END dout[421]
  PIN dout[422]
    DIRECTION OUTPUT ;
    USE SIGNAL ;
    PORT
      LAYER M5 ;
        RECT  68.688 97.116 68.712 97.2 ;
    END
  END dout[422]
  PIN dout[423]
    DIRECTION OUTPUT ;
    USE SIGNAL ;
    PORT
      LAYER M5 ;
        RECT  68.784 97.116 68.808 97.2 ;
    END
  END dout[423]
  PIN dout[424]
    DIRECTION OUTPUT ;
    USE SIGNAL ;
    PORT
      LAYER M5 ;
        RECT  68.88 97.116 68.904 97.2 ;
    END
  END dout[424]
  PIN dout[425]
    DIRECTION OUTPUT ;
    USE SIGNAL ;
    PORT
      LAYER M5 ;
        RECT  68.976 97.116 69 97.2 ;
    END
  END dout[425]
  PIN dout[426]
    DIRECTION OUTPUT ;
    USE SIGNAL ;
    PORT
      LAYER M5 ;
        RECT  69.072 97.116 69.096 97.2 ;
    END
  END dout[426]
  PIN dout[427]
    DIRECTION OUTPUT ;
    USE SIGNAL ;
    PORT
      LAYER M5 ;
        RECT  69.168 97.116 69.192 97.2 ;
    END
  END dout[427]
  PIN dout[428]
    DIRECTION OUTPUT ;
    USE SIGNAL ;
    PORT
      LAYER M5 ;
        RECT  69.264 97.116 69.288 97.2 ;
    END
  END dout[428]
  PIN dout[429]
    DIRECTION OUTPUT ;
    USE SIGNAL ;
    PORT
      LAYER M5 ;
        RECT  69.36 97.116 69.384 97.2 ;
    END
  END dout[429]
  PIN dout[42]
    DIRECTION OUTPUT ;
    USE SIGNAL ;
    PORT
      LAYER M5 ;
        RECT  46.8 97.116 46.824 97.2 ;
    END
  END dout[42]
  PIN dout[430]
    DIRECTION OUTPUT ;
    USE SIGNAL ;
    PORT
      LAYER M5 ;
        RECT  69.456 97.116 69.48 97.2 ;
    END
  END dout[430]
  PIN dout[431]
    DIRECTION OUTPUT ;
    USE SIGNAL ;
    PORT
      LAYER M5 ;
        RECT  69.552 97.116 69.576 97.2 ;
    END
  END dout[431]
  PIN dout[432]
    DIRECTION OUTPUT ;
    USE SIGNAL ;
    PORT
      LAYER M5 ;
        RECT  69.648 97.116 69.672 97.2 ;
    END
  END dout[432]
  PIN dout[433]
    DIRECTION OUTPUT ;
    USE SIGNAL ;
    PORT
      LAYER M5 ;
        RECT  69.744 97.116 69.768 97.2 ;
    END
  END dout[433]
  PIN dout[434]
    DIRECTION OUTPUT ;
    USE SIGNAL ;
    PORT
      LAYER M5 ;
        RECT  69.84 97.116 69.864 97.2 ;
    END
  END dout[434]
  PIN dout[435]
    DIRECTION OUTPUT ;
    USE SIGNAL ;
    PORT
      LAYER M5 ;
        RECT  69.936 97.116 69.96 97.2 ;
    END
  END dout[435]
  PIN dout[436]
    DIRECTION OUTPUT ;
    USE SIGNAL ;
    PORT
      LAYER M5 ;
        RECT  70.032 97.116 70.056 97.2 ;
    END
  END dout[436]
  PIN dout[437]
    DIRECTION OUTPUT ;
    USE SIGNAL ;
    PORT
      LAYER M5 ;
        RECT  70.128 97.116 70.152 97.2 ;
    END
  END dout[437]
  PIN dout[438]
    DIRECTION OUTPUT ;
    USE SIGNAL ;
    PORT
      LAYER M5 ;
        RECT  70.224 97.116 70.248 97.2 ;
    END
  END dout[438]
  PIN dout[439]
    DIRECTION OUTPUT ;
    USE SIGNAL ;
    PORT
      LAYER M5 ;
        RECT  70.32 97.116 70.344 97.2 ;
    END
  END dout[439]
  PIN dout[43]
    DIRECTION OUTPUT ;
    USE SIGNAL ;
    PORT
      LAYER M5 ;
        RECT  46.896 97.116 46.92 97.2 ;
    END
  END dout[43]
  PIN dout[440]
    DIRECTION OUTPUT ;
    USE SIGNAL ;
    PORT
      LAYER M5 ;
        RECT  70.416 97.116 70.44 97.2 ;
    END
  END dout[440]
  PIN dout[441]
    DIRECTION OUTPUT ;
    USE SIGNAL ;
    PORT
      LAYER M5 ;
        RECT  70.512 97.116 70.536 97.2 ;
    END
  END dout[441]
  PIN dout[442]
    DIRECTION OUTPUT ;
    USE SIGNAL ;
    PORT
      LAYER M5 ;
        RECT  70.608 97.116 70.632 97.2 ;
    END
  END dout[442]
  PIN dout[443]
    DIRECTION OUTPUT ;
    USE SIGNAL ;
    PORT
      LAYER M5 ;
        RECT  70.704 97.116 70.728 97.2 ;
    END
  END dout[443]
  PIN dout[444]
    DIRECTION OUTPUT ;
    USE SIGNAL ;
    PORT
      LAYER M5 ;
        RECT  70.8 97.116 70.824 97.2 ;
    END
  END dout[444]
  PIN dout[445]
    DIRECTION OUTPUT ;
    USE SIGNAL ;
    PORT
      LAYER M5 ;
        RECT  70.896 97.116 70.92 97.2 ;
    END
  END dout[445]
  PIN dout[446]
    DIRECTION OUTPUT ;
    USE SIGNAL ;
    PORT
      LAYER M5 ;
        RECT  70.992 97.116 71.016 97.2 ;
    END
  END dout[446]
  PIN dout[447]
    DIRECTION OUTPUT ;
    USE SIGNAL ;
    PORT
      LAYER M5 ;
        RECT  71.088 97.116 71.112 97.2 ;
    END
  END dout[447]
  PIN dout[448]
    DIRECTION OUTPUT ;
    USE SIGNAL ;
    PORT
      LAYER M5 ;
        RECT  55.056 97.116 55.08 97.2 ;
    END
  END dout[448]
  PIN dout[449]
    DIRECTION OUTPUT ;
    USE SIGNAL ;
    PORT
      LAYER M5 ;
        RECT  55.152 97.116 55.176 97.2 ;
    END
  END dout[449]
  PIN dout[44]
    DIRECTION OUTPUT ;
    USE SIGNAL ;
    PORT
      LAYER M5 ;
        RECT  46.992 97.116 47.016 97.2 ;
    END
  END dout[44]
  PIN dout[450]
    DIRECTION OUTPUT ;
    USE SIGNAL ;
    PORT
      LAYER M5 ;
        RECT  55.248 97.116 55.272 97.2 ;
    END
  END dout[450]
  PIN dout[451]
    DIRECTION OUTPUT ;
    USE SIGNAL ;
    PORT
      LAYER M5 ;
        RECT  55.344 97.116 55.368 97.2 ;
    END
  END dout[451]
  PIN dout[452]
    DIRECTION OUTPUT ;
    USE SIGNAL ;
    PORT
      LAYER M5 ;
        RECT  55.44 97.116 55.464 97.2 ;
    END
  END dout[452]
  PIN dout[453]
    DIRECTION OUTPUT ;
    USE SIGNAL ;
    PORT
      LAYER M5 ;
        RECT  55.536 97.116 55.56 97.2 ;
    END
  END dout[453]
  PIN dout[454]
    DIRECTION OUTPUT ;
    USE SIGNAL ;
    PORT
      LAYER M5 ;
        RECT  55.632 97.116 55.656 97.2 ;
    END
  END dout[454]
  PIN dout[455]
    DIRECTION OUTPUT ;
    USE SIGNAL ;
    PORT
      LAYER M5 ;
        RECT  55.728 97.116 55.752 97.2 ;
    END
  END dout[455]
  PIN dout[456]
    DIRECTION OUTPUT ;
    USE SIGNAL ;
    PORT
      LAYER M5 ;
        RECT  55.824 97.116 55.848 97.2 ;
    END
  END dout[456]
  PIN dout[457]
    DIRECTION OUTPUT ;
    USE SIGNAL ;
    PORT
      LAYER M5 ;
        RECT  55.92 97.116 55.944 97.2 ;
    END
  END dout[457]
  PIN dout[458]
    DIRECTION OUTPUT ;
    USE SIGNAL ;
    PORT
      LAYER M5 ;
        RECT  56.016 97.116 56.04 97.2 ;
    END
  END dout[458]
  PIN dout[459]
    DIRECTION OUTPUT ;
    USE SIGNAL ;
    PORT
      LAYER M5 ;
        RECT  56.112 97.116 56.136 97.2 ;
    END
  END dout[459]
  PIN dout[45]
    DIRECTION OUTPUT ;
    USE SIGNAL ;
    PORT
      LAYER M5 ;
        RECT  47.088 97.116 47.112 97.2 ;
    END
  END dout[45]
  PIN dout[460]
    DIRECTION OUTPUT ;
    USE SIGNAL ;
    PORT
      LAYER M5 ;
        RECT  56.208 97.116 56.232 97.2 ;
    END
  END dout[460]
  PIN dout[461]
    DIRECTION OUTPUT ;
    USE SIGNAL ;
    PORT
      LAYER M5 ;
        RECT  56.304 97.116 56.328 97.2 ;
    END
  END dout[461]
  PIN dout[462]
    DIRECTION OUTPUT ;
    USE SIGNAL ;
    PORT
      LAYER M5 ;
        RECT  56.4 97.116 56.424 97.2 ;
    END
  END dout[462]
  PIN dout[463]
    DIRECTION OUTPUT ;
    USE SIGNAL ;
    PORT
      LAYER M5 ;
        RECT  56.496 97.116 56.52 97.2 ;
    END
  END dout[463]
  PIN dout[464]
    DIRECTION OUTPUT ;
    USE SIGNAL ;
    PORT
      LAYER M5 ;
        RECT  56.592 97.116 56.616 97.2 ;
    END
  END dout[464]
  PIN dout[465]
    DIRECTION OUTPUT ;
    USE SIGNAL ;
    PORT
      LAYER M5 ;
        RECT  56.688 97.116 56.712 97.2 ;
    END
  END dout[465]
  PIN dout[466]
    DIRECTION OUTPUT ;
    USE SIGNAL ;
    PORT
      LAYER M5 ;
        RECT  56.784 97.116 56.808 97.2 ;
    END
  END dout[466]
  PIN dout[467]
    DIRECTION OUTPUT ;
    USE SIGNAL ;
    PORT
      LAYER M5 ;
        RECT  56.88 97.116 56.904 97.2 ;
    END
  END dout[467]
  PIN dout[468]
    DIRECTION OUTPUT ;
    USE SIGNAL ;
    PORT
      LAYER M5 ;
        RECT  56.976 97.116 57 97.2 ;
    END
  END dout[468]
  PIN dout[469]
    DIRECTION OUTPUT ;
    USE SIGNAL ;
    PORT
      LAYER M5 ;
        RECT  57.072 97.116 57.096 97.2 ;
    END
  END dout[469]
  PIN dout[46]
    DIRECTION OUTPUT ;
    USE SIGNAL ;
    PORT
      LAYER M5 ;
        RECT  47.184 97.116 47.208 97.2 ;
    END
  END dout[46]
  PIN dout[470]
    DIRECTION OUTPUT ;
    USE SIGNAL ;
    PORT
      LAYER M5 ;
        RECT  57.168 97.116 57.192 97.2 ;
    END
  END dout[470]
  PIN dout[471]
    DIRECTION OUTPUT ;
    USE SIGNAL ;
    PORT
      LAYER M5 ;
        RECT  57.264 97.116 57.288 97.2 ;
    END
  END dout[471]
  PIN dout[472]
    DIRECTION OUTPUT ;
    USE SIGNAL ;
    PORT
      LAYER M5 ;
        RECT  57.36 97.116 57.384 97.2 ;
    END
  END dout[472]
  PIN dout[473]
    DIRECTION OUTPUT ;
    USE SIGNAL ;
    PORT
      LAYER M5 ;
        RECT  57.456 97.116 57.48 97.2 ;
    END
  END dout[473]
  PIN dout[474]
    DIRECTION OUTPUT ;
    USE SIGNAL ;
    PORT
      LAYER M5 ;
        RECT  57.552 97.116 57.576 97.2 ;
    END
  END dout[474]
  PIN dout[475]
    DIRECTION OUTPUT ;
    USE SIGNAL ;
    PORT
      LAYER M5 ;
        RECT  57.648 97.116 57.672 97.2 ;
    END
  END dout[475]
  PIN dout[476]
    DIRECTION OUTPUT ;
    USE SIGNAL ;
    PORT
      LAYER M5 ;
        RECT  57.744 97.116 57.768 97.2 ;
    END
  END dout[476]
  PIN dout[477]
    DIRECTION OUTPUT ;
    USE SIGNAL ;
    PORT
      LAYER M5 ;
        RECT  57.84 97.116 57.864 97.2 ;
    END
  END dout[477]
  PIN dout[478]
    DIRECTION OUTPUT ;
    USE SIGNAL ;
    PORT
      LAYER M5 ;
        RECT  57.936 97.116 57.96 97.2 ;
    END
  END dout[478]
  PIN dout[479]
    DIRECTION OUTPUT ;
    USE SIGNAL ;
    PORT
      LAYER M5 ;
        RECT  58.032 97.116 58.056 97.2 ;
    END
  END dout[479]
  PIN dout[47]
    DIRECTION OUTPUT ;
    USE SIGNAL ;
    PORT
      LAYER M5 ;
        RECT  47.28 97.116 47.304 97.2 ;
    END
  END dout[47]
  PIN dout[480]
    DIRECTION OUTPUT ;
    USE SIGNAL ;
    PORT
      LAYER M5 ;
        RECT  48.912 97.116 48.936 97.2 ;
    END
  END dout[480]
  PIN dout[481]
    DIRECTION OUTPUT ;
    USE SIGNAL ;
    PORT
      LAYER M5 ;
        RECT  49.008 97.116 49.032 97.2 ;
    END
  END dout[481]
  PIN dout[482]
    DIRECTION OUTPUT ;
    USE SIGNAL ;
    PORT
      LAYER M5 ;
        RECT  49.104 97.116 49.128 97.2 ;
    END
  END dout[482]
  PIN dout[483]
    DIRECTION OUTPUT ;
    USE SIGNAL ;
    PORT
      LAYER M5 ;
        RECT  49.2 97.116 49.224 97.2 ;
    END
  END dout[483]
  PIN dout[484]
    DIRECTION OUTPUT ;
    USE SIGNAL ;
    PORT
      LAYER M5 ;
        RECT  49.296 97.116 49.32 97.2 ;
    END
  END dout[484]
  PIN dout[485]
    DIRECTION OUTPUT ;
    USE SIGNAL ;
    PORT
      LAYER M5 ;
        RECT  49.392 97.116 49.416 97.2 ;
    END
  END dout[485]
  PIN dout[486]
    DIRECTION OUTPUT ;
    USE SIGNAL ;
    PORT
      LAYER M5 ;
        RECT  49.488 97.116 49.512 97.2 ;
    END
  END dout[486]
  PIN dout[487]
    DIRECTION OUTPUT ;
    USE SIGNAL ;
    PORT
      LAYER M5 ;
        RECT  49.584 97.116 49.608 97.2 ;
    END
  END dout[487]
  PIN dout[488]
    DIRECTION OUTPUT ;
    USE SIGNAL ;
    PORT
      LAYER M5 ;
        RECT  49.68 97.116 49.704 97.2 ;
    END
  END dout[488]
  PIN dout[489]
    DIRECTION OUTPUT ;
    USE SIGNAL ;
    PORT
      LAYER M5 ;
        RECT  49.776 97.116 49.8 97.2 ;
    END
  END dout[489]
  PIN dout[48]
    DIRECTION OUTPUT ;
    USE SIGNAL ;
    PORT
      LAYER M5 ;
        RECT  47.376 97.116 47.4 97.2 ;
    END
  END dout[48]
  PIN dout[490]
    DIRECTION OUTPUT ;
    USE SIGNAL ;
    PORT
      LAYER M5 ;
        RECT  49.872 97.116 49.896 97.2 ;
    END
  END dout[490]
  PIN dout[491]
    DIRECTION OUTPUT ;
    USE SIGNAL ;
    PORT
      LAYER M5 ;
        RECT  49.968 97.116 49.992 97.2 ;
    END
  END dout[491]
  PIN dout[492]
    DIRECTION OUTPUT ;
    USE SIGNAL ;
    PORT
      LAYER M5 ;
        RECT  50.064 97.116 50.088 97.2 ;
    END
  END dout[492]
  PIN dout[493]
    DIRECTION OUTPUT ;
    USE SIGNAL ;
    PORT
      LAYER M5 ;
        RECT  50.16 97.116 50.184 97.2 ;
    END
  END dout[493]
  PIN dout[494]
    DIRECTION OUTPUT ;
    USE SIGNAL ;
    PORT
      LAYER M5 ;
        RECT  50.256 97.116 50.28 97.2 ;
    END
  END dout[494]
  PIN dout[495]
    DIRECTION OUTPUT ;
    USE SIGNAL ;
    PORT
      LAYER M5 ;
        RECT  50.352 97.116 50.376 97.2 ;
    END
  END dout[495]
  PIN dout[496]
    DIRECTION OUTPUT ;
    USE SIGNAL ;
    PORT
      LAYER M5 ;
        RECT  50.448 97.116 50.472 97.2 ;
    END
  END dout[496]
  PIN dout[497]
    DIRECTION OUTPUT ;
    USE SIGNAL ;
    PORT
      LAYER M5 ;
        RECT  50.544 97.116 50.568 97.2 ;
    END
  END dout[497]
  PIN dout[498]
    DIRECTION OUTPUT ;
    USE SIGNAL ;
    PORT
      LAYER M5 ;
        RECT  50.64 97.116 50.664 97.2 ;
    END
  END dout[498]
  PIN dout[499]
    DIRECTION OUTPUT ;
    USE SIGNAL ;
    PORT
      LAYER M5 ;
        RECT  50.736 97.116 50.76 97.2 ;
    END
  END dout[499]
  PIN dout[49]
    DIRECTION OUTPUT ;
    USE SIGNAL ;
    PORT
      LAYER M5 ;
        RECT  47.472 97.116 47.496 97.2 ;
    END
  END dout[49]
  PIN dout[4]
    DIRECTION OUTPUT ;
    USE SIGNAL ;
    PORT
      LAYER M5 ;
        RECT  59.28 97.116 59.304 97.2 ;
    END
  END dout[4]
  PIN dout[500]
    DIRECTION OUTPUT ;
    USE SIGNAL ;
    PORT
      LAYER M5 ;
        RECT  50.832 97.116 50.856 97.2 ;
    END
  END dout[500]
  PIN dout[501]
    DIRECTION OUTPUT ;
    USE SIGNAL ;
    PORT
      LAYER M5 ;
        RECT  50.928 97.116 50.952 97.2 ;
    END
  END dout[501]
  PIN dout[502]
    DIRECTION OUTPUT ;
    USE SIGNAL ;
    PORT
      LAYER M5 ;
        RECT  51.024 97.116 51.048 97.2 ;
    END
  END dout[502]
  PIN dout[503]
    DIRECTION OUTPUT ;
    USE SIGNAL ;
    PORT
      LAYER M5 ;
        RECT  51.12 97.116 51.144 97.2 ;
    END
  END dout[503]
  PIN dout[504]
    DIRECTION OUTPUT ;
    USE SIGNAL ;
    PORT
      LAYER M5 ;
        RECT  51.216 97.116 51.24 97.2 ;
    END
  END dout[504]
  PIN dout[505]
    DIRECTION OUTPUT ;
    USE SIGNAL ;
    PORT
      LAYER M5 ;
        RECT  51.312 97.116 51.336 97.2 ;
    END
  END dout[505]
  PIN dout[506]
    DIRECTION OUTPUT ;
    USE SIGNAL ;
    PORT
      LAYER M5 ;
        RECT  51.408 97.116 51.432 97.2 ;
    END
  END dout[506]
  PIN dout[507]
    DIRECTION OUTPUT ;
    USE SIGNAL ;
    PORT
      LAYER M5 ;
        RECT  51.504 97.116 51.528 97.2 ;
    END
  END dout[507]
  PIN dout[508]
    DIRECTION OUTPUT ;
    USE SIGNAL ;
    PORT
      LAYER M5 ;
        RECT  51.6 97.116 51.624 97.2 ;
    END
  END dout[508]
  PIN dout[509]
    DIRECTION OUTPUT ;
    USE SIGNAL ;
    PORT
      LAYER M5 ;
        RECT  51.696 97.116 51.72 97.2 ;
    END
  END dout[509]
  PIN dout[50]
    DIRECTION OUTPUT ;
    USE SIGNAL ;
    PORT
      LAYER M5 ;
        RECT  47.568 97.116 47.592 97.2 ;
    END
  END dout[50]
  PIN dout[510]
    DIRECTION OUTPUT ;
    USE SIGNAL ;
    PORT
      LAYER M5 ;
        RECT  51.792 97.116 51.816 97.2 ;
    END
  END dout[510]
  PIN dout[511]
    DIRECTION OUTPUT ;
    USE SIGNAL ;
    PORT
      LAYER M5 ;
        RECT  51.888 97.116 51.912 97.2 ;
    END
  END dout[511]
  PIN dout[512]
    DIRECTION OUTPUT ;
    USE SIGNAL ;
    PORT
      LAYER M5 ;
        RECT  53.424 97.116 53.448 97.2 ;
    END
  END dout[512]
  PIN dout[513]
    DIRECTION OUTPUT ;
    USE SIGNAL ;
    PORT
      LAYER M5 ;
        RECT  53.52 97.116 53.544 97.2 ;
    END
  END dout[513]
  PIN dout[514]
    DIRECTION OUTPUT ;
    USE SIGNAL ;
    PORT
      LAYER M5 ;
        RECT  53.616 97.116 53.64 97.2 ;
    END
  END dout[514]
  PIN dout[515]
    DIRECTION OUTPUT ;
    USE SIGNAL ;
    PORT
      LAYER M5 ;
        RECT  53.712 97.116 53.736 97.2 ;
    END
  END dout[515]
  PIN dout[516]
    DIRECTION OUTPUT ;
    USE SIGNAL ;
    PORT
      LAYER M5 ;
        RECT  53.808 97.116 53.832 97.2 ;
    END
  END dout[516]
  PIN dout[517]
    DIRECTION OUTPUT ;
    USE SIGNAL ;
    PORT
      LAYER M5 ;
        RECT  53.904 97.116 53.928 97.2 ;
    END
  END dout[517]
  PIN dout[518]
    DIRECTION OUTPUT ;
    USE SIGNAL ;
    PORT
      LAYER M5 ;
        RECT  54 97.116 54.024 97.2 ;
    END
  END dout[518]
  PIN dout[519]
    DIRECTION OUTPUT ;
    USE SIGNAL ;
    PORT
      LAYER M5 ;
        RECT  54.096 97.116 54.12 97.2 ;
    END
  END dout[519]
  PIN dout[51]
    DIRECTION OUTPUT ;
    USE SIGNAL ;
    PORT
      LAYER M5 ;
        RECT  47.664 97.116 47.688 97.2 ;
    END
  END dout[51]
  PIN dout[520]
    DIRECTION OUTPUT ;
    USE SIGNAL ;
    PORT
      LAYER M5 ;
        RECT  54.192 97.116 54.216 97.2 ;
    END
  END dout[520]
  PIN dout[521]
    DIRECTION OUTPUT ;
    USE SIGNAL ;
    PORT
      LAYER M5 ;
        RECT  54.288 97.116 54.312 97.2 ;
    END
  END dout[521]
  PIN dout[522]
    DIRECTION OUTPUT ;
    USE SIGNAL ;
    PORT
      LAYER M5 ;
        RECT  54.384 97.116 54.408 97.2 ;
    END
  END dout[522]
  PIN dout[523]
    DIRECTION OUTPUT ;
    USE SIGNAL ;
    PORT
      LAYER M5 ;
        RECT  54.48 97.116 54.504 97.2 ;
    END
  END dout[523]
  PIN dout[524]
    DIRECTION OUTPUT ;
    USE SIGNAL ;
    PORT
      LAYER M5 ;
        RECT  54.576 97.116 54.6 97.2 ;
    END
  END dout[524]
  PIN dout[525]
    DIRECTION OUTPUT ;
    USE SIGNAL ;
    PORT
      LAYER M5 ;
        RECT  54.672 97.116 54.696 97.2 ;
    END
  END dout[525]
  PIN dout[526]
    DIRECTION OUTPUT ;
    USE SIGNAL ;
    PORT
      LAYER M5 ;
        RECT  54.768 97.116 54.792 97.2 ;
    END
  END dout[526]
  PIN dout[527]
    DIRECTION OUTPUT ;
    USE SIGNAL ;
    PORT
      LAYER M5 ;
        RECT  54.864 97.116 54.888 97.2 ;
    END
  END dout[527]
  PIN dout[52]
    DIRECTION OUTPUT ;
    USE SIGNAL ;
    PORT
      LAYER M5 ;
        RECT  47.76 97.116 47.784 97.2 ;
    END
  END dout[52]
  PIN dout[53]
    DIRECTION OUTPUT ;
    USE SIGNAL ;
    PORT
      LAYER M5 ;
        RECT  47.856 97.116 47.88 97.2 ;
    END
  END dout[53]
  PIN dout[54]
    DIRECTION OUTPUT ;
    USE SIGNAL ;
    PORT
      LAYER M5 ;
        RECT  47.952 97.116 47.976 97.2 ;
    END
  END dout[54]
  PIN dout[55]
    DIRECTION OUTPUT ;
    USE SIGNAL ;
    PORT
      LAYER M5 ;
        RECT  48.048 97.116 48.072 97.2 ;
    END
  END dout[55]
  PIN dout[56]
    DIRECTION OUTPUT ;
    USE SIGNAL ;
    PORT
      LAYER M5 ;
        RECT  48.144 97.116 48.168 97.2 ;
    END
  END dout[56]
  PIN dout[57]
    DIRECTION OUTPUT ;
    USE SIGNAL ;
    PORT
      LAYER M5 ;
        RECT  48.24 97.116 48.264 97.2 ;
    END
  END dout[57]
  PIN dout[58]
    DIRECTION OUTPUT ;
    USE SIGNAL ;
    PORT
      LAYER M5 ;
        RECT  48.336 97.116 48.36 97.2 ;
    END
  END dout[58]
  PIN dout[59]
    DIRECTION OUTPUT ;
    USE SIGNAL ;
    PORT
      LAYER M5 ;
        RECT  48.432 97.116 48.456 97.2 ;
    END
  END dout[59]
  PIN dout[5]
    DIRECTION OUTPUT ;
    USE SIGNAL ;
    PORT
      LAYER M5 ;
        RECT  59.376 97.116 59.4 97.2 ;
    END
  END dout[5]
  PIN dout[60]
    DIRECTION OUTPUT ;
    USE SIGNAL ;
    PORT
      LAYER M5 ;
        RECT  48.528 97.116 48.552 97.2 ;
    END
  END dout[60]
  PIN dout[61]
    DIRECTION OUTPUT ;
    USE SIGNAL ;
    PORT
      LAYER M5 ;
        RECT  48.624 97.116 48.648 97.2 ;
    END
  END dout[61]
  PIN dout[62]
    DIRECTION OUTPUT ;
    USE SIGNAL ;
    PORT
      LAYER M5 ;
        RECT  48.72 97.116 48.744 97.2 ;
    END
  END dout[62]
  PIN dout[63]
    DIRECTION OUTPUT ;
    USE SIGNAL ;
    PORT
      LAYER M5 ;
        RECT  48.816 97.116 48.84 97.2 ;
    END
  END dout[63]
  PIN dout[64]
    DIRECTION OUTPUT ;
    USE SIGNAL ;
    PORT
      LAYER M5 ;
        RECT  39.696 97.116 39.72 97.2 ;
    END
  END dout[64]
  PIN dout[65]
    DIRECTION OUTPUT ;
    USE SIGNAL ;
    PORT
      LAYER M5 ;
        RECT  39.792 97.116 39.816 97.2 ;
    END
  END dout[65]
  PIN dout[66]
    DIRECTION OUTPUT ;
    USE SIGNAL ;
    PORT
      LAYER M5 ;
        RECT  39.888 97.116 39.912 97.2 ;
    END
  END dout[66]
  PIN dout[67]
    DIRECTION OUTPUT ;
    USE SIGNAL ;
    PORT
      LAYER M5 ;
        RECT  39.984 97.116 40.008 97.2 ;
    END
  END dout[67]
  PIN dout[68]
    DIRECTION OUTPUT ;
    USE SIGNAL ;
    PORT
      LAYER M5 ;
        RECT  40.08 97.116 40.104 97.2 ;
    END
  END dout[68]
  PIN dout[69]
    DIRECTION OUTPUT ;
    USE SIGNAL ;
    PORT
      LAYER M5 ;
        RECT  40.176 97.116 40.2 97.2 ;
    END
  END dout[69]
  PIN dout[6]
    DIRECTION OUTPUT ;
    USE SIGNAL ;
    PORT
      LAYER M5 ;
        RECT  59.472 97.116 59.496 97.2 ;
    END
  END dout[6]
  PIN dout[70]
    DIRECTION OUTPUT ;
    USE SIGNAL ;
    PORT
      LAYER M5 ;
        RECT  40.272 97.116 40.296 97.2 ;
    END
  END dout[70]
  PIN dout[71]
    DIRECTION OUTPUT ;
    USE SIGNAL ;
    PORT
      LAYER M5 ;
        RECT  40.368 97.116 40.392 97.2 ;
    END
  END dout[71]
  PIN dout[72]
    DIRECTION OUTPUT ;
    USE SIGNAL ;
    PORT
      LAYER M5 ;
        RECT  40.464 97.116 40.488 97.2 ;
    END
  END dout[72]
  PIN dout[73]
    DIRECTION OUTPUT ;
    USE SIGNAL ;
    PORT
      LAYER M5 ;
        RECT  40.56 97.116 40.584 97.2 ;
    END
  END dout[73]
  PIN dout[74]
    DIRECTION OUTPUT ;
    USE SIGNAL ;
    PORT
      LAYER M5 ;
        RECT  40.656 97.116 40.68 97.2 ;
    END
  END dout[74]
  PIN dout[75]
    DIRECTION OUTPUT ;
    USE SIGNAL ;
    PORT
      LAYER M5 ;
        RECT  40.752 97.116 40.776 97.2 ;
    END
  END dout[75]
  PIN dout[76]
    DIRECTION OUTPUT ;
    USE SIGNAL ;
    PORT
      LAYER M5 ;
        RECT  40.848 97.116 40.872 97.2 ;
    END
  END dout[76]
  PIN dout[77]
    DIRECTION OUTPUT ;
    USE SIGNAL ;
    PORT
      LAYER M5 ;
        RECT  40.944 97.116 40.968 97.2 ;
    END
  END dout[77]
  PIN dout[78]
    DIRECTION OUTPUT ;
    USE SIGNAL ;
    PORT
      LAYER M5 ;
        RECT  41.04 97.116 41.064 97.2 ;
    END
  END dout[78]
  PIN dout[79]
    DIRECTION OUTPUT ;
    USE SIGNAL ;
    PORT
      LAYER M5 ;
        RECT  41.136 97.116 41.16 97.2 ;
    END
  END dout[79]
  PIN dout[7]
    DIRECTION OUTPUT ;
    USE SIGNAL ;
    PORT
      LAYER M5 ;
        RECT  59.568 97.116 59.592 97.2 ;
    END
  END dout[7]
  PIN dout[80]
    DIRECTION OUTPUT ;
    USE SIGNAL ;
    PORT
      LAYER M5 ;
        RECT  41.232 97.116 41.256 97.2 ;
    END
  END dout[80]
  PIN dout[81]
    DIRECTION OUTPUT ;
    USE SIGNAL ;
    PORT
      LAYER M5 ;
        RECT  41.328 97.116 41.352 97.2 ;
    END
  END dout[81]
  PIN dout[82]
    DIRECTION OUTPUT ;
    USE SIGNAL ;
    PORT
      LAYER M5 ;
        RECT  41.424 97.116 41.448 97.2 ;
    END
  END dout[82]
  PIN dout[83]
    DIRECTION OUTPUT ;
    USE SIGNAL ;
    PORT
      LAYER M5 ;
        RECT  41.52 97.116 41.544 97.2 ;
    END
  END dout[83]
  PIN dout[84]
    DIRECTION OUTPUT ;
    USE SIGNAL ;
    PORT
      LAYER M5 ;
        RECT  41.616 97.116 41.64 97.2 ;
    END
  END dout[84]
  PIN dout[85]
    DIRECTION OUTPUT ;
    USE SIGNAL ;
    PORT
      LAYER M5 ;
        RECT  41.712 97.116 41.736 97.2 ;
    END
  END dout[85]
  PIN dout[86]
    DIRECTION OUTPUT ;
    USE SIGNAL ;
    PORT
      LAYER M5 ;
        RECT  41.808 97.116 41.832 97.2 ;
    END
  END dout[86]
  PIN dout[87]
    DIRECTION OUTPUT ;
    USE SIGNAL ;
    PORT
      LAYER M5 ;
        RECT  41.904 97.116 41.928 97.2 ;
    END
  END dout[87]
  PIN dout[88]
    DIRECTION OUTPUT ;
    USE SIGNAL ;
    PORT
      LAYER M5 ;
        RECT  42 97.116 42.024 97.2 ;
    END
  END dout[88]
  PIN dout[89]
    DIRECTION OUTPUT ;
    USE SIGNAL ;
    PORT
      LAYER M5 ;
        RECT  42.096 97.116 42.12 97.2 ;
    END
  END dout[89]
  PIN dout[8]
    DIRECTION OUTPUT ;
    USE SIGNAL ;
    PORT
      LAYER M5 ;
        RECT  59.664 97.116 59.688 97.2 ;
    END
  END dout[8]
  PIN dout[90]
    DIRECTION OUTPUT ;
    USE SIGNAL ;
    PORT
      LAYER M5 ;
        RECT  42.192 97.116 42.216 97.2 ;
    END
  END dout[90]
  PIN dout[91]
    DIRECTION OUTPUT ;
    USE SIGNAL ;
    PORT
      LAYER M5 ;
        RECT  42.288 97.116 42.312 97.2 ;
    END
  END dout[91]
  PIN dout[92]
    DIRECTION OUTPUT ;
    USE SIGNAL ;
    PORT
      LAYER M5 ;
        RECT  42.384 97.116 42.408 97.2 ;
    END
  END dout[92]
  PIN dout[93]
    DIRECTION OUTPUT ;
    USE SIGNAL ;
    PORT
      LAYER M5 ;
        RECT  42.48 97.116 42.504 97.2 ;
    END
  END dout[93]
  PIN dout[94]
    DIRECTION OUTPUT ;
    USE SIGNAL ;
    PORT
      LAYER M5 ;
        RECT  42.576 97.116 42.6 97.2 ;
    END
  END dout[94]
  PIN dout[95]
    DIRECTION OUTPUT ;
    USE SIGNAL ;
    PORT
      LAYER M5 ;
        RECT  42.672 97.116 42.696 97.2 ;
    END
  END dout[95]
  PIN dout[96]
    DIRECTION OUTPUT ;
    USE SIGNAL ;
    PORT
      LAYER M5 ;
        RECT  20.496 97.116 20.52 97.2 ;
    END
  END dout[96]
  PIN dout[97]
    DIRECTION OUTPUT ;
    USE SIGNAL ;
    PORT
      LAYER M5 ;
        RECT  20.592 97.116 20.616 97.2 ;
    END
  END dout[97]
  PIN dout[98]
    DIRECTION OUTPUT ;
    USE SIGNAL ;
    PORT
      LAYER M5 ;
        RECT  20.688 97.116 20.712 97.2 ;
    END
  END dout[98]
  PIN dout[99]
    DIRECTION OUTPUT ;
    USE SIGNAL ;
    PORT
      LAYER M5 ;
        RECT  20.784 97.116 20.808 97.2 ;
    END
  END dout[99]
  PIN dout[9]
    DIRECTION OUTPUT ;
    USE SIGNAL ;
    PORT
      LAYER M5 ;
        RECT  59.76 97.116 59.784 97.2 ;
    END
  END dout[9]
  PIN empty
    DIRECTION OUTPUT ;
    USE SIGNAL ;
    PORT
      LAYER M5 ;
        RECT  54.96 97.116 54.984 97.2 ;
    END
  END empty
  PIN pop
    DIRECTION INPUT ;
    USE SIGNAL ;
    PORT
      LAYER M4 ;
        RECT  0 50.448 0.084 50.472 ;
    END
  END pop
  PIN push
    DIRECTION INPUT ;
    USE SIGNAL ;
    PORT
      LAYER M5 ;
        RECT  27.6 0 27.624 0.084 ;
    END
  END push
  PIN rst_n
    DIRECTION INPUT ;
    USE SIGNAL ;
    PORT
      LAYER M4 ;
        RECT  0 50.544 0.084 50.568 ;
    END
  END rst_n
  PIN VDD
    DIRECTION INOUT ;
    USE POWER ;
    PORT
      LAYER M5 ;
        RECT  94.392 2.151 94.512 95.049 ;
        RECT  88.992 2.151 89.112 95.049 ;
        RECT  83.592 2.151 83.712 95.049 ;
        RECT  78.192 2.151 78.312 95.049 ;
        RECT  72.792 2.151 72.912 95.049 ;
        RECT  67.392 2.151 67.512 95.049 ;
        RECT  61.992 2.151 62.112 95.049 ;
        RECT  56.592 2.151 56.712 95.049 ;
        RECT  51.192 2.151 51.312 95.049 ;
        RECT  45.792 2.151 45.912 95.049 ;
        RECT  40.392 2.151 40.512 95.049 ;
        RECT  34.992 2.151 35.112 95.049 ;
        RECT  29.592 2.151 29.712 95.049 ;
        RECT  24.192 2.151 24.312 95.049 ;
        RECT  18.792 2.151 18.912 95.049 ;
        RECT  13.392 2.151 13.512 95.049 ;
        RECT  7.992 2.151 8.112 95.049 ;
        RECT  2.592 2.151 2.712 95.049 ;
    END
  END VDD
  PIN VSS
    DIRECTION INOUT ;
    USE GROUND ;
    PORT
      LAYER M5 ;
        RECT  94.2 2.137 94.32 95.063 ;
        RECT  88.8 2.137 88.92 95.063 ;
        RECT  83.4 2.137 83.52 95.063 ;
        RECT  78 2.137 78.12 95.063 ;
        RECT  72.6 2.137 72.72 95.063 ;
        RECT  67.2 2.137 67.32 95.063 ;
        RECT  61.8 2.137 61.92 95.063 ;
        RECT  56.4 2.137 56.52 95.063 ;
        RECT  51 2.137 51.12 95.063 ;
        RECT  45.6 2.137 45.72 95.063 ;
        RECT  40.2 2.137 40.32 95.063 ;
        RECT  34.8 2.137 34.92 95.063 ;
        RECT  29.4 2.137 29.52 95.063 ;
        RECT  24 2.137 24.12 95.063 ;
        RECT  18.6 2.137 18.72 95.063 ;
        RECT  13.2 2.137 13.32 95.063 ;
        RECT  7.8 2.137 7.92 95.063 ;
        RECT  2.4 2.137 2.52 95.063 ;
    END
  END VSS
  OBS
    LAYER RVTN ;
     RECT  2.16 2.16 95.04 2.295 ;
     RECT  2.16 2.565 95.04 2.835 ;
     RECT  2.16 3.105 95.04 3.375 ;
     RECT  2.16 3.645 95.04 3.915 ;
     RECT  2.16 4.185 95.04 4.455 ;
     RECT  2.16 4.725 95.04 4.995 ;
     RECT  2.16 5.265 95.04 5.535 ;
     RECT  2.16 5.805 95.04 6.075 ;
     RECT  2.16 6.345 95.04 6.615 ;
     RECT  2.16 6.885 95.04 7.155 ;
     RECT  2.16 7.425 95.04 7.695 ;
     RECT  2.16 7.965 95.04 8.235 ;
     RECT  2.16 8.505 95.04 8.775 ;
     RECT  2.16 9.045 95.04 9.315 ;
     RECT  2.16 9.585 95.04 9.855 ;
     RECT  2.16 10.125 95.04 10.395 ;
     RECT  2.16 10.665 95.04 10.935 ;
     RECT  2.16 11.205 95.04 11.475 ;
     RECT  2.16 11.745 95.04 12.015 ;
     RECT  2.16 12.285 95.04 12.555 ;
     RECT  2.16 12.825 95.04 13.095 ;
     RECT  2.16 13.365 95.04 13.635 ;
     RECT  2.16 13.905 95.04 14.175 ;
     RECT  2.16 14.445 95.04 14.715 ;
     RECT  2.16 14.985 95.04 15.255 ;
     RECT  2.16 15.525 95.04 15.795 ;
     RECT  2.16 16.065 95.04 16.335 ;
     RECT  2.16 16.605 95.04 16.875 ;
     RECT  2.16 17.145 95.04 17.415 ;
     RECT  2.16 17.685 95.04 17.955 ;
     RECT  2.16 18.225 95.04 18.495 ;
     RECT  2.16 18.765 95.04 19.035 ;
     RECT  2.16 19.305 95.04 19.575 ;
     RECT  2.16 19.845 95.04 20.115 ;
     RECT  2.16 20.385 95.04 20.655 ;
     RECT  2.16 20.925 95.04 21.195 ;
     RECT  2.16 21.465 95.04 21.735 ;
     RECT  2.16 22.005 95.04 22.275 ;
     RECT  2.16 22.545 95.04 22.815 ;
     RECT  2.16 23.085 95.04 23.355 ;
     RECT  2.16 23.625 95.04 23.895 ;
     RECT  2.16 24.165 95.04 24.435 ;
     RECT  2.16 24.705 95.04 24.975 ;
     RECT  2.16 25.245 95.04 25.515 ;
     RECT  2.16 25.785 95.04 26.055 ;
     RECT  2.16 26.325 95.04 26.595 ;
     RECT  2.16 26.865 95.04 27.135 ;
     RECT  2.16 27.405 95.04 27.675 ;
     RECT  2.16 27.945 95.04 28.215 ;
     RECT  2.16 28.485 95.04 28.755 ;
     RECT  2.16 29.025 95.04 29.295 ;
     RECT  2.16 29.565 95.04 29.835 ;
     RECT  2.16 30.105 95.04 30.375 ;
     RECT  2.16 30.645 95.04 30.915 ;
     RECT  2.16 31.185 95.04 31.455 ;
     RECT  2.16 31.725 95.04 31.995 ;
     RECT  2.16 32.265 95.04 32.535 ;
     RECT  2.16 32.805 95.04 33.075 ;
     RECT  2.16 33.345 95.04 33.615 ;
     RECT  2.16 33.885 95.04 34.155 ;
     RECT  2.16 34.425 95.04 34.695 ;
     RECT  2.16 34.965 95.04 35.235 ;
     RECT  2.16 35.505 95.04 35.775 ;
     RECT  2.16 36.045 95.04 36.315 ;
     RECT  2.16 36.585 95.04 36.855 ;
     RECT  2.16 37.125 95.04 37.395 ;
     RECT  2.16 37.665 95.04 37.935 ;
     RECT  2.16 38.205 95.04 38.475 ;
     RECT  2.16 38.745 95.04 39.015 ;
     RECT  2.16 39.285 95.04 39.555 ;
     RECT  2.16 39.825 95.04 40.095 ;
     RECT  2.16 40.365 95.04 40.635 ;
     RECT  2.16 40.905 95.04 41.175 ;
     RECT  2.16 41.445 95.04 41.715 ;
     RECT  2.16 41.985 95.04 42.255 ;
     RECT  2.16 42.525 95.04 42.795 ;
     RECT  2.16 43.065 95.04 43.335 ;
     RECT  2.16 43.605 95.04 43.875 ;
     RECT  2.16 44.145 95.04 44.415 ;
     RECT  2.16 44.685 95.04 44.955 ;
     RECT  2.16 45.225 95.04 45.495 ;
     RECT  2.16 45.765 95.04 46.035 ;
     RECT  2.16 46.305 95.04 46.575 ;
     RECT  2.16 46.845 95.04 47.115 ;
     RECT  2.16 47.385 95.04 47.655 ;
     RECT  2.16 47.925 95.04 48.195 ;
     RECT  2.16 48.465 95.04 48.735 ;
     RECT  2.16 49.005 95.04 49.275 ;
     RECT  2.16 49.545 95.04 49.815 ;
     RECT  2.16 50.085 95.04 50.355 ;
     RECT  2.16 50.625 95.04 50.895 ;
     RECT  2.16 51.165 95.04 51.435 ;
     RECT  2.16 51.705 95.04 51.975 ;
     RECT  2.16 52.245 95.04 52.515 ;
     RECT  2.16 52.785 95.04 53.055 ;
     RECT  2.16 53.325 95.04 53.595 ;
     RECT  2.16 53.865 95.04 54.135 ;
     RECT  2.16 54.405 95.04 54.675 ;
     RECT  2.16 54.945 95.04 55.215 ;
     RECT  2.16 55.485 95.04 55.755 ;
     RECT  2.16 56.025 95.04 56.295 ;
     RECT  2.16 56.565 95.04 56.835 ;
     RECT  2.16 57.105 95.04 57.375 ;
     RECT  2.16 57.645 95.04 57.915 ;
     RECT  2.16 58.185 95.04 58.455 ;
     RECT  2.16 58.725 95.04 58.995 ;
     RECT  2.16 59.265 95.04 59.535 ;
     RECT  2.16 59.805 95.04 60.075 ;
     RECT  2.16 60.345 95.04 60.615 ;
     RECT  2.16 60.885 95.04 61.155 ;
     RECT  2.16 61.425 95.04 61.695 ;
     RECT  2.16 61.965 95.04 62.235 ;
     RECT  2.16 62.505 95.04 62.775 ;
     RECT  2.16 63.045 95.04 63.315 ;
     RECT  2.16 63.585 95.04 63.855 ;
     RECT  2.16 64.125 95.04 64.395 ;
     RECT  2.16 64.665 95.04 64.935 ;
     RECT  2.16 65.205 95.04 65.475 ;
     RECT  2.16 65.745 95.04 66.015 ;
     RECT  2.16 66.285 95.04 66.555 ;
     RECT  2.16 66.825 95.04 67.095 ;
     RECT  2.16 67.365 95.04 67.635 ;
     RECT  2.16 67.905 95.04 68.175 ;
     RECT  2.16 68.445 95.04 68.715 ;
     RECT  2.16 68.985 95.04 69.255 ;
     RECT  2.16 69.525 95.04 69.795 ;
     RECT  2.16 70.065 95.04 70.335 ;
     RECT  2.16 70.605 95.04 70.875 ;
     RECT  2.16 71.145 95.04 71.415 ;
     RECT  2.16 71.685 95.04 71.955 ;
     RECT  2.16 72.225 95.04 72.495 ;
     RECT  2.16 72.765 95.04 73.035 ;
     RECT  2.16 73.305 95.04 73.575 ;
     RECT  2.16 73.845 95.04 74.115 ;
     RECT  2.16 74.385 95.04 74.655 ;
     RECT  2.16 74.925 95.04 75.195 ;
     RECT  2.16 75.465 95.04 75.735 ;
     RECT  2.16 76.005 95.04 76.275 ;
     RECT  2.16 76.545 95.04 76.815 ;
     RECT  2.16 77.085 95.04 77.355 ;
     RECT  2.16 77.625 95.04 77.895 ;
     RECT  2.16 78.165 95.04 78.435 ;
     RECT  2.16 78.705 95.04 78.975 ;
     RECT  2.16 79.245 95.04 79.515 ;
     RECT  2.16 79.785 95.04 80.055 ;
     RECT  2.16 80.325 95.04 80.595 ;
     RECT  2.16 80.865 95.04 81.135 ;
     RECT  2.16 81.405 95.04 81.675 ;
     RECT  2.16 81.945 95.04 82.215 ;
     RECT  2.16 82.485 95.04 82.755 ;
     RECT  2.16 83.025 95.04 83.295 ;
     RECT  2.16 83.565 95.04 83.835 ;
     RECT  2.16 84.105 95.04 84.375 ;
     RECT  2.16 84.645 95.04 84.915 ;
     RECT  2.16 85.185 95.04 85.455 ;
     RECT  2.16 85.725 95.04 85.995 ;
     RECT  2.16 86.265 95.04 86.535 ;
     RECT  2.16 86.805 95.04 87.075 ;
     RECT  2.16 87.345 95.04 87.615 ;
     RECT  2.16 87.885 95.04 88.155 ;
     RECT  2.16 88.425 95.04 88.695 ;
     RECT  2.16 88.965 95.04 89.235 ;
     RECT  2.16 89.505 95.04 89.775 ;
     RECT  2.16 90.045 95.04 90.315 ;
     RECT  2.16 90.585 95.04 90.855 ;
     RECT  2.16 91.125 95.04 91.395 ;
     RECT  2.16 91.665 95.04 91.935 ;
     RECT  2.16 92.205 95.04 92.475 ;
     RECT  2.16 92.745 95.04 93.015 ;
     RECT  2.16 93.285 95.04 93.555 ;
     RECT  2.16 93.825 95.04 94.095 ;
     RECT  2.16 94.365 95.04 94.635 ;
     RECT  2.16 94.905 95.04 95.04 ;
    LAYER RVTP ;
     RECT  2.16 2.295 95.04 2.565 ;
     RECT  2.16 2.835 95.04 3.105 ;
     RECT  2.16 3.375 95.04 3.645 ;
     RECT  2.16 3.915 95.04 4.185 ;
     RECT  2.16 4.455 95.04 4.725 ;
     RECT  2.16 4.995 95.04 5.265 ;
     RECT  2.16 5.535 95.04 5.805 ;
     RECT  2.16 6.075 95.04 6.345 ;
     RECT  2.16 6.615 95.04 6.885 ;
     RECT  2.16 7.155 95.04 7.425 ;
     RECT  2.16 7.695 95.04 7.965 ;
     RECT  2.16 8.235 95.04 8.505 ;
     RECT  2.16 8.775 95.04 9.045 ;
     RECT  2.16 9.315 95.04 9.585 ;
     RECT  2.16 9.855 95.04 10.125 ;
     RECT  2.16 10.395 95.04 10.665 ;
     RECT  2.16 10.935 95.04 11.205 ;
     RECT  2.16 11.475 95.04 11.745 ;
     RECT  2.16 12.015 95.04 12.285 ;
     RECT  2.16 12.555 95.04 12.825 ;
     RECT  2.16 13.095 95.04 13.365 ;
     RECT  2.16 13.635 95.04 13.905 ;
     RECT  2.16 14.175 95.04 14.445 ;
     RECT  2.16 14.715 95.04 14.985 ;
     RECT  2.16 15.255 95.04 15.525 ;
     RECT  2.16 15.795 95.04 16.065 ;
     RECT  2.16 16.335 95.04 16.605 ;
     RECT  2.16 16.875 95.04 17.145 ;
     RECT  2.16 17.415 95.04 17.685 ;
     RECT  2.16 17.955 95.04 18.225 ;
     RECT  2.16 18.495 95.04 18.765 ;
     RECT  2.16 19.035 95.04 19.305 ;
     RECT  2.16 19.575 95.04 19.845 ;
     RECT  2.16 20.115 95.04 20.385 ;
     RECT  2.16 20.655 95.04 20.925 ;
     RECT  2.16 21.195 95.04 21.465 ;
     RECT  2.16 21.735 95.04 22.005 ;
     RECT  2.16 22.275 95.04 22.545 ;
     RECT  2.16 22.815 95.04 23.085 ;
     RECT  2.16 23.355 95.04 23.625 ;
     RECT  2.16 23.895 95.04 24.165 ;
     RECT  2.16 24.435 95.04 24.705 ;
     RECT  2.16 24.975 95.04 25.245 ;
     RECT  2.16 25.515 95.04 25.785 ;
     RECT  2.16 26.055 95.04 26.325 ;
     RECT  2.16 26.595 95.04 26.865 ;
     RECT  2.16 27.135 95.04 27.405 ;
     RECT  2.16 27.675 95.04 27.945 ;
     RECT  2.16 28.215 95.04 28.485 ;
     RECT  2.16 28.755 95.04 29.025 ;
     RECT  2.16 29.295 95.04 29.565 ;
     RECT  2.16 29.835 95.04 30.105 ;
     RECT  2.16 30.375 95.04 30.645 ;
     RECT  2.16 30.915 95.04 31.185 ;
     RECT  2.16 31.455 95.04 31.725 ;
     RECT  2.16 31.995 95.04 32.265 ;
     RECT  2.16 32.535 95.04 32.805 ;
     RECT  2.16 33.075 95.04 33.345 ;
     RECT  2.16 33.615 95.04 33.885 ;
     RECT  2.16 34.155 95.04 34.425 ;
     RECT  2.16 34.695 95.04 34.965 ;
     RECT  2.16 35.235 95.04 35.505 ;
     RECT  2.16 35.775 95.04 36.045 ;
     RECT  2.16 36.315 95.04 36.585 ;
     RECT  2.16 36.855 95.04 37.125 ;
     RECT  2.16 37.395 95.04 37.665 ;
     RECT  2.16 37.935 95.04 38.205 ;
     RECT  2.16 38.475 95.04 38.745 ;
     RECT  2.16 39.015 95.04 39.285 ;
     RECT  2.16 39.555 95.04 39.825 ;
     RECT  2.16 40.095 95.04 40.365 ;
     RECT  2.16 40.635 95.04 40.905 ;
     RECT  2.16 41.175 95.04 41.445 ;
     RECT  2.16 41.715 95.04 41.985 ;
     RECT  2.16 42.255 95.04 42.525 ;
     RECT  2.16 42.795 95.04 43.065 ;
     RECT  2.16 43.335 95.04 43.605 ;
     RECT  2.16 43.875 95.04 44.145 ;
     RECT  2.16 44.415 95.04 44.685 ;
     RECT  2.16 44.955 95.04 45.225 ;
     RECT  2.16 45.495 95.04 45.765 ;
     RECT  2.16 46.035 95.04 46.305 ;
     RECT  2.16 46.575 95.04 46.845 ;
     RECT  2.16 47.115 95.04 47.385 ;
     RECT  2.16 47.655 95.04 47.925 ;
     RECT  2.16 48.195 95.04 48.465 ;
     RECT  2.16 48.735 95.04 49.005 ;
     RECT  2.16 49.275 95.04 49.545 ;
     RECT  2.16 49.815 95.04 50.085 ;
     RECT  2.16 50.355 95.04 50.625 ;
     RECT  2.16 50.895 95.04 51.165 ;
     RECT  2.16 51.435 95.04 51.705 ;
     RECT  2.16 51.975 95.04 52.245 ;
     RECT  2.16 52.515 95.04 52.785 ;
     RECT  2.16 53.055 95.04 53.325 ;
     RECT  2.16 53.595 95.04 53.865 ;
     RECT  2.16 54.135 95.04 54.405 ;
     RECT  2.16 54.675 95.04 54.945 ;
     RECT  2.16 55.215 95.04 55.485 ;
     RECT  2.16 55.755 95.04 56.025 ;
     RECT  2.16 56.295 95.04 56.565 ;
     RECT  2.16 56.835 95.04 57.105 ;
     RECT  2.16 57.375 95.04 57.645 ;
     RECT  2.16 57.915 95.04 58.185 ;
     RECT  2.16 58.455 95.04 58.725 ;
     RECT  2.16 58.995 95.04 59.265 ;
     RECT  2.16 59.535 95.04 59.805 ;
     RECT  2.16 60.075 95.04 60.345 ;
     RECT  2.16 60.615 95.04 60.885 ;
     RECT  2.16 61.155 95.04 61.425 ;
     RECT  2.16 61.695 95.04 61.965 ;
     RECT  2.16 62.235 95.04 62.505 ;
     RECT  2.16 62.775 95.04 63.045 ;
     RECT  2.16 63.315 95.04 63.585 ;
     RECT  2.16 63.855 95.04 64.125 ;
     RECT  2.16 64.395 95.04 64.665 ;
     RECT  2.16 64.935 95.04 65.205 ;
     RECT  2.16 65.475 95.04 65.745 ;
     RECT  2.16 66.015 95.04 66.285 ;
     RECT  2.16 66.555 95.04 66.825 ;
     RECT  2.16 67.095 95.04 67.365 ;
     RECT  2.16 67.635 95.04 67.905 ;
     RECT  2.16 68.175 95.04 68.445 ;
     RECT  2.16 68.715 95.04 68.985 ;
     RECT  2.16 69.255 95.04 69.525 ;
     RECT  2.16 69.795 95.04 70.065 ;
     RECT  2.16 70.335 95.04 70.605 ;
     RECT  2.16 70.875 95.04 71.145 ;
     RECT  2.16 71.415 95.04 71.685 ;
     RECT  2.16 71.955 95.04 72.225 ;
     RECT  2.16 72.495 95.04 72.765 ;
     RECT  2.16 73.035 95.04 73.305 ;
     RECT  2.16 73.575 95.04 73.845 ;
     RECT  2.16 74.115 95.04 74.385 ;
     RECT  2.16 74.655 95.04 74.925 ;
     RECT  2.16 75.195 95.04 75.465 ;
     RECT  2.16 75.735 95.04 76.005 ;
     RECT  2.16 76.275 95.04 76.545 ;
     RECT  2.16 76.815 95.04 77.085 ;
     RECT  2.16 77.355 95.04 77.625 ;
     RECT  2.16 77.895 95.04 78.165 ;
     RECT  2.16 78.435 95.04 78.705 ;
     RECT  2.16 78.975 95.04 79.245 ;
     RECT  2.16 79.515 95.04 79.785 ;
     RECT  2.16 80.055 95.04 80.325 ;
     RECT  2.16 80.595 95.04 80.865 ;
     RECT  2.16 81.135 95.04 81.405 ;
     RECT  2.16 81.675 95.04 81.945 ;
     RECT  2.16 82.215 95.04 82.485 ;
     RECT  2.16 82.755 95.04 83.025 ;
     RECT  2.16 83.295 95.04 83.565 ;
     RECT  2.16 83.835 95.04 84.105 ;
     RECT  2.16 84.375 95.04 84.645 ;
     RECT  2.16 84.915 95.04 85.185 ;
     RECT  2.16 85.455 95.04 85.725 ;
     RECT  2.16 85.995 95.04 86.265 ;
     RECT  2.16 86.535 95.04 86.805 ;
     RECT  2.16 87.075 95.04 87.345 ;
     RECT  2.16 87.615 95.04 87.885 ;
     RECT  2.16 88.155 95.04 88.425 ;
     RECT  2.16 88.695 95.04 88.965 ;
     RECT  2.16 89.235 95.04 89.505 ;
     RECT  2.16 89.775 95.04 90.045 ;
     RECT  2.16 90.315 95.04 90.585 ;
     RECT  2.16 90.855 95.04 91.125 ;
     RECT  2.16 91.395 95.04 91.665 ;
     RECT  2.16 91.935 95.04 92.205 ;
     RECT  2.16 92.475 95.04 92.745 ;
     RECT  2.16 93.015 95.04 93.285 ;
     RECT  2.16 93.555 95.04 93.825 ;
     RECT  2.16 94.095 95.04 94.365 ;
     RECT  2.16 94.635 95.04 94.905 ;
    LAYER M1 ;
     RECT  2.16 2.151 95.04 95.049 ;
    LAYER M2 ;
     RECT  2.16 2.151 18.859 95.049 ;
     RECT  18.859 2.151 22.847 95.094 ;
     RECT  22.847 2.151 32.359 95.049 ;
     RECT  32.359 2.151 34.771 95.13 ;
     RECT  34.771 2.151 36.031 95.166 ;
     RECT  36.031 2.106 36.563 95.166 ;
     RECT  36.563 2.151 38.767 95.166 ;
     RECT  38.767 2.151 42.215 95.238 ;
     RECT  42.215 2.151 44.275 95.166 ;
     RECT  44.275 2.106 46.535 95.166 ;
     RECT  46.535 2.151 47.327 95.166 ;
     RECT  47.327 2.151 48.415 95.094 ;
     RECT  48.415 2.151 51.323 95.166 ;
     RECT  51.323 2.151 51.331 95.13 ;
     RECT  51.331 2.106 51.935 95.13 ;
     RECT  51.935 2.106 52.439 95.094 ;
     RECT  52.439 2.151 52.663 95.094 ;
     RECT  52.663 2.151 54.715 95.166 ;
     RECT  54.715 2.106 55.499 95.166 ;
     RECT  55.499 2.151 65.003 95.166 ;
     RECT  65.003 2.151 66.703 95.13 ;
     RECT  66.703 2.151 70.699 95.166 ;
     RECT  70.699 2.151 73.571 95.238 ;
     RECT  73.571 2.151 78.683 95.166 ;
     RECT  78.683 2.151 78.719 95.094 ;
     RECT  78.719 2.151 84.883 95.049 ;
     RECT  84.883 2.151 85.559 95.094 ;
     RECT  85.559 2.151 95.04 95.049 ;
    LAYER M3 ;
     RECT  24.588 0.091 24.606 0.139 ;
     RECT  26.064 0.091 26.082 0.139 ;
     RECT  27.288 0.091 27.522 0.139 ;
     RECT  29.772 0.091 31.158 0.139 ;
     RECT  32.292 0.091 32.31 0.139 ;
     RECT  33.084 0.091 33.102 0.139 ;
     RECT  33.84 0.091 33.858 0.139 ;
     RECT  64.656 0.091 64.674 0.139 ;
     RECT  70.272 0.091 70.29 0.139 ;
     RECT  72.396 0.091 73.098 0.139 ;
     RECT  76.428 0.091 76.446 0.139 ;
     RECT  81.072 0.091 81.63 0.139 ;
     RECT  27.288 0.139 27.594 0.187 ;
     RECT  69.948 0.139 70.29 0.187 ;
     RECT  71.064 0.091 71.334 0.187 ;
     RECT  26.064 0.139 26.298 0.235 ;
     RECT  35.172 0.091 37.602 0.269 ;
     RECT  69.732 0.187 71.334 0.283 ;
     RECT  29.772 0.139 31.266 0.317 ;
     RECT  29.772 0.317 31.086 0.365 ;
     RECT  29.772 0.365 31.014 0.413 ;
     RECT  77.652 0.427 77.67 0.475 ;
     RECT  77.652 0.475 77.778 0.523 ;
     RECT  78.732 0.091 79.254 0.523 ;
     RECT  7.632 0.091 7.65 1.723 ;
     RECT  9.108 0.091 9.126 1.723 ;
     RECT  9.9 0.091 9.918 1.723 ;
     RECT  19.044 0.091 19.062 1.723 ;
     RECT  21.132 0.091 21.15 1.723 ;
     RECT  22.716 1.099 22.734 1.723 ;
     RECT  23.508 0.187 23.526 1.723 ;
     RECT  24.264 0.139 24.606 1.723 ;
     RECT  29.772 0.413 30.978 1.723 ;
     RECT  32.22 0.139 32.31 1.723 ;
     RECT  33.084 0.139 33.858 1.723 ;
     RECT  35.352 0.269 37.602 1.723 ;
     RECT  39.348 0.091 39.366 1.723 ;
     RECT  40.788 0.091 41.454 1.723 ;
     RECT  52.632 0.091 53.19 1.723 ;
     RECT  54.18 0.091 55.422 1.723 ;
     RECT  56.556 0.091 57.078 1.723 ;
     RECT  66.168 0.091 66.726 1.723 ;
     RECT  68.4 0.091 68.994 1.723 ;
     RECT  69.732 0.283 71.442 1.723 ;
     RECT  72.288 0.139 73.098 1.723 ;
     RECT  74.124 0.091 74.142 1.723 ;
     RECT  76.428 0.139 76.662 1.723 ;
     RECT  77.472 0.523 77.778 1.723 ;
     RECT  78.696 0.523 79.254 1.723 ;
     RECT  7.2 1.723 9.954 1.819 ;
     RECT  39.348 1.723 39.798 1.963 ;
     RECT  40.536 1.723 42.066 1.963 ;
     RECT  82.872 0.091 83.574 1.963 ;
     RECT  29.772 1.723 33.858 2.011 ;
     RECT  35.28 1.723 38.07 2.011 ;
     RECT  65.7 1.723 67.374 2.011 ;
     RECT  68.112 1.723 71.442 2.011 ;
     RECT  43.596 0.091 43.614 2.101 ;
     RECT  52.56 1.723 57.114 2.101 ;
     RECT  51.336 2.101 51.354 2.143 ;
     RECT  16.236 1.723 19.062 2.191 ;
     RECT  26.064 0.235 26.334 2.191 ;
     RECT  29.34 2.011 33.858 2.191 ;
     RECT  34.776 2.011 38.07 2.191 ;
     RECT  39.348 1.963 42.066 2.191 ;
     RECT  43.596 2.101 44.298 2.191 ;
     RECT  61.815 2.143 61.905 2.191 ;
     RECT  64.584 0.139 64.674 2.191 ;
     RECT  65.7 2.011 71.442 2.191 ;
     RECT  72.288 1.723 75.006 2.191 ;
     RECT  81 0.139 81.63 2.191 ;
     RECT  82.872 1.963 83.862 2.191 ;
     RECT  29.088 2.191 33.858 2.227 ;
     RECT  34.776 2.191 42.066 2.227 ;
     RECT  43.308 2.191 44.298 2.227 ;
     RECT  52.416 2.101 57.114 2.227 ;
     RECT  64.584 2.191 71.442 2.227 ;
     RECT  82.872 2.191 84.042 2.227 ;
     RECT  51.015 2.143 51.354 2.251 ;
     RECT  52.308 2.227 57.114 2.251 ;
     RECT  58.032 2.191 58.05 2.251 ;
     RECT  7.164 1.819 9.954 2.263 ;
     RECT  51.015 2.251 58.05 2.263 ;
     RECT  7.164 2.263 10.674 2.299 ;
     RECT  15.876 2.191 19.062 2.299 ;
     RECT  21.132 1.723 24.894 2.299 ;
     RECT  26.064 2.191 26.37 2.299 ;
     RECT  27.288 0.187 28.242 2.299 ;
     RECT  50.832 2.263 58.05 2.299 ;
     RECT  63.216 2.227 63.234 2.299 ;
     RECT  64.152 2.227 71.442 2.299 ;
     RECT  72.288 2.191 75.402 2.299 ;
     RECT  76.356 1.723 76.662 2.299 ;
     RECT  77.472 1.723 79.542 2.299 ;
     RECT  80.748 2.191 81.63 2.299 ;
     RECT  82.872 2.227 84.618 2.299 ;
     RECT  28.98 2.227 44.442 2.327 ;
     RECT  50.832 2.299 58.194 2.335 ;
     RECT  6.948 2.299 10.674 2.363 ;
     RECT  15.876 2.299 28.242 2.371 ;
     RECT  28.98 2.327 43.866 2.371 ;
     RECT  2.415 2.143 2.505 2.413 ;
     RECT  13.215 2.143 13.305 2.413 ;
     RECT  45.615 2.143 45.705 2.413 ;
     RECT  46.512 2.101 46.53 2.413 ;
     RECT  61.815 2.191 61.974 2.413 ;
     RECT  88.815 2.143 88.905 2.413 ;
     RECT  94.215 2.143 94.305 2.413 ;
     RECT  45.615 2.413 46.53 2.491 ;
     RECT  15.876 2.371 43.866 2.525 ;
     RECT  50.58 2.335 58.194 2.605 ;
     RECT  63.216 2.299 84.618 2.605 ;
     RECT  7.02 2.363 10.674 2.641 ;
     RECT  45.612 2.491 46.53 2.641 ;
     RECT  15.876 2.525 43.83 2.731 ;
     RECT  47.916 2.227 47.934 2.731 ;
     RECT  48.78 2.641 48.798 2.731 ;
     RECT  50.508 2.605 58.194 2.767 ;
     RECT  7.02 2.641 10.71 2.795 ;
     RECT  50.508 2.767 58.482 2.803 ;
     RECT  86.652 2.191 86.67 2.803 ;
     RECT  45.612 2.641 46.71 2.827 ;
     RECT  47.916 2.731 49.05 2.827 ;
     RECT  50.184 2.803 58.482 2.827 ;
     RECT  63 2.605 84.618 2.911 ;
     RECT  45.18 2.827 46.71 2.939 ;
     RECT  61.815 2.413 62.097 3.145 ;
     RECT  62.82 2.911 84.618 3.145 ;
     RECT  13.215 2.413 13.497 3.181 ;
     RECT  61.815 3.145 84.618 3.181 ;
     RECT  47.916 2.827 58.482 3.271 ;
     RECT  45.36 2.939 46.71 3.343 ;
     RECT  15.48 2.731 43.83 3.379 ;
     RECT  61.815 3.181 85.302 3.595 ;
     RECT  60.732 3.451 60.75 3.649 ;
     RECT  13.215 3.181 13.59 3.685 ;
     RECT  11.484 2.803 11.502 3.691 ;
     RECT  15.48 3.379 43.866 3.721 ;
     RECT  45.36 3.343 47.142 3.721 ;
     RECT  47.916 3.271 59.13 3.721 ;
     RECT  60.66 3.649 60.75 3.721 ;
     RECT  61.815 3.595 85.41 3.721 ;
     RECT  13.215 3.685 13.914 3.725 ;
     RECT  15.48 3.721 44.406 3.811 ;
     RECT  60.66 3.721 85.698 3.811 ;
     RECT  13.215 3.725 13.497 3.847 ;
     RECT  60.444 3.811 85.698 3.847 ;
     RECT  86.652 2.803 86.742 3.847 ;
     RECT  7.092 2.795 10.71 3.875 ;
     RECT  13.032 3.847 13.497 3.917 ;
     RECT  15.264 3.811 44.406 3.979 ;
     RECT  45.36 3.721 59.13 3.979 ;
     RECT  7.092 3.875 10.494 3.983 ;
     RECT  11.484 3.691 12.114 3.991 ;
     RECT  45.36 3.979 59.49 3.991 ;
     RECT  60.444 3.847 86.742 3.991 ;
     RECT  11.484 3.991 12.258 4.109 ;
     RECT  11.484 4.109 11.862 4.145 ;
     RECT  45.36 3.991 86.742 4.145 ;
     RECT  45.36 4.145 45.897 4.261 ;
     RECT  46.692 4.145 86.742 4.415 ;
     RECT  14.904 3.979 44.406 4.507 ;
     RECT  13.215 3.917 13.497 4.531 ;
     RECT  14.508 4.507 44.406 4.531 ;
     RECT  84.564 4.415 86.742 4.531 ;
     RECT  46.692 4.415 83.697 4.685 ;
     RECT  11.484 4.145 11.574 4.801 ;
     RECT  46.692 4.685 60.138 4.919 ;
     RECT  60.912 4.685 83.697 5.027 ;
     RECT  7.164 3.983 10.494 5.071 ;
     RECT  11.34 4.801 11.574 5.071 ;
     RECT  13.215 4.531 44.406 5.071 ;
     RECT  45.144 4.261 45.897 5.071 ;
     RECT  84.564 4.531 86.778 5.189 ;
     RECT  7.164 5.071 11.574 5.341 ;
     RECT  6.732 5.341 11.61 5.611 ;
     RECT  46.692 4.919 59.958 5.737 ;
     RECT  6.732 5.611 12.114 5.741 ;
     RECT  13.215 5.071 45.897 5.755 ;
     RECT  46.656 5.737 59.958 5.755 ;
     RECT  11.124 5.741 12.114 5.881 ;
     RECT  13.215 5.755 59.958 5.881 ;
     RECT  11.124 5.881 59.958 5.909 ;
     RECT  11.124 5.909 14.706 6.269 ;
     RECT  60.912 5.027 63.342 6.421 ;
     RECT  64.08 5.027 83.697 6.421 ;
     RECT  84.924 5.189 86.778 6.691 ;
     RECT  6.732 5.741 10.242 6.845 ;
     RECT  60.912 6.421 83.697 7.123 ;
     RECT  84.492 6.691 86.778 7.123 ;
     RECT  9.576 6.845 10.242 7.195 ;
     RECT  9.576 7.195 10.314 7.229 ;
     RECT  11.124 6.269 11.718 7.231 ;
     RECT  15.48 5.909 59.958 7.771 ;
     RECT  60.912 7.123 86.778 7.771 ;
     RECT  11.124 7.231 11.79 8.041 ;
     RECT  12.636 6.269 14.706 8.041 ;
     RECT  9.576 7.229 10.278 8.195 ;
     RECT  9.576 8.195 10.134 9.121 ;
     RECT  11.124 8.041 14.706 9.121 ;
     RECT  9.576 9.121 10.17 9.239 ;
     RECT  10.908 9.121 14.706 9.239 ;
     RECT  10.908 9.239 11.826 9.275 ;
     RECT  6.732 6.845 8.838 9.661 ;
     RECT  9.576 9.239 10.134 9.661 ;
     RECT  6.732 9.661 10.134 10.201 ;
     RECT  10.908 9.275 11.79 10.201 ;
     RECT  6.732 10.201 11.79 10.355 ;
     RECT  15.48 7.771 86.778 11.273 ;
     RECT  6.732 10.355 8.838 11.371 ;
     RECT  9.648 10.355 11.79 11.371 ;
     RECT  12.636 9.239 14.706 18.571 ;
     RECT  15.48 11.273 84.51 18.571 ;
     RECT  85.284 11.273 86.778 18.571 ;
     RECT  6.732 11.371 11.79 18.769 ;
     RECT  12.636 18.571 86.778 18.769 ;
     RECT  6.732 18.769 86.778 22.775 ;
     RECT  9.648 22.775 86.778 25.169 ;
     RECT  87.984 15.331 88.002 25.321 ;
     RECT  6.732 22.775 8.838 25.591 ;
     RECT  9.648 25.169 86.742 25.591 ;
     RECT  87.984 25.321 88.038 27.949 ;
     RECT  88.815 2.413 89.097 27.949 ;
     RECT  87.984 27.949 89.097 27.977 ;
     RECT  6.732 25.591 86.742 28.409 ;
     RECT  88.02 27.977 89.097 28.417 ;
     RECT  88.02 28.417 89.262 28.445 ;
     RECT  7.488 28.409 86.742 29.911 ;
     RECT  7.488 29.911 87.246 36.545 ;
     RECT  85.284 36.545 87.246 36.661 ;
     RECT  88.02 28.445 88.038 36.661 ;
     RECT  85.284 36.661 88.038 37.469 ;
     RECT  88.02 37.469 88.038 37.471 ;
     RECT  88.815 28.445 89.262 37.471 ;
     RECT  7.488 36.545 84.51 38.039 ;
     RECT  71.496 38.039 84.51 39.181 ;
     RECT  85.284 37.469 87.246 39.181 ;
     RECT  71.496 39.181 87.246 39.355 ;
     RECT  88.02 37.471 89.262 39.355 ;
     RECT  7.488 38.039 70.758 39.595 ;
     RECT  71.496 39.355 89.262 39.595 ;
     RECT  7.488 39.595 89.262 40.019 ;
     RECT  6.732 28.409 6.75 40.405 ;
     RECT  7.488 40.019 70.758 40.405 ;
     RECT  6.732 40.405 70.758 40.711 ;
     RECT  6.264 40.711 70.758 40.837 ;
     RECT  90.144 40.711 90.162 40.837 ;
     RECT  71.496 40.019 89.262 40.909 ;
     RECT  90.144 40.837 90.198 40.909 ;
     RECT  71.496 40.909 89.334 40.981 ;
     RECT  71.496 40.981 89.37 41.009 ;
     RECT  6.192 40.837 70.758 41.071 ;
     RECT  83.232 41.009 89.37 41.143 ;
     RECT  90.144 40.909 90.378 41.143 ;
     RECT  5.868 41.071 70.758 41.251 ;
     RECT  71.496 41.009 82.458 41.251 ;
     RECT  83.232 41.143 90.378 41.251 ;
     RECT  5.868 41.251 82.458 41.485 ;
     RECT  5.688 41.485 82.458 41.791 ;
     RECT  83.232 41.251 90.666 41.791 ;
     RECT  5.652 41.791 90.882 42.025 ;
     RECT  5.22 42.025 90.882 42.053 ;
     RECT  15.876 42.053 90.882 42.151 ;
     RECT  5.22 42.053 15.102 42.187 ;
     RECT  15.876 42.151 91.062 42.601 ;
     RECT  4.968 42.187 15.102 42.715 ;
     RECT  15.876 42.601 91.134 42.871 ;
     RECT  4.536 42.715 15.102 43.105 ;
     RECT  15.876 42.871 91.962 43.105 ;
     RECT  4.536 43.105 91.962 43.141 ;
     RECT  4.536 43.141 92.142 43.673 ;
     RECT  4.896 43.673 92.142 43.681 ;
     RECT  4.896 43.681 92.358 43.853 ;
     RECT  5.112 43.853 92.358 44.339 ;
     RECT  5.112 44.339 92.214 44.761 ;
     RECT  4.572 44.761 92.214 45.031 ;
     RECT  4.32 45.031 92.214 45.221 ;
     RECT  90.36 45.221 92.214 45.229 ;
     RECT  4.32 45.221 89.478 45.257 ;
     RECT  90.36 45.229 92.25 45.391 ;
     RECT  90.36 45.391 92.538 45.931 ;
     RECT  4.32 45.257 89.406 45.979 ;
     RECT  4.32 45.979 89.55 46.039 ;
     RECT  90.36 45.931 92.646 46.039 ;
     RECT  4.32 46.039 92.646 46.615 ;
     RECT  3.924 46.615 92.646 46.685 ;
     RECT  4.356 46.685 92.646 47.323 ;
     RECT  4.356 47.323 92.718 47.425 ;
     RECT  4.356 47.425 92.754 47.461 ;
     RECT  4.356 47.461 92.862 47.615 ;
     RECT  4.86 47.615 92.862 47.731 ;
     RECT  4.86 47.731 93.078 47.921 ;
     RECT  4.86 47.921 92.646 48.397 ;
     RECT  4.14 48.397 92.646 48.475 ;
     RECT  3.924 48.475 92.646 49.009 ;
     RECT  3.924 49.009 92.79 49.081 ;
     RECT  3.924 49.081 93.078 49.085 ;
     RECT  3.924 49.085 5.274 49.505 ;
     RECT  6.084 49.085 93.078 49.517 ;
     RECT  3.996 49.505 5.274 49.819 ;
     RECT  6.084 49.517 82.494 49.819 ;
     RECT  83.232 49.517 93.078 50.141 ;
     RECT  91.512 50.141 93.078 50.279 ;
     RECT  3.996 49.819 82.494 50.359 ;
     RECT  83.232 50.141 90.594 50.359 ;
     RECT  3.996 50.359 90.594 50.395 ;
     RECT  0.252 50.299 0.27 50.477 ;
     RECT  3.6 50.395 90.594 50.549 ;
     RECT  3.6 50.549 37.53 50.573 ;
     RECT  6.228 50.573 37.53 50.621 ;
     RECT  2.415 2.413 2.697 50.701 ;
     RECT  3.6 50.573 5.166 50.701 ;
     RECT  2.415 50.701 5.166 50.731 ;
     RECT  2.304 50.731 5.166 50.891 ;
     RECT  38.376 50.549 90.594 50.971 ;
     RECT  91.512 50.279 92.97 50.971 ;
     RECT  2.304 50.891 2.697 51.125 ;
     RECT  3.6 50.891 5.166 51.269 ;
     RECT  3.78 51.269 5.166 51.293 ;
     RECT  4.068 51.293 5.166 51.331 ;
     RECT  6.228 50.621 37.458 51.331 ;
     RECT  38.376 50.971 92.97 51.499 ;
     RECT  4.068 51.331 37.458 51.871 ;
     RECT  4.068 51.871 37.602 51.883 ;
     RECT  38.376 51.499 93.294 51.883 ;
     RECT  4.068 51.883 93.294 52.015 ;
     RECT  4.032 52.015 93.294 52.051 ;
     RECT  4.032 52.051 93.366 52.619 ;
     RECT  4.032 52.619 92.898 53.015 ;
     RECT  4.284 53.015 92.898 53.401 ;
     RECT  94.215 2.413 94.497 53.401 ;
     RECT  4.284 53.401 94.497 53.597 ;
     RECT  4.284 53.597 93.186 53.627 ;
     RECT  4.284 53.627 92.79 53.699 ;
     RECT  4.284 53.699 92.574 53.941 ;
     RECT  3.96 53.941 92.574 54.095 ;
     RECT  60.228 54.095 91.026 54.239 ;
     RECT  60.264 54.239 91.026 54.329 ;
     RECT  91.8 54.095 92.574 54.401 ;
     RECT  3.96 54.095 59.346 54.445 ;
     RECT  3.42 54.445 59.346 55.139 ;
     RECT  91.8 54.401 92.502 55.219 ;
     RECT  3.672 55.139 59.346 55.325 ;
     RECT  60.372 54.329 91.026 55.417 ;
     RECT  91.764 55.219 92.502 55.417 ;
     RECT  3.924 55.325 59.346 55.651 ;
     RECT  60.372 55.417 92.502 55.651 ;
     RECT  3.924 55.651 92.502 56.101 ;
     RECT  3.924 56.101 93.114 56.255 ;
     RECT  4.14 56.255 93.114 56.327 ;
     RECT  4.14 56.327 92.718 56.363 ;
     RECT  4.14 56.363 92.322 56.795 ;
     RECT  4.14 56.795 90.846 57.299 ;
     RECT  91.8 56.795 92.322 57.415 ;
     RECT  4.932 57.299 90.846 57.569 ;
     RECT  4.032 57.415 4.05 57.581 ;
     RECT  4.932 57.569 59.562 57.605 ;
     RECT  91.8 57.415 92.43 57.649 ;
     RECT  91.8 57.649 92.934 57.685 ;
     RECT  60.3 57.569 90.846 57.721 ;
     RECT  91.764 57.685 92.934 57.721 ;
     RECT  5.472 57.605 59.562 57.839 ;
     RECT  60.3 57.721 92.934 58.379 ;
     RECT  60.3 58.379 92.466 58.651 ;
     RECT  5.472 57.839 59.346 58.699 ;
     RECT  60.156 58.651 92.466 58.699 ;
     RECT  5.472 58.699 92.466 58.829 ;
     RECT  6.408 58.829 92.466 58.919 ;
     RECT  5.472 58.829 5.67 58.955 ;
     RECT  6.48 58.919 92.466 59.161 ;
     RECT  5.652 58.955 5.67 59.213 ;
     RECT  6.48 59.161 92.646 59.213 ;
     RECT  6.48 59.213 92.466 59.369 ;
     RECT  11.916 59.369 92.466 59.459 ;
     RECT  6.48 59.369 11.178 59.495 ;
     RECT  12.024 59.459 92.286 59.495 ;
     RECT  6.48 59.495 6.498 59.567 ;
     RECT  91.98 59.495 91.998 59.567 ;
     RECT  12.024 59.495 91.242 59.603 ;
     RECT  12.024 59.603 90.63 59.729 ;
     RECT  12.024 59.729 90.45 59.765 ;
     RECT  12.024 59.765 90.234 59.837 ;
     RECT  12.096 59.837 90.234 60.413 ;
     RECT  12.096 60.413 89.802 60.647 ;
     RECT  12.132 60.647 89.802 60.953 ;
     RECT  12.132 60.953 85.662 61.115 ;
     RECT  7.56 59.495 10.89 61.385 ;
     RECT  12.132 61.115 85.59 61.655 ;
     RECT  85.428 61.655 85.59 64.939 ;
     RECT  86.436 60.953 89.802 64.939 ;
     RECT  12.132 61.655 84.69 65.137 ;
     RECT  85.428 64.939 89.802 65.137 ;
     RECT  12.132 65.137 89.802 65.515 ;
     RECT  11.664 65.515 89.802 65.939 ;
     RECT  11.664 65.939 84.834 65.975 ;
     RECT  11.664 65.975 84.69 66.353 ;
     RECT  15.3 66.353 84.69 68.485 ;
     RECT  85.572 65.939 89.802 68.485 ;
     RECT  15.3 68.485 89.802 68.639 ;
     RECT  7.56 61.385 9.306 68.989 ;
     RECT  10.08 61.385 10.89 68.989 ;
     RECT  15.3 68.639 84.69 69.451 ;
     RECT  15.3 69.451 84.726 69.457 ;
     RECT  7.56 68.989 10.89 69.485 ;
     RECT  11.664 66.353 14.526 69.493 ;
     RECT  15.3 69.457 84.834 69.493 ;
     RECT  11.664 69.493 84.834 69.499 ;
     RECT  85.572 68.639 89.802 69.499 ;
     RECT  11.664 69.499 89.802 69.521 ;
     RECT  14.508 69.521 89.802 69.719 ;
     RECT  10.224 69.485 10.89 69.871 ;
     RECT  11.664 69.521 13.662 69.871 ;
     RECT  7.56 69.485 9.342 70.069 ;
     RECT  10.224 69.871 13.662 70.709 ;
     RECT  14.508 69.719 84.69 70.807 ;
     RECT  85.572 69.719 89.802 70.807 ;
     RECT  7.2 70.069 9.342 72.661 ;
     RECT  10.224 70.709 13.554 72.661 ;
     RECT  7.2 72.661 13.554 73.387 ;
     RECT  14.508 70.807 89.802 73.387 ;
     RECT  7.2 73.387 89.802 74.615 ;
     RECT  12.708 74.615 89.802 74.651 ;
     RECT  12.708 74.651 13.95 74.669 ;
     RECT  14.688 74.651 89.802 74.849 ;
     RECT  12.78 74.669 13.95 75.739 ;
     RECT  14.724 74.849 89.802 75.739 ;
     RECT  7.2 74.615 11.97 76.081 ;
     RECT  12.78 75.739 89.802 76.081 ;
     RECT  7.2 76.081 89.802 77.315 ;
     RECT  10.404 77.315 89.802 77.855 ;
     RECT  63.432 77.855 89.802 77.963 ;
     RECT  63.432 77.963 64.242 78.781 ;
     RECT  65.16 77.963 89.802 78.781 ;
     RECT  63.432 78.781 89.802 82.517 ;
     RECT  63.432 82.517 63.99 83.371 ;
     RECT  64.836 82.517 89.802 83.371 ;
     RECT  63.432 83.371 89.802 84.839 ;
     RECT  63.432 84.839 63.846 84.845 ;
     RECT  64.62 84.839 89.802 85.109 ;
     RECT  10.404 77.855 62.694 85.685 ;
     RECT  7.2 77.315 9.666 85.801 ;
     RECT  10.404 85.685 35.334 85.801 ;
     RECT  7.2 85.801 35.334 85.853 ;
     RECT  64.656 85.109 89.802 85.963 ;
     RECT  64.404 85.963 89.802 86.333 ;
     RECT  10.404 85.853 35.334 86.575 ;
     RECT  36.18 85.685 62.694 86.575 ;
     RECT  10.404 86.575 62.694 86.639 ;
     RECT  12.456 86.639 62.694 87.845 ;
     RECT  63.432 84.845 63.522 87.989 ;
     RECT  14.364 87.845 62.694 89.429 ;
     RECT  18 89.429 62.694 89.537 ;
     RECT  7.2 85.853 9.666 90.653 ;
     RECT  7.2 90.653 9.594 91.589 ;
     RECT  18.216 89.537 62.694 91.733 ;
     RECT  32.616 91.733 62.694 91.859 ;
     RECT  7.308 91.589 9.594 92.165 ;
     RECT  32.616 91.859 35.097 92.165 ;
     RECT  35.928 91.859 62.694 92.165 ;
     RECT  35.964 92.165 62.694 92.237 ;
     RECT  36.216 92.237 62.694 92.507 ;
     RECT  39.276 92.507 62.694 92.543 ;
     RECT  7.524 92.165 9.594 93.091 ;
     RECT  10.404 86.639 11.646 93.091 ;
     RECT  36.216 92.507 38.466 93.361 ;
     RECT  39.42 92.543 62.694 93.361 ;
     RECT  14.364 89.429 17.082 93.499 ;
     RECT  18.216 91.733 31.806 93.499 ;
     RECT  14.364 93.499 31.806 93.515 ;
     RECT  33.084 92.165 35.097 93.595 ;
     RECT  36.216 93.361 62.694 93.595 ;
     RECT  33.084 93.595 62.694 93.721 ;
     RECT  63.432 87.989 63.45 93.721 ;
     RECT  7.524 93.091 11.646 93.749 ;
     RECT  17.748 93.515 31.806 93.749 ;
     RECT  33.084 93.721 63.45 93.901 ;
     RECT  14.364 93.515 16.866 93.929 ;
     RECT  64.656 86.333 89.802 93.991 ;
     RECT  17.748 93.749 17.838 94.019 ;
     RECT  15.66 93.929 16.866 94.055 ;
     RECT  32.58 93.901 63.45 94.055 ;
     RECT  14.364 93.929 14.598 94.061 ;
     RECT  36.072 94.055 63.45 94.261 ;
     RECT  64.188 93.991 89.802 94.261 ;
     RECT  12.456 87.845 13.497 94.289 ;
     RECT  14.364 94.061 14.382 94.289 ;
     RECT  36.072 94.261 89.802 94.289 ;
     RECT  7.524 93.749 11.25 94.559 ;
     RECT  12.816 94.289 13.497 94.595 ;
     RECT  36.216 94.289 89.802 94.595 ;
     RECT  36.216 94.595 62.838 94.631 ;
     RECT  32.58 94.055 35.154 94.739 ;
     RECT  77.04 94.595 89.802 94.739 ;
     RECT  2.415 51.125 2.697 94.787 ;
     RECT  13.215 94.595 13.497 94.787 ;
     RECT  32.58 94.739 35.097 94.787 ;
     RECT  94.215 53.597 94.497 94.787 ;
     RECT  18.615 93.749 31.806 94.795 ;
     RECT  32.58 94.787 34.974 94.795 ;
     RECT  15.66 94.055 15.894 94.865 ;
     RECT  16.848 94.055 16.866 94.865 ;
     RECT  18.615 94.795 34.974 94.865 ;
     RECT  36.216 94.631 62.766 94.865 ;
     RECT  64.188 94.595 75.87 94.865 ;
     RECT  77.04 94.739 89.55 94.865 ;
     RECT  33.264 94.865 33.858 94.877 ;
     RECT  64.98 94.865 75.87 94.877 ;
     RECT  30.78 94.865 31.338 94.937 ;
     RECT  33.264 94.877 33.75 94.937 ;
     RECT  43.632 94.865 62.766 94.973 ;
     RECT  20.232 94.865 30.006 95.009 ;
     RECT  30.78 94.937 31.302 95.009 ;
     RECT  64.98 94.877 75.402 95.009 ;
     RECT  20.232 95.009 29.646 95.021 ;
     RECT  77.652 94.865 89.046 95.021 ;
     RECT  2.415 94.787 2.505 95.057 ;
     RECT  13.215 94.787 13.305 95.057 ;
     RECT  18.615 94.865 18.882 95.057 ;
     RECT  94.215 94.787 94.305 95.057 ;
     RECT  18.864 95.057 18.882 95.099 ;
     RECT  38.736 94.865 42.858 95.099 ;
     RECT  52.668 94.973 62.766 95.099 ;
     RECT  75.384 95.009 75.402 95.099 ;
     RECT  27.324 95.021 29.646 95.117 ;
     RECT  87.732 95.021 89.046 95.117 ;
     RECT  32.076 94.865 32.382 95.135 ;
     RECT  43.632 94.973 51.93 95.135 ;
     RECT  62.748 95.099 62.766 95.135 ;
     RECT  7.524 94.559 11.07 95.165 ;
     RECT  27.36 95.117 29.646 95.165 ;
     RECT  43.632 95.135 51.858 95.165 ;
     RECT  64.98 95.009 74.61 95.165 ;
     RECT  87.732 95.117 87.75 95.165 ;
     RECT  34.776 94.865 34.974 95.171 ;
     RECT  36.288 94.865 37.674 95.171 ;
     RECT  52.668 95.099 61.974 95.171 ;
     RECT  52.776 95.171 61.974 95.213 ;
     RECT  70.704 95.165 74.61 95.243 ;
     RECT  32.076 95.135 32.094 95.501 ;
     RECT  36.288 95.171 36.954 95.549 ;
     RECT  52.776 95.213 58.05 95.645 ;
     RECT  20.304 95.021 26.586 95.741 ;
     RECT  58.788 95.213 61.974 95.741 ;
     RECT  64.98 95.165 69.462 95.741 ;
     RECT  52.776 95.645 57.798 95.789 ;
     RECT  58.788 95.741 61.794 95.789 ;
     RECT  64.98 95.741 68.706 95.789 ;
     RECT  71.172 95.243 74.61 95.789 ;
     RECT  77.652 95.021 86.922 95.789 ;
     RECT  38.736 95.099 42.75 95.837 ;
     RECT  52.92 95.789 57.798 95.837 ;
     RECT  77.652 95.789 85.806 95.837 ;
     RECT  53.424 95.837 57.798 95.885 ;
     RECT  30.852 95.009 31.302 96.029 ;
     RECT  33.264 94.937 33.282 96.077 ;
     RECT  34.956 95.171 34.974 96.125 ;
     RECT  38.736 95.837 42.39 96.221 ;
     RECT  7.524 95.165 9.558 96.317 ;
     RECT  27.36 95.165 29.574 96.317 ;
     RECT  43.632 95.165 51.714 96.317 ;
     RECT  53.892 95.885 57.798 96.317 ;
     RECT  64.98 95.789 68.454 96.317 ;
     RECT  69.444 95.741 69.462 96.317 ;
     RECT  77.652 95.837 85.518 96.317 ;
     RECT  86.652 95.789 86.886 96.317 ;
     RECT  10.404 95.165 10.422 96.365 ;
     RECT  20.304 95.741 26.37 96.365 ;
     RECT  27.36 96.317 29.214 96.365 ;
     RECT  53.892 96.317 55.566 96.365 ;
     RECT  58.788 95.789 61.614 96.365 ;
     RECT  64.188 94.865 64.206 96.365 ;
     RECT  64.98 96.317 66.402 96.365 ;
     RECT  71.352 95.789 74.61 96.365 ;
     RECT  77.652 96.317 80.082 96.365 ;
     RECT  80.856 96.317 85.338 96.365 ;
     RECT  20.52 96.365 20.97 96.413 ;
     RECT  27.36 96.365 28.782 96.413 ;
     RECT  39.456 96.221 42.39 96.413 ;
     RECT  43.632 96.317 51.606 96.413 ;
     RECT  54 96.365 54.414 96.413 ;
     RECT  64.98 96.365 66.006 96.413 ;
     RECT  67.356 96.317 68.454 96.413 ;
     RECT  80.856 96.365 85.23 96.413 ;
     RECT  21.708 96.365 24.786 96.461 ;
     RECT  39.456 96.413 40.014 96.461 ;
     RECT  41.076 96.413 42.39 96.461 ;
     RECT  47.772 96.413 51.606 96.461 ;
     RECT  54.18 96.413 54.414 96.461 ;
     RECT  56.952 96.317 57.798 96.461 ;
     RECT  58.824 96.365 61.614 96.461 ;
     RECT  78.516 96.365 80.082 96.461 ;
     RECT  80.856 96.413 83.106 96.461 ;
     RECT  20.772 96.413 20.79 96.509 ;
     RECT  49.284 96.461 51.606 96.509 ;
     RECT  59.148 96.461 60.786 96.509 ;
     RECT  78.66 96.461 80.082 96.509 ;
     RECT  21.744 96.461 24.498 96.557 ;
     RECT  39.456 96.461 39.978 96.557 ;
     RECT  49.284 96.509 50.814 96.557 ;
     RECT  71.388 96.365 74.61 96.557 ;
     RECT  39.96 96.557 39.978 96.605 ;
     RECT  73.476 96.557 74.61 96.845 ;
     RECT  71.388 96.557 72.558 96.893 ;
     RECT  27.36 96.413 28.278 96.941 ;
     RECT  21.888 96.557 24.498 97.037 ;
     RECT  27.504 96.941 28.278 97.037 ;
     RECT  43.956 96.413 46.998 97.037 ;
     RECT  49.284 96.557 50.67 97.037 ;
     RECT  67.68 96.413 68.454 97.037 ;
     RECT  78.804 96.509 80.082 97.037 ;
     RECT  80.856 96.461 82.638 97.037 ;
     RECT  84.096 96.413 85.23 97.037 ;
     RECT  42.192 96.461 42.39 97.051 ;
     RECT  86.652 96.317 86.67 97.051 ;
     RECT  7.704 96.317 9.558 97.085 ;
     RECT  21.888 97.037 21.906 97.085 ;
     RECT  22.752 97.037 24.498 97.085 ;
     RECT  25.632 96.365 25.65 97.085 ;
     RECT  27.648 97.037 27.666 97.085 ;
     RECT  30.852 96.029 30.87 97.085 ;
     RECT  41.076 96.461 41.454 97.085 ;
     RECT  43.956 97.037 46.854 97.085 ;
     RECT  47.772 96.461 48.51 97.085 ;
     RECT  49.284 97.037 49.302 97.085 ;
     RECT  50.4 97.037 50.67 97.085 ;
     RECT  51.588 96.509 51.606 97.085 ;
     RECT  54.396 96.461 54.414 97.085 ;
     RECT  55.368 96.365 55.566 97.085 ;
     RECT  56.952 96.461 56.97 97.085 ;
     RECT  57.78 96.461 57.798 97.085 ;
     RECT  59.148 96.509 59.166 97.085 ;
     RECT  59.904 96.509 60.786 97.085 ;
     RECT  61.596 96.461 61.614 97.085 ;
     RECT  65.052 96.413 66.006 97.085 ;
     RECT  67.68 97.037 67.698 97.085 ;
     RECT  68.436 97.037 68.454 97.085 ;
     RECT  71.388 96.893 72.342 97.085 ;
     RECT  73.476 96.845 74.25 97.085 ;
     RECT  77.724 96.365 77.742 97.085 ;
     RECT  78.876 97.037 80.082 97.085 ;
     RECT  80.856 97.037 82.314 97.085 ;
     RECT  84.456 97.037 85.23 97.085 ;
     RECT  86.076 97.051 86.67 97.085 ;
     RECT  36.288 95.549 36.846 97.133 ;
     RECT  42.192 97.051 42.57 97.133 ;
     RECT  36.288 97.133 36.306 97.181 ;
     RECT  42.552 97.133 42.57 97.181 ;
     RECT  60.12 97.085 60.138 97.181 ;
     RECT  65.988 97.085 66.006 97.181 ;
     RECT  70.164 97.051 70.182 97.181 ;
     RECT  73.476 97.085 73.494 97.181 ;
     RECT  74.232 97.085 74.25 97.181 ;
     RECT  79.524 97.085 79.542 97.181 ;
     RECT  86.076 97.085 86.094 97.181 ;
     RECT  89.028 95.117 89.046 97.181 ;
    LAYER M4 ;
     RECT  0.06 50.352 0.133 50.568 ;
     RECT  0.133 50.352 0.241 50.76 ;
     RECT  0.133 48.72 2.408 48.744 ;
     RECT  0.241 50.304 2.408 50.76 ;
     RECT  2.408 2.148 2.512 95.052 ;
     RECT  2.512 2.418 2.704 94.782 ;
     RECT  2.704 50.16 3.769 50.568 ;
     RECT  3.769 50.16 3.781 51.288 ;
     RECT  2.704 48.72 3.913 48.744 ;
     RECT  3.913 46.656 3.973 46.68 ;
     RECT  2.704 55.296 3.985 55.32 ;
     RECT  3.973 46.656 4.019 46.776 ;
     RECT  3.985 55.296 4.021 55.704 ;
     RECT  3.781 50.16 4.057 52.056 ;
     RECT  4.019 46.752 4.345 46.776 ;
     RECT  3.913 48.48 4.345 48.744 ;
     RECT  4.345 46.752 4.453 48.744 ;
     RECT  4.057 50.064 4.453 52.344 ;
     RECT  4.021 54.096 4.489 55.704 ;
     RECT  4.021 57.552 4.489 57.576 ;
     RECT  4.453 46.752 4.501 52.344 ;
     RECT  4.489 54.096 4.547 57.576 ;
     RECT  4.501 46.752 4.705 52.728 ;
     RECT  4.489 45.456 4.885 45.48 ;
     RECT  4.885 43.824 4.933 43.848 ;
     RECT  4.525 42.72 4.957 42.744 ;
     RECT  4.705 46.752 5.173 53.112 ;
     RECT  4.547 54.096 5.173 54.12 ;
     RECT  4.933 43.824 5.209 44.376 ;
     RECT  4.885 45.456 5.209 45.576 ;
     RECT  4.957 42.192 5.245 42.744 ;
     RECT  5.209 43.824 5.245 45.576 ;
     RECT  5.245 42.192 5.249 45.576 ;
     RECT  5.173 46.752 5.249 54.12 ;
     RECT  5.249 42.192 5.267 45.048 ;
     RECT  5.249 46.752 5.701 51.48 ;
     RECT  5.267 42.192 5.713 45 ;
     RECT  4.547 55.68 5.713 57.576 ;
     RECT  5.713 41.712 5.747 45 ;
     RECT  5.249 52.512 5.857 54.12 ;
     RECT  5.713 55.68 5.857 57.864 ;
     RECT  5.747 41.712 6.077 42.792 ;
     RECT  5.701 46.176 6.227 51.48 ;
     RECT  5.747 43.824 6.277 45 ;
     RECT  5.641 59.184 6.277 59.208 ;
     RECT  6.227 48.72 6.289 51.48 ;
     RECT  5.857 52.512 6.289 57.864 ;
     RECT  6.289 48.72 6.325 57.864 ;
     RECT  6.277 58.896 6.325 59.208 ;
     RECT  6.277 43.824 6.469 45.192 ;
     RECT  6.227 46.176 6.469 47.736 ;
     RECT  6.325 48.72 6.563 59.208 ;
     RECT  6.563 48.72 6.659 54.168 ;
     RECT  6.659 52.176 6.707 54.168 ;
     RECT  6.563 55.536 6.797 59.208 ;
     RECT  6.077 42.24 6.805 42.792 ;
     RECT  6.469 43.824 6.805 47.736 ;
     RECT  6.853 2.304 6.949 2.328 ;
     RECT  6.253 41.136 7.225 41.16 ;
     RECT  6.805 42.24 7.225 47.736 ;
     RECT  7.333 5.136 7.477 5.16 ;
     RECT  7.429 96.288 7.621 96.312 ;
     RECT  7.525 95.136 7.657 95.16 ;
     RECT  7.477 13.68 7.693 13.704 ;
     RECT  6.949 1.728 7.808 2.328 ;
     RECT  7.477 5.136 7.808 5.88 ;
     RECT  7.477 7.392 7.808 7.416 ;
     RECT  7.693 13.584 7.808 13.704 ;
     RECT  7.189 20.928 7.808 20.952 ;
     RECT  7.657 26.64 7.808 26.664 ;
     RECT  6.901 28.272 7.808 28.296 ;
     RECT  7.225 41.136 7.808 47.736 ;
     RECT  6.659 48.72 7.808 50.904 ;
     RECT  6.707 52.512 7.808 54.168 ;
     RECT  6.797 55.536 7.808 58.92 ;
     RECT  7.657 95.136 7.808 95.256 ;
     RECT  7.808 1.728 8.005 95.256 ;
     RECT  7.621 96.288 8.005 97.08 ;
     RECT  7.237 0.096 8.053 0.12 ;
     RECT  8.053 0.096 8.101 0.168 ;
     RECT  8.005 1.728 8.104 97.08 ;
     RECT  8.104 47.088 8.165 57.528 ;
     RECT  8.101 0.096 8.243 0.312 ;
     RECT  8.104 1.728 8.243 3.432 ;
     RECT  8.104 25.872 8.243 28.296 ;
     RECT  8.104 11.424 8.309 13.608 ;
     RECT  8.104 94.56 8.345 97.08 ;
     RECT  8.104 58.512 8.381 58.776 ;
     RECT  8.309 12 8.387 13.608 ;
     RECT  8.243 25.872 8.417 25.896 ;
     RECT  8.104 4.896 8.435 6.84 ;
     RECT  8.387 12.576 8.435 13.608 ;
     RECT  8.243 1.728 8.453 3.192 ;
     RECT  8.435 4.896 8.531 6.792 ;
     RECT  8.435 12.576 8.531 12.6 ;
     RECT  8.165 47.28 8.531 57.528 ;
     RECT  8.531 4.896 8.597 6.264 ;
     RECT  8.104 93.504 8.771 93.528 ;
     RECT  8.597 4.896 8.813 5.88 ;
     RECT  8.104 40.992 8.813 45.24 ;
     RECT  8.531 47.28 8.813 51.24 ;
     RECT  8.243 27.312 8.921 28.296 ;
     RECT  8.381 58.608 8.957 58.776 ;
     RECT  8.813 47.424 8.963 51.24 ;
     RECT  8.813 42.24 8.993 45.24 ;
     RECT  8.963 48.48 9.029 51.24 ;
     RECT  8.993 43.248 9.097 45.24 ;
     RECT  8.957 58.656 9.137 58.776 ;
     RECT  8.813 40.992 9.241 41.16 ;
     RECT  8.345 94.56 9.241 95.16 ;
     RECT  8.453 1.728 9.389 3 ;
     RECT  8.531 52.512 9.395 57.528 ;
     RECT  9.241 40.8 9.421 41.16 ;
     RECT  8.921 27.648 9.493 28.296 ;
     RECT  8.345 96.288 9.533 97.08 ;
     RECT  9.395 52.56 9.539 57.528 ;
     RECT  9.533 96.336 9.569 97.08 ;
     RECT  8.104 20.928 9.637 20.952 ;
     RECT  9.539 52.56 9.677 54.696 ;
     RECT  9.601 10.224 9.683 10.248 ;
     RECT  8.435 13.584 9.683 13.608 ;
     RECT  8.104 15.696 9.683 15.72 ;
     RECT  9.601 18.624 9.683 18.648 ;
     RECT  9.637 20.928 9.683 21.048 ;
     RECT  9.529 22.464 9.683 22.488 ;
     RECT  9.097 43.248 9.731 45.576 ;
     RECT  9.241 94.512 9.733 95.16 ;
     RECT  9.541 85.824 9.749 85.848 ;
     RECT  9.389 1.728 9.785 2.952 ;
     RECT  8.813 4.896 9.785 4.92 ;
     RECT  9.677 52.56 9.821 53.88 ;
     RECT  9.493 27.648 9.853 29.208 ;
     RECT  9.421 40.608 9.853 41.16 ;
     RECT  8.993 42.24 9.853 42.264 ;
     RECT  9.853 27.648 9.877 30.168 ;
     RECT  9.877 27.648 9.889 30.312 ;
     RECT  9.853 31.392 9.889 31.416 ;
     RECT  9.733 94.032 9.925 95.16 ;
     RECT  8.243 0.096 9.929 0.12 ;
     RECT  9.731 44.88 9.961 45.576 ;
     RECT  8.963 47.424 9.961 47.496 ;
     RECT  9.029 48.48 9.961 51 ;
     RECT  9.785 1.728 9.965 2.328 ;
     RECT  9.205 34.08 9.973 34.104 ;
     RECT  8.104 77.808 10.069 77.832 ;
     RECT  9.961 44.88 10.105 51 ;
     RECT  9.137 58.656 10.141 58.68 ;
     RECT  9.889 35.664 10.177 35.688 ;
     RECT  9.965 2.304 10.217 2.328 ;
     RECT  9.973 33.504 10.249 34.104 ;
     RECT  10.177 35.424 10.249 35.688 ;
     RECT  9.889 27.648 10.321 31.416 ;
     RECT  10.249 33.504 10.405 35.88 ;
     RECT  10.405 33.36 10.429 35.88 ;
     RECT  9.569 96.336 10.451 96.36 ;
     RECT  10.429 33.36 10.501 36.12 ;
     RECT  10.105 44.88 10.501 51.288 ;
     RECT  10.357 39.312 10.573 39.336 ;
     RECT  9.539 56.112 10.573 57.528 ;
     RECT  10.321 27.648 10.577 32.232 ;
     RECT  10.577 31.392 10.645 32.232 ;
     RECT  10.501 33.264 10.645 36.12 ;
     RECT  10.573 38.976 10.649 39.336 ;
     RECT  10.577 27.648 10.681 30.312 ;
     RECT  10.429 37.584 10.693 37.608 ;
     RECT  10.649 38.976 10.693 39 ;
     RECT  10.573 55.824 10.717 57.528 ;
     RECT  10.141 58.656 10.717 59.256 ;
     RECT  10.681 27.312 10.753 30.312 ;
     RECT  10.501 44.88 10.753 51.384 ;
     RECT  9.821 52.56 10.753 53.688 ;
     RECT  9.731 43.248 10.789 43.896 ;
     RECT  10.753 44.88 10.789 53.688 ;
     RECT  10.717 54.864 10.789 59.256 ;
     RECT  10.693 37.584 10.825 39 ;
     RECT  10.789 54.816 10.837 59.256 ;
     RECT  10.309 87.168 10.865 87.192 ;
     RECT  10.645 31.392 10.901 36.12 ;
     RECT  10.837 54.72 10.969 59.256 ;
     RECT  9.925 93.984 10.973 95.16 ;
     RECT  10.973 94.032 11.081 95.16 ;
     RECT  9.683 21.024 11.257 21.048 ;
     RECT  9.853 40.608 11.257 42.264 ;
     RECT  10.789 43.248 11.257 53.688 ;
     RECT  10.213 79.728 11.261 79.752 ;
     RECT  11.257 40.608 11.293 53.688 ;
     RECT  10.969 54.672 11.297 59.256 ;
     RECT  11.293 40.464 11.365 53.688 ;
     RECT  10.753 26.736 11.405 30.312 ;
     RECT  10.117 84.336 11.405 84.36 ;
     RECT  11.257 20.544 11.411 21.048 ;
     RECT  11.405 29.472 11.459 30.312 ;
     RECT  11.401 24.72 11.473 24.744 ;
     RECT  11.459 29.568 11.549 30.312 ;
     RECT  11.297 56.112 11.557 59.256 ;
     RECT  11.365 40.416 11.617 53.688 ;
     RECT  11.297 54.672 11.617 54.984 ;
     RECT  10.901 33.6 11.621 36.12 ;
     RECT  11.557 56.112 11.621 59.448 ;
     RECT  10.825 37.104 11.653 39 ;
     RECT  10.285 7.2 11.689 7.224 ;
     RECT  11.689 6.816 11.725 7.224 ;
     RECT  11.549 29.616 11.725 30.312 ;
     RECT  10.901 31.392 11.725 32.472 ;
     RECT  11.725 29.616 11.747 32.472 ;
     RECT  11.725 6.816 11.749 7.944 ;
     RECT  11.749 6.816 11.795 8.568 ;
     RECT  10.393 5.472 11.797 5.736 ;
     RECT  11.795 6.816 11.797 7.464 ;
     RECT  9.745 23.664 11.833 23.688 ;
     RECT  11.473 24.72 11.833 25.56 ;
     RECT  11.797 5.472 11.843 7.464 ;
     RECT  11.621 33.792 11.869 36.12 ;
     RECT  11.653 37.104 11.869 39.24 ;
     RECT  11.833 23.664 11.977 25.56 ;
     RECT  11.405 26.736 11.977 28.44 ;
     RECT  11.869 33.792 11.977 39.24 ;
     RECT  11.977 33.792 12.121 39.336 ;
     RECT  11.617 40.416 12.121 54.984 ;
     RECT  11.843 5.472 12.125 6.264 ;
     RECT  12.125 5.472 12.131 5.736 ;
     RECT  11.795 8.544 12.161 8.568 ;
     RECT  11.977 23.664 12.229 28.44 ;
     RECT  12.229 80.64 12.373 80.664 ;
     RECT  11.411 21.024 12.445 21.048 ;
     RECT  12.445 21.024 12.469 21.096 ;
     RECT  12.229 23.136 12.469 28.44 ;
     RECT  11.621 59.424 12.625 59.448 ;
     RECT  12.229 79.056 12.661 79.08 ;
     RECT  12.469 21.024 12.697 28.44 ;
     RECT  11.747 29.616 12.697 31.944 ;
     RECT  12.121 33.792 12.709 54.984 ;
     RECT  12.085 86.592 12.733 87.24 ;
     RECT  12.085 3.696 12.757 3.72 ;
     RECT  12.709 33.552 12.757 54.984 ;
     RECT  11.621 56.112 12.757 58.152 ;
     RECT  12.757 33.552 12.769 58.152 ;
     RECT  12.697 21.024 12.853 31.944 ;
     RECT  12.769 33.072 12.853 58.152 ;
     RECT  12.373 80.64 12.913 82.536 ;
     RECT  12.853 21.024 12.949 58.152 ;
     RECT  12.625 59.232 12.949 59.448 ;
     RECT  12.697 74.64 12.949 74.664 ;
     RECT  12.913 80.64 12.985 83.064 ;
     RECT  12.949 74.64 13.045 75.384 ;
     RECT  13.045 73.968 13.057 75.384 ;
     RECT  10.069 77.616 13.093 77.832 ;
     RECT  12.661 79.056 13.093 79.32 ;
     RECT  12.913 85.104 13.165 85.128 ;
     RECT  12.757 3.696 13.208 3.912 ;
     RECT  12.131 5.472 13.208 5.592 ;
     RECT  11.365 18.96 13.208 18.984 ;
     RECT  12.949 21.024 13.208 59.448 ;
     RECT  13.057 73.872 13.208 75.384 ;
     RECT  12.949 76.464 13.208 76.488 ;
     RECT  13.093 77.616 13.208 79.32 ;
     RECT  12.985 80.304 13.208 83.064 ;
     RECT  13.165 84.336 13.208 85.128 ;
     RECT  12.733 86.304 13.208 87.24 ;
     RECT  11.081 94.032 13.208 94.584 ;
     RECT  13.208 2.148 13.312 95.052 ;
     RECT  13.312 2.418 13.504 94.782 ;
     RECT  13.504 26.736 13.601 30.984 ;
     RECT  13.504 73.392 13.601 74.616 ;
     RECT  13.601 26.736 13.619 30.936 ;
     RECT  13.504 20.448 13.667 25.608 ;
     RECT  13.504 38.64 13.667 45.72 ;
     RECT  13.504 46.8 13.667 60.312 ;
     RECT  13.504 75.6 13.709 87.528 ;
     RECT  13.667 20.448 13.763 22.824 ;
     RECT  13.504 32.448 13.853 37.608 ;
     RECT  13.619 26.736 13.859 30.888 ;
     RECT  13.709 75.792 13.889 87.528 ;
     RECT  13.504 3.696 13.925 3.72 ;
     RECT  13.889 76.32 14.051 87.528 ;
     RECT  13.853 32.592 14.069 37.608 ;
     RECT  13.859 26.784 14.213 30.888 ;
     RECT  14.213 26.784 14.285 30.408 ;
     RECT  13.667 38.64 14.285 42.024 ;
     RECT  13.667 46.8 14.291 49.08 ;
     RECT  14.051 81.456 14.357 87.528 ;
     RECT  14.291 46.8 14.465 48.984 ;
     RECT  13.667 50.064 14.483 60.312 ;
     RECT  14.051 76.32 14.483 80.472 ;
     RECT  13.504 5.472 14.497 5.592 ;
     RECT  14.483 79.056 14.501 80.472 ;
     RECT  13.601 73.392 14.569 74.376 ;
     RECT  14.465 48.384 14.573 48.984 ;
     RECT  13.504 94.032 14.609 94.056 ;
     RECT  14.569 73.392 14.645 74.616 ;
     RECT  14.645 73.44 14.677 74.616 ;
     RECT  14.285 27.264 14.681 30.408 ;
     RECT  13.763 22.752 14.713 22.824 ;
     RECT  13.667 23.856 14.713 25.608 ;
     RECT  14.677 73.44 14.713 74.808 ;
     RECT  14.497 4.512 14.861 5.592 ;
     RECT  14.483 53.856 14.867 60.312 ;
     RECT  14.357 85.104 14.867 87.528 ;
     RECT  14.861 4.512 14.893 5.496 ;
     RECT  14.069 32.592 14.893 36.312 ;
     RECT  14.713 73.44 14.893 75.192 ;
     RECT  14.483 76.32 14.893 77.736 ;
     RECT  14.069 37.344 14.929 37.608 ;
     RECT  14.285 38.64 14.929 39.864 ;
     RECT  14.893 3.984 14.933 5.496 ;
     RECT  14.867 56.88 14.965 60.312 ;
     RECT  14.713 22.752 15.001 25.608 ;
     RECT  13.667 43.104 15.109 45.72 ;
     RECT  14.465 46.8 15.109 47.352 ;
     RECT  14.893 31.68 15.185 36.312 ;
     RECT  13.763 20.448 15.253 21.672 ;
     RECT  15.001 22.752 15.253 25.992 ;
     RECT  14.483 50.064 15.253 52.824 ;
     RECT  13.504 18.576 15.349 18.984 ;
     RECT  14.929 37.344 15.349 39.864 ;
     RECT  14.285 40.848 15.349 42.024 ;
     RECT  14.501 79.104 15.349 80.472 ;
     RECT  14.357 81.456 15.349 84.12 ;
     RECT  15.349 18.576 15.365 19.464 ;
     RECT  15.109 43.104 15.395 47.352 ;
     RECT  15.185 31.872 15.397 36.312 ;
     RECT  15.349 37.344 15.397 42.024 ;
     RECT  15.349 79.104 15.401 84.12 ;
     RECT  14.681 27.264 15.433 30.36 ;
     RECT  15.397 31.872 15.443 42.024 ;
     RECT  15.401 81.6 15.445 84.12 ;
     RECT  14.867 85.104 15.445 87.48 ;
     RECT  15.253 20.448 15.469 25.992 ;
     RECT  15.433 27.024 15.469 30.36 ;
     RECT  15.443 31.872 15.545 37.608 ;
     RECT  15.545 31.872 15.581 32.616 ;
     RECT  15.443 38.64 15.581 42.024 ;
     RECT  15.253 49.824 15.649 52.824 ;
     RECT  14.867 53.856 15.649 55.896 ;
     RECT  14.965 56.88 15.649 60.456 ;
     RECT  15.217 72.24 15.649 72.264 ;
     RECT  15.649 71.472 15.721 72.264 ;
     RECT  14.893 73.44 15.721 77.736 ;
     RECT  15.469 20.448 15.731 30.36 ;
     RECT  15.649 56.88 15.731 60.984 ;
     RECT  15.731 25.968 15.757 30.36 ;
     RECT  15.757 25.968 15.827 30.696 ;
     RECT  15.721 71.472 15.829 77.736 ;
     RECT  15.445 81.6 15.875 87.48 ;
     RECT  15.401 79.104 15.877 80.52 ;
     RECT  15.829 71.232 15.901 77.736 ;
     RECT  15.877 79.056 15.901 80.52 ;
     RECT  15.365 18.768 15.937 19.464 ;
     RECT  15.731 20.448 15.937 24.696 ;
     RECT  15.901 71.232 15.971 80.52 ;
     RECT  15.827 27.12 16.009 30.696 ;
     RECT  15.589 93.504 16.049 93.528 ;
     RECT  16.045 2.304 16.069 2.328 ;
     RECT  15.581 38.928 16.081 42.024 ;
     RECT  15.395 43.104 16.081 47.256 ;
     RECT  15.875 81.84 16.081 87.48 ;
     RECT  15.971 71.232 16.085 77.832 ;
     RECT  16.081 81.84 16.085 87.576 ;
     RECT  14.573 48.384 16.153 48.84 ;
     RECT  15.649 49.824 16.153 55.896 ;
     RECT  15.865 7.392 16.163 7.416 ;
     RECT  16.117 9.936 16.163 9.96 ;
     RECT  16.069 2.304 16.165 2.424 ;
     RECT  16.085 71.232 16.229 74.088 ;
     RECT  16.165 1.728 16.261 2.424 ;
     RECT  16.085 81.936 16.261 87.576 ;
     RECT  16.081 38.928 16.265 47.256 ;
     RECT  14.933 3.984 16.357 4.008 ;
     RECT  14.933 5.472 16.357 5.496 ;
     RECT  15.545 33.6 16.441 37.608 ;
     RECT  16.153 48.384 16.441 55.896 ;
     RECT  15.937 18.768 16.445 24.696 ;
     RECT  16.265 43.104 16.453 47.256 ;
     RECT  16.441 48.24 16.453 55.896 ;
     RECT  16.085 75.12 16.481 77.832 ;
     RECT  16.261 1.728 16.501 2.904 ;
     RECT  16.357 3.984 16.501 5.496 ;
     RECT  15.757 11.376 16.517 11.4 ;
     RECT  16.229 71.472 16.517 74.088 ;
     RECT  16.445 18.768 16.547 21.432 ;
     RECT  16.261 81.936 16.547 88.104 ;
     RECT  16.481 75.12 16.553 77.736 ;
     RECT  16.453 43.104 16.589 55.896 ;
     RECT  15.581 31.872 16.693 32.52 ;
     RECT  16.441 33.6 16.693 37.896 ;
     RECT  15.731 56.88 16.729 60.456 ;
     RECT  16.589 48.24 16.765 55.896 ;
     RECT  16.729 56.88 16.765 60.984 ;
     RECT  16.009 27.12 16.801 30.84 ;
     RECT  16.693 31.872 16.801 37.896 ;
     RECT  15.971 79.296 16.801 80.52 ;
     RECT  16.765 48.24 16.873 60.984 ;
     RECT  16.589 43.104 16.883 47.064 ;
     RECT  16.117 8.448 16.909 8.472 ;
     RECT  15.827 25.968 16.909 25.992 ;
     RECT  16.801 27.12 16.909 37.896 ;
     RECT  16.909 8.448 16.979 8.568 ;
     RECT  15.685 62.016 17.027 62.04 ;
     RECT  16.547 81.936 17.057 87.816 ;
     RECT  16.873 48.24 17.077 61.032 ;
     RECT  16.909 25.968 17.125 37.896 ;
     RECT  16.265 38.928 17.125 42.072 ;
     RECT  16.801 79.296 17.233 80.568 ;
     RECT  17.125 25.968 17.273 42.072 ;
     RECT  16.801 6.816 17.305 6.84 ;
     RECT  17.273 25.968 17.305 30.456 ;
     RECT  17.017 88.944 17.305 88.968 ;
     RECT  17.233 9.696 17.315 9.72 ;
     RECT  16.445 22.56 17.315 24.696 ;
     RECT  17.077 48.24 17.381 61.704 ;
     RECT  17.305 25.776 17.411 30.456 ;
     RECT  16.979 8.448 17.521 8.472 ;
     RECT  17.305 6.816 17.557 6.936 ;
     RECT  17.521 7.968 17.557 8.472 ;
     RECT  16.883 43.152 17.557 47.064 ;
     RECT  17.381 48.24 17.557 56.52 ;
     RECT  17.557 6.768 17.561 8.472 ;
     RECT  16.517 71.472 17.593 73.368 ;
     RECT  17.411 30 17.597 30.456 ;
     RECT  16.547 18.96 17.605 21.432 ;
     RECT  16.553 75.12 17.605 77.592 ;
     RECT  17.605 75.024 17.629 77.592 ;
     RECT  17.233 78.912 17.629 80.568 ;
     RECT  17.629 75.024 17.653 80.568 ;
     RECT  17.057 81.936 17.653 82.728 ;
     RECT  17.057 83.712 17.845 87.816 ;
     RECT  17.305 88.944 17.845 89.16 ;
     RECT  16.501 1.728 18.025 5.496 ;
     RECT  17.593 71.472 18.025 73.848 ;
     RECT  17.653 75.024 18.025 80.856 ;
     RECT  17.381 57.6 18.037 61.704 ;
     RECT  17.605 18 18.061 21.432 ;
     RECT  17.315 22.56 18.061 24.504 ;
     RECT  17.273 31.488 18.133 42.072 ;
     RECT  17.557 43.152 18.133 56.52 ;
     RECT  18.025 71.472 18.181 80.856 ;
     RECT  17.653 81.84 18.181 82.728 ;
     RECT  17.449 69.504 18.241 69.528 ;
     RECT  18.181 71.472 18.277 82.728 ;
     RECT  18.037 57.6 18.421 61.896 ;
     RECT  18.277 71.184 18.457 82.728 ;
     RECT  17.845 83.712 18.457 89.16 ;
     RECT  18.421 57.552 18.469 61.896 ;
     RECT  18.025 1.728 18.608 5.64 ;
     RECT  17.561 6.768 18.608 7.992 ;
     RECT  18.169 11.424 18.608 11.448 ;
     RECT  16.981 15.312 18.608 15.336 ;
     RECT  18.061 18 18.608 24.504 ;
     RECT  17.411 25.776 18.608 29.016 ;
     RECT  17.597 30.144 18.608 30.456 ;
     RECT  18.133 31.488 18.608 56.52 ;
     RECT  18.469 57.552 18.608 62.184 ;
     RECT  16.981 64.992 18.608 65.016 ;
     RECT  18.241 69.264 18.608 69.528 ;
     RECT  18.457 71.184 18.608 89.16 ;
     RECT  17.737 93.504 18.608 93.528 ;
     RECT  18.421 0.144 18.611 0.168 ;
     RECT  18.608 1.728 18.712 95.052 ;
     RECT  18.712 1.728 18.904 94.782 ;
     RECT  18.904 74.88 18.929 90.504 ;
     RECT  18.904 1.728 19.001 4.056 ;
     RECT  18.904 31.392 19.001 46.152 ;
     RECT  19.001 1.824 19.037 4.056 ;
     RECT  18.757 0.096 19.073 0.12 ;
     RECT  18.904 18.96 19.109 30.408 ;
     RECT  18.929 74.88 19.109 80.904 ;
     RECT  19.109 74.928 19.139 80.904 ;
     RECT  18.904 14.784 19.181 16.152 ;
     RECT  19.181 15.312 19.379 16.152 ;
     RECT  18.904 17.664 19.379 17.688 ;
     RECT  19.001 31.392 19.379 42.792 ;
     RECT  19.379 33.936 19.397 42.792 ;
     RECT  18.904 47.664 19.433 51.48 ;
     RECT  18.904 52.464 19.433 54.744 ;
     RECT  19.109 18.96 19.469 25.416 ;
     RECT  19.001 43.872 19.475 46.152 ;
     RECT  19.433 52.464 19.505 54.648 ;
     RECT  19.433 47.664 19.541 48.744 ;
     RECT  19.505 52.464 19.541 52.776 ;
     RECT  18.904 5.472 19.577 6.312 ;
     RECT  19.469 18.96 19.721 24.936 ;
     RECT  19.475 43.872 19.721 45.72 ;
     RECT  19.037 2.304 19.897 4.056 ;
     RECT  19.577 5.472 19.897 5.928 ;
     RECT  18.904 58.656 19.897 62.76 ;
     RECT  19.397 37.584 19.901 42.792 ;
     RECT  18.904 68.352 19.933 73.8 ;
     RECT  19.897 58.128 19.957 62.76 ;
     RECT  18.904 64.176 19.957 65.016 ;
     RECT  19.957 58.128 20.003 65.016 ;
     RECT  18.904 11.424 20.045 11.448 ;
     RECT  19.721 20.592 20.045 24.936 ;
     RECT  19.397 33.936 20.045 36.504 ;
     RECT  19.933 67.968 20.053 73.8 ;
     RECT  19.139 74.976 20.053 80.904 ;
     RECT  18.929 81.936 20.053 90.504 ;
     RECT  19.721 43.872 20.081 44.088 ;
     RECT  20.053 74.976 20.099 90.504 ;
     RECT  18.904 55.728 20.149 57.048 ;
     RECT  20.003 58.128 20.149 62.136 ;
     RECT  20.041 66.672 20.149 66.696 ;
     RECT  19.109 26.448 20.185 30.408 ;
     RECT  19.379 31.392 20.185 32.904 ;
     RECT  20.081 43.92 20.189 44.088 ;
     RECT  20.003 63.264 20.197 65.016 ;
     RECT  20.149 66.672 20.221 66.744 ;
     RECT  20.053 67.92 20.221 73.8 ;
     RECT  20.221 66.672 20.257 73.8 ;
     RECT  20.099 74.976 20.257 81.096 ;
     RECT  19.721 45.264 20.405 45.72 ;
     RECT  19.541 52.464 20.405 52.728 ;
     RECT  20.045 34.176 20.473 36.504 ;
     RECT  19.901 37.584 20.473 37.608 ;
     RECT  20.221 94.992 20.473 95.016 ;
     RECT  20.293 96.336 20.509 96.36 ;
     RECT  19.897 2.304 20.513 5.928 ;
     RECT  20.473 94.656 20.533 95.016 ;
     RECT  19.541 47.712 20.545 48.744 ;
     RECT  20.185 26.448 20.579 32.904 ;
     RECT  19.901 38.64 20.585 42.792 ;
     RECT  20.533 93.84 20.585 95.016 ;
     RECT  18.904 7.92 20.617 8.184 ;
     RECT  20.579 30.144 20.621 32.904 ;
     RECT  20.585 94.032 20.627 95.016 ;
     RECT  20.545 47.712 20.629 48.936 ;
     RECT  19.505 53.76 20.675 54.648 ;
     RECT  20.629 47.52 20.689 48.936 ;
     RECT  20.257 66.672 20.723 81.096 ;
     RECT  20.621 32.448 20.725 32.904 ;
     RECT  20.689 47.472 20.725 48.984 ;
     RECT  20.405 52.512 20.725 52.728 ;
     RECT  20.725 47.472 20.729 49.032 ;
     RECT  20.509 96.336 20.761 96.408 ;
     RECT  20.197 63.264 20.773 65.304 ;
     RECT  20.723 66.672 20.773 76.536 ;
     RECT  19.721 18.96 20.869 18.984 ;
     RECT  20.675 54.048 20.869 54.648 ;
     RECT  20.149 55.728 20.869 62.136 ;
     RECT  20.189 44.064 20.905 44.088 ;
     RECT  20.405 45.264 20.905 45.288 ;
     RECT  20.905 44.064 20.945 45.288 ;
     RECT  20.729 48.72 21.013 49.032 ;
     RECT  19.433 50.016 21.013 51.48 ;
     RECT  20.965 95.088 21.013 95.16 ;
     RECT  20.761 96.336 21.013 96.504 ;
     RECT  20.617 7.2 21.049 8.184 ;
     RECT  20.579 26.448 21.049 28.872 ;
     RECT  20.869 54.048 21.061 62.136 ;
     RECT  20.773 63.264 21.061 76.536 ;
     RECT  21.049 25.872 21.089 28.872 ;
     RECT  21.049 7.2 21.107 8.952 ;
     RECT  21.061 0.096 21.161 0.12 ;
     RECT  20.045 20.592 21.193 24.792 ;
     RECT  21.089 25.872 21.193 28.824 ;
     RECT  20.099 82.656 21.205 90.504 ;
     RECT  20.723 77.568 21.253 81.096 ;
     RECT  21.205 82.272 21.253 90.504 ;
     RECT  20.725 52.512 21.445 52.776 ;
     RECT  20.585 42.624 21.481 42.792 ;
     RECT  20.945 44.352 21.481 45.288 ;
     RECT  21.481 44.352 21.521 45.528 ;
     RECT  21.013 48.72 21.553 51.48 ;
     RECT  21.445 52.464 21.553 52.776 ;
     RECT  21.107 7.2 21.557 7.992 ;
     RECT  20.729 47.472 21.589 47.736 ;
     RECT  21.557 7.92 21.635 7.992 ;
     RECT  21.061 54.048 21.635 76.536 ;
     RECT  20.621 30.144 21.637 31.464 ;
     RECT  20.725 32.448 21.637 33.048 ;
     RECT  21.521 45.504 21.637 45.528 ;
     RECT  21.637 32.448 21.683 33.144 ;
     RECT  20.513 2.304 21.733 5.688 ;
     RECT  21.013 95.088 21.733 96.504 ;
     RECT  21.637 45.504 21.769 45.96 ;
     RECT  21.589 47.04 21.769 47.736 ;
     RECT  20.585 38.64 21.781 41.64 ;
     RECT  21.481 42.624 21.781 43.272 ;
     RECT  21.635 54.048 21.805 67.704 ;
     RECT  21.805 53.76 21.827 67.704 ;
     RECT  21.635 68.88 21.827 76.536 ;
     RECT  21.733 1.728 21.877 5.688 ;
     RECT  21.683 32.736 21.877 33.144 ;
     RECT  20.473 34.176 21.877 37.608 ;
     RECT  21.733 95.088 21.877 96.552 ;
     RECT  21.769 45.504 21.881 47.736 ;
     RECT  21.553 48.72 21.985 52.776 ;
     RECT  21.827 53.76 21.985 66.264 ;
     RECT  21.877 32.736 22.093 37.608 ;
     RECT  21.781 38.64 22.093 43.272 ;
     RECT  22.093 32.736 22.133 43.272 ;
     RECT  21.827 68.928 22.165 76.536 ;
     RECT  21.253 77.568 22.165 90.504 ;
     RECT  21.193 20.592 22.201 28.824 ;
     RECT  21.877 1.728 22.205 6.84 ;
     RECT  22.201 20.592 22.205 29.016 ;
     RECT  22.205 1.728 22.211 5.736 ;
     RECT  22.133 32.736 22.211 34.488 ;
     RECT  20.627 94.032 22.213 94.056 ;
     RECT  22.205 22.608 22.237 29.016 ;
     RECT  21.637 30 22.237 31.464 ;
     RECT  22.213 94.032 22.237 94.104 ;
     RECT  21.877 95.088 22.237 97.08 ;
     RECT  22.211 32.736 22.241 34.344 ;
     RECT  22.237 22.608 22.273 31.464 ;
     RECT  22.133 35.472 22.273 43.272 ;
     RECT  21.521 44.352 22.273 44.424 ;
     RECT  22.241 32.736 22.313 33.96 ;
     RECT  22.273 35.472 22.355 44.424 ;
     RECT  20.869 18.96 22.381 19.368 ;
     RECT  22.205 20.592 22.381 21.336 ;
     RECT  22.381 18.96 22.453 21.336 ;
     RECT  21.881 45.504 22.457 47.544 ;
     RECT  22.273 22.608 22.499 31.56 ;
     RECT  22.165 68.928 22.525 90.504 ;
     RECT  22.525 68.928 22.565 90.6 ;
     RECT  21.301 13.488 22.597 13.512 ;
     RECT  22.499 23.088 22.601 31.56 ;
     RECT  22.453 18.768 22.637 21.336 ;
     RECT  22.597 13.488 22.673 14.232 ;
     RECT  22.453 17.568 22.673 17.592 ;
     RECT  22.211 1.728 22.705 5.4 ;
     RECT  19.379 16.128 22.741 16.152 ;
     RECT  22.565 70.8 22.741 90.6 ;
     RECT  22.637 18.768 22.745 21.24 ;
     RECT  22.313 32.928 22.745 33.96 ;
     RECT  22.601 23.088 22.781 24.504 ;
     RECT  21.985 48.72 22.787 66.264 ;
     RECT  22.205 6.816 22.789 6.84 ;
     RECT  21.635 7.92 22.789 7.944 ;
     RECT  22.705 1.104 22.835 5.4 ;
     RECT  21.827 67.296 22.837 67.704 ;
     RECT  22.565 68.928 22.837 69.48 ;
     RECT  22.601 25.872 22.889 31.56 ;
     RECT  22.787 48.72 22.925 65.448 ;
     RECT  22.741 15.888 22.957 16.152 ;
     RECT  22.925 48.72 22.957 53.064 ;
     RECT  22.789 6.816 22.961 8.568 ;
     RECT  22.457 45.6 22.981 47.544 ;
     RECT  22.957 48.624 22.981 53.064 ;
     RECT  22.355 35.472 23.027 42.792 ;
     RECT  22.981 45.6 23.027 53.064 ;
     RECT  22.837 67.296 23.065 69.48 ;
     RECT  22.645 10.512 23.101 10.536 ;
     RECT  23.077 0.096 23.173 0.12 ;
     RECT  23.027 35.472 23.281 39.192 ;
     RECT  23.027 40.32 23.317 42.792 ;
     RECT  22.355 44.208 23.317 44.424 ;
     RECT  23.101 10.08 23.425 10.536 ;
     RECT  23.461 14.688 23.497 14.712 ;
     RECT  22.957 15.888 23.497 16.872 ;
     RECT  22.237 94.032 23.507 97.08 ;
     RECT  22.835 1.728 23.509 5.4 ;
     RECT  22.961 6.816 23.509 7.944 ;
     RECT  22.741 70.8 23.605 90.648 ;
     RECT  22.673 13.488 23.641 13.608 ;
     RECT  23.497 14.688 23.641 16.872 ;
     RECT  23.641 13.488 23.749 16.872 ;
     RECT  23.125 17.952 23.749 17.976 ;
     RECT  23.065 66.768 23.749 69.48 ;
     RECT  23.605 70.656 23.749 90.648 ;
     RECT  22.745 18.96 23.785 21.24 ;
     RECT  22.781 23.28 23.785 24.504 ;
     RECT  23.749 13.488 23.797 17.976 ;
     RECT  23.785 18.96 23.797 24.504 ;
     RECT  23.797 13.488 23.893 24.504 ;
     RECT  22.745 33.024 23.893 33.96 ;
     RECT  23.425 10.08 23.929 10.776 ;
     RECT  23.509 1.728 24.008 7.944 ;
     RECT  23.929 9.792 24.008 10.776 ;
     RECT  23.965 11.76 24.008 11.784 ;
     RECT  23.893 13.488 24.008 24.84 ;
     RECT  22.889 25.872 24.008 31.32 ;
     RECT  23.893 33.024 24.008 34.008 ;
     RECT  23.281 35.232 24.008 39.192 ;
     RECT  23.317 40.32 24.008 44.424 ;
     RECT  23.027 46.032 24.008 53.064 ;
     RECT  22.925 54.048 24.008 65.448 ;
     RECT  23.749 66.768 24.008 90.648 ;
     RECT  23.507 94.032 24.008 95.256 ;
     RECT  23.173 0.096 24.037 0.216 ;
     RECT  24.008 1.728 24.304 95.256 ;
     RECT  24.304 1.728 24.401 6.84 ;
     RECT  24.304 17.088 24.401 24.552 ;
     RECT  24.037 0.096 24.419 0.264 ;
     RECT  24.401 1.728 24.419 6.408 ;
     RECT  24.401 17.184 24.419 24.552 ;
     RECT  24.304 43.872 24.419 44.424 ;
     RECT  24.304 94.56 24.467 95.256 ;
     RECT  24.304 64.656 24.473 90.312 ;
     RECT  24.304 29.664 24.509 42.744 ;
     RECT  24.473 64.656 24.563 84.744 ;
     RECT  24.304 9.072 24.581 14.952 ;
     RECT  24.509 29.664 24.617 31.992 ;
     RECT  24.563 64.656 24.617 82.2 ;
     RECT  24.617 64.656 24.659 82.152 ;
     RECT  24.617 29.664 24.833 31.704 ;
     RECT  24.419 1.728 24.905 5.832 ;
     RECT  24.833 29.664 24.905 31.368 ;
     RECT  24.659 64.656 24.905 68.952 ;
     RECT  24.659 70.08 25.085 82.152 ;
     RECT  24.581 9.792 25.139 14.952 ;
     RECT  24.509 32.976 25.139 42.744 ;
     RECT  25.139 9.792 25.265 14.856 ;
     RECT  24.473 85.728 25.265 90.312 ;
     RECT  24.304 15.936 25.297 16.056 ;
     RECT  25.297 15.936 25.301 16.104 ;
     RECT  25.139 32.976 25.301 33 ;
     RECT  24.304 26.064 25.373 28.584 ;
     RECT  25.085 70.08 25.379 77.688 ;
     RECT  24.419 22.752 25.441 24.552 ;
     RECT  25.441 22.752 25.445 25.032 ;
     RECT  25.139 34.176 25.445 42.744 ;
     RECT  24.467 95.136 25.445 95.256 ;
     RECT  25.379 70.08 25.475 76.488 ;
     RECT  24.304 62.208 25.477 63.624 ;
     RECT  24.905 64.656 25.477 67.56 ;
     RECT  24.905 2.304 25.481 5.832 ;
     RECT  25.333 8.352 25.481 8.376 ;
     RECT  23.507 96.288 25.549 97.08 ;
     RECT  24.419 44.112 25.585 44.136 ;
     RECT  25.477 62.208 25.657 67.56 ;
     RECT  25.549 95.712 25.661 97.08 ;
     RECT  25.445 36.672 25.667 42.744 ;
     RECT  25.265 85.728 25.667 90.264 ;
     RECT  25.301 16.032 25.669 16.104 ;
     RECT  24.419 17.184 25.669 21.672 ;
     RECT  25.481 2.304 25.715 4.584 ;
     RECT  25.657 94.656 25.715 94.68 ;
     RECT  25.669 16.032 25.765 21.672 ;
     RECT  25.445 22.752 25.765 23.88 ;
     RECT  25.085 78.72 25.765 82.152 ;
     RECT  24.563 83.328 25.765 84.744 ;
     RECT  25.765 78.72 25.801 84.744 ;
     RECT  25.667 85.728 25.801 90.072 ;
     RECT  25.765 16.032 25.805 23.88 ;
     RECT  25.765 93.504 25.811 93.528 ;
     RECT  24.905 68.592 25.837 68.952 ;
     RECT  25.475 70.08 25.837 76.344 ;
     RECT  25.481 5.664 25.841 5.832 ;
     RECT  25.265 9.792 25.841 14.712 ;
     RECT  25.837 68.592 25.877 76.344 ;
     RECT  25.585 44.112 25.909 44.904 ;
     RECT  24.304 45.936 25.909 60.312 ;
     RECT  25.841 5.712 25.913 5.832 ;
     RECT  25.657 62.16 26.017 67.56 ;
     RECT  24.419 0.096 26.053 0.12 ;
     RECT  25.445 25.008 26.053 25.032 ;
     RECT  25.373 26.064 26.053 26.088 ;
     RECT  25.909 44.112 26.053 60.312 ;
     RECT  26.017 62.112 26.129 67.56 ;
     RECT  25.909 7.248 26.147 7.272 ;
     RECT  25.877 68.784 26.147 76.344 ;
     RECT  26.053 0.096 26.149 0.168 ;
     RECT  24.905 29.664 26.149 30.888 ;
     RECT  25.667 37.056 26.149 42.744 ;
     RECT  26.053 44.112 26.149 60.648 ;
     RECT  25.805 18.432 26.195 23.88 ;
     RECT  26.149 29.664 26.195 31.656 ;
     RECT  26.195 31.632 26.269 31.656 ;
     RECT  26.129 62.112 26.273 62.184 ;
     RECT  25.373 27.168 26.293 28.584 ;
     RECT  26.195 29.664 26.293 30.024 ;
     RECT  25.715 2.304 26.309 4.056 ;
     RECT  26.269 31.632 26.309 31.896 ;
     RECT  25.801 78.72 26.309 90.072 ;
     RECT  25.379 77.472 26.341 77.688 ;
     RECT  26.309 78.72 26.341 83.784 ;
     RECT  26.149 0.096 26.345 0.264 ;
     RECT  26.149 37.056 26.345 60.648 ;
     RECT  26.345 41.568 26.381 60.648 ;
     RECT  25.661 95.712 26.413 96.36 ;
     RECT  26.195 22.176 26.417 23.88 ;
     RECT  26.293 27.168 26.417 30.024 ;
     RECT  26.147 68.928 26.453 76.344 ;
     RECT  26.453 69.024 26.485 76.344 ;
     RECT  26.341 77.472 26.485 83.784 ;
     RECT  26.309 2.304 26.561 3.432 ;
     RECT  25.841 9.792 26.561 14.52 ;
     RECT  25.805 16.032 26.581 17.112 ;
     RECT  26.485 6.816 26.629 6.84 ;
     RECT  26.309 84.912 26.633 90.072 ;
     RECT  26.345 37.056 26.669 40.488 ;
     RECT  26.381 43.104 26.669 60.648 ;
     RECT  25.445 34.176 26.701 35.592 ;
     RECT  26.669 37.056 26.701 38.712 ;
     RECT  26.413 95.136 26.725 96.36 ;
     RECT  26.629 5.904 26.771 6.84 ;
     RECT  26.381 41.568 26.819 41.592 ;
     RECT  26.725 94.992 26.821 96.36 ;
     RECT  26.669 43.104 26.849 59.544 ;
     RECT  26.849 44.112 26.885 59.544 ;
     RECT  26.195 18.432 26.953 20.76 ;
     RECT  26.917 93.504 26.963 93.528 ;
     RECT  26.273 62.112 27.013 62.136 ;
     RECT  26.821 94.992 27.013 97.08 ;
     RECT  26.669 39.792 27.059 40.488 ;
     RECT  26.701 34.176 27.065 38.712 ;
     RECT  27.059 39.792 27.065 40.152 ;
     RECT  26.129 63.312 27.097 67.56 ;
     RECT  26.417 22.176 27.101 23.352 ;
     RECT  27.061 33.024 27.107 33.048 ;
     RECT  26.669 60.528 27.133 60.648 ;
     RECT  27.013 62.016 27.281 62.136 ;
     RECT  26.485 69.024 27.299 83.784 ;
     RECT  27.097 63.264 27.347 67.704 ;
     RECT  26.417 27.888 27.349 30.024 ;
     RECT  26.309 31.872 27.349 31.896 ;
     RECT  26.561 2.304 27.389 2.952 ;
     RECT  26.561 13.968 27.397 14.52 ;
     RECT  26.581 15.792 27.397 17.112 ;
     RECT  26.053 25.008 27.421 26.088 ;
     RECT  27.101 22.176 27.461 23.16 ;
     RECT  26.345 0.096 27.493 0.216 ;
     RECT  27.421 25.008 27.493 26.568 ;
     RECT  25.621 8.544 27.533 8.568 ;
     RECT  27.493 0.096 27.539 0.264 ;
     RECT  27.277 4.752 27.541 4.776 ;
     RECT  27.385 92.928 27.541 92.952 ;
     RECT  27.299 69.024 27.565 79.944 ;
     RECT  27.539 0.144 27.587 0.264 ;
     RECT  27.281 62.112 27.601 62.136 ;
     RECT  27.347 63.312 27.601 67.704 ;
     RECT  27.565 68.688 27.601 79.944 ;
     RECT  27.013 94.656 27.601 97.08 ;
     RECT  27.587 0.144 27.605 0.216 ;
     RECT  27.541 92.352 27.635 92.952 ;
     RECT  26.633 84.96 27.637 90.072 ;
     RECT  27.241 91.056 27.637 91.08 ;
     RECT  26.953 18.192 27.641 20.76 ;
     RECT  26.885 54.384 27.685 59.544 ;
     RECT  27.133 60.528 27.685 60.984 ;
     RECT  27.493 25.008 27.709 26.904 ;
     RECT  27.349 27.888 27.709 32.76 ;
     RECT  27.709 25.008 27.779 32.76 ;
     RECT  26.849 43.104 27.781 43.128 ;
     RECT  27.635 92.352 27.857 92.376 ;
     RECT  27.299 81.072 27.877 83.784 ;
     RECT  27.637 84.96 27.877 91.32 ;
     RECT  26.561 9.792 27.889 12.888 ;
     RECT  27.397 13.968 27.923 17.112 ;
     RECT  27.641 18.192 27.925 18.216 ;
     RECT  27.641 19.248 27.925 20.76 ;
     RECT  27.565 21.936 27.925 21.96 ;
     RECT  27.877 81.072 27.929 91.32 ;
     RECT  27.389 2.304 27.965 2.904 ;
     RECT  27.929 81.072 27.965 90.072 ;
     RECT  27.541 3.984 27.997 4.776 ;
     RECT  27.923 15.888 27.997 17.112 ;
     RECT  27.925 18.144 28.037 18.216 ;
     RECT  26.885 44.112 28.069 53.4 ;
     RECT  27.685 54.384 28.069 60.984 ;
     RECT  27.929 91.056 28.073 91.32 ;
     RECT  27.781 42.336 28.105 43.128 ;
     RECT  28.069 44.112 28.105 60.984 ;
     RECT  27.923 13.968 28.109 14.76 ;
     RECT  27.601 94.32 28.117 97.08 ;
     RECT  27.889 9.12 28.145 12.888 ;
     RECT  27.461 23.04 28.177 23.16 ;
     RECT  28.105 42.336 28.181 60.984 ;
     RECT  28.145 9.792 28.213 12.888 ;
     RECT  27.065 34.224 28.213 38.712 ;
     RECT  27.065 40.032 28.213 40.152 ;
     RECT  28.177 23.04 28.357 23.976 ;
     RECT  27.779 25.008 28.357 29.784 ;
     RECT  28.109 14.496 28.397 14.76 ;
     RECT  28.213 40.032 28.429 40.344 ;
     RECT  28.213 34.128 28.453 38.712 ;
     RECT  28.429 40.032 28.453 40.392 ;
     RECT  28.181 58.176 28.453 60.984 ;
     RECT  27.601 62.112 28.453 62.232 ;
     RECT  27.779 31.008 28.465 32.76 ;
     RECT  26.771 6.816 28.573 6.84 ;
     RECT  27.601 63.312 28.573 79.944 ;
     RECT  27.965 81.072 28.573 89.976 ;
     RECT  28.453 58.176 28.609 62.232 ;
     RECT  28.573 63.312 28.609 89.976 ;
     RECT  27.997 3.984 28.681 5.592 ;
     RECT  28.573 6.816 28.681 6.888 ;
     RECT  28.181 42.336 28.681 57.096 ;
     RECT  28.465 31.008 28.717 32.808 ;
     RECT  28.453 34.128 28.717 40.392 ;
     RECT  27.965 2.832 28.789 2.904 ;
     RECT  28.681 3.984 28.789 6.888 ;
     RECT  28.357 23.04 28.837 29.784 ;
     RECT  28.717 31.008 28.837 40.392 ;
     RECT  27.925 19.248 28.885 21.96 ;
     RECT  28.837 23.04 28.885 40.392 ;
     RECT  28.789 2.832 28.897 6.888 ;
     RECT  28.789 8.4 28.897 8.424 ;
     RECT  28.397 14.64 28.897 14.76 ;
     RECT  27.997 15.888 28.897 17.16 ;
     RECT  28.037 18.192 28.969 18.216 ;
     RECT  28.885 19.248 28.969 40.392 ;
     RECT  28.897 2.832 28.981 8.424 ;
     RECT  28.981 2.64 29.005 8.424 ;
     RECT  28.897 14.64 29.077 17.16 ;
     RECT  28.969 18.192 29.077 40.392 ;
     RECT  29.005 2.304 29.221 8.424 ;
     RECT  29.221 2.304 29.257 8.76 ;
     RECT  28.213 9.792 29.257 13.08 ;
     RECT  28.681 42.24 29.257 57.096 ;
     RECT  28.609 58.176 29.257 89.976 ;
     RECT  27.605 0.192 29.269 0.216 ;
     RECT  28.073 91.056 29.293 91.224 ;
     RECT  29.257 2.304 29.317 13.08 ;
     RECT  29.257 42.24 29.329 89.976 ;
     RECT  29.317 2.016 29.408 13.08 ;
     RECT  29.077 14.64 29.408 40.392 ;
     RECT  29.329 42 29.408 89.976 ;
     RECT  29.293 91.056 29.408 91.464 ;
     RECT  28.117 93.504 29.408 97.08 ;
     RECT  29.408 2.016 29.459 97.08 ;
     RECT  29.269 0.144 29.555 0.216 ;
     RECT  29.459 96.288 29.585 97.08 ;
     RECT  29.555 0.144 29.605 0.168 ;
     RECT  29.459 2.016 29.657 95.16 ;
     RECT  29.657 2.016 29.701 94.872 ;
     RECT  29.701 1.728 29.704 94.872 ;
     RECT  29.704 42 29.843 47.208 ;
     RECT  29.704 19.008 30.083 28.632 ;
     RECT  29.704 72.48 30.227 90.072 ;
     RECT  29.704 14.736 30.269 17.832 ;
     RECT  30.083 19.008 30.371 28.584 ;
     RECT  29.704 48.24 30.371 71.448 ;
     RECT  30.227 81.648 30.449 90.072 ;
     RECT  29.704 29.76 30.521 40.392 ;
     RECT  30.371 19.008 30.659 26.808 ;
     RECT  30.449 81.696 30.659 90.072 ;
     RECT  30.659 87.888 30.709 90.072 ;
     RECT  29.704 91.056 30.709 91.608 ;
     RECT  30.521 30.192 30.737 40.392 ;
     RECT  29.605 0.096 30.757 0.168 ;
     RECT  30.371 53.472 30.769 71.448 ;
     RECT  30.227 72.48 30.769 80.52 ;
     RECT  29.704 94.32 30.769 94.872 ;
     RECT  30.659 81.696 30.773 86.856 ;
     RECT  30.773 81.744 30.809 86.856 ;
     RECT  30.809 81.744 30.845 83.016 ;
     RECT  30.757 0.096 30.877 0.312 ;
     RECT  29.843 42 30.877 42.792 ;
     RECT  29.843 43.824 30.877 47.208 ;
     RECT  30.737 30.192 30.881 34.344 ;
     RECT  29.585 97.056 30.881 97.08 ;
     RECT  30.845 81.888 30.947 83.016 ;
     RECT  30.659 20.688 30.953 26.808 ;
     RECT  30.769 53.472 30.953 80.52 ;
     RECT  30.877 0.096 30.985 0.36 ;
     RECT  30.737 35.376 30.985 40.392 ;
     RECT  30.769 94.272 30.985 94.872 ;
     RECT  30.881 30.432 31.043 34.344 ;
     RECT  30.709 87.888 31.043 91.608 ;
     RECT  30.985 35.376 31.061 40.44 ;
     RECT  30.985 0.096 31.091 0.408 ;
     RECT  30.953 53.472 31.133 69.192 ;
     RECT  31.043 87.888 31.169 88.248 ;
     RECT  31.091 0.096 31.187 0.36 ;
     RECT  31.187 0.144 31.235 0.36 ;
     RECT  31.133 59.136 31.241 63.816 ;
     RECT  30.985 94.272 31.273 95.448 ;
     RECT  31.235 0.144 31.277 0.312 ;
     RECT  31.061 39.792 31.285 40.44 ;
     RECT  30.877 42 31.285 47.208 ;
     RECT  31.285 39.792 31.309 47.208 ;
     RECT  30.371 48.24 31.309 52.44 ;
     RECT  31.309 39.792 31.333 52.44 ;
     RECT  31.133 53.472 31.333 58.152 ;
     RECT  31.333 39.792 31.349 58.152 ;
     RECT  30.269 14.784 31.417 17.832 ;
     RECT  30.659 19.008 31.417 19.656 ;
     RECT  31.349 39.792 31.421 47.64 ;
     RECT  31.061 35.376 31.457 38.712 ;
     RECT  30.953 70.224 31.669 80.52 ;
     RECT  31.349 48.72 31.745 58.152 ;
     RECT  29.704 1.728 31.777 13.464 ;
     RECT  31.417 14.784 31.777 19.656 ;
     RECT  31.043 30.432 31.849 34.248 ;
     RECT  31.669 70.224 31.849 80.712 ;
     RECT  30.947 81.888 31.849 82.824 ;
     RECT  30.809 84.24 31.885 86.856 ;
     RECT  31.169 87.888 31.885 88.008 ;
     RECT  31.849 70.224 31.909 82.824 ;
     RECT  31.133 64.896 31.921 69.192 ;
     RECT  31.909 70.224 31.921 83.208 ;
     RECT  31.849 29.664 31.925 34.248 ;
     RECT  30.953 20.688 31.957 26.664 ;
     RECT  30.371 27.888 31.957 28.584 ;
     RECT  31.457 37.056 32.029 38.712 ;
     RECT  31.421 39.792 32.029 40.92 ;
     RECT  31.925 32.736 32.033 34.248 ;
     RECT  32.029 37.056 32.033 40.92 ;
     RECT  31.745 48.72 32.051 57.288 ;
     RECT  31.925 29.664 32.065 31.512 ;
     RECT  32.065 29.568 32.069 31.512 ;
     RECT  31.277 0.144 32.099 0.264 ;
     RECT  31.043 89.424 32.101 91.608 ;
     RECT  31.241 61.056 32.209 63.816 ;
     RECT  31.921 64.896 32.245 83.208 ;
     RECT  31.885 84.24 32.245 88.008 ;
     RECT  32.099 0.144 32.281 0.216 ;
     RECT  32.033 32.784 32.353 34.248 ;
     RECT  31.457 35.376 32.353 35.976 ;
     RECT  32.209 61.008 32.357 63.816 ;
     RECT  31.777 1.728 32.389 19.656 ;
     RECT  31.957 20.688 32.389 28.584 ;
     RECT  31.241 59.136 32.393 60.024 ;
     RECT  32.069 29.568 32.429 31.464 ;
     RECT  32.353 32.784 32.485 35.976 ;
     RECT  32.033 37.056 32.485 40.872 ;
     RECT  32.245 64.896 32.497 88.008 ;
     RECT  32.101 89.424 32.497 91.8 ;
     RECT  32.497 64.896 32.537 91.8 ;
     RECT  32.537 67.152 32.677 91.8 ;
     RECT  32.677 67.152 32.681 91.848 ;
     RECT  32.681 83.76 32.785 91.848 ;
     RECT  32.681 67.152 32.789 82.68 ;
     RECT  32.051 48.72 32.867 57.048 ;
     RECT  31.421 42.24 32.893 47.64 ;
     RECT  32.389 1.728 32.915 28.584 ;
     RECT  32.915 2.304 32.933 28.584 ;
     RECT  32.789 67.152 32.933 79.608 ;
     RECT  32.485 32.784 33.061 40.872 ;
     RECT  33.061 32.592 33.073 40.872 ;
     RECT  32.893 42.144 33.073 47.64 ;
     RECT  33.073 32.592 33.109 47.64 ;
     RECT  32.429 30.432 33.145 31.464 ;
     RECT  33.109 32.592 33.145 47.688 ;
     RECT  32.867 48.72 33.145 50.472 ;
     RECT  32.933 23.808 33.217 28.584 ;
     RECT  31.273 94.272 33.253 96.024 ;
     RECT  32.281 0.096 33.257 0.216 ;
     RECT  33.145 30.432 33.257 50.472 ;
     RECT  32.867 51.504 33.361 57.048 ;
     RECT  32.785 83.76 33.365 91.944 ;
     RECT  33.217 23.808 33.395 29.208 ;
     RECT  32.393 59.136 33.401 59.832 ;
     RECT  33.395 24.384 33.505 29.208 ;
     RECT  33.257 30.432 33.505 41.112 ;
     RECT  33.401 59.184 33.613 59.832 ;
     RECT  32.357 61.056 33.613 63.816 ;
     RECT  32.933 67.152 33.617 78.648 ;
     RECT  33.613 59.184 33.637 63.816 ;
     RECT  32.537 64.896 33.637 65.928 ;
     RECT  33.637 59.184 33.725 65.928 ;
     RECT  33.361 51.504 33.779 57.576 ;
     RECT  32.789 80.592 33.793 82.68 ;
     RECT  33.365 83.76 33.793 85.512 ;
     RECT  33.725 59.232 33.829 65.928 ;
     RECT  33.617 67.152 33.829 73.608 ;
     RECT  33.257 0.096 33.869 0.168 ;
     RECT  33.257 42.144 33.877 50.472 ;
     RECT  33.779 51.504 33.877 52.872 ;
     RECT  33.617 74.736 33.937 78.648 ;
     RECT  32.933 2.304 33.973 22.776 ;
     RECT  33.937 74.736 34.045 79.224 ;
     RECT  33.793 80.592 34.045 85.512 ;
     RECT  33.505 24.384 34.369 41.112 ;
     RECT  33.877 42.144 34.369 52.872 ;
     RECT  34.045 74.736 34.645 85.512 ;
     RECT  33.365 86.592 34.693 91.944 ;
     RECT  33.973 2.304 34.729 23.304 ;
     RECT  34.369 24.384 34.729 52.872 ;
     RECT  34.729 2.304 34.765 52.872 ;
     RECT  34.765 2.016 34.808 53.064 ;
     RECT  33.779 54.192 34.808 57.576 ;
     RECT  33.829 59.232 34.808 73.608 ;
     RECT  34.645 74.688 34.808 85.512 ;
     RECT  34.693 86.592 34.808 92.28 ;
     RECT  33.253 94.272 34.808 96.072 ;
     RECT  33.869 0.144 34.885 0.168 ;
     RECT  34.808 2.016 34.945 96.072 ;
     RECT  34.945 2.016 35.077 96.12 ;
     RECT  35.077 1.728 35.104 96.12 ;
     RECT  34.885 0.144 35.161 0.36 ;
     RECT  35.104 62.256 35.219 63.288 ;
     RECT  35.104 1.728 35.309 11.784 ;
     RECT  35.161 0.096 35.315 0.36 ;
     RECT  35.104 65.712 35.315 92.28 ;
     RECT  35.104 64.32 35.345 64.68 ;
     RECT  35.315 0.096 35.363 0.264 ;
     RECT  35.104 21.168 35.381 27.72 ;
     RECT  35.104 46.08 35.381 53.064 ;
     RECT  35.104 39.84 35.411 44.904 ;
     RECT  35.381 25.872 35.417 27.72 ;
     RECT  35.104 33.648 35.525 38.76 ;
     RECT  35.219 62.496 35.525 63.096 ;
     RECT  35.381 46.08 35.705 51.384 ;
     RECT  35.315 65.712 35.891 85.704 ;
     RECT  35.381 21.168 35.921 24.744 ;
     RECT  35.417 25.872 35.939 26.712 ;
     RECT  35.921 21.168 35.957 22.296 ;
     RECT  35.104 58.128 35.957 61.176 ;
     RECT  35.104 54.672 35.993 55.272 ;
     RECT  35.417 27.696 36.065 27.72 ;
     RECT  35.309 2.208 36.133 11.784 ;
     RECT  35.104 12.912 36.133 13.08 ;
     RECT  35.705 46.08 36.133 50.376 ;
     RECT  35.993 54.72 36.169 55.272 ;
     RECT  35.104 56.736 36.169 57.048 ;
     RECT  35.104 14.352 36.209 14.76 ;
     RECT  35.921 23.28 36.275 24.744 ;
     RECT  35.345 64.416 36.277 64.68 ;
     RECT  35.891 65.712 36.277 81.432 ;
     RECT  36.169 54.72 36.313 57.048 ;
     RECT  35.957 58.128 36.313 58.68 ;
     RECT  35.104 93.744 36.373 94.344 ;
     RECT  35.957 59.76 36.389 61.176 ;
     RECT  36.275 23.376 36.419 24.744 ;
     RECT  36.277 64.416 36.419 81.432 ;
     RECT  36.419 23.856 36.421 24.744 ;
     RECT  35.939 25.872 36.421 26.088 ;
     RECT  36.209 14.352 36.457 14.376 ;
     RECT  35.104 18.144 36.457 19.944 ;
     RECT  35.957 21.168 36.457 21.528 ;
     RECT  36.421 23.856 36.467 26.088 ;
     RECT  36.133 45.936 36.467 50.376 ;
     RECT  35.891 82.704 36.493 85.704 ;
     RECT  35.315 86.784 36.493 92.28 ;
     RECT  36.419 65.712 36.497 81.432 ;
     RECT  35.363 0.096 36.529 0.168 ;
     RECT  35.525 63.072 36.529 63.096 ;
     RECT  36.493 82.704 36.533 92.28 ;
     RECT  36.133 2.208 36.569 13.08 ;
     RECT  36.497 65.712 36.569 71.4 ;
     RECT  35.104 28.707 36.601 32.52 ;
     RECT  36.313 54.72 36.611 58.68 ;
     RECT  36.569 67.488 36.641 71.4 ;
     RECT  36.601 28.32 36.661 32.52 ;
     RECT  35.525 33.792 36.661 38.76 ;
     RECT  36.569 8.208 36.673 13.08 ;
     RECT  36.457 14.256 36.707 14.376 ;
     RECT  36.661 28.32 36.709 38.76 ;
     RECT  36.709 28.32 36.781 38.808 ;
     RECT  36.781 28.32 36.805 38.856 ;
     RECT  35.411 39.84 36.805 44.664 ;
     RECT  36.277 97.152 36.817 97.176 ;
     RECT  36.611 58.656 36.821 58.68 ;
     RECT  36.673 8.208 36.853 13.128 ;
     RECT  36.467 23.904 36.899 26.088 ;
     RECT  36.497 72.528 36.899 81.432 ;
     RECT  36.467 45.936 36.925 48.744 ;
     RECT  35.381 53.04 36.929 53.064 ;
     RECT  36.805 28.32 36.947 44.664 ;
     RECT  36.641 67.488 36.965 70.68 ;
     RECT  36.925 45.84 36.997 48.744 ;
     RECT  36.389 60.816 36.997 61.176 ;
     RECT  36.529 62.784 36.997 63.096 ;
     RECT  36.419 64.416 36.997 64.44 ;
     RECT  36.569 2.304 37.037 7.176 ;
     RECT  36.529 0.096 37.043 0.216 ;
     RECT  36.965 67.488 37.043 69.432 ;
     RECT  36.947 31.68 37.091 44.664 ;
     RECT  37.091 31.68 37.109 35.544 ;
     RECT  37.091 36.912 37.141 44.664 ;
     RECT  36.997 45.792 37.141 48.744 ;
     RECT  35.104 16.368 37.177 16.968 ;
     RECT  36.899 23.904 37.181 24.744 ;
     RECT  36.899 75.168 37.181 81.432 ;
     RECT  37.109 31.68 37.187 35.4 ;
     RECT  37.177 15.984 37.237 16.968 ;
     RECT  37.237 15.744 37.249 16.968 ;
     RECT  36.457 18.144 37.253 21.528 ;
     RECT  36.965 70.656 37.253 70.68 ;
     RECT  36.707 14.352 37.285 14.376 ;
     RECT  37.249 15.36 37.285 16.968 ;
     RECT  37.181 79.776 37.285 81.432 ;
     RECT  37.187 31.68 37.289 31.704 ;
     RECT  36.997 60.816 37.331 64.44 ;
     RECT  36.611 54.72 37.333 57.672 ;
     RECT  37.333 54.096 37.393 57.672 ;
     RECT  36.899 72.528 37.433 74.04 ;
     RECT  37.331 62.64 37.477 64.44 ;
     RECT  36.569 65.712 37.477 66.408 ;
     RECT  36.389 59.76 37.525 59.784 ;
     RECT  37.331 60.816 37.525 61.464 ;
     RECT  36.947 28.32 37.541 30.456 ;
     RECT  37.037 5.904 37.573 7.176 ;
     RECT  36.853 8.208 37.573 13.224 ;
     RECT  36.899 25.728 37.573 26.088 ;
     RECT  37.573 5.904 37.577 13.224 ;
     RECT  37.141 36.912 37.577 48.744 ;
     RECT  37.043 0.096 37.619 0.12 ;
     RECT  36.533 82.704 37.645 82.872 ;
     RECT  37.181 75.168 37.649 78.792 ;
     RECT  37.477 62.64 37.667 66.408 ;
     RECT  36.373 93.504 37.681 94.344 ;
     RECT  37.037 2.304 37.685 4.824 ;
     RECT  37.573 25.728 37.753 26.376 ;
     RECT  37.285 14.352 37.757 16.968 ;
     RECT  37.685 2.304 37.765 4.632 ;
     RECT  37.765 1.728 37.793 4.632 ;
     RECT  37.577 5.904 37.793 13.128 ;
     RECT  37.393 53.568 37.825 57.672 ;
     RECT  37.825 53.568 37.829 57.72 ;
     RECT  37.577 37.008 37.859 48.744 ;
     RECT  37.859 38.688 37.861 48.744 ;
     RECT  36.467 49.728 37.861 49.8 ;
     RECT  37.285 79.776 37.897 81.624 ;
     RECT  37.645 82.656 37.897 82.872 ;
     RECT  37.253 21.36 37.933 21.528 ;
     RECT  37.861 38.688 37.933 49.8 ;
     RECT  37.433 72.528 37.933 73.608 ;
     RECT  37.933 21.36 37.969 21.816 ;
     RECT  37.717 58.752 37.969 58.776 ;
     RECT  37.525 59.76 37.969 61.464 ;
     RECT  37.897 79.776 37.969 82.872 ;
     RECT  37.541 28.32 38.005 30.168 ;
     RECT  37.969 58.752 38.005 61.464 ;
     RECT  37.681 93.504 38.009 94.392 ;
     RECT  37.757 14.64 38.077 16.968 ;
     RECT  37.829 53.76 38.077 57.72 ;
     RECT  38.005 58.704 38.077 61.464 ;
     RECT  37.793 1.728 38.081 4.584 ;
     RECT  37.969 79.776 38.081 83.064 ;
     RECT  36.533 84.192 38.113 92.28 ;
     RECT  37.187 32.736 38.149 35.352 ;
     RECT  35.705 51.36 38.149 51.384 ;
     RECT  38.041 52.464 38.149 52.488 ;
     RECT  37.793 6.048 38.153 13.128 ;
     RECT  37.933 38.688 38.153 50.088 ;
     RECT  37.649 76.944 38.189 78.792 ;
     RECT  37.859 37.008 38.195 37.32 ;
     RECT  37.969 21.36 38.221 21.96 ;
     RECT  37.181 24.096 38.221 24.744 ;
     RECT  37.753 25.728 38.221 26.808 ;
     RECT  38.005 27.84 38.221 30.168 ;
     RECT  38.153 6.048 38.225 9.288 ;
     RECT  38.153 40.416 38.225 50.088 ;
     RECT  37.253 18.144 38.257 20.376 ;
     RECT  38.221 21.36 38.257 24.744 ;
     RECT  38.149 32.736 38.257 35.448 ;
     RECT  37.649 75.168 38.293 75.96 ;
     RECT  38.081 80.304 38.293 83.064 ;
     RECT  38.113 84.144 38.293 92.28 ;
     RECT  38.153 38.688 38.297 39.384 ;
     RECT  38.195 37.008 38.333 37.128 ;
     RECT  37.043 67.488 38.437 69.288 ;
     RECT  38.153 10.416 38.513 13.128 ;
     RECT  38.077 14.64 38.513 17.112 ;
     RECT  38.513 10.416 38.531 12.792 ;
     RECT  38.189 76.944 38.579 78.648 ;
     RECT  38.257 18.144 38.617 24.744 ;
     RECT  38.221 25.728 38.617 30.168 ;
     RECT  38.077 53.76 38.693 61.464 ;
     RECT  38.437 67.488 38.725 69.48 ;
     RECT  35.104 95.424 38.725 96.12 ;
     RECT  36.817 97.104 38.725 97.176 ;
     RECT  38.257 32.064 38.729 35.448 ;
     RECT  38.225 47.664 38.761 50.088 ;
     RECT  38.149 51.12 38.761 52.488 ;
     RECT  38.617 18.144 38.771 30.36 ;
     RECT  38.729 32.064 38.797 32.76 ;
     RECT  38.729 34.224 38.801 35.448 ;
     RECT  38.081 2.304 38.821 4.584 ;
     RECT  38.513 15.408 38.821 17.112 ;
     RECT  38.771 18.144 38.821 22.056 ;
     RECT  38.257 70.608 38.833 70.632 ;
     RECT  38.821 2.304 38.869 4.68 ;
     RECT  38.293 80.304 38.909 92.28 ;
     RECT  38.293 75.12 38.965 75.96 ;
     RECT  37.933 72.288 39.013 73.608 ;
     RECT  39.013 72.288 39.049 74.04 ;
     RECT  38.965 75.024 39.049 75.96 ;
     RECT  37.667 62.64 39.053 65.976 ;
     RECT  38.693 53.76 39.059 61.224 ;
     RECT  38.761 47.664 39.085 52.488 ;
     RECT  39.059 53.76 39.085 56.088 ;
     RECT  38.297 38.928 39.125 39.384 ;
     RECT  39.053 63.024 39.157 65.976 ;
     RECT  38.725 67.44 39.157 69.48 ;
     RECT  38.833 70.512 39.157 70.632 ;
     RECT  38.225 40.416 39.229 46.536 ;
     RECT  38.869 2.304 39.265 4.776 ;
     RECT  38.225 6.048 39.265 9.096 ;
     RECT  39.265 2.304 39.301 9.096 ;
     RECT  39.157 63.024 39.301 69.48 ;
     RECT  39.157 70.512 39.301 70.68 ;
     RECT  39.301 2.304 39.337 9.144 ;
     RECT  39.049 72.288 39.373 75.96 ;
     RECT  38.905 13.824 39.481 13.848 ;
     RECT  39.125 38.928 39.481 38.952 ;
     RECT  39.373 72 39.493 75.96 ;
     RECT  38.579 76.944 39.493 78.456 ;
     RECT  39.301 63.024 39.589 70.68 ;
     RECT  39.229 40.128 39.625 46.536 ;
     RECT  39.085 47.664 39.625 56.088 ;
     RECT  38.531 10.752 39.661 12.792 ;
     RECT  39.481 13.824 39.661 14.184 ;
     RECT  39.337 2.304 39.685 9.624 ;
     RECT  38.009 93.552 39.685 94.392 ;
     RECT  38.725 95.424 39.685 97.176 ;
     RECT  39.661 10.752 39.781 14.184 ;
     RECT  38.797 31.488 39.805 32.76 ;
     RECT  38.801 34.368 39.805 35.448 ;
     RECT  38.821 15.408 39.841 22.056 ;
     RECT  38.771 23.184 39.841 30.36 ;
     RECT  38.333 37.008 39.841 37.032 ;
     RECT  39.685 1.728 39.877 9.624 ;
     RECT  39.781 10.752 39.877 14.424 ;
     RECT  39.841 15.408 39.913 30.36 ;
     RECT  39.493 72 40.069 78.456 ;
     RECT  39.337 79.536 40.069 79.56 ;
     RECT  39.913 15.408 40.093 30.408 ;
     RECT  39.805 31.488 40.093 35.448 ;
     RECT  40.069 72 40.165 79.56 ;
     RECT  38.909 80.544 40.165 92.28 ;
     RECT  39.877 1.728 40.208 14.424 ;
     RECT  40.093 15.408 40.208 35.448 ;
     RECT  39.841 36.864 40.208 37.032 ;
     RECT  39.481 38.16 40.208 38.952 ;
     RECT  39.625 40.128 40.208 56.088 ;
     RECT  39.059 57.264 40.208 61.224 ;
     RECT  39.589 63.024 40.208 70.824 ;
     RECT  40.165 72 40.208 92.28 ;
     RECT  39.685 93.552 40.208 97.176 ;
     RECT  39.301 0.096 40.453 0.12 ;
     RECT  40.208 1.728 40.504 97.176 ;
     RECT  40.453 0.096 40.549 0.36 ;
     RECT  40.504 1.728 40.565 20.712 ;
     RECT  40.504 77.328 40.601 78.696 ;
     RECT  40.504 23.904 40.643 51 ;
     RECT  40.601 78.384 40.643 78.696 ;
     RECT  40.549 0.096 40.691 0.456 ;
     RECT  40.643 46.464 40.709 51 ;
     RECT  40.643 23.904 40.781 45.48 ;
     RECT  40.709 47.568 40.781 51 ;
     RECT  40.691 0.096 40.787 0.264 ;
     RECT  40.504 93.552 40.817 97.176 ;
     RECT  40.781 40.128 40.835 45.48 ;
     RECT  40.504 70.56 40.835 70.824 ;
     RECT  40.504 71.904 40.835 75 ;
     RECT  40.781 47.664 40.853 51 ;
     RECT  40.565 2.304 40.925 20.712 ;
     RECT  40.504 52.464 40.925 52.728 ;
     RECT  40.787 0.096 40.979 0.216 ;
     RECT  40.781 23.904 40.997 38.952 ;
     RECT  40.504 80.064 41.069 91.896 ;
     RECT  41.069 82.608 41.177 91.896 ;
     RECT  41.069 80.064 41.219 81.624 ;
     RECT  40.997 31.344 41.249 38.952 ;
     RECT  41.177 82.8 41.285 91.896 ;
     RECT  40.835 40.128 41.315 40.392 ;
     RECT  41.285 88.896 41.357 91.896 ;
     RECT  41.285 82.8 41.555 87.912 ;
     RECT  40.835 70.8 41.557 70.824 ;
     RECT  40.835 71.904 41.557 74.76 ;
     RECT  41.219 80.064 41.569 81.432 ;
     RECT  40.925 2.304 41.573 9.192 ;
     RECT  40.817 94.08 41.573 97.176 ;
     RECT  40.504 76.272 41.605 76.344 ;
     RECT  40.504 53.808 41.681 66.6 ;
     RECT  41.557 70.8 41.681 74.76 ;
     RECT  41.569 79.968 41.681 81.432 ;
     RECT  41.573 2.304 41.749 8.904 ;
     RECT  41.605 75.84 41.749 76.344 ;
     RECT  40.601 77.328 41.749 77.352 ;
     RECT  41.249 31.344 41.825 35.112 ;
     RECT  41.681 79.968 41.825 80.808 ;
     RECT  40.709 46.464 41.857 46.536 ;
     RECT  40.853 47.664 41.857 49.8 ;
     RECT  41.681 70.8 41.857 73.512 ;
     RECT  40.853 50.784 41.893 51 ;
     RECT  40.925 52.464 41.893 52.488 ;
     RECT  40.643 78.672 41.893 78.696 ;
     RECT  41.681 53.808 41.897 57.384 ;
     RECT  40.925 10.272 41.965 20.712 ;
     RECT  40.504 21.696 41.965 22.776 ;
     RECT  40.997 23.904 41.965 30.36 ;
     RECT  40.835 41.664 41.965 45.48 ;
     RECT  41.857 46.464 41.965 49.8 ;
     RECT  41.897 53.808 41.965 57.24 ;
     RECT  41.555 83.088 41.969 87.912 ;
     RECT  41.965 23.904 42.037 30.888 ;
     RECT  41.749 1.728 42.077 8.904 ;
     RECT  41.965 10.272 42.085 22.776 ;
     RECT  42.037 23.856 42.085 30.888 ;
     RECT  41.681 58.56 42.113 66.6 ;
     RECT  41.969 83.088 42.113 86.616 ;
     RECT  41.969 87.744 42.113 87.912 ;
     RECT  42.113 83.088 42.131 86.472 ;
     RECT  40.504 67.632 42.133 69.528 ;
     RECT  42.113 58.56 42.179 66.408 ;
     RECT  41.357 88.896 42.179 91.32 ;
     RECT  41.315 40.224 42.181 40.392 ;
     RECT  42.113 87.744 42.185 87.816 ;
     RECT  42.179 89.424 42.185 91.32 ;
     RECT  41.893 50.784 42.217 52.488 ;
     RECT  41.681 74.592 42.217 74.76 ;
     RECT  41.749 75.84 42.217 77.352 ;
     RECT  42.077 2.256 42.221 8.904 ;
     RECT  41.249 36.24 42.257 38.952 ;
     RECT  42.185 87.744 42.257 87.768 ;
     RECT  42.085 10.272 42.289 30.888 ;
     RECT  41.965 41.664 42.361 49.8 ;
     RECT  42.217 50.784 42.361 52.536 ;
     RECT  42.289 10.032 42.371 30.888 ;
     RECT  42.257 37.584 42.421 38.952 ;
     RECT  42.181 40.224 42.421 40.44 ;
     RECT  42.371 10.272 42.437 30.888 ;
     RECT  42.437 10.272 42.515 13.752 ;
     RECT  41.573 94.32 42.581 97.176 ;
     RECT  42.581 94.32 42.611 97.08 ;
     RECT  41.825 32.256 42.613 35.112 ;
     RECT  42.257 36.24 42.613 36.36 ;
     RECT  42.515 10.272 42.617 10.296 ;
     RECT  42.421 37.584 42.721 40.44 ;
     RECT  42.361 41.664 42.721 52.536 ;
     RECT  41.857 70.704 42.721 73.512 ;
     RECT  42.217 74.592 42.721 77.352 ;
     RECT  41.893 78.672 42.721 78.744 ;
     RECT  42.721 70.704 42.757 78.792 ;
     RECT  41.825 79.968 42.757 80.52 ;
     RECT  42.185 89.424 42.761 89.496 ;
     RECT  42.221 7.968 42.793 8.904 ;
     RECT  42.721 37.584 42.865 52.536 ;
     RECT  41.965 53.568 42.865 57.24 ;
     RECT  42.179 66.192 42.899 66.408 ;
     RECT  42.131 83.088 42.901 85.512 ;
     RECT  42.611 94.32 42.905 97.032 ;
     RECT  42.515 11.328 42.941 13.752 ;
     RECT  42.905 94.32 42.949 94.344 ;
     RECT  42.757 70.704 42.973 80.52 ;
     RECT  42.865 37.584 43.117 57.24 ;
     RECT  42.179 58.56 43.117 65.016 ;
     RECT  42.973 70.704 43.117 80.712 ;
     RECT  43.117 37.584 43.121 65.016 ;
     RECT  43.117 70.704 43.187 81.144 ;
     RECT  43.121 37.584 43.301 51.912 ;
     RECT  43.187 70.704 43.301 75.672 ;
     RECT  42.221 2.256 43.331 6.792 ;
     RECT  43.187 76.752 43.337 81.144 ;
     RECT  42.133 67.44 43.369 69.528 ;
     RECT  43.301 70.704 43.369 73.272 ;
     RECT  43.331 3.744 43.379 6.792 ;
     RECT  43.301 41.664 43.409 51.912 ;
     RECT  43.121 53.376 43.427 65.016 ;
     RECT  42.437 14.784 43.441 30.888 ;
     RECT  42.613 32.256 43.441 36.36 ;
     RECT  43.301 37.584 43.441 40.344 ;
     RECT  43.441 14.784 43.481 40.344 ;
     RECT  43.481 14.784 43.573 37.032 ;
     RECT  43.379 4.224 43.621 6.792 ;
     RECT  42.793 7.968 43.621 9.096 ;
     RECT  43.427 59.232 43.621 65.016 ;
     RECT  42.899 66.192 43.621 66.36 ;
     RECT  42.901 83.04 43.621 85.512 ;
     RECT  40.979 0.096 43.625 0.12 ;
     RECT  43.409 44.688 43.625 51.912 ;
     RECT  43.573 14.688 43.715 37.032 ;
     RECT  43.715 14.688 43.763 25.224 ;
     RECT  43.763 14.688 43.841 25.08 ;
     RECT  43.621 59.232 43.873 66.36 ;
     RECT  43.369 67.44 43.873 73.272 ;
     RECT  43.621 82.224 43.873 85.512 ;
     RECT  42.949 94.08 43.873 94.344 ;
     RECT  42.905 95.424 43.873 97.032 ;
     RECT  43.873 59.232 43.877 73.272 ;
     RECT  43.873 94.08 43.909 97.032 ;
     RECT  42.941 11.328 43.949 13.656 ;
     RECT  43.841 18.528 43.949 25.08 ;
     RECT  43.625 44.688 43.949 51.768 ;
     RECT  43.621 4.224 43.955 9.096 ;
     RECT  43.909 87.936 43.981 87.96 ;
     RECT  42.185 90.528 44.021 91.32 ;
     RECT  43.337 78.336 44.053 81.144 ;
     RECT  43.873 82.224 44.053 86.328 ;
     RECT  43.949 11.472 44.089 13.656 ;
     RECT  43.841 14.688 44.089 17.496 ;
     RECT  43.331 2.256 44.129 2.52 ;
     RECT  44.089 11.472 44.237 17.496 ;
     RECT  43.909 94.08 44.237 97.08 ;
     RECT  44.237 11.472 44.243 14.664 ;
     RECT  43.427 53.376 44.341 58.2 ;
     RECT  44.053 78.336 44.341 86.328 ;
     RECT  43.301 74.544 44.377 75.672 ;
     RECT  43.955 7.392 44.413 9.096 ;
     RECT  44.377 74.544 44.413 75.72 ;
     RECT  43.337 76.752 44.413 77.352 ;
     RECT  43.981 87.744 44.413 87.96 ;
     RECT  42.761 89.424 44.413 89.448 ;
     RECT  43.877 70.656 44.437 73.272 ;
     RECT  43.409 41.664 44.449 43.368 ;
     RECT  44.237 15.888 44.561 17.496 ;
     RECT  43.481 38.208 44.581 40.344 ;
     RECT  43.949 46.896 44.629 51.768 ;
     RECT  44.341 52.992 44.665 58.2 ;
     RECT  43.877 59.232 44.665 69.672 ;
     RECT  44.413 7.392 44.809 9.288 ;
     RECT  44.437 10.32 44.809 10.344 ;
     RECT  44.449 41.664 44.917 43.464 ;
     RECT  43.949 44.688 44.917 45.576 ;
     RECT  44.243 11.472 44.953 14.616 ;
     RECT  44.437 70.656 44.953 73.368 ;
     RECT  44.413 74.544 44.953 77.352 ;
     RECT  44.917 41.664 45.013 45.576 ;
     RECT  44.953 70.656 45.013 77.352 ;
     RECT  44.341 78.336 45.013 86.472 ;
     RECT  44.561 17.424 45.061 17.496 ;
     RECT  43.949 18.528 45.061 24.744 ;
     RECT  43.715 26.208 45.097 37.032 ;
     RECT  44.581 38.16 45.097 40.344 ;
     RECT  44.665 52.992 45.097 69.672 ;
     RECT  45.013 70.656 45.097 86.472 ;
     RECT  44.809 7.392 45.109 10.344 ;
     RECT  44.953 11.424 45.109 14.616 ;
     RECT  44.129 2.496 45.169 2.52 ;
     RECT  45.169 2.496 45.349 2.856 ;
     RECT  43.955 4.224 45.349 6.36 ;
     RECT  45.109 7.392 45.349 14.616 ;
     RECT  45.097 52.992 45.421 86.472 ;
     RECT  45.349 2.496 45.493 14.616 ;
     RECT  44.561 15.888 45.493 16.44 ;
     RECT  45.493 2.496 45.529 16.44 ;
     RECT  45.061 17.424 45.529 24.744 ;
     RECT  44.413 87.744 45.529 89.448 ;
     RECT  44.021 90.528 45.529 91.176 ;
     RECT  45.529 2.496 45.601 24.744 ;
     RECT  45.601 2.496 45.608 25.224 ;
     RECT  45.097 26.208 45.608 40.344 ;
     RECT  45.013 41.568 45.608 45.576 ;
     RECT  44.629 46.896 45.608 51.912 ;
     RECT  45.421 52.992 45.608 86.76 ;
     RECT  45.529 87.744 45.608 91.176 ;
     RECT  45.349 92.208 45.608 92.232 ;
     RECT  44.237 94.32 45.608 97.08 ;
     RECT  45.608 2.148 45.712 97.08 ;
     RECT  45.712 2.418 45.904 97.08 ;
     RECT  45.904 13.104 46.019 92.28 ;
     RECT  46.019 13.104 46.037 52.008 ;
     RECT  46.037 31.632 46.067 52.008 ;
     RECT  46.019 52.992 46.067 92.28 ;
     RECT  45.904 4.08 46.217 11.976 ;
     RECT  46.067 52.992 46.217 70.344 ;
     RECT  46.037 13.104 46.253 30.6 ;
     RECT  45.904 2.832 46.289 2.856 ;
     RECT  46.253 22.224 46.289 30.6 ;
     RECT  46.067 35.712 46.541 52.008 ;
     RECT  46.217 57.024 46.685 70.344 ;
     RECT  46.067 71.328 46.739 92.28 ;
     RECT  46.217 4.08 46.757 11.544 ;
     RECT  46.541 37.92 46.835 52.008 ;
     RECT  46.739 79.536 46.897 92.28 ;
     RECT  46.685 57.024 46.901 69.576 ;
     RECT  46.253 13.104 46.933 21.24 ;
     RECT  46.067 31.632 46.937 34.536 ;
     RECT  46.217 52.992 46.937 55.608 ;
     RECT  46.757 5.76 46.979 11.544 ;
     RECT  46.289 22.224 46.979 30.36 ;
     RECT  46.739 71.328 47.041 78.504 ;
     RECT  46.979 5.76 47.075 11.496 ;
     RECT  46.937 31.968 47.077 34.536 ;
     RECT  46.541 35.712 47.077 36.6 ;
     RECT  46.897 79.536 47.077 92.376 ;
     RECT  47.041 70.656 47.081 78.504 ;
     RECT  47.081 70.656 47.123 77.976 ;
     RECT  45.904 94.08 47.123 97.08 ;
     RECT  46.901 57.024 47.189 62.28 ;
     RECT  47.077 79.536 47.261 92.424 ;
     RECT  47.075 5.76 47.267 11.4 ;
     RECT  46.835 46.224 47.267 52.008 ;
     RECT  47.267 5.76 47.297 9.672 ;
     RECT  47.077 31.968 47.315 36.6 ;
     RECT  46.933 12.912 47.317 21.24 ;
     RECT  46.979 22.224 47.317 27.672 ;
     RECT  47.297 5.76 47.333 9.336 ;
     RECT  47.267 10.848 47.369 11.4 ;
     RECT  47.317 12.912 47.441 27.672 ;
     RECT  47.333 6 47.459 9.336 ;
     RECT  46.901 63.504 47.477 69.576 ;
     RECT  47.441 12.912 47.507 25.8 ;
     RECT  47.441 26.784 47.513 27.672 ;
     RECT  47.513 26.832 47.621 27.672 ;
     RECT  47.459 6 47.657 7.752 ;
     RECT  47.507 12.912 47.657 25.512 ;
     RECT  46.835 37.92 47.689 45.048 ;
     RECT  47.189 57.168 47.693 62.28 ;
     RECT  47.477 63.792 47.699 69.576 ;
     RECT  47.315 31.968 47.729 36.408 ;
     RECT  47.261 84.864 47.801 92.424 ;
     RECT  47.657 6.24 47.837 7.752 ;
     RECT  47.657 15.696 47.837 25.512 ;
     RECT  47.837 20.064 47.873 25.512 ;
     RECT  46.937 52.992 47.909 55.56 ;
     RECT  46.757 4.08 47.941 4.104 ;
     RECT  47.267 46.224 47.981 51.816 ;
     RECT  47.693 57.6 47.981 62.28 ;
     RECT  47.941 3.408 47.987 4.104 ;
     RECT  47.981 57.6 48.035 60.84 ;
     RECT  47.981 62.16 48.035 62.28 ;
     RECT  47.699 68.88 48.133 69.576 ;
     RECT  47.123 71.28 48.157 77.976 ;
     RECT  47.801 84.96 48.161 92.424 ;
     RECT  47.837 15.696 48.197 18.936 ;
     RECT  48.035 57.6 48.197 60.552 ;
     RECT  46.979 28.707 48.229 30.36 ;
     RECT  47.909 52.992 48.233 55.512 ;
     RECT  48.197 57.6 48.233 60.264 ;
     RECT  48.161 84.96 48.233 91.08 ;
     RECT  47.873 20.064 48.269 24.744 ;
     RECT  47.261 79.536 48.277 83.784 ;
     RECT  48.157 71.28 48.301 78.12 ;
     RECT  48.269 20.064 48.305 20.616 ;
     RECT  47.689 37.776 48.373 45.048 ;
     RECT  47.981 46.32 48.373 51.816 ;
     RECT  48.233 52.992 48.373 54.744 ;
     RECT  48.233 84.96 48.485 90.408 ;
     RECT  47.621 27.072 48.517 27.672 ;
     RECT  48.229 28.707 48.517 30.936 ;
     RECT  48.517 27.072 48.563 30.936 ;
     RECT  47.369 11.376 48.589 11.4 ;
     RECT  48.373 37.776 48.593 45.096 ;
     RECT  48.485 84.96 48.593 90.072 ;
     RECT  47.987 3.408 48.625 3.432 ;
     RECT  48.589 10.848 48.625 11.4 ;
     RECT  48.625 10.848 48.661 11.832 ;
     RECT  47.657 12.912 48.661 13.896 ;
     RECT  48.161 92.208 48.661 92.424 ;
     RECT  47.837 7.344 48.697 7.752 ;
     RECT  47.699 63.792 48.709 67.896 ;
     RECT  48.133 68.88 48.709 69.72 ;
     RECT  48.709 63.792 48.733 69.72 ;
     RECT  48.233 57.6 48.757 58.728 ;
     RECT  48.697 7.344 48.769 7.848 ;
     RECT  47.459 8.928 48.769 9.336 ;
     RECT  47.837 6.24 48.805 6.312 ;
     RECT  48.035 62.256 48.805 62.28 ;
     RECT  47.729 32.064 48.809 36.408 ;
     RECT  48.757 56.88 48.809 58.728 ;
     RECT  48.593 84.96 48.809 89.496 ;
     RECT  48.661 92.208 48.809 92.904 ;
     RECT  48.809 92.352 48.853 92.904 ;
     RECT  47.123 94.272 48.853 97.08 ;
     RECT  48.805 62.256 48.877 62.664 ;
     RECT  48.733 63.792 48.877 69.864 ;
     RECT  48.769 7.344 48.947 9.336 ;
     RECT  48.877 62.256 48.949 69.864 ;
     RECT  48.301 71.232 48.949 78.12 ;
     RECT  48.809 32.064 48.953 36.36 ;
     RECT  48.809 84.96 48.985 88.92 ;
     RECT  48.553 4.56 49.043 4.584 ;
     RECT  48.593 39.888 49.043 45.096 ;
     RECT  48.953 32.064 49.057 36.264 ;
     RECT  48.593 37.776 49.061 38.76 ;
     RECT  48.305 20.592 49.091 20.616 ;
     RECT  48.949 62.256 49.093 78.12 ;
     RECT  48.947 7.344 49.169 9.048 ;
     RECT  48.853 92.352 49.169 97.08 ;
     RECT  49.093 61.776 49.187 78.12 ;
     RECT  48.805 6.048 49.201 6.312 ;
     RECT  49.169 7.344 49.201 7.848 ;
     RECT  49.043 40.992 49.201 45.096 ;
     RECT  48.373 46.32 49.201 54.744 ;
     RECT  48.809 57.6 49.201 58.728 ;
     RECT  49.093 56.4 49.205 56.424 ;
     RECT  48.661 10.848 49.237 13.896 ;
     RECT  48.197 15.696 49.237 18.264 ;
     RECT  49.237 10.848 49.273 18.264 ;
     RECT  49.045 19.296 49.273 19.32 ;
     RECT  48.277 79.536 49.309 83.832 ;
     RECT  49.201 5.808 49.333 7.848 ;
     RECT  49.201 40.992 49.381 54.744 ;
     RECT  49.333 5.088 49.385 7.848 ;
     RECT  49.057 31.968 49.417 36.264 ;
     RECT  49.273 10.848 49.427 19.32 ;
     RECT  48.563 27.6 49.489 30.936 ;
     RECT  49.417 31.92 49.489 36.264 ;
     RECT  49.385 5.808 49.523 7.848 ;
     RECT  49.489 27.6 49.525 36.264 ;
     RECT  49.309 79.152 49.525 83.832 ;
     RECT  48.985 84.816 49.525 88.92 ;
     RECT  49.061 38.016 49.561 38.76 ;
     RECT  49.043 39.888 49.561 39.912 ;
     RECT  49.187 62.544 49.571 78.12 ;
     RECT  49.525 27.072 49.573 36.264 ;
     RECT  48.269 22.176 49.669 24.744 ;
     RECT  48.233 60.24 49.705 60.264 ;
     RECT  49.345 20.832 49.741 21.144 ;
     RECT  49.669 22.176 49.741 25.464 ;
     RECT  49.705 60.24 49.781 61.224 ;
     RECT  49.381 40.992 49.853 54.792 ;
     RECT  49.571 67.728 49.853 78.12 ;
     RECT  49.573 26.784 49.921 36.264 ;
     RECT  49.853 67.872 49.921 78.12 ;
     RECT  49.525 79.152 49.921 88.92 ;
     RECT  49.201 57.6 49.957 59.208 ;
     RECT  49.781 60.24 49.957 61.176 ;
     RECT  49.169 92.352 49.957 93.24 ;
     RECT  49.921 26.784 49.961 36.936 ;
     RECT  49.853 41.424 49.961 54.792 ;
     RECT  49.921 67.872 49.961 88.92 ;
     RECT  49.427 10.848 50.029 18.264 ;
     RECT  49.961 79.44 50.065 88.92 ;
     RECT  49.957 57.6 50.101 61.176 ;
     RECT  49.957 90.048 50.197 90.072 ;
     RECT  48.625 2.832 50.209 3.432 ;
     RECT  49.961 26.88 50.209 36.936 ;
     RECT  49.561 38.016 50.209 39.912 ;
     RECT  50.101 57.456 50.209 61.176 ;
     RECT  50.065 79.44 50.245 88.968 ;
     RECT  50.197 90 50.245 90.072 ;
     RECT  49.957 91.632 50.293 93.24 ;
     RECT  49.169 94.272 50.293 97.08 ;
     RECT  50.293 91.632 50.353 97.08 ;
     RECT  49.427 19.296 50.389 19.32 ;
     RECT  50.389 19.296 50.461 19.464 ;
     RECT  49.741 20.832 50.461 25.464 ;
     RECT  49.523 5.808 50.485 6.36 ;
     RECT  49.523 7.344 50.485 7.848 ;
     RECT  50.209 2.832 50.497 3.912 ;
     RECT  50.497 2.64 50.533 4.584 ;
     RECT  50.485 5.808 50.533 7.848 ;
     RECT  49.169 8.928 50.533 9.048 ;
     RECT  50.461 19.296 50.533 25.464 ;
     RECT  50.533 2.64 50.569 9.048 ;
     RECT  50.029 10.08 50.569 18.264 ;
     RECT  50.533 19.296 50.569 25.704 ;
     RECT  50.209 57.312 50.713 61.176 ;
     RECT  50.569 2.352 50.785 9.048 ;
     RECT  50.569 10.08 50.785 25.704 ;
     RECT  49.571 62.544 50.869 66.504 ;
     RECT  49.961 67.872 50.929 78.216 ;
     RECT  50.245 79.44 50.929 90.072 ;
     RECT  50.209 26.88 50.965 39.912 ;
     RECT  49.961 41.424 50.965 54.744 ;
     RECT  50.785 2.352 51.008 25.704 ;
     RECT  50.965 26.88 51.008 54.744 ;
     RECT  50.713 55.872 51.008 61.176 ;
     RECT  50.869 62.208 51.008 66.504 ;
     RECT  50.929 67.872 51.008 90.072 ;
     RECT  50.353 91.344 51.008 97.08 ;
     RECT  51.008 2.148 51.112 97.08 ;
     RECT  51.112 2.256 51.304 97.08 ;
     RECT  51.304 34.176 51.401 35.832 ;
     RECT  51.304 37.68 51.443 41.448 ;
     RECT  51.304 60 51.443 83.352 ;
     RECT  51.443 37.68 51.581 38.808 ;
     RECT  51.443 68.688 51.617 83.352 ;
     RECT  51.304 94.272 51.635 97.08 ;
     RECT  51.635 94.272 51.731 96.312 ;
     RECT  51.443 60 51.827 67.032 ;
     RECT  51.617 68.88 51.827 83.352 ;
     RECT  51.304 42.48 51.869 51.72 ;
     RECT  51.731 94.272 51.869 95.784 ;
     RECT  51.827 68.928 51.875 83.352 ;
     RECT  51.875 68.928 51.905 81.528 ;
     RECT  51.401 34.752 51.923 35.832 ;
     RECT  51.304 84.384 51.941 89.064 ;
     RECT  51.905 68.928 52.013 75.192 ;
     RECT  51.923 34.896 52.019 35.832 ;
     RECT  52.013 68.928 52.121 74.712 ;
     RECT  51.875 82.752 52.157 83.352 ;
     RECT  51.827 60 52.163 65.784 ;
     RECT  52.163 60 52.229 62.184 ;
     RECT  52.163 63.168 52.259 65.784 ;
     RECT  52.019 34.896 52.265 35.688 ;
     RECT  51.304 52.752 52.297 58.68 ;
     RECT  52.229 60 52.297 61.656 ;
     RECT  51.304 91.248 52.297 93.096 ;
     RECT  51.869 94.272 52.297 94.68 ;
     RECT  51.905 76.368 52.337 81.528 ;
     RECT  51.869 43.296 52.355 51.72 ;
     RECT  52.355 47.088 52.357 51.72 ;
     RECT  52.297 52.752 52.357 61.656 ;
     RECT  51.443 40.56 52.405 41.448 ;
     RECT  52.157 82.848 52.441 83.352 ;
     RECT  51.941 84.384 52.441 87.624 ;
     RECT  51.304 90.048 52.441 90.072 ;
     RECT  52.297 91.248 52.441 94.68 ;
     RECT  52.357 47.088 52.445 61.656 ;
     RECT  52.405 40.56 52.451 42.216 ;
     RECT  51.941 88.608 52.501 89.064 ;
     RECT  52.441 90.048 52.501 94.68 ;
     RECT  51.304 15.312 52.513 33.096 ;
     RECT  51.827 67.008 52.513 67.032 ;
     RECT  52.259 63.168 52.517 64.92 ;
     RECT  51.304 2.256 52.549 14.088 ;
     RECT  52.513 15.312 52.549 33.528 ;
     RECT  51.581 38.4 52.549 38.808 ;
     RECT  52.549 1.728 52.645 33.528 ;
     RECT  52.445 54.096 52.691 61.656 ;
     RECT  52.645 1.68 52.697 33.528 ;
     RECT  52.549 37.584 52.765 38.808 ;
     RECT  52.517 63.168 52.787 64.632 ;
     RECT  52.451 40.56 52.789 41.16 ;
     RECT  52.513 67.008 52.801 67.272 ;
     RECT  52.787 63.168 52.805 64.152 ;
     RECT  52.691 55.776 52.835 61.656 ;
     RECT  52.805 63.168 52.835 63.864 ;
     RECT  52.355 43.296 52.837 46.104 ;
     RECT  52.697 1.728 52.841 33.528 ;
     RECT  52.801 66.096 52.883 67.272 ;
     RECT  51.869 95.76 52.909 95.784 ;
     RECT  52.441 82.848 52.981 87.624 ;
     RECT  52.501 88.608 52.981 94.68 ;
     RECT  52.837 43.248 52.985 46.104 ;
     RECT  52.883 66.336 52.985 67.272 ;
     RECT  52.835 55.776 53.021 60.456 ;
     RECT  52.121 68.928 53.027 73.56 ;
     RECT  52.265 34.896 53.053 35.352 ;
     RECT  52.445 47.088 53.123 53.064 ;
     RECT  53.021 56.496 53.123 60.456 ;
     RECT  53.123 56.496 53.129 59.592 ;
     RECT  53.123 47.088 53.165 50.664 ;
     RECT  53.129 57.456 53.165 59.592 ;
     RECT  53.165 57.456 53.171 58.824 ;
     RECT  53.165 49.584 53.237 50.664 ;
     RECT  53.053 34.56 53.269 35.352 ;
     RECT  52.981 82.848 53.305 94.68 ;
     RECT  53.269 34.56 53.309 35.88 ;
     RECT  52.835 63.168 53.309 63.816 ;
     RECT  53.305 82.848 53.363 94.728 ;
     RECT  52.121 74.688 53.377 74.712 ;
     RECT  53.377 74.64 53.413 74.712 ;
     RECT  52.909 95.76 53.413 95.832 ;
     RECT  53.363 88.848 53.449 94.728 ;
     RECT  53.413 95.76 53.449 95.88 ;
     RECT  53.363 82.848 53.485 87.864 ;
     RECT  52.337 76.368 53.509 81.384 ;
     RECT  52.451 42.192 53.557 42.216 ;
     RECT  52.985 43.248 53.557 45.864 ;
     RECT  53.413 74.64 53.557 74.952 ;
     RECT  52.841 1.728 53.561 14.424 ;
     RECT  52.841 15.408 53.561 33.528 ;
     RECT  52.789 40.464 53.593 41.16 ;
     RECT  53.561 27.936 53.669 33.528 ;
     RECT  53.171 58.128 53.669 58.824 ;
     RECT  53.485 82.752 53.701 87.864 ;
     RECT  53.669 58.512 53.705 58.824 ;
     RECT  53.593 40.464 53.737 41.208 ;
     RECT  53.165 47.088 53.777 48.504 ;
     RECT  53.561 2.208 53.809 14.424 ;
     RECT  53.561 15.408 53.809 26.808 ;
     RECT  52.985 66.96 53.845 67.272 ;
     RECT  53.027 68.928 53.845 73.32 ;
     RECT  53.737 40.416 53.881 41.208 ;
     RECT  53.449 88.848 53.881 95.88 ;
     RECT  53.845 66.96 53.885 73.32 ;
     RECT  53.809 2.208 53.921 26.808 ;
     RECT  53.669 30.24 53.953 33.528 ;
     RECT  53.309 34.56 53.953 34.632 ;
     RECT  53.701 82.656 53.953 87.864 ;
     RECT  53.881 88.848 53.989 96.36 ;
     RECT  53.921 14.4 54.029 26.808 ;
     RECT  53.309 35.712 54.061 35.88 ;
     RECT  52.765 37.584 54.061 39.288 ;
     RECT  53.509 76.368 54.065 81.432 ;
     RECT  53.885 67.248 54.085 73.32 ;
     RECT  53.557 74.64 54.085 75 ;
     RECT  53.669 27.936 54.101 29.016 ;
     RECT  54.085 67.248 54.101 75 ;
     RECT  54.101 67.248 54.137 67.56 ;
     RECT  54.065 76.608 54.137 81.432 ;
     RECT  53.777 47.28 54.169 48.504 ;
     RECT  53.989 88.848 54.169 96.408 ;
     RECT  54.029 14.4 54.179 25.128 ;
     RECT  54.137 76.608 54.179 81.192 ;
     RECT  53.953 82.416 54.179 87.864 ;
     RECT  53.123 51.696 54.229 53.064 ;
     RECT  52.691 54.096 54.229 54.744 ;
     RECT  54.061 35.712 54.245 36.504 ;
     RECT  54.179 15.744 54.281 25.128 ;
     RECT  54.229 51.696 54.313 54.744 ;
     RECT  54.313 51.648 54.353 54.744 ;
     RECT  52.357 0.096 54.373 0.12 ;
     RECT  54.169 88.848 54.373 96.456 ;
     RECT  54.245 36.048 54.385 36.504 ;
     RECT  54.061 37.584 54.385 39.336 ;
     RECT  53.557 42.192 54.421 45.864 ;
     RECT  54.385 36.048 54.457 39.336 ;
     RECT  53.881 40.32 54.457 41.208 ;
     RECT  54.457 36.048 54.493 41.208 ;
     RECT  54.421 42.192 54.493 46.008 ;
     RECT  53.921 2.208 54.497 13.32 ;
     RECT  54.281 15.792 54.497 25.128 ;
     RECT  53.953 30.24 54.517 34.632 ;
     RECT  54.517 30.24 54.533 34.68 ;
     RECT  54.169 47.28 54.565 48.552 ;
     RECT  53.237 49.968 54.565 50.568 ;
     RECT  54.565 1.152 54.611 1.176 ;
     RECT  54.533 31.776 54.659 34.68 ;
     RECT  54.659 31.872 54.709 34.68 ;
     RECT  54.565 47.28 54.709 50.568 ;
     RECT  54.353 51.648 54.709 53.4 ;
     RECT  54.493 36.048 54.713 46.008 ;
     RECT  54.713 36.816 54.755 46.008 ;
     RECT  54.533 30.24 54.781 30.456 ;
     RECT  54.755 36.912 54.781 46.008 ;
     RECT  54.709 47.28 54.781 53.4 ;
     RECT  54.029 26.256 54.785 26.808 ;
     RECT  54.373 88.848 54.803 97.08 ;
     RECT  54.709 31.872 54.821 34.968 ;
     RECT  54.101 28.896 54.901 29.016 ;
     RECT  54.781 30.048 54.901 30.456 ;
     RECT  54.785 26.784 54.961 26.808 ;
     RECT  54.601 27.888 54.961 27.912 ;
     RECT  54.179 76.608 54.965 81.096 ;
     RECT  54.965 80.256 55.037 81.096 ;
     RECT  54.137 67.248 55.141 67.272 ;
     RECT  54.965 76.608 55.213 79.224 ;
     RECT  54.101 69.168 55.237 75 ;
     RECT  55.213 76.08 55.237 79.224 ;
     RECT  54.781 36.912 55.253 53.4 ;
     RECT  55.237 69.168 55.283 79.224 ;
     RECT  52.835 61.632 55.321 61.656 ;
     RECT  55.141 67.248 55.321 67.848 ;
     RECT  54.179 82.512 55.357 87.864 ;
     RECT  54.803 88.848 55.357 95.736 ;
     RECT  55.283 71.904 55.361 79.224 ;
     RECT  54.373 0.096 55.379 0.168 ;
     RECT  55.321 67.248 55.429 68.136 ;
     RECT  55.283 69.168 55.429 70.68 ;
     RECT  54.497 2.208 55.537 13.08 ;
     RECT  54.179 14.4 55.537 14.424 ;
     RECT  54.803 97.056 55.577 97.08 ;
     RECT  54.821 32.112 55.609 34.968 ;
     RECT  55.537 2.208 55.645 14.424 ;
     RECT  53.705 58.56 55.645 58.584 ;
     RECT  55.321 65.76 55.645 65.784 ;
     RECT  55.321 60.816 55.681 61.656 ;
     RECT  54.961 26.784 55.753 27.912 ;
     RECT  53.309 63.168 55.813 63.192 ;
     RECT  55.645 65.76 55.813 66.12 ;
     RECT  55.645 1.728 55.861 14.424 ;
     RECT  54.497 15.792 55.861 24.936 ;
     RECT  55.753 26.208 55.861 27.912 ;
     RECT  55.813 65.376 55.861 66.12 ;
     RECT  55.429 67.248 55.861 70.68 ;
     RECT  55.357 82.512 55.861 95.736 ;
     RECT  55.861 1.728 55.865 24.936 ;
     RECT  55.681 60.384 55.933 61.656 ;
     RECT  55.861 82.272 55.933 95.736 ;
     RECT  55.361 71.952 56.053 79.224 ;
     RECT  55.037 80.4 56.053 80.808 ;
     RECT  54.353 54.72 56.185 54.744 ;
     RECT  55.861 26.016 56.197 27.912 ;
     RECT  54.901 28.896 56.197 30.456 ;
     RECT  55.609 32.112 56.197 35.304 ;
     RECT  55.933 82.272 56.197 95.784 ;
     RECT  55.813 63.168 56.221 64.056 ;
     RECT  56.053 71.952 56.221 80.904 ;
     RECT  56.197 82.272 56.221 96.312 ;
     RECT  55.865 2.016 56.293 24.936 ;
     RECT  56.197 26.016 56.293 30.456 ;
     RECT  56.197 31.776 56.293 35.304 ;
     RECT  55.933 60.384 56.293 62.04 ;
     RECT  56.221 63.168 56.293 64.344 ;
     RECT  55.253 37.44 56.401 53.4 ;
     RECT  56.293 2.016 56.408 35.304 ;
     RECT  56.401 36.912 56.408 53.4 ;
     RECT  56.185 54.72 56.408 54.792 ;
     RECT  55.645 58.56 56.408 58.68 ;
     RECT  56.293 60.384 56.408 64.344 ;
     RECT  55.861 65.376 56.408 70.68 ;
     RECT  56.221 71.952 56.408 96.312 ;
     RECT  55.379 0.096 56.485 0.12 ;
     RECT  56.485 0.096 56.621 0.552 ;
     RECT  56.408 2.016 56.677 96.312 ;
     RECT  56.677 2.016 56.704 97.08 ;
     RECT  56.621 0.096 56.819 0.312 ;
     RECT  56.704 58.8 56.819 97.08 ;
     RECT  56.704 2.016 56.915 39.528 ;
     RECT  56.915 14.448 56.945 39.528 ;
     RECT  56.819 0.096 57.011 0.264 ;
     RECT  56.945 14.448 57.011 26.952 ;
     RECT  56.704 42.48 57.011 53.4 ;
     RECT  57.011 50.016 57.053 53.4 ;
     RECT  56.915 2.016 57.061 13.128 ;
     RECT  57.011 0.096 57.089 0.12 ;
     RECT  57.061 1.728 57.107 13.128 ;
     RECT  57.107 1.728 57.125 5.496 ;
     RECT  57.107 6.672 57.161 13.128 ;
     RECT  57.011 21.072 57.233 26.952 ;
     RECT  57.161 6.816 57.251 13.128 ;
     RECT  57.233 21.072 57.299 24.408 ;
     RECT  57.053 50.016 57.347 53.16 ;
     RECT  57.251 6.816 57.413 10.344 ;
     RECT  57.233 25.488 57.413 26.952 ;
     RECT  56.819 58.8 57.443 86.28 ;
     RECT  56.945 28.128 57.449 39.528 ;
     RECT  57.443 67.248 57.485 86.28 ;
     RECT  56.819 87.312 57.587 97.08 ;
     RECT  57.011 42.48 57.629 49.032 ;
     RECT  57.125 2.256 57.683 5.496 ;
     RECT  56.704 40.56 57.697 41.496 ;
     RECT  57.629 42.48 57.697 48.984 ;
     RECT  57.449 36.096 57.733 39.528 ;
     RECT  57.697 40.56 57.733 48.984 ;
     RECT  57.485 72 57.773 86.28 ;
     RECT  57.413 25.488 57.779 26.616 ;
     RECT  57.587 97.056 57.809 97.08 ;
     RECT  57.773 72.24 57.827 86.28 ;
     RECT  57.587 87.312 57.845 95.784 ;
     RECT  57.251 11.328 57.877 13.128 ;
     RECT  57.011 14.448 57.877 19.848 ;
     RECT  57.845 88.896 57.923 95.784 ;
     RECT  57.449 28.128 57.949 35.016 ;
     RECT  57.845 87.312 57.989 87.816 ;
     RECT  57.683 2.304 58.025 5.496 ;
     RECT  57.827 82.128 58.057 86.28 ;
     RECT  57.989 87.312 58.057 87.768 ;
     RECT  58.025 3.984 58.061 5.496 ;
     RECT  57.923 90 58.067 95.784 ;
     RECT  57.949 27.744 58.097 35.016 ;
     RECT  57.923 88.896 58.115 88.92 ;
     RECT  58.067 90 58.115 91.32 ;
     RECT  57.443 58.8 58.133 66.216 ;
     RECT  58.115 91.056 58.133 91.32 ;
     RECT  58.067 92.304 58.163 95.784 ;
     RECT  58.025 2.304 58.205 2.472 ;
     RECT  57.413 6.816 58.205 9.288 ;
     RECT  58.133 58.8 58.205 63.192 ;
     RECT  58.163 92.928 58.205 95.784 ;
     RECT  56.704 54.72 58.211 54.744 ;
     RECT  58.057 82.128 58.211 87.768 ;
     RECT  58.061 3.984 58.277 4.008 ;
     RECT  58.097 34.272 58.277 35.016 ;
     RECT  57.413 10.272 58.309 10.344 ;
     RECT  57.877 11.328 58.309 19.848 ;
     RECT  57.299 21.072 58.313 22.296 ;
     RECT  58.133 64.368 58.385 66.216 ;
     RECT  58.211 84.24 58.385 87.768 ;
     RECT  58.385 84.24 58.421 84.84 ;
     RECT  58.385 85.824 58.421 87.768 ;
     RECT  57.779 25.68 58.453 26.616 ;
     RECT  58.097 27.744 58.453 33.288 ;
     RECT  58.061 5.088 58.457 5.496 ;
     RECT  58.421 84.288 58.457 84.84 ;
     RECT  58.205 7.728 58.489 9.288 ;
     RECT  58.309 10.272 58.489 19.848 ;
     RECT  57.299 23.328 58.489 24.408 ;
     RECT  57.733 36.096 58.493 48.984 ;
     RECT  58.453 25.68 58.529 33.288 ;
     RECT  58.313 21.072 58.597 22.248 ;
     RECT  58.457 5.136 58.601 5.496 ;
     RECT  58.489 7.728 58.673 19.848 ;
     RECT  58.385 64.416 58.693 66.216 ;
     RECT  57.485 67.248 58.693 71.016 ;
     RECT  58.277 34.992 58.741 35.016 ;
     RECT  58.493 36.096 58.741 45.624 ;
     RECT  58.601 5.28 58.745 5.496 ;
     RECT  58.493 46.608 58.745 48.984 ;
     RECT  58.133 91.056 58.745 91.08 ;
     RECT  58.205 93.744 58.777 95.784 ;
     RECT  58.345 6.624 58.787 6.648 ;
     RECT  58.777 93.744 58.813 96.36 ;
     RECT  57.347 50.112 58.849 53.16 ;
     RECT  58.673 7.968 58.961 19.848 ;
     RECT  58.529 27.504 58.961 33.288 ;
     RECT  58.205 58.8 58.961 62.808 ;
     RECT  58.745 46.608 59.027 48.936 ;
     RECT  58.849 50.112 59.027 53.592 ;
     RECT  58.961 30.624 59.125 33.288 ;
     RECT  59.027 50.112 59.125 53.352 ;
     RECT  58.693 64.416 59.125 71.016 ;
     RECT  57.827 72.24 59.125 81 ;
     RECT  58.813 93.744 59.137 96.456 ;
     RECT  58.961 58.8 59.177 62.28 ;
     RECT  58.211 82.128 59.269 83.112 ;
     RECT  59.125 30.624 59.285 33.672 ;
     RECT  58.457 84.288 59.315 84.648 ;
     RECT  59.125 64.416 59.353 81 ;
     RECT  59.269 82.128 59.363 83.208 ;
     RECT  58.597 20.832 59.365 22.248 ;
     RECT  58.489 23.328 59.365 24.552 ;
     RECT  59.353 63.84 59.365 81 ;
     RECT  59.365 63.504 59.413 81 ;
     RECT  59.363 82.464 59.429 83.208 ;
     RECT  58.961 11.376 59.497 19.848 ;
     RECT  59.365 20.832 59.497 24.552 ;
     RECT  59.177 60.048 59.501 62.28 ;
     RECT  58.421 85.824 59.501 87.432 ;
     RECT  58.529 25.68 59.569 26.088 ;
     RECT  59.533 27.12 59.569 27.144 ;
     RECT  59.569 25.68 59.605 27.144 ;
     RECT  59.177 58.8 59.677 59.064 ;
     RECT  59.497 11.376 59.681 24.552 ;
     RECT  59.605 25.584 59.681 27.144 ;
     RECT  59.413 63.504 59.681 81.48 ;
     RECT  59.315 84.336 59.681 84.648 ;
     RECT  59.461 3.984 59.713 4.008 ;
     RECT  58.745 5.472 59.713 5.496 ;
     RECT  59.681 11.376 59.753 12.504 ;
     RECT  59.713 3.984 59.797 5.496 ;
     RECT  59.501 86.64 59.797 87.432 ;
     RECT  58.741 34.992 59.821 45.624 ;
     RECT  59.027 46.608 59.821 46.872 ;
     RECT  59.797 3.312 59.843 5.496 ;
     RECT  59.681 65.76 59.843 81.48 ;
     RECT  59.797 86.64 59.843 88.152 ;
     RECT  58.961 7.968 59.857 10.392 ;
     RECT  59.843 65.76 59.861 75.528 ;
     RECT  59.821 34.992 59.891 46.872 ;
     RECT  59.681 26.16 59.897 27.144 ;
     RECT  59.891 34.992 59.897 45.72 ;
     RECT  59.843 86.64 59.933 86.664 ;
     RECT  59.681 13.488 60.001 24.552 ;
     RECT  59.753 12.432 60.035 12.504 ;
     RECT  59.857 7.44 60.037 10.392 ;
     RECT  59.753 11.376 60.037 11.4 ;
     RECT  59.681 84.624 60.037 84.648 ;
     RECT  60.037 7.44 60.041 11.4 ;
     RECT  59.891 46.848 60.077 46.872 ;
     RECT  59.429 82.464 60.083 82.968 ;
     RECT  59.027 47.856 60.109 48.936 ;
     RECT  59.125 50.064 60.109 53.352 ;
     RECT  59.389 56.448 60.109 56.472 ;
     RECT  59.137 93.744 60.109 97.08 ;
     RECT  60.109 47.856 60.113 53.352 ;
     RECT  59.677 58.704 60.145 59.064 ;
     RECT  60.001 13.488 60.149 24.936 ;
     RECT  59.897 38.4 60.149 45.72 ;
     RECT  59.843 76.752 60.149 81.48 ;
     RECT  60.035 12.432 60.227 12.456 ;
     RECT  60.113 48.384 60.253 53.352 ;
     RECT  60.109 56.448 60.253 57.048 ;
     RECT  60.037 84.624 60.257 84.984 ;
     RECT  60.145 58.656 60.289 59.064 ;
     RECT  60.253 56.064 60.325 57.048 ;
     RECT  60.289 58.224 60.325 59.064 ;
     RECT  60.325 56.064 60.371 59.064 ;
     RECT  60.371 58.656 60.397 59.064 ;
     RECT  59.501 60.048 60.397 61.944 ;
     RECT  60.149 13.488 60.401 22.2 ;
     RECT  60.257 84.624 60.419 84.648 ;
     RECT  60.401 16.464 60.473 22.2 ;
     RECT  60.397 58.656 60.505 61.944 ;
     RECT  60.253 48.384 60.517 54.168 ;
     RECT  59.861 75.504 60.545 75.528 ;
     RECT  60.041 7.44 60.565 7.464 ;
     RECT  60.517 48.384 60.581 54.6 ;
     RECT  60.371 56.064 60.613 57.432 ;
     RECT  60.401 13.488 60.617 15.24 ;
     RECT  59.861 65.76 60.653 74.52 ;
     RECT  60.473 16.464 60.707 19.848 ;
     RECT  59.285 30.624 60.805 33.288 ;
     RECT  60.083 82.56 60.805 82.968 ;
     RECT  60.617 13.872 60.833 15.24 ;
     RECT  60.653 65.76 60.865 74.088 ;
     RECT  59.843 4.512 60.901 5.496 ;
     RECT  60.149 23.424 60.937 24.936 ;
     RECT  59.897 26.304 60.937 27.144 ;
     RECT  60.805 30.624 60.949 33.672 ;
     RECT  59.897 34.992 60.949 36.936 ;
     RECT  58.961 28.128 61.045 29.304 ;
     RECT  60.949 30.624 61.045 36.936 ;
     RECT  60.149 76.752 61.141 80.52 ;
     RECT  60.505 58.656 61.225 62.184 ;
     RECT  59.681 63.504 61.225 64.632 ;
     RECT  60.937 23.424 61.297 27.144 ;
     RECT  61.045 28.128 61.297 36.936 ;
     RECT  61.225 58.656 61.441 64.632 ;
     RECT  60.109 93.744 61.523 97.176 ;
     RECT  61.441 58.656 61.525 64.68 ;
     RECT  60.865 65.664 61.525 74.088 ;
     RECT  60.473 20.832 61.549 22.2 ;
     RECT  61.297 23.424 61.549 36.936 ;
     RECT  60.581 48.384 61.573 54.168 ;
     RECT  61.573 48.384 61.585 54.6 ;
     RECT  61.523 97.056 61.625 97.176 ;
     RECT  61.585 48.384 61.657 54.744 ;
     RECT  60.149 38.4 61.801 45.624 ;
     RECT  59.843 3.312 61.808 3.336 ;
     RECT  60.901 4.512 61.808 5.64 ;
     RECT  60.565 6.624 61.808 7.464 ;
     RECT  60.041 8.496 61.808 11.4 ;
     RECT  61.045 12.768 61.808 12.792 ;
     RECT  60.833 13.872 61.808 14.664 ;
     RECT  60.707 16.464 61.808 19.608 ;
     RECT  61.549 20.832 61.808 36.936 ;
     RECT  61.801 37.968 61.808 45.624 ;
     RECT  61.657 48.288 61.808 54.744 ;
     RECT  60.613 55.968 61.808 57.432 ;
     RECT  61.525 58.656 61.808 74.088 ;
     RECT  61.141 76.752 61.808 81.048 ;
     RECT  60.805 82.56 61.808 83.256 ;
     RECT  59.843 88.128 61.808 88.152 ;
     RECT  61.523 93.744 61.808 95.784 ;
     RECT  61.808 2.148 61.907 95.784 ;
     RECT  61.907 2.148 61.912 95.736 ;
     RECT  61.912 2.418 61.985 95.736 ;
     RECT  61.985 2.418 62.104 94.782 ;
     RECT  62.104 21.984 62.165 36.936 ;
     RECT  62.104 41.472 62.201 45.816 ;
     RECT  62.104 88.128 62.201 88.248 ;
     RECT  62.104 76.464 62.309 78.408 ;
     RECT  62.104 58.128 62.453 65.784 ;
     RECT  62.104 37.968 62.489 40.488 ;
     RECT  62.104 56.352 62.489 57.048 ;
     RECT  62.104 4.656 62.633 5.496 ;
     RECT  62.165 21.984 62.633 25.848 ;
     RECT  62.104 93.744 62.633 94.296 ;
     RECT  62.104 66.864 62.813 74.04 ;
     RECT  62.104 17.328 62.819 20.856 ;
     RECT  62.489 37.968 62.885 39.912 ;
     RECT  62.453 64.944 62.885 65.784 ;
     RECT  62.633 4.8 62.957 5.496 ;
     RECT  62.165 27.12 62.957 36.936 ;
     RECT  62.104 14.4 62.963 15.672 ;
     RECT  62.201 41.664 62.993 45.816 ;
     RECT  62.993 41.808 63.097 45.816 ;
     RECT  62.104 46.896 63.097 47.592 ;
     RECT  63.097 41.808 63.109 47.592 ;
     RECT  62.104 49.104 63.109 54.744 ;
     RECT  62.813 66.864 63.137 73.944 ;
     RECT  62.104 2.832 63.205 3.336 ;
     RECT  62.819 20.544 63.205 20.856 ;
     RECT  62.489 56.736 63.241 57.048 ;
     RECT  63.241 56.736 63.421 57.144 ;
     RECT  62.453 58.128 63.421 58.152 ;
     RECT  62.963 14.4 63.461 14.664 ;
     RECT  62.104 6.624 63.493 7.992 ;
     RECT  62.104 9.6 63.493 10.248 ;
     RECT  63.109 41.808 63.529 54.744 ;
     RECT  62.453 59.184 63.529 63.816 ;
     RECT  62.885 64.944 63.529 65.544 ;
     RECT  62.957 4.8 63.539 5.4 ;
     RECT  62.104 11.52 63.601 11.544 ;
     RECT  62.104 13.104 63.601 13.128 ;
     RECT  62.885 37.968 63.605 38.76 ;
     RECT  62.963 15.648 63.637 15.672 ;
     RECT  62.819 17.328 63.637 17.976 ;
     RECT  63.529 41.808 63.637 54.936 ;
     RECT  63.421 56.736 63.637 58.152 ;
     RECT  63.529 59.184 63.637 65.544 ;
     RECT  63.601 11.52 63.709 13.128 ;
     RECT  63.637 41.808 63.713 55.704 ;
     RECT  62.309 76.464 63.713 78.12 ;
     RECT  63.713 76.512 63.731 78.12 ;
     RECT  62.104 79.968 63.745 79.992 ;
     RECT  62.633 22.464 63.781 25.848 ;
     RECT  62.104 82.944 63.817 82.968 ;
     RECT  63.745 4.704 63.827 4.728 ;
     RECT  63.137 67.104 63.929 73.944 ;
     RECT  62.957 27.936 63.997 36.936 ;
     RECT  63.605 37.968 63.997 38.568 ;
     RECT  63.817 82.944 64.001 83.832 ;
     RECT  63.961 75.264 64.019 75.288 ;
     RECT  63.929 68.352 64.021 73.944 ;
     RECT  63.997 27.936 64.037 38.568 ;
     RECT  63.713 41.808 64.067 50.808 ;
     RECT  63.205 2.4 64.105 3.336 ;
     RECT  63.493 6.624 64.105 10.248 ;
     RECT  62.819 19.2 64.105 19.416 ;
     RECT  63.205 20.544 64.105 21.096 ;
     RECT  63.781 22.464 64.105 26.424 ;
     RECT  64.037 31.488 64.109 38.568 ;
     RECT  63.817 84.816 64.141 84.84 ;
     RECT  63.745 79.728 64.177 79.992 ;
     RECT  61.625 97.152 64.177 97.176 ;
     RECT  63.709 11.52 64.213 13.896 ;
     RECT  64.177 79.728 64.253 80.952 ;
     RECT  64.105 2.4 64.357 3.432 ;
     RECT  64.177 4.56 64.357 4.584 ;
     RECT  64.067 41.808 64.357 43.896 ;
     RECT  63.713 51.888 64.361 55.704 ;
     RECT  64.021 68.352 64.403 74.088 ;
     RECT  64.361 51.936 64.429 55.704 ;
     RECT  63.637 56.736 64.429 65.544 ;
     RECT  64.403 71.76 64.429 74.088 ;
     RECT  64.109 31.488 64.451 38.136 ;
     RECT  64.429 51.936 64.469 65.544 ;
     RECT  62.885 39.744 64.501 39.912 ;
     RECT  64.357 41.28 64.501 43.896 ;
     RECT  64.105 19.2 64.537 21.096 ;
     RECT  64.105 22.464 64.537 26.952 ;
     RECT  64.451 31.488 64.541 37.992 ;
     RECT  64.429 71.76 64.541 74.808 ;
     RECT  64.501 39.744 64.577 43.896 ;
     RECT  64.573 0.144 64.645 0.168 ;
     RECT  62.633 94.272 64.645 94.296 ;
     RECT  64.645 0.096 64.691 0.168 ;
     RECT  64.469 65.136 64.691 65.544 ;
     RECT  64.403 68.352 64.691 70.104 ;
     RECT  64.537 19.2 64.787 26.952 ;
     RECT  64.105 5.856 64.789 10.248 ;
     RECT  64.213 11.376 64.789 13.896 ;
     RECT  64.691 65.52 64.789 65.544 ;
     RECT  63.929 67.104 64.789 67.368 ;
     RECT  64.469 51.936 64.793 58.152 ;
     RECT  64.469 59.136 64.793 63.864 ;
     RECT  64.357 2.208 64.861 4.584 ;
     RECT  64.789 5.856 64.861 13.896 ;
     RECT  63.637 15.648 64.897 17.976 ;
     RECT  64.141 84.288 64.897 84.84 ;
     RECT  64.897 15.504 64.969 17.976 ;
     RECT  64.787 19.2 64.969 25.08 ;
     RECT  64.577 39.744 64.969 39.912 ;
     RECT  64.645 94.272 64.973 94.68 ;
     RECT  64.691 0.144 64.979 0.168 ;
     RECT  64.861 2.208 64.979 13.896 ;
     RECT  64.253 79.728 64.981 79.752 ;
     RECT  64.825 86.448 64.981 86.472 ;
     RECT  64.969 39.36 65.009 39.912 ;
     RECT  64.981 79.248 65.027 79.752 ;
     RECT  64.897 84.288 65.027 84.936 ;
     RECT  64.979 11.424 65.029 13.896 ;
     RECT  64.897 82.08 65.029 82.104 ;
     RECT  64.981 86.448 65.041 87 ;
     RECT  62.201 88.224 65.041 88.248 ;
     RECT  64.789 65.52 65.077 67.368 ;
     RECT  64.691 68.352 65.077 70.008 ;
     RECT  64.793 51.936 65.081 55.704 ;
     RECT  64.253 80.784 65.113 80.952 ;
     RECT  65.029 82.08 65.113 82.44 ;
     RECT  65.029 11.424 65.125 14.136 ;
     RECT  65.077 75.408 65.125 75.432 ;
     RECT  63.731 76.512 65.125 76.536 ;
     RECT  63.731 77.52 65.125 78.12 ;
     RECT  65.113 80.784 65.185 82.44 ;
     RECT  64.541 31.488 65.221 31.944 ;
     RECT  65.027 84.288 65.221 84.84 ;
     RECT  65.041 86.448 65.261 88.248 ;
     RECT  64.577 41.28 65.293 43.896 ;
     RECT  64.067 44.88 65.293 50.808 ;
     RECT  65.081 55.2 65.333 55.704 ;
     RECT  65.077 65.52 65.333 70.008 ;
     RECT  65.077 94.992 65.363 95.304 ;
     RECT  64.541 32.976 65.405 37.992 ;
     RECT  65.221 84.24 65.473 84.84 ;
     RECT  64.037 27.936 65.509 30.408 ;
     RECT  65.221 31.44 65.509 31.944 ;
     RECT  65.009 39.36 65.509 39.384 ;
     RECT  64.541 71.76 65.581 74.232 ;
     RECT  65.405 33.168 65.585 37.992 ;
     RECT  65.293 41.28 65.585 50.808 ;
     RECT  65.125 75.408 65.621 78.12 ;
     RECT  65.261 86.448 65.621 87.816 ;
     RECT  65.585 44.928 65.653 50.808 ;
     RECT  64.979 2.208 65.689 10.344 ;
     RECT  64.787 26.112 65.689 26.952 ;
     RECT  65.509 27.936 65.689 31.944 ;
     RECT  65.581 71.568 65.689 74.232 ;
     RECT  65.621 75.408 65.689 77.64 ;
     RECT  65.185 80.784 65.689 82.632 ;
     RECT  65.473 84 65.689 84.84 ;
     RECT  65.689 71.568 65.747 77.64 ;
     RECT  64.969 15.504 65.761 25.08 ;
     RECT  65.689 26.112 65.761 31.944 ;
     RECT  65.585 33.312 65.761 37.992 ;
     RECT  65.509 38.976 65.761 39.384 ;
     RECT  64.793 56.736 65.761 58.152 ;
     RECT  65.621 86.448 65.797 87.24 ;
     RECT  65.333 65.52 65.833 69.864 ;
     RECT  65.653 44.928 65.843 50.856 ;
     RECT  65.585 41.28 65.869 43.896 ;
     RECT  65.843 45.264 65.869 50.856 ;
     RECT  65.081 51.936 65.869 54.216 ;
     RECT  64.177 96.336 66.017 97.176 ;
     RECT  66.017 96.336 66.035 97.08 ;
     RECT  65.689 1.728 66.037 10.344 ;
     RECT  65.761 15.504 66.049 31.944 ;
     RECT  65.761 56.448 66.049 58.152 ;
     RECT  64.793 59.136 66.049 63.816 ;
     RECT  66.013 89.472 66.085 89.496 ;
     RECT  65.689 80.784 66.089 84.84 ;
     RECT  66.085 88.848 66.121 89.496 ;
     RECT  65.027 79.248 66.133 79.704 ;
     RECT  65.833 65.136 66.193 69.864 ;
     RECT  66.035 96.336 66.227 97.032 ;
     RECT  66.037 1.728 66.229 10.392 ;
     RECT  65.125 11.424 66.229 14.424 ;
     RECT  66.049 15.456 66.229 31.944 ;
     RECT  66.227 96.336 66.265 96.36 ;
     RECT  65.363 94.992 66.277 95.208 ;
     RECT  65.333 55.2 66.301 55.32 ;
     RECT  66.049 56.448 66.301 63.816 ;
     RECT  66.193 64.992 66.337 69.864 ;
     RECT  65.747 71.568 66.337 74.232 ;
     RECT  65.869 45.264 66.445 54.216 ;
     RECT  66.301 55.2 66.445 63.816 ;
     RECT  66.089 82.224 66.445 84.84 ;
     RECT  66.277 94.08 66.517 95.208 ;
     RECT  66.265 96.288 66.517 96.36 ;
     RECT  65.761 33.312 66.553 39.384 ;
     RECT  66.229 1.728 66.613 31.944 ;
     RECT  65.797 86.016 66.625 87.24 ;
     RECT  66.613 1.728 66.661 31.992 ;
     RECT  66.625 86.016 66.661 87.768 ;
     RECT  66.121 88.848 66.661 90.072 ;
     RECT  66.661 1.728 66.733 32.232 ;
     RECT  66.553 33.312 66.733 39.624 ;
     RECT  66.157 0.096 66.803 0.12 ;
     RECT  66.133 78.624 66.805 79.704 ;
     RECT  65.869 40.608 66.877 43.896 ;
     RECT  66.445 45.264 66.877 63.816 ;
     RECT  66.877 40.608 66.949 63.816 ;
     RECT  66.337 64.992 66.949 74.232 ;
     RECT  66.661 86.016 66.949 90.072 ;
     RECT  66.517 94.08 66.949 96.36 ;
     RECT  66.949 94.032 67.045 96.36 ;
     RECT  66.089 80.784 67.057 81.144 ;
     RECT  66.445 82.224 67.057 84.936 ;
     RECT  66.949 40.608 67.093 74.232 ;
     RECT  66.733 1.728 67.208 39.624 ;
     RECT  67.093 40.608 67.208 74.328 ;
     RECT  65.747 75.408 67.208 77.64 ;
     RECT  66.805 78.624 67.208 79.8 ;
     RECT  67.057 80.784 67.208 84.936 ;
     RECT  66.949 86.016 67.208 90.264 ;
     RECT  67.045 93.504 67.208 96.36 ;
     RECT  67.208 1.728 67.345 96.36 ;
     RECT  67.345 1.728 67.504 96.408 ;
     RECT  67.504 1.728 67.565 22.536 ;
     RECT  67.504 93.504 67.601 96.408 ;
     RECT  66.997 0.144 67.619 0.168 ;
     RECT  67.601 96.288 67.621 96.408 ;
     RECT  67.504 23.568 67.715 50.952 ;
     RECT  67.504 83.52 67.715 86.184 ;
     RECT  67.504 60.384 67.811 77.64 ;
     RECT  67.601 93.504 67.859 95.208 ;
     RECT  67.565 11.952 67.889 22.536 ;
     RECT  67.715 23.568 67.889 27.096 ;
     RECT  67.715 28.128 67.889 50.952 ;
     RECT  67.504 87.84 68.033 90.264 ;
     RECT  67.889 15.984 68.051 22.536 ;
     RECT  67.889 28.128 68.105 43.896 ;
     RECT  67.811 64.896 68.105 77.64 ;
     RECT  68.105 39.36 68.249 41.928 ;
     RECT  67.504 78.624 68.249 82.296 ;
     RECT  67.859 93.504 68.249 94.104 ;
     RECT  67.889 44.976 68.291 50.952 ;
     RECT  67.621 96.288 68.321 97.08 ;
     RECT  67.811 60.384 68.465 63.768 ;
     RECT  68.321 96.864 68.465 97.08 ;
     RECT  68.105 64.944 68.483 77.64 ;
     RECT  68.291 46.32 68.533 50.952 ;
     RECT  67.504 51.936 68.533 58.68 ;
     RECT  67.715 83.52 68.533 84.936 ;
     RECT  68.249 78.864 68.573 81.48 ;
     RECT  67.715 86.016 68.605 86.184 ;
     RECT  68.033 87.84 68.605 90.12 ;
     RECT  68.533 46.32 68.627 58.68 ;
     RECT  68.605 86.016 68.645 90.12 ;
     RECT  67.859 95.136 68.677 95.208 ;
     RECT  68.051 15.984 68.681 18.024 ;
     RECT  67.565 1.728 68.713 10.872 ;
     RECT  67.889 11.952 68.713 14.952 ;
     RECT  68.645 86.064 68.771 90.12 ;
     RECT  68.051 19.344 68.785 22.536 ;
     RECT  68.785 19.344 68.857 22.728 ;
     RECT  67.889 23.808 68.857 27.096 ;
     RECT  68.105 28.128 68.857 38.184 ;
     RECT  68.005 0.096 68.869 0.12 ;
     RECT  68.249 94.08 68.869 94.104 ;
     RECT  68.677 95.136 68.869 95.784 ;
     RECT  68.869 94.08 68.969 95.784 ;
     RECT  68.291 44.976 69.011 45.336 ;
     RECT  68.969 94.656 69.041 95.784 ;
     RECT  68.533 82.656 69.073 84.936 ;
     RECT  68.857 19.344 69.109 38.184 ;
     RECT  68.465 60.864 69.109 63.768 ;
     RECT  68.573 78.864 69.185 80.424 ;
     RECT  69.073 82.656 69.185 85.032 ;
     RECT  68.627 46.32 69.221 55.224 ;
     RECT  68.869 0.096 69.349 0.168 ;
     RECT  68.465 96.864 69.349 96.888 ;
     RECT  68.105 43.392 69.361 43.896 ;
     RECT  69.011 44.976 69.361 45.288 ;
     RECT  69.109 19.344 69.365 38.28 ;
     RECT  68.713 1.728 69.397 14.952 ;
     RECT  68.771 86.352 69.401 90.12 ;
     RECT  68.249 39.504 69.433 41.928 ;
     RECT  68.627 56.352 69.433 58.68 ;
     RECT  69.253 59.76 69.433 59.784 ;
     RECT  69.349 96.288 69.473 96.888 ;
     RECT  69.349 0.096 69.541 0.216 ;
     RECT  69.109 60.864 69.541 63.816 ;
     RECT  69.365 21.648 69.581 38.28 ;
     RECT  68.483 67.2 69.581 77.64 ;
     RECT  69.221 49.008 69.653 55.224 ;
     RECT  68.483 64.944 69.685 66.168 ;
     RECT  69.581 67.2 69.685 69.576 ;
     RECT  69.653 49.008 69.689 53.928 ;
     RECT  69.581 25.44 69.725 38.28 ;
     RECT  69.725 33.36 69.733 38.28 ;
     RECT  69.433 39.312 69.733 41.928 ;
     RECT  69.733 33.36 69.797 41.928 ;
     RECT  69.797 39.312 69.829 41.928 ;
     RECT  69.829 39.312 69.869 42.168 ;
     RECT  69.397 1.728 69.877 15.048 ;
     RECT  68.681 16.032 69.877 18.024 ;
     RECT  69.869 39.504 69.901 42.168 ;
     RECT  69.901 39.504 69.905 42.216 ;
     RECT  69.581 70.56 69.905 77.64 ;
     RECT  69.473 96.864 69.925 96.888 ;
     RECT  69.725 25.44 69.977 32.232 ;
     RECT  69.685 64.944 70.009 69.576 ;
     RECT  69.041 94.656 70.009 95.16 ;
     RECT  69.541 0.096 70.021 0.264 ;
     RECT  69.365 19.344 70.045 20.472 ;
     RECT  69.433 56.352 70.049 59.784 ;
     RECT  69.541 60.864 70.069 63.864 ;
     RECT  70.009 64.896 70.069 69.576 ;
     RECT  69.877 1.728 70.117 18.024 ;
     RECT  70.045 19.056 70.117 20.472 ;
     RECT  69.925 96.864 70.117 96.984 ;
     RECT  69.905 40.848 70.121 42.216 ;
     RECT  69.185 79.584 70.153 80.424 ;
     RECT  68.573 81.408 70.153 81.48 ;
     RECT  70.117 96.864 70.153 97.08 ;
     RECT  69.185 82.656 70.189 84.36 ;
     RECT  70.069 60.864 70.211 69.576 ;
     RECT  70.153 79.584 70.225 81.48 ;
     RECT  70.189 82.656 70.225 85.416 ;
     RECT  68.869 92.928 70.261 92.952 ;
     RECT  70.211 60.864 70.265 69.48 ;
     RECT  69.977 25.44 70.301 32.04 ;
     RECT  69.361 43.392 70.333 45.288 ;
     RECT  69.221 46.32 70.333 47.832 ;
     RECT  69.905 39.504 70.337 39.528 ;
     RECT  70.021 0.096 70.405 0.312 ;
     RECT  70.121 41.568 70.409 42.216 ;
     RECT  70.225 79.584 70.409 85.416 ;
     RECT  69.401 87.12 70.481 90.12 ;
     RECT  70.261 92.352 70.517 92.952 ;
     RECT  70.405 0.096 70.547 0.408 ;
     RECT  69.653 54.96 70.549 55.224 ;
     RECT  70.333 43.392 70.585 47.832 ;
     RECT  69.689 49.008 70.585 52.296 ;
     RECT  70.549 54.96 70.589 56.088 ;
     RECT  70.585 43.392 70.621 52.296 ;
     RECT  70.117 1.728 70.643 20.472 ;
     RECT  70.589 55.008 70.733 56.088 ;
     RECT  70.265 60.864 70.733 69.384 ;
     RECT  70.409 79.728 70.733 85.416 ;
     RECT  69.581 21.648 70.765 24.12 ;
     RECT  70.733 79.776 70.769 85.416 ;
     RECT  69.905 72.336 70.801 77.64 ;
     RECT  70.643 2.304 70.805 20.472 ;
     RECT  70.621 43.296 70.805 52.296 ;
     RECT  70.301 25.968 70.835 32.04 ;
     RECT  70.049 57.312 70.873 59.784 ;
     RECT  70.733 60.864 70.877 67.992 ;
     RECT  70.153 96.864 70.885 97.176 ;
     RECT  70.873 57.312 70.909 59.88 ;
     RECT  70.877 60.864 70.909 62.136 ;
     RECT  70.517 92.928 70.909 92.952 ;
     RECT  70.009 94.032 70.909 95.16 ;
     RECT  70.835 29.712 70.913 32.04 ;
     RECT  70.801 72.336 70.933 78.36 ;
     RECT  70.769 79.776 71.027 85.176 ;
     RECT  70.805 49.776 71.053 52.296 ;
     RECT  69.689 53.28 71.053 53.928 ;
     RECT  70.909 92.928 71.075 95.16 ;
     RECT  70.805 16.512 71.077 20.472 ;
     RECT  70.765 21.648 71.077 24.888 ;
     RECT  70.805 43.296 71.093 48.552 ;
     RECT  70.933 72.336 71.123 78.648 ;
     RECT  71.075 94.032 71.161 95.16 ;
     RECT  70.805 2.304 71.237 15.432 ;
     RECT  71.075 92.928 71.237 93 ;
     RECT  71.237 2.304 71.273 15.384 ;
     RECT  69.905 70.56 71.305 71.256 ;
     RECT  71.123 72.336 71.305 77.496 ;
     RECT  70.909 57.312 71.309 62.136 ;
     RECT  71.161 94.032 71.341 95.784 ;
     RECT  70.885 96.816 71.341 97.176 ;
     RECT  70.409 41.712 71.449 42.216 ;
     RECT  70.547 0.096 71.453 0.312 ;
     RECT  71.077 16.512 71.557 24.888 ;
     RECT  70.913 29.76 71.557 32.04 ;
     RECT  69.797 33.36 71.557 38.232 ;
     RECT  71.449 41.664 71.557 42.216 ;
     RECT  71.309 57.312 71.557 58.488 ;
     RECT  71.557 29.76 71.561 38.232 ;
     RECT  70.877 63.12 71.701 67.992 ;
     RECT  70.733 68.976 71.701 69.384 ;
     RECT  71.053 49.776 71.809 53.928 ;
     RECT  70.733 55.008 71.809 55.416 ;
     RECT  71.125 86.448 71.809 86.472 ;
     RECT  70.481 87.648 71.809 90.12 ;
     RECT  71.809 86.448 71.845 90.12 ;
     RECT  71.309 59.472 71.881 62.136 ;
     RECT  71.701 63.12 71.881 69.576 ;
     RECT  71.557 16.512 71.893 25.08 ;
     RECT  70.835 26.112 71.893 28.728 ;
     RECT  71.557 40.992 71.953 42.216 ;
     RECT  71.557 57.12 71.953 58.488 ;
     RECT  71.953 40.56 72.037 42.216 ;
     RECT  71.953 56.88 72.061 58.488 ;
     RECT  71.027 79.776 72.061 84.12 ;
     RECT  72.061 79.728 72.097 84.12 ;
     RECT  71.027 85.152 72.097 85.176 ;
     RECT  71.123 78.624 72.133 78.648 ;
     RECT  72.037 40.416 72.205 42.216 ;
     RECT  71.093 43.296 72.205 48.456 ;
     RECT  71.561 32.496 72.241 38.232 ;
     RECT  71.305 70.56 72.313 77.496 ;
     RECT  72.097 79.728 72.385 85.176 ;
     RECT  71.453 0.096 72.421 0.168 ;
     RECT  72.061 56.832 72.457 58.488 ;
     RECT  71.881 59.472 72.457 69.576 ;
     RECT  72.421 0.096 72.469 0.312 ;
     RECT  71.893 16.512 72.469 28.728 ;
     RECT  71.561 29.76 72.469 31.416 ;
     RECT  72.205 40.416 72.469 48.456 ;
     RECT  72.313 70.56 72.469 77.64 ;
     RECT  72.133 78.624 72.469 78.744 ;
     RECT  71.273 2.304 72.608 12.648 ;
     RECT  71.273 13.632 72.608 15.384 ;
     RECT  72.469 16.512 72.608 31.416 ;
     RECT  72.241 32.496 72.608 38.76 ;
     RECT  72.469 40.416 72.608 48.696 ;
     RECT  71.809 49.776 72.608 55.416 ;
     RECT  72.457 56.832 72.608 69.576 ;
     RECT  72.469 70.56 72.608 78.744 ;
     RECT  72.385 79.728 72.608 85.464 ;
     RECT  71.845 86.448 72.608 90.312 ;
     RECT  71.237 92.976 72.608 93 ;
     RECT  71.341 94.032 72.608 97.176 ;
     RECT  72.608 2.148 72.613 97.176 ;
     RECT  72.469 0.096 72.755 0.408 ;
     RECT  72.613 2.016 72.805 97.176 ;
     RECT  72.805 1.968 72.904 97.176 ;
     RECT  72.904 1.968 72.929 48.696 ;
     RECT  72.929 1.968 72.965 48.648 ;
     RECT  72.904 92.976 72.965 93 ;
     RECT  72.904 60.528 73.043 75 ;
     RECT  72.904 87.648 73.043 90.504 ;
     RECT  72.965 1.968 73.091 44.952 ;
     RECT  72.755 0.096 73.139 0.12 ;
     RECT  72.904 54.528 73.217 59.496 ;
     RECT  72.904 75.984 73.217 83.832 ;
     RECT  73.091 32.112 73.289 44.952 ;
     RECT  72.904 94.032 73.427 97.176 ;
     RECT  73.091 1.968 73.465 30.648 ;
     RECT  73.465 1.728 73.523 30.648 ;
     RECT  72.904 84.816 73.541 86.616 ;
     RECT  73.523 1.776 73.577 30.648 ;
     RECT  73.541 86.064 73.613 86.616 ;
     RECT  73.577 23.904 73.649 30.648 ;
     RECT  73.043 71.184 73.757 75 ;
     RECT  73.043 87.648 73.757 90.312 ;
     RECT  73.577 1.776 73.763 22.536 ;
     RECT  73.613 86.592 73.763 86.616 ;
     RECT  73.289 32.112 73.811 44.712 ;
     RECT  73.217 75.984 73.811 79.992 ;
     RECT  73.217 81.216 73.897 83.832 ;
     RECT  73.541 84.816 73.897 85.08 ;
     RECT  73.427 94.032 73.901 94.92 ;
     RECT  73.811 38.496 74.003 44.712 ;
     RECT  73.427 96.288 74.003 97.176 ;
     RECT  72.965 45.936 74.005 48.648 ;
     RECT  72.904 49.68 74.005 53.304 ;
     RECT  73.811 32.112 74.051 37.128 ;
     RECT  74.003 38.496 74.051 41.688 ;
     RECT  73.757 71.184 74.051 73.656 ;
     RECT  74.051 71.184 74.077 73.608 ;
     RECT  73.043 60.528 74.113 69.912 ;
     RECT  74.077 70.896 74.113 73.608 ;
     RECT  74.113 0.096 74.195 0.12 ;
     RECT  74.003 96.336 74.195 97.176 ;
     RECT  74.005 45.936 74.221 53.304 ;
     RECT  73.757 74.64 74.293 75 ;
     RECT  73.811 75.984 74.293 78.648 ;
     RECT  74.113 60.528 74.297 73.608 ;
     RECT  74.221 45.936 74.329 53.4 ;
     RECT  73.217 54.528 74.329 56.568 ;
     RECT  73.217 57.6 74.329 59.496 ;
     RECT  74.297 60.528 74.329 73.464 ;
     RECT  74.051 38.688 74.369 41.688 ;
     RECT  74.329 57.6 74.387 73.464 ;
     RECT  73.901 94.08 74.435 94.92 ;
     RECT  74.003 42.672 74.441 44.712 ;
     RECT  73.763 1.776 74.533 16.056 ;
     RECT  73.811 79.728 74.533 79.992 ;
     RECT  73.897 81.216 74.533 85.08 ;
     RECT  74.195 96.816 74.621 97.176 ;
     RECT  74.441 44.448 74.653 44.712 ;
     RECT  74.329 45.936 74.653 56.568 ;
     RECT  73.649 24.048 74.675 30.648 ;
     RECT  74.675 27.888 74.677 30.648 ;
     RECT  74.533 79.728 74.693 85.08 ;
     RECT  74.435 94.128 74.693 94.92 ;
     RECT  74.693 82.128 74.725 85.08 ;
     RECT  74.693 79.728 74.729 80.376 ;
     RECT  74.677 27.888 74.765 30.984 ;
     RECT  74.533 1.728 74.801 16.056 ;
     RECT  74.675 24.048 74.833 26.76 ;
     RECT  74.801 10.128 74.905 16.056 ;
     RECT  73.763 17.04 74.905 22.536 ;
     RECT  74.653 44.448 74.945 56.568 ;
     RECT  74.051 32.112 75.017 35.832 ;
     RECT  74.369 38.784 75.049 41.688 ;
     RECT  74.441 42.672 75.049 43.32 ;
     RECT  74.293 74.64 75.049 78.648 ;
     RECT  74.729 79.728 75.049 80.136 ;
     RECT  74.801 1.728 75.059 9.144 ;
     RECT  75.049 38.784 75.059 43.32 ;
     RECT  74.765 28.464 75.085 30.984 ;
     RECT  74.387 57.6 75.109 59.496 ;
     RECT  74.905 10.128 75.121 22.68 ;
     RECT  75.059 38.784 75.155 38.808 ;
     RECT  75.059 2.304 75.233 9.144 ;
     RECT  74.945 44.448 75.233 55.992 ;
     RECT  75.121 10.128 75.253 22.776 ;
     RECT  74.833 23.904 75.253 26.76 ;
     RECT  75.109 57.168 75.299 59.496 ;
     RECT  75.085 28.464 75.301 31.128 ;
     RECT  75.017 32.112 75.301 35.016 ;
     RECT  75.301 28.464 75.347 35.016 ;
     RECT  74.725 82.128 75.373 85.416 ;
     RECT  73.757 87.744 75.397 90.312 ;
     RECT  75.347 28.464 75.413 34.92 ;
     RECT  75.413 28.464 75.443 34.392 ;
     RECT  75.397 87.744 75.449 90.792 ;
     RECT  75.049 74.64 75.481 80.136 ;
     RECT  75.059 39.84 75.517 43.32 ;
     RECT  75.233 44.448 75.517 52.248 ;
     RECT  74.387 60.528 75.517 73.464 ;
     RECT  75.481 74.592 75.517 80.136 ;
     RECT  75.373 82.128 75.541 85.464 ;
     RECT  74.725 86.592 75.541 86.616 ;
     RECT  75.233 5.712 75.593 9.144 ;
     RECT  75.443 28.464 75.593 34.296 ;
     RECT  75.517 60.528 75.683 80.136 ;
     RECT  75.593 5.712 75.779 6.6 ;
     RECT  75.253 10.128 75.827 26.76 ;
     RECT  75.541 82.128 75.841 86.76 ;
     RECT  75.233 2.304 75.881 4.68 ;
     RECT  74.693 94.128 75.881 94.872 ;
     RECT  75.683 60.528 75.913 78.648 ;
     RECT  75.593 7.632 75.917 9.144 ;
     RECT  75.913 60.24 75.917 78.648 ;
     RECT  75.881 94.128 75.949 94.296 ;
     RECT  75.827 10.128 75.971 19.752 ;
     RECT  75.827 21.12 75.971 26.76 ;
     RECT  75.971 24.096 76.021 26.76 ;
     RECT  75.517 39.84 76.021 52.248 ;
     RECT  75.299 57.168 76.021 59.208 ;
     RECT  76.021 39.456 76.025 52.248 ;
     RECT  76.021 56.976 76.025 59.208 ;
     RECT  75.917 7.92 76.061 9.144 ;
     RECT  75.233 53.904 76.061 55.992 ;
     RECT  75.949 94.08 76.061 94.296 ;
     RECT  76.025 44.928 76.097 52.248 ;
     RECT  76.061 94.08 76.097 94.152 ;
     RECT  76.025 39.456 76.117 43.656 ;
     RECT  75.683 79.728 76.117 80.136 ;
     RECT  75.841 81.6 76.129 86.76 ;
     RECT  75.449 87.744 76.129 90.6 ;
     RECT  75.971 10.128 76.133 19.416 ;
     RECT  75.917 69.696 76.163 78.648 ;
     RECT  75.881 2.304 76.165 4.584 ;
     RECT  76.061 8.496 76.165 9.144 ;
     RECT  76.133 10.128 76.165 14.424 ;
     RECT  76.097 94.08 76.165 94.104 ;
     RECT  76.129 81.6 76.169 90.6 ;
     RECT  76.117 38.784 76.201 43.656 ;
     RECT  75.971 21.12 76.205 23.064 ;
     RECT  76.097 50.928 76.237 52.248 ;
     RECT  76.165 92.88 76.259 94.104 ;
     RECT  75.781 0.096 76.261 0.12 ;
     RECT  76.165 8.496 76.277 14.424 ;
     RECT  76.259 92.88 76.307 93.768 ;
     RECT  76.201 38.208 76.313 43.656 ;
     RECT  76.313 38.208 76.355 38.232 ;
     RECT  76.165 1.728 76.385 4.584 ;
     RECT  76.025 58.704 76.385 59.208 ;
     RECT  76.133 15.504 76.403 19.416 ;
     RECT  76.021 24.096 76.403 27.384 ;
     RECT  76.403 24.336 76.453 27.384 ;
     RECT  75.593 28.464 76.453 33.432 ;
     RECT  76.261 0.096 76.457 0.168 ;
     RECT  76.453 24.336 76.457 33.432 ;
     RECT  76.097 44.928 76.457 49.752 ;
     RECT  76.237 50.928 76.597 52.584 ;
     RECT  76.163 69.696 76.601 78.6 ;
     RECT  76.457 0.144 76.673 0.168 ;
     RECT  76.117 79.728 76.741 80.424 ;
     RECT  76.457 44.928 76.781 48.744 ;
     RECT  76.205 21.12 76.789 22.68 ;
     RECT  76.061 54.384 76.835 55.992 ;
     RECT  76.385 2.304 76.883 4.584 ;
     RECT  76.741 79.728 76.885 80.472 ;
     RECT  76.169 81.6 76.885 90.12 ;
     RECT  76.885 79.728 76.889 90.12 ;
     RECT  76.889 85.872 76.925 90.12 ;
     RECT  75.779 6.24 76.933 6.6 ;
     RECT  76.403 16.848 76.933 19.416 ;
     RECT  76.789 20.4 76.933 22.68 ;
     RECT  76.457 24.336 76.961 33.288 ;
     RECT  76.933 5.616 76.979 7.464 ;
     RECT  76.933 16.848 76.997 22.68 ;
     RECT  75.917 60.24 76.997 68.328 ;
     RECT  76.889 79.728 76.997 84.888 ;
     RECT  76.925 89.472 76.997 90.12 ;
     RECT  76.997 79.728 77.077 80.424 ;
     RECT  76.597 50.928 77.137 53.064 ;
     RECT  76.277 10.176 77.173 14.424 ;
     RECT  76.403 15.504 77.173 15.528 ;
     RECT  76.457 49.728 77.245 49.752 ;
     RECT  77.137 50.928 77.245 53.784 ;
     RECT  76.835 54.912 77.245 55.992 ;
     RECT  76.025 56.976 77.245 57.624 ;
     RECT  76.307 93.744 77.245 93.768 ;
     RECT  77.245 54.912 77.365 57.624 ;
     RECT  77.365 54.912 77.389 57.816 ;
     RECT  76.385 58.896 77.389 59.208 ;
     RECT  77.173 10.176 77.425 15.528 ;
     RECT  76.997 16.848 77.425 19.368 ;
     RECT  76.961 24.336 77.425 27.384 ;
     RECT  77.425 23.904 77.461 27.384 ;
     RECT  76.313 39.312 77.533 43.656 ;
     RECT  76.781 44.928 77.533 48.408 ;
     RECT  77.461 0.528 77.557 0.552 ;
     RECT  77.557 0.528 77.641 0.648 ;
     RECT  74.621 97.152 77.641 97.176 ;
     RECT  77.641 0.432 77.645 0.648 ;
     RECT  76.883 2.304 77.677 4.44 ;
     RECT  77.677 2.208 77.701 4.44 ;
     RECT  77.533 39.312 77.749 48.408 ;
     RECT  77.245 49.728 77.749 53.784 ;
     RECT  76.997 60.432 77.821 68.328 ;
     RECT  77.641 96.336 77.821 97.176 ;
     RECT  77.821 60.432 77.845 68.664 ;
     RECT  76.601 69.696 77.845 71.4 ;
     RECT  76.601 72.48 77.845 78.6 ;
     RECT  77.077 79.68 77.845 80.424 ;
     RECT  76.979 7.344 77.893 7.464 ;
     RECT  76.277 8.496 77.893 9.144 ;
     RECT  77.425 10.176 77.893 19.368 ;
     RECT  77.845 60.432 78.001 71.4 ;
     RECT  77.845 72.48 78.001 80.424 ;
     RECT  77.701 1.728 78.008 4.44 ;
     RECT  76.979 5.616 78.008 5.64 ;
     RECT  77.893 7.344 78.008 19.368 ;
     RECT  76.997 20.4 78.008 22.68 ;
     RECT  77.461 23.664 78.008 27.384 ;
     RECT  76.961 28.416 78.008 33.288 ;
     RECT  76.777 36 78.008 36.024 ;
     RECT  77.749 39.312 78.008 53.784 ;
     RECT  77.389 54.912 78.008 59.208 ;
     RECT  78.001 60.432 78.008 80.424 ;
     RECT  76.997 81.408 78.008 84.888 ;
     RECT  76.925 85.968 78.008 88.488 ;
     RECT  76.997 89.52 78.008 90.12 ;
     RECT  77.245 93.744 78.008 94.728 ;
     RECT  77.821 95.76 78.008 97.176 ;
     RECT  77.645 0.432 78.277 0.552 ;
     RECT  78.008 1.728 78.304 97.176 ;
     RECT  78.304 93.744 78.323 97.176 ;
     RECT  78.304 29.616 78.401 31.368 ;
     RECT  78.304 28.416 78.419 28.44 ;
     RECT  78.304 39.504 78.419 64.968 ;
     RECT  78.323 95.808 78.419 97.176 ;
     RECT  78.304 88.128 78.437 89.544 ;
     RECT  78.401 29.808 78.473 31.368 ;
     RECT  78.473 29.808 78.509 30.6 ;
     RECT  78.419 96.288 78.515 97.176 ;
     RECT  78.419 39.792 78.545 64.968 ;
     RECT  78.437 88.176 78.611 89.544 ;
     RECT  78.545 58.944 78.617 64.968 ;
     RECT  78.611 89.136 78.617 89.544 ;
     RECT  78.304 10.416 78.659 27.384 ;
     RECT  78.304 35.328 78.659 36.792 ;
     RECT  78.304 37.824 78.659 37.848 ;
     RECT  78.304 66.048 78.689 78.696 ;
     RECT  78.617 89.136 78.689 89.16 ;
     RECT  78.689 67.248 78.707 78.696 ;
     RECT  78.277 0.144 78.721 0.552 ;
     RECT  78.659 10.416 78.797 23.16 ;
     RECT  78.797 13.968 78.803 23.16 ;
     RECT  78.545 39.792 78.833 57.864 ;
     RECT  78.797 10.416 78.977 12.984 ;
     RECT  78.803 13.968 78.977 22.248 ;
     RECT  78.977 13.968 78.995 15.24 ;
     RECT  78.304 1.728 79.049 5.88 ;
     RECT  78.833 39.792 79.091 55.8 ;
     RECT  78.977 10.416 79.121 12.792 ;
     RECT  78.659 35.328 79.121 35.352 ;
     RECT  78.304 33.12 79.139 34.248 ;
     RECT  78.617 58.992 79.157 64.968 ;
     RECT  78.509 29.808 79.187 29.832 ;
     RECT  79.091 39.792 79.193 53.544 ;
     RECT  79.121 10.416 79.265 12.6 ;
     RECT  79.193 43.152 79.265 53.544 ;
     RECT  78.721 0.096 79.283 0.552 ;
     RECT  78.707 67.584 79.285 78.696 ;
     RECT  78.304 86.352 79.301 87.144 ;
     RECT  79.265 43.632 79.331 53.544 ;
     RECT  78.304 80.064 79.333 85.368 ;
     RECT  78.977 16.224 79.337 22.248 ;
     RECT  78.659 24.912 79.337 27.384 ;
     RECT  79.049 5.616 79.405 5.88 ;
     RECT  79.337 16.224 79.409 22.152 ;
     RECT  79.193 39.792 79.429 42.024 ;
     RECT  78.515 96.336 79.477 97.176 ;
     RECT  79.429 39.312 79.481 42.024 ;
     RECT  78.833 56.976 79.549 57.864 ;
     RECT  79.049 1.728 79.553 4.584 ;
     RECT  79.139 33.12 79.553 33.576 ;
     RECT  79.477 95.76 79.553 97.176 ;
     RECT  79.553 2.256 79.571 4.584 ;
     RECT  78.995 13.968 79.589 14.424 ;
     RECT  79.405 5.616 79.619 6.312 ;
     RECT  79.337 26.4 79.619 27.384 ;
     RECT  79.619 27.216 79.625 27.384 ;
     RECT  79.337 24.912 79.657 25.128 ;
     RECT  79.265 11.952 79.661 12.6 ;
     RECT  79.409 16.224 79.667 19.08 ;
     RECT  79.285 67.584 79.669 78.744 ;
     RECT  79.333 80.016 79.669 85.368 ;
     RECT  79.301 86.352 79.669 86.712 ;
     RECT  78.689 66.048 79.693 66.168 ;
     RECT  79.669 67.584 79.693 86.712 ;
     RECT  79.661 12.576 79.697 12.6 ;
     RECT  79.693 66.048 79.715 86.712 ;
     RECT  78.304 7.344 79.765 9.288 ;
     RECT  79.265 10.416 79.765 10.44 ;
     RECT  79.765 7.344 79.769 10.44 ;
     RECT  78.323 93.744 79.801 94.68 ;
     RECT  79.769 7.872 79.811 10.44 ;
     RECT  79.657 24.864 79.811 25.128 ;
     RECT  79.811 8.496 79.841 10.44 ;
     RECT  79.667 16.224 79.859 18.984 ;
     RECT  79.715 66.048 79.859 86.616 ;
     RECT  79.157 62.736 79.873 64.968 ;
     RECT  79.859 66.048 79.873 76.488 ;
     RECT  79.409 20.304 79.913 22.152 ;
     RECT  78.659 36.768 79.913 36.792 ;
     RECT  79.549 56.976 79.945 57.912 ;
     RECT  79.157 58.992 79.945 61.368 ;
     RECT  79.589 14.112 79.985 14.424 ;
     RECT  79.331 50.544 79.985 53.544 ;
     RECT  79.801 93.552 80.005 94.68 ;
     RECT  79.091 54.576 80.017 55.8 ;
     RECT  79.913 21.888 80.021 22.152 ;
     RECT  79.859 77.856 80.021 86.616 ;
     RECT  79.859 16.224 80.057 17.928 ;
     RECT  79.765 23.328 80.057 23.352 ;
     RECT  79.913 20.304 80.093 20.328 ;
     RECT  79.811 24.864 80.093 24.888 ;
     RECT  80.017 54.576 80.093 55.848 ;
     RECT  80.057 16.224 80.099 17.64 ;
     RECT  80.005 92.928 80.101 94.68 ;
     RECT  79.553 95.76 80.101 97.08 ;
     RECT  79.873 62.736 80.195 76.488 ;
     RECT  79.985 14.112 80.201 14.136 ;
     RECT  80.053 34.8 80.201 34.824 ;
     RECT  79.331 43.632 80.233 49.272 ;
     RECT  79.859 18.96 80.237 18.984 ;
     RECT  80.099 16.224 80.243 16.68 ;
     RECT  80.195 66.624 80.243 76.488 ;
     RECT  79.625 27.216 80.273 27.24 ;
     RECT  79.841 8.496 80.339 8.52 ;
     RECT  80.243 16.512 80.417 16.68 ;
     RECT  80.021 21.888 80.417 21.912 ;
     RECT  79.571 2.304 80.437 4.584 ;
     RECT  79.619 5.616 80.437 6.264 ;
     RECT  80.233 43.2 80.449 49.272 ;
     RECT  79.985 50.544 80.449 52.44 ;
     RECT  79.945 56.976 80.449 61.368 ;
     RECT  80.195 62.736 80.449 65.256 ;
     RECT  80.437 2.304 80.483 6.264 ;
     RECT  80.483 3.408 80.597 6.264 ;
     RECT  80.597 3.408 80.633 5.64 ;
     RECT  80.021 86.592 80.669 86.616 ;
     RECT  80.243 67.824 80.675 76.488 ;
     RECT  79.985 53.52 80.677 53.544 ;
     RECT  79.283 0.528 80.723 0.552 ;
     RECT  80.633 5.52 80.723 5.64 ;
     RECT  79.841 9.696 80.723 10.296 ;
     RECT  80.723 5.616 80.741 5.64 ;
     RECT  80.449 43.2 80.821 52.44 ;
     RECT  80.449 56.976 80.867 65.256 ;
     RECT  80.483 2.304 80.885 2.328 ;
     RECT  79.481 39.792 80.917 42.024 ;
     RECT  80.821 43.152 80.917 52.44 ;
     RECT  80.633 3.408 80.993 4.536 ;
     RECT  80.417 16.512 80.993 16.536 ;
     RECT  80.989 0.144 81.061 0.168 ;
     RECT  80.093 54.816 81.061 55.848 ;
     RECT  80.867 56.976 81.061 59.496 ;
     RECT  81.013 7.776 81.107 8.472 ;
     RECT  81.107 7.776 81.203 7.992 ;
     RECT  80.917 39.792 81.205 52.44 ;
     RECT  80.677 53.52 81.205 53.832 ;
     RECT  81.061 54.816 81.205 59.496 ;
     RECT  80.243 66.624 81.277 66.744 ;
     RECT  81.061 0.096 81.299 0.168 ;
     RECT  80.867 60.864 81.389 65.256 ;
     RECT  80.675 67.824 81.425 73.608 ;
     RECT  81.389 62.736 81.533 65.256 ;
     RECT  80.675 74.64 81.541 76.488 ;
     RECT  80.021 77.856 81.541 85.56 ;
     RECT  80.993 3.408 81.589 3.528 ;
     RECT  81.349 1.728 81.605 1.752 ;
     RECT  81.205 39.792 81.713 59.496 ;
     RECT  81.425 72.432 81.781 73.608 ;
     RECT  81.541 74.64 81.781 85.56 ;
     RECT  81.589 2.88 81.889 3.528 ;
     RECT  81.781 72.432 81.893 85.56 ;
     RECT  81.425 67.824 81.965 71.352 ;
     RECT  80.101 92.928 81.971 97.08 ;
     RECT  81.277 66.336 81.997 66.744 ;
     RECT  81.965 67.824 81.997 71.304 ;
     RECT  81.889 1.968 82.021 3.528 ;
     RECT  80.993 4.512 82.021 4.536 ;
     RECT  81.533 63.072 82.033 65.256 ;
     RECT  81.997 66.336 82.033 71.304 ;
     RECT  82.021 1.968 82.067 4.536 ;
     RECT  81.781 6.864 82.067 7.416 ;
     RECT  82.033 63.072 82.109 71.304 ;
     RECT  81.893 74.64 82.211 76.392 ;
     RECT  80.723 9.696 82.253 10.2 ;
     RECT  81.893 78.096 82.325 85.56 ;
     RECT  81.971 95.184 82.325 97.08 ;
     RECT  82.211 76.224 82.397 76.392 ;
     RECT  81.713 39.792 82.537 58.728 ;
     RECT  81.299 0.096 82.597 0.12 ;
     RECT  81.389 60.864 82.645 61.704 ;
     RECT  82.109 63.072 82.645 71.208 ;
     RECT  82.325 95.184 82.649 97.032 ;
     RECT  82.325 78.096 82.861 85.224 ;
     RECT  82.397 76.32 82.933 76.392 ;
     RECT  82.861 77.712 82.933 85.224 ;
     RECT  82.597 0.096 82.937 0.216 ;
     RECT  82.537 39.744 82.969 58.728 ;
     RECT  82.645 60.864 83.005 71.208 ;
     RECT  82.969 39.744 83.149 59.256 ;
     RECT  82.067 1.968 83.173 3.624 ;
     RECT  83.005 60.816 83.173 71.208 ;
     RECT  82.693 7.44 83.221 7.464 ;
     RECT  83.173 1.728 83.225 3.624 ;
     RECT  82.501 10.224 83.269 10.248 ;
     RECT  83.149 39.6 83.269 59.256 ;
     RECT  83.173 60.24 83.269 71.208 ;
     RECT  81.893 72.432 83.269 73.608 ;
     RECT  82.211 74.64 83.365 75.24 ;
     RECT  82.933 76.32 83.365 85.224 ;
     RECT  83.225 1.968 83.408 3.624 ;
     RECT  82.021 5.856 83.408 5.88 ;
     RECT  83.221 7.44 83.408 8.088 ;
     RECT  83.269 10.224 83.408 10.92 ;
     RECT  79.553 33.264 83.408 33.576 ;
     RECT  83.269 39.312 83.408 59.256 ;
     RECT  83.269 60.24 83.408 73.608 ;
     RECT  83.365 74.64 83.408 85.224 ;
     RECT  81.971 92.928 83.408 94.152 ;
     RECT  82.649 95.184 83.408 96.456 ;
     RECT  82.937 0.096 83.507 0.168 ;
     RECT  83.507 0.096 83.585 0.12 ;
     RECT  83.408 1.968 83.704 96.456 ;
     RECT  83.704 63.792 83.837 72.888 ;
     RECT  83.704 81.84 83.843 84.024 ;
     RECT  83.704 1.968 83.873 1.992 ;
     RECT  83.843 81.84 84.017 83.304 ;
     RECT  83.704 50.976 84.053 56.616 ;
     RECT  83.837 65.52 84.053 72.888 ;
     RECT  83.704 95.184 84.083 96.456 ;
     RECT  84.083 95.232 84.085 96.456 ;
     RECT  84.017 81.84 84.089 83.256 ;
     RECT  84.053 65.52 84.125 72.552 ;
     RECT  83.704 7.968 84.197 7.992 ;
     RECT  83.837 63.792 84.233 64.44 ;
     RECT  84.085 95.232 84.275 97.032 ;
     RECT  84.053 51.264 84.305 56.616 ;
     RECT  84.125 65.52 84.305 65.688 ;
     RECT  84.125 67.104 84.341 72.552 ;
     RECT  84.305 65.52 84.371 65.544 ;
     RECT  84.341 67.104 84.371 67.848 ;
     RECT  83.704 57.744 84.413 60.408 ;
     RECT  83.704 93.744 84.413 93.768 ;
     RECT  84.275 95.76 84.421 97.032 ;
     RECT  84.341 69.456 84.467 72.552 ;
     RECT  83.704 39.36 84.485 47.352 ;
     RECT  84.233 63.792 84.485 63.816 ;
     RECT  84.467 70.8 84.485 72.552 ;
     RECT  83.704 48.336 84.593 49.56 ;
     RECT  83.704 5.136 84.611 5.16 ;
     RECT  84.485 39.36 84.701 46.344 ;
     RECT  83.704 74.064 84.709 80.28 ;
     RECT  84.089 81.84 84.709 82.728 ;
     RECT  84.593 48.336 84.737 48.744 ;
     RECT  84.467 69.456 84.737 69.528 ;
     RECT  84.413 57.84 84.769 60.408 ;
     RECT  84.709 74.064 84.803 82.728 ;
     RECT  84.803 75.216 84.899 81.864 ;
     RECT  84.485 71.088 84.917 71.64 ;
     RECT  84.899 80.304 84.917 81.864 ;
     RECT  84.701 39.36 84.949 46.2 ;
     RECT  84.737 69.504 84.953 69.528 ;
     RECT  84.769 57.84 84.995 60.504 ;
     RECT  84.899 75.216 85.097 79.272 ;
     RECT  84.917 71.088 85.139 71.16 ;
     RECT  85.139 71.136 85.205 71.16 ;
     RECT  83.704 33.216 85.235 33.24 ;
     RECT  84.949 39.312 85.235 46.2 ;
     RECT  83.704 10.896 85.277 10.92 ;
     RECT  84.305 55.104 85.309 56.616 ;
     RECT  84.803 74.064 85.313 74.088 ;
     RECT  85.097 78.048 85.313 79.272 ;
     RECT  84.305 51.264 85.345 53.976 ;
     RECT  85.309 54.96 85.345 56.616 ;
     RECT  85.097 75.216 85.385 76.392 ;
     RECT  83.704 3.6 85.421 3.624 ;
     RECT  85.189 37.44 85.493 38.184 ;
     RECT  85.313 79.2 85.523 79.272 ;
     RECT  84.917 80.304 85.523 81.384 ;
     RECT  84.805 49.92 85.525 49.944 ;
     RECT  85.345 51.264 85.525 56.616 ;
     RECT  84.421 95.76 85.525 97.08 ;
     RECT  85.385 75.36 85.529 76.392 ;
     RECT  85.523 80.304 85.529 80.328 ;
     RECT  85.525 95.088 85.529 97.08 ;
     RECT  85.525 49.92 85.565 56.616 ;
     RECT  85.565 49.92 85.571 55.272 ;
     RECT  84.485 47.328 85.601 47.352 ;
     RECT  85.529 75.744 85.619 76.392 ;
     RECT  84.995 57.888 85.621 60.504 ;
     RECT  85.313 78.048 85.637 78.12 ;
     RECT  85.621 57.888 85.673 60.792 ;
     RECT  85.523 79.2 85.673 79.224 ;
     RECT  85.523 81.36 85.745 81.384 ;
     RECT  85.235 39.36 85.813 46.2 ;
     RECT  85.813 39.36 85.817 47.112 ;
     RECT  85.571 50.592 85.925 55.272 ;
     RECT  85.637 78.048 85.997 78.072 ;
     RECT  84.737 48.336 86.005 48.552 ;
     RECT  85.925 50.592 86.033 53.016 ;
     RECT  85.529 97.056 86.065 97.08 ;
     RECT  85.817 45.024 86.069 47.112 ;
     RECT  86.033 50.592 86.069 51.912 ;
     RECT  85.565 56.544 86.245 56.616 ;
     RECT  85.673 57.888 86.245 60.408 ;
     RECT  85.529 95.088 86.341 95.832 ;
     RECT  86.341 94.992 86.425 95.832 ;
     RECT  85.619 76.368 86.435 76.392 ;
     RECT  86.425 94.656 86.483 95.832 ;
     RECT  85.925 54.096 86.531 55.272 ;
     RECT  86.245 56.544 86.573 60.408 ;
     RECT  86.641 25.632 86.723 25.656 ;
     RECT  85.189 29.904 86.723 29.928 ;
     RECT  86.483 94.896 86.725 95.832 ;
     RECT  86.065 97.056 86.725 97.176 ;
     RECT  86.573 56.544 86.821 60.12 ;
     RECT  86.069 47.088 86.857 47.112 ;
     RECT  86.005 48.336 86.857 48.936 ;
     RECT  86.725 94.896 86.897 97.176 ;
     RECT  86.069 50.784 87.037 51.912 ;
     RECT  86.033 52.992 87.037 53.016 ;
     RECT  86.069 45.024 87.181 45.96 ;
     RECT  86.897 94.896 87.185 95.784 ;
     RECT  87.037 50.784 87.205 53.016 ;
     RECT  85.817 39.36 87.221 43.8 ;
     RECT  87.185 94.992 87.221 95.784 ;
     RECT  87.221 95.04 87.251 95.784 ;
     RECT  86.857 47.088 87.253 48.936 ;
     RECT  87.205 50.544 87.253 53.016 ;
     RECT  86.531 55.248 87.289 55.272 ;
     RECT  86.821 56.304 87.289 60.12 ;
     RECT  87.289 55.248 87.293 60.12 ;
     RECT  87.253 47.088 87.299 49.464 ;
     RECT  85.493 37.44 87.473 37.464 ;
     RECT  87.221 39.36 87.473 39.384 ;
     RECT  87.221 40.416 87.473 43.8 ;
     RECT  87.253 50.448 87.587 53.016 ;
     RECT  87.587 50.448 87.589 50.952 ;
     RECT  87.293 55.248 87.689 59.88 ;
     RECT  86.531 54.096 87.721 54.168 ;
     RECT  87.589 50.016 87.731 50.952 ;
     RECT  87.251 95.04 87.761 95.16 ;
     RECT  87.689 55.824 87.779 59.88 ;
     RECT  87.587 52.272 87.973 53.016 ;
     RECT  87.721 54.048 87.973 54.168 ;
     RECT  87.181 44.976 88.045 45.96 ;
     RECT  87.299 47.088 88.045 49.032 ;
     RECT  87.473 40.656 88.117 43.8 ;
     RECT  88.045 44.832 88.117 49.032 ;
     RECT  87.761 95.04 88.337 95.112 ;
     RECT  88.337 95.04 88.625 95.064 ;
     RECT  87.779 55.968 88.693 59.88 ;
     RECT  86.677 28.416 88.808 28.44 ;
     RECT  88.117 40.656 88.808 49.032 ;
     RECT  87.731 50.832 88.808 50.856 ;
     RECT  87.973 52.272 88.808 54.168 ;
     RECT  88.693 55.968 88.808 60.552 ;
     RECT  88.625 95.04 88.808 95.052 ;
     RECT  88.808 2.148 88.912 95.052 ;
     RECT  86.897 97.152 89.057 97.176 ;
     RECT  88.912 2.418 89.104 94.782 ;
     RECT  89.104 40.944 89.237 43.944 ;
     RECT  89.104 55.248 89.273 59.88 ;
     RECT  89.104 49.536 90.035 54.12 ;
     RECT  89.104 45.168 90.097 48.504 ;
     RECT  90.035 49.536 90.097 51.432 ;
     RECT  89.237 41.376 90.209 43.944 ;
     RECT  90.209 41.52 90.323 43.944 ;
     RECT  90.097 45.168 90.385 51.432 ;
     RECT  90.323 41.76 90.421 43.944 ;
     RECT  90.385 44.976 90.421 51.432 ;
     RECT  90.421 41.76 90.677 51.432 ;
     RECT  90.677 41.76 90.707 48.984 ;
     RECT  89.273 55.248 90.713 59.352 ;
     RECT  90.713 58.128 90.851 59.352 ;
     RECT  90.707 42.624 90.965 48.984 ;
     RECT  90.965 45.216 91.001 48.984 ;
     RECT  90.713 55.248 91.001 56.76 ;
     RECT  90.035 52.8 91.141 54.12 ;
     RECT  90.965 42.624 91.145 44.184 ;
     RECT  91.141 52.416 91.187 54.12 ;
     RECT  91.001 55.824 91.187 56.76 ;
     RECT  91.145 42.768 91.253 44.184 ;
     RECT  91.253 42.768 91.283 42.792 ;
     RECT  91.001 45.552 91.289 48.984 ;
     RECT  91.289 48.48 91.325 48.984 ;
     RECT  91.325 48.48 91.397 48.936 ;
     RECT  90.677 50.112 91.465 51.432 ;
     RECT  91.187 52.416 91.465 52.488 ;
     RECT  91.253 44.16 91.469 44.184 ;
     RECT  91.289 45.552 91.523 47.496 ;
     RECT  91.523 45.552 91.541 46.344 ;
     RECT  91.465 50.112 91.541 52.488 ;
     RECT  91.187 55.872 91.577 56.76 ;
     RECT  91.541 45.936 91.613 46.344 ;
     RECT  91.187 53.568 91.811 54.12 ;
     RECT  91.577 55.872 91.811 56.328 ;
     RECT  91.613 46.32 92.009 46.344 ;
     RECT  91.523 47.328 92.153 47.496 ;
     RECT  91.811 55.872 92.189 56.28 ;
     RECT  90.851 58.56 92.245 59.352 ;
     RECT  92.245 58.56 92.291 59.448 ;
     RECT  92.291 59.184 92.297 59.448 ;
     RECT  91.541 50.112 92.339 50.28 ;
     RECT  91.397 48.816 92.365 48.936 ;
     RECT  92.339 50.112 92.365 50.184 ;
     RECT  92.365 48.816 92.369 50.184 ;
     RECT  92.189 56.256 92.405 56.28 ;
     RECT  91.541 51.264 92.437 52.488 ;
     RECT  92.369 48.816 92.483 49.848 ;
     RECT  91.811 53.568 92.483 53.784 ;
     RECT  92.483 48.816 92.513 48.84 ;
     RECT  92.437 51.264 92.581 52.584 ;
     RECT  92.581 51.216 92.657 52.584 ;
     RECT  92.297 59.184 92.657 59.208 ;
     RECT  92.153 47.328 92.729 47.352 ;
     RECT  92.483 49.824 92.765 49.848 ;
     RECT  92.657 51.504 92.797 52.584 ;
     RECT  92.483 53.568 92.797 53.592 ;
     RECT  92.797 51.504 93.125 53.592 ;
     RECT  93.125 52.992 93.155 53.592 ;
     RECT  93.125 51.504 94.208 51.528 ;
     RECT  93.155 53.568 94.208 53.592 ;
     RECT  94.208 2.148 94.312 95.052 ;
     RECT  94.312 2.418 94.504 94.782 ;
    LAYER M5 ;
     RECT  29.136 0.016 42.12 0.131 ;
     RECT  6.864 0.016 9.864 1.763 ;
     RECT  51.408 0.016 57.48 2.137 ;
     RECT  2.4 2.137 2.52 2.151 ;
     RECT  13.2 2.137 13.32 2.151 ;
     RECT  45.6 2.137 45.72 2.151 ;
     RECT  61.8 2.137 61.92 2.151 ;
     RECT  64.464 0.016 83.592 2.151 ;
     RECT  88.8 2.137 88.92 2.151 ;
     RECT  94.2 2.137 94.32 2.151 ;
     RECT  64.464 2.151 83.712 2.197 ;
     RECT  29.136 0.131 42.024 2.245 ;
     RECT  51 2.137 57.48 2.245 ;
     RECT  6.864 1.763 9.768 2.339 ;
     RECT  16.08 0.016 27.624 2.435 ;
     RECT  29.136 2.245 43.32 2.485 ;
     RECT  29.088 2.485 43.32 2.629 ;
     RECT  51 2.245 57.672 2.629 ;
     RECT  28.992 2.629 43.32 2.821 ;
     RECT  7.344 2.339 9.672 2.963 ;
     RECT  16.368 2.435 27.624 2.963 ;
     RECT  64.368 2.197 83.712 2.963 ;
     RECT  7.344 2.963 9.192 3.011 ;
     RECT  63.216 2.821 63.24 3.011 ;
     RECT  64.368 2.963 75.24 3.157 ;
     RECT  49.008 3.349 49.032 3.397 ;
     RECT  16.368 2.963 26.472 3.443 ;
     RECT  76.368 2.963 83.712 3.589 ;
     RECT  28.608 2.821 43.32 3.733 ;
     RECT  45.6 2.151 45.912 3.733 ;
     RECT  12.096 3.685 12.12 3.877 ;
     RECT  13.2 2.151 13.512 3.877 ;
     RECT  63.792 3.157 75.24 3.925 ;
     RECT  76.368 3.589 84.6 3.925 ;
     RECT  27.552 2.963 27.624 4.019 ;
     RECT  28.608 3.733 43.368 4.019 ;
     RECT  50.544 2.629 57.672 4.019 ;
     RECT  59.808 3.301 59.832 4.019 ;
     RECT  16.368 3.443 25.704 4.067 ;
     RECT  47.952 3.397 47.976 4.115 ;
     RECT  43.344 4.019 43.368 4.259 ;
     RECT  50.544 4.019 57.24 4.451 ;
     RECT  16.368 4.067 18.912 4.595 ;
     RECT  20.112 4.067 20.232 4.595 ;
     RECT  23.328 4.067 25.704 4.595 ;
     RECT  28.944 4.019 42.168 4.595 ;
     RECT  49.008 3.397 49.464 4.595 ;
     RECT  37.584 4.595 37.608 4.643 ;
     RECT  21.6 4.067 22.296 4.691 ;
     RECT  28.944 4.595 36.408 4.691 ;
     RECT  38.832 4.595 42.168 4.691 ;
     RECT  20.16 4.595 20.232 4.739 ;
     RECT  38.88 4.691 42.168 4.787 ;
     RECT  63.792 3.925 84.6 4.789 ;
     RECT  28.992 4.691 36.408 4.979 ;
     RECT  21.6 4.691 22.2 5.077 ;
     RECT  23.328 4.595 25.368 5.077 ;
     RECT  45.36 3.733 45.912 5.077 ;
     RECT  7.344 3.011 8.424 5.171 ;
     RECT  63.504 4.789 84.6 5.171 ;
     RECT  50.544 4.451 57.096 5.219 ;
     RECT  39.168 4.787 42.168 5.365 ;
     RECT  61.8 2.151 62.112 5.605 ;
     RECT  23.232 5.077 25.368 5.653 ;
     RECT  20.976 5.077 22.2 5.747 ;
     RECT  23.232 5.653 25.752 5.747 ;
     RECT  63.504 5.171 83.712 5.747 ;
     RECT  20.976 5.747 22.056 5.893 ;
     RECT  27.6 4.019 27.624 5.893 ;
     RECT  49.344 4.595 49.464 6.037 ;
     RECT  45.216 5.077 46.728 6.133 ;
     RECT  12.096 3.877 13.512 6.229 ;
     RECT  29.04 4.979 36.408 6.229 ;
     RECT  48.816 6.037 49.464 6.229 ;
     RECT  45.216 6.133 46.776 6.277 ;
     RECT  63.504 5.747 64.392 6.323 ;
     RECT  65.472 5.747 83.712 6.323 ;
     RECT  48.72 6.229 49.512 6.325 ;
     RECT  51 5.219 57.096 6.325 ;
     RECT  58.416 5.077 58.44 6.613 ;
     RECT  60.912 5.605 62.112 6.613 ;
     RECT  7.8 5.171 8.424 6.757 ;
     RECT  20.256 5.893 22.056 6.851 ;
     RECT  39.168 5.365 42.312 6.949 ;
     RECT  60.576 6.613 62.112 7.045 ;
     RECT  63.504 6.323 63.528 7.045 ;
     RECT  28.8 6.229 36.408 7.141 ;
     RECT  28.8 7.141 36.888 7.189 ;
     RECT  38.448 6.949 42.312 7.189 ;
     RECT  25.728 5.747 25.752 7.237 ;
     RECT  26.736 5.893 27.624 7.237 ;
     RECT  48.72 6.325 57.096 7.379 ;
     RECT  7.8 6.757 8.52 7.381 ;
     RECT  16.896 4.595 18.912 7.381 ;
     RECT  43.92 5.749 43.944 7.381 ;
     RECT  11.808 6.229 13.512 7.475 ;
     RECT  45.216 6.277 47.208 7.475 ;
     RECT  60.576 7.045 63.528 7.475 ;
     RECT  65.52 6.323 83.712 7.475 ;
     RECT  23.232 5.747 24.408 7.477 ;
     RECT  65.52 7.475 81.816 7.669 ;
     RECT  45.504 7.475 47.208 7.717 ;
     RECT  50.496 7.379 57.096 7.717 ;
     RECT  58.416 6.613 58.776 7.717 ;
     RECT  50.496 7.717 58.776 7.763 ;
     RECT  48.72 7.379 49.512 7.859 ;
     RECT  28.8 7.189 42.312 7.957 ;
     RECT  20.256 6.851 21.624 8.003 ;
     RECT  28.8 7.957 42.36 8.003 ;
     RECT  60.576 7.475 60.6 8.005 ;
     RECT  83.232 7.475 83.712 8.099 ;
     RECT  22.8 7.477 24.408 8.341 ;
     RECT  25.728 7.237 27.624 8.341 ;
     RECT  11.76 7.909 11.784 8.579 ;
     RECT  16.128 7.381 18.912 8.579 ;
     RECT  22.8 8.341 27.624 8.579 ;
     RECT  45.504 7.717 47.448 8.579 ;
     RECT  61.8 7.475 63.528 8.675 ;
     RECT  43.92 7.381 43.992 8.677 ;
     RECT  43.92 8.677 44.472 8.723 ;
     RECT  65.088 7.669 81.816 8.725 ;
     RECT  48.912 7.859 49.512 8.917 ;
     RECT  50.544 7.763 58.776 8.917 ;
     RECT  28.8 8.003 36.888 9.013 ;
     RECT  38.208 8.003 42.36 9.013 ;
     RECT  45.6 8.579 47.448 9.107 ;
     RECT  48.912 8.917 58.776 9.301 ;
     RECT  17.28 8.579 18.912 9.731 ;
     RECT  48.912 9.301 59.016 9.779 ;
     RECT  45.6 9.107 47.352 9.925 ;
     RECT  52.752 9.779 59.016 10.021 ;
     RECT  60 8.005 60.6 10.021 ;
     RECT  64.944 8.725 81.816 10.211 ;
     RECT  83.4 8.099 83.712 10.213 ;
     RECT  64.944 10.211 81.624 10.403 ;
     RECT  23.232 8.579 27.624 10.501 ;
     RECT  28.8 9.013 42.36 10.741 ;
     RECT  45.456 9.925 47.352 10.883 ;
     RECT  28.8 10.741 42.504 10.931 ;
     RECT  83.28 10.213 83.712 10.931 ;
     RECT  52.752 10.021 60.6 10.933 ;
     RECT  61.8 8.675 62.856 10.933 ;
     RECT  44.448 8.723 44.472 11.221 ;
     RECT  45.456 10.883 47.064 11.221 ;
     RECT  22.656 10.501 27.624 11.365 ;
     RECT  64.944 10.403 65.112 11.365 ;
     RECT  16.128 8.579 16.152 11.411 ;
     RECT  48.912 9.779 51.672 11.413 ;
     RECT  52.752 10.933 62.856 11.413 ;
     RECT  28.944 10.931 42.504 11.459 ;
     RECT  44.448 11.221 47.064 11.507 ;
     RECT  64.512 11.365 65.112 11.509 ;
     RECT  66.096 10.403 81.624 11.509 ;
     RECT  44.448 11.507 46.968 11.653 ;
     RECT  48.912 11.413 62.856 11.797 ;
     RECT  29.136 11.459 42.504 11.843 ;
     RECT  22.656 11.365 27.96 12.371 ;
     RECT  7.488 7.381 8.52 12.611 ;
     RECT  64.512 11.509 81.624 12.611 ;
     RECT  29.136 11.843 42.312 12.755 ;
     RECT  48.816 11.797 62.856 12.757 ;
     RECT  48.672 12.757 62.856 12.899 ;
     RECT  38.16 12.755 42.312 12.901 ;
     RECT  43.776 11.653 46.968 12.901 ;
     RECT  48.672 12.899 49.608 12.901 ;
     RECT  38.16 12.901 49.608 12.947 ;
     RECT  7.488 12.611 8.424 13.139 ;
     RECT  38.16 12.947 46.344 13.139 ;
     RECT  47.856 12.947 49.608 13.619 ;
     RECT  7.488 13.139 8.112 13.715 ;
     RECT  22.656 12.371 27.336 13.957 ;
     RECT  65.04 12.611 81.624 14.147 ;
     RECT  22.656 13.957 27.432 14.197 ;
     RECT  49.152 13.619 49.608 14.197 ;
     RECT  50.592 12.899 62.856 14.197 ;
     RECT  18 9.731 18.912 14.773 ;
     RECT  29.136 12.755 36.696 14.773 ;
     RECT  38.16 13.139 42.312 14.773 ;
     RECT  29.136 14.773 42.312 14.867 ;
     RECT  18 14.773 19.08 15.301 ;
     RECT  20.256 8.003 21.144 15.301 ;
     RECT  49.152 14.197 62.856 15.301 ;
     RECT  22.608 14.197 27.432 15.349 ;
     RECT  22.608 15.349 27.912 15.395 ;
     RECT  29.136 14.867 37.32 15.637 ;
     RECT  65.088 14.147 81.624 15.637 ;
     RECT  49.152 15.301 62.952 15.683 ;
     RECT  47.856 13.619 47.88 15.685 ;
     RECT  47.616 15.685 47.88 15.781 ;
     RECT  47.328 15.781 47.88 15.827 ;
     RECT  27.888 15.395 27.912 15.877 ;
     RECT  28.992 15.637 37.32 15.877 ;
     RECT  27.888 15.877 37.32 16.019 ;
     RECT  43.584 13.139 46.344 16.355 ;
     RECT  38.4 14.867 42.312 16.405 ;
     RECT  43.584 16.355 43.8 16.405 ;
     RECT  45.216 16.355 46.344 16.451 ;
     RECT  38.4 16.405 43.8 16.931 ;
     RECT  27.888 16.019 37.272 17.123 ;
     RECT  49.152 15.683 62.856 17.125 ;
     RECT  38.832 16.931 43.8 17.461 ;
     RECT  45.216 16.451 46.2 17.461 ;
     RECT  47.328 15.827 47.64 17.509 ;
     RECT  22.608 15.395 26.76 17.557 ;
     RECT  38.832 17.461 46.2 17.603 ;
     RECT  18 15.301 21.144 17.699 ;
     RECT  64.416 15.637 81.624 17.699 ;
     RECT  49.056 17.125 62.856 17.843 ;
     RECT  49.056 17.843 57.384 17.891 ;
     RECT  18 17.699 18.912 17.989 ;
     RECT  28.128 17.123 37.272 18.133 ;
     RECT  38.832 17.603 46.104 18.133 ;
     RECT  49.152 17.891 57.384 18.227 ;
     RECT  64.992 17.699 81.624 18.659 ;
     RECT  22.464 17.557 26.76 18.803 ;
     RECT  64.992 18.659 73.368 18.851 ;
     RECT  22.56 18.803 26.76 18.995 ;
     RECT  17.616 17.989 18.912 19.045 ;
     RECT  20.256 17.699 21.144 19.045 ;
     RECT  47.28 17.509 47.64 19.045 ;
     RECT  27.936 18.133 37.272 19.139 ;
     RECT  49.344 18.227 57.384 19.285 ;
     RECT  38.736 18.133 46.104 19.333 ;
     RECT  15.36 18.757 15.384 19.475 ;
     RECT  17.616 19.045 21.144 19.475 ;
     RECT  22.656 18.995 26.76 19.523 ;
     RECT  38.64 19.333 46.104 19.571 ;
     RECT  16.512 18.757 16.536 20.387 ;
     RECT  12.768 7.475 13.512 20.437 ;
     RECT  11.376 18.949 11.4 20.579 ;
     RECT  44.928 19.571 46.104 20.581 ;
     RECT  47.28 19.045 47.736 20.581 ;
     RECT  49.056 19.285 57.384 20.627 ;
     RECT  12.768 20.437 13.608 20.677 ;
     RECT  18.6 19.475 21.144 20.677 ;
     RECT  12.768 20.677 13.752 21.013 ;
     RECT  65.088 18.851 73.368 21.109 ;
     RECT  18.096 20.677 21.144 21.155 ;
     RECT  49.344 20.627 57.384 21.157 ;
     RECT  58.416 17.843 62.856 21.157 ;
     RECT  44.928 20.581 47.736 21.251 ;
     RECT  27.936 19.139 37.224 21.539 ;
     RECT  49.344 21.157 62.856 21.539 ;
     RECT  18.096 21.155 19.032 21.683 ;
     RECT  58.416 21.539 62.856 21.779 ;
     RECT  20.256 21.155 21.144 21.781 ;
     RECT  22.656 19.523 24.312 21.781 ;
     RECT  12.48 21.013 13.752 21.971 ;
     RECT  20.256 21.781 24.312 22.021 ;
     RECT  25.344 19.523 26.76 22.021 ;
     RECT  45.456 21.251 47.736 22.213 ;
     RECT  45.456 22.213 48.312 22.355 ;
     RECT  9.648 10.213 9.672 22.499 ;
     RECT  20.256 22.021 26.76 22.549 ;
     RECT  61.584 21.779 62.856 22.787 ;
     RECT  14.832 22.789 14.856 22.885 ;
     RECT  27.936 21.539 36.408 23.029 ;
     RECT  14.832 22.885 14.952 23.077 ;
     RECT  18.6 21.683 18.912 23.077 ;
     RECT  19.92 22.549 26.76 23.077 ;
     RECT  12.48 21.971 13.656 23.125 ;
     RECT  16.8 22.741 16.824 23.317 ;
     RECT  38.64 19.571 43.896 23.317 ;
     RECT  64.992 21.109 73.368 23.317 ;
     RECT  12.24 23.125 13.656 23.411 ;
     RECT  61.632 22.787 62.856 23.603 ;
     RECT  45.456 22.355 46.056 23.605 ;
     RECT  27.744 23.029 36.408 23.845 ;
     RECT  12.24 23.411 13.512 23.893 ;
     RECT  27.744 23.845 36.456 23.893 ;
     RECT  64.944 23.317 73.368 23.893 ;
     RECT  74.352 18.659 81.624 23.893 ;
     RECT  47.28 22.355 48.312 24.083 ;
     RECT  47.28 24.083 47.544 24.277 ;
     RECT  14.832 23.077 15.528 24.421 ;
     RECT  38.256 23.317 43.896 24.467 ;
     RECT  45.456 23.605 46.152 24.469 ;
     RECT  47.232 24.277 47.544 24.469 ;
     RECT  16.8 23.317 17.304 24.563 ;
     RECT  18.6 23.077 26.76 24.563 ;
     RECT  49.344 21.539 57.384 24.659 ;
     RECT  12.192 23.893 13.512 24.709 ;
     RECT  14.832 24.421 15.768 24.755 ;
     RECT  64.944 23.893 81.624 24.757 ;
     RECT  14.928 24.755 15.768 24.899 ;
     RECT  27.744 23.893 36.888 24.899 ;
     RECT  38.256 24.467 43.848 24.947 ;
     RECT  50.544 24.659 57.384 25.477 ;
     RECT  58.416 21.779 60.6 25.477 ;
     RECT  12.192 24.709 13.848 25.523 ;
     RECT  61.68 23.603 62.856 25.525 ;
     RECT  50.544 25.477 60.6 25.715 ;
     RECT  7.8 13.715 8.112 25.861 ;
     RECT  27.744 24.899 36.456 25.861 ;
     RECT  27.744 25.861 36.984 26.291 ;
     RECT  64.752 24.757 81.624 26.389 ;
     RECT  25.344 24.563 26.76 26.725 ;
     RECT  63.888 26.389 81.624 26.771 ;
     RECT  49.344 24.659 49.464 26.773 ;
     RECT  38.256 24.947 43.8 26.819 ;
     RECT  59.616 25.715 60.6 26.819 ;
     RECT  15.12 24.899 15.768 26.917 ;
     RECT  45.456 24.469 47.544 27.059 ;
     RECT  49.344 26.773 49.608 27.061 ;
     RECT  59.808 26.819 60.6 27.107 ;
     RECT  18.6 24.563 24.312 27.155 ;
     RECT  12.336 25.523 13.848 27.299 ;
     RECT  7.8 25.861 8.232 27.301 ;
     RECT  10.992 27.205 11.016 27.301 ;
     RECT  18.6 27.155 18.912 27.301 ;
     RECT  38.64 26.819 43.8 27.301 ;
     RECT  45.456 27.059 47.304 27.301 ;
     RECT  60.048 27.107 60.6 27.301 ;
     RECT  61.68 25.525 62.904 27.301 ;
     RECT  15.12 26.917 15.816 27.349 ;
     RECT  15.12 27.349 16.056 27.395 ;
     RECT  38.64 27.301 47.304 27.443 ;
     RECT  15.456 27.395 16.056 27.635 ;
     RECT  43.68 27.443 47.304 27.635 ;
     RECT  15.792 27.635 16.056 27.637 ;
     RECT  17.28 24.563 17.304 27.637 ;
     RECT  18.48 27.301 18.912 27.637 ;
     RECT  43.68 27.635 44.472 27.683 ;
     RECT  10.992 27.301 11.352 27.685 ;
     RECT  25.296 26.725 26.76 27.877 ;
     RECT  27.744 26.291 32.472 27.877 ;
     RECT  15.792 27.637 18.912 27.971 ;
     RECT  48.528 27.061 49.608 28.163 ;
     RECT  7.8 27.301 8.52 28.307 ;
     RECT  12.336 27.299 13.512 28.451 ;
     RECT  25.296 27.877 32.472 28.451 ;
     RECT  63.888 26.771 63.912 28.451 ;
     RECT  65.088 26.771 81.624 28.453 ;
     RECT  9.504 28.261 9.528 28.549 ;
     RECT  10.56 27.685 11.352 28.549 ;
     RECT  12.768 28.451 13.512 28.741 ;
     RECT  43.776 27.683 44.472 28.789 ;
     RECT  45.456 27.635 47.304 28.789 ;
     RECT  38.64 27.443 42.504 28.837 ;
     RECT  43.776 28.789 47.304 28.837 ;
     RECT  18.6 27.971 18.912 28.981 ;
     RECT  20.016 27.155 24.312 28.981 ;
     RECT  33.456 26.291 36.984 28.981 ;
     RECT  48.768 28.163 49.608 29.027 ;
     RECT  25.344 28.451 32.472 29.075 ;
     RECT  9.504 28.549 11.352 29.219 ;
     RECT  12.768 28.741 13.608 29.363 ;
     RECT  15.984 27.971 17.592 29.365 ;
     RECT  9.888 29.219 11.352 29.461 ;
     RECT  60.048 27.301 62.904 29.557 ;
     RECT  64.416 28.453 81.624 29.557 ;
     RECT  60.048 29.557 81.624 29.795 ;
     RECT  48.915 29.027 49.608 29.797 ;
     RECT  50.592 25.715 58.632 29.797 ;
     RECT  38.64 28.837 47.304 29.843 ;
     RECT  86.688 25.621 86.712 29.939 ;
     RECT  48.915 29.797 58.632 30.035 ;
     RECT  18.6 28.981 24.312 30.037 ;
     RECT  25.344 29.075 26.76 30.037 ;
     RECT  33.456 28.981 37.128 30.275 ;
     RECT  9.888 29.461 11.448 30.277 ;
     RECT  12.768 29.363 13.512 30.277 ;
     RECT  9.888 30.277 13.512 30.323 ;
     RECT  15.6 29.365 17.592 30.371 ;
     RECT  15.6 30.371 17.496 30.851 ;
     RECT  9.984 30.323 13.512 30.901 ;
     RECT  18.6 30.037 26.76 30.949 ;
     RECT  27.744 29.075 32.472 30.949 ;
     RECT  65.088 29.795 81.624 31.235 ;
     RECT  38.64 29.843 43.944 31.477 ;
     RECT  44.928 29.843 47.304 31.477 ;
     RECT  38.64 31.477 47.304 31.523 ;
     RECT  48.915 30.035 58.44 31.861 ;
     RECT  60.048 29.795 63.816 31.861 ;
     RECT  9.984 30.901 13.608 31.907 ;
     RECT  16.704 30.851 17.496 31.909 ;
     RECT  18.6 30.949 32.472 31.909 ;
     RECT  48.915 31.861 63.816 31.955 ;
     RECT  50.592 31.955 63.816 32.005 ;
     RECT  65.088 31.235 65.112 32.005 ;
     RECT  66.096 31.235 81.624 32.195 ;
     RECT  12.768 31.907 13.608 32.437 ;
     RECT  33.456 30.275 36.936 32.437 ;
     RECT  16.704 31.909 32.472 32.581 ;
     RECT  33.456 32.437 37.176 32.581 ;
     RECT  16.704 32.581 37.176 32.723 ;
     RECT  18.48 32.723 37.176 32.725 ;
     RECT  38.64 31.523 39.192 32.725 ;
     RECT  50.592 32.005 65.112 32.819 ;
     RECT  16.704 32.723 17.496 32.963 ;
     RECT  40.2 31.523 47.304 33.013 ;
     RECT  48.915 31.955 49.464 33.013 ;
     RECT  50.592 32.819 57.384 33.013 ;
     RECT  16.704 32.963 17.304 33.059 ;
     RECT  18.48 32.725 39.192 33.107 ;
     RECT  77.904 32.195 81.624 33.155 ;
     RECT  9.984 31.907 11.736 33.539 ;
     RECT  12.768 32.437 13.704 33.541 ;
     RECT  40.2 33.013 57.384 33.683 ;
     RECT  58.416 32.819 65.112 33.683 ;
     RECT  12.72 33.541 13.704 33.827 ;
     RECT  40.2 33.683 43.992 34.115 ;
     RECT  60.048 33.683 65.112 34.115 ;
     RECT  15.6 30.851 15.624 34.117 ;
     RECT  15.408 34.117 15.624 34.165 ;
     RECT  16.8 33.059 17.304 34.165 ;
     RECT  54.192 33.683 57.384 34.165 ;
     RECT  58.416 33.683 58.44 34.165 ;
     RECT  18.48 33.107 31.128 34.259 ;
     RECT  32.112 33.107 39.192 34.355 ;
     RECT  44.976 33.683 53.208 34.355 ;
     RECT  44.976 34.355 49.464 34.403 ;
     RECT  10.416 33.539 11.736 34.405 ;
     RECT  12.72 33.827 13.608 34.405 ;
     RECT  18.48 34.259 31.032 34.595 ;
     RECT  15.408 34.165 17.304 34.643 ;
     RECT  38.16 34.355 39.192 34.741 ;
     RECT  40.2 34.115 42.984 34.741 ;
     RECT  45.456 34.403 49.464 34.787 ;
     RECT  15.408 34.643 17.112 34.835 ;
     RECT  48.816 34.787 49.464 34.883 ;
     RECT  38.16 34.741 42.984 34.931 ;
     RECT  43.968 34.115 43.992 34.979 ;
     RECT  10.416 34.405 13.608 35.077 ;
     RECT  64.944 34.115 65.112 35.317 ;
     RECT  66.096 32.195 76.728 35.317 ;
     RECT  10.416 35.077 14.184 35.363 ;
     RECT  64.944 35.317 76.728 35.363 ;
     RECT  32.112 34.355 37.176 35.411 ;
     RECT  10.416 35.363 10.824 35.459 ;
     RECT  27.744 34.595 31.032 35.555 ;
     RECT  12.096 35.363 14.184 35.603 ;
     RECT  10.464 35.459 10.824 35.699 ;
     RECT  50.592 34.355 53.208 35.701 ;
     RECT  54.192 34.165 58.44 35.701 ;
     RECT  12.096 35.603 13.608 35.747 ;
     RECT  45.456 34.787 47.352 35.845 ;
     RECT  48.915 34.883 49.464 35.845 ;
     RECT  16.8 34.835 17.112 35.939 ;
     RECT  15.408 34.835 15.624 35.989 ;
     RECT  60.048 34.115 63.864 36.035 ;
     RECT  45.024 35.845 47.352 36.227 ;
     RECT  18.48 34.595 26.76 36.323 ;
     RECT  16.848 35.939 17.112 36.325 ;
     RECT  18.48 36.323 18.912 36.325 ;
     RECT  19.968 36.323 26.76 36.515 ;
     RECT  50.592 35.701 58.44 36.515 ;
     RECT  60.048 36.035 63.816 36.563 ;
     RECT  54.192 36.515 58.44 36.661 ;
     RECT  48.432 35.845 49.464 36.901 ;
     RECT  50.592 36.515 53.208 36.901 ;
     RECT  54.192 36.661 58.488 36.995 ;
     RECT  32.112 35.411 37.08 36.997 ;
     RECT  38.16 34.931 38.184 36.997 ;
     RECT  39.168 34.931 42.984 37.043 ;
     RECT  20.112 36.515 26.76 37.091 ;
     RECT  27.744 35.555 30.888 37.139 ;
     RECT  60.048 36.563 62.856 37.141 ;
     RECT  14.736 35.989 15.624 37.189 ;
     RECT  16.848 36.325 18.912 37.189 ;
     RECT  32.112 36.997 38.184 37.331 ;
     RECT  14.736 37.189 18.912 37.427 ;
     RECT  12.192 35.747 13.608 37.477 ;
     RECT  14.736 37.427 17.208 37.477 ;
     RECT  65.088 35.363 76.728 37.571 ;
     RECT  10.704 35.699 10.824 37.573 ;
     RECT  12.192 37.477 17.208 37.573 ;
     RECT  10.704 37.573 17.208 37.859 ;
     RECT  65.088 37.571 72.912 38.101 ;
     RECT  45.456 36.227 47.352 38.149 ;
     RECT  39.168 37.043 39.192 38.197 ;
     RECT  40.2 37.043 42.984 38.197 ;
     RECT  64.416 38.101 72.912 38.243 ;
     RECT  28.128 37.139 30.888 38.581 ;
     RECT  32.112 37.331 37.848 38.581 ;
     RECT  20.112 37.091 24.312 38.675 ;
     RECT  28.128 38.581 37.848 38.675 ;
     RECT  18.6 37.427 18.912 38.677 ;
     RECT  25.344 37.091 26.76 38.677 ;
     RECT  48.432 36.901 53.208 38.771 ;
     RECT  33.456 38.675 37.848 38.819 ;
     RECT  39.168 38.197 42.984 38.819 ;
     RECT  44.592 38.149 47.352 38.819 ;
     RECT  50.592 38.771 53.208 38.819 ;
     RECT  33.456 38.819 36.984 38.915 ;
     RECT  20.208 38.675 24.312 38.963 ;
     RECT  10.704 37.859 16.872 39.011 ;
     RECT  74.016 37.571 76.728 39.011 ;
     RECT  20.256 38.963 24.312 39.061 ;
     RECT  25.344 38.677 27.048 39.061 ;
     RECT  45.456 38.819 47.352 39.205 ;
     RECT  48.432 38.771 49.464 39.205 ;
     RECT  11.664 39.011 16.872 39.251 ;
     RECT  52.608 38.819 53.208 39.253 ;
     RECT  54.192 36.995 58.44 39.253 ;
     RECT  12.288 39.251 16.872 39.301 ;
     RECT  17.952 38.677 18.912 39.301 ;
     RECT  83.4 10.931 83.712 39.301 ;
     RECT  85.2 29.893 85.224 39.301 ;
     RECT  84.96 39.301 85.224 39.347 ;
     RECT  12.288 39.301 18.912 39.395 ;
     RECT  33.456 38.915 36.84 39.395 ;
     RECT  14.736 39.395 18.912 39.443 ;
     RECT  74.16 39.011 76.728 39.637 ;
     RECT  78 33.155 81.624 39.637 ;
     RECT  15.072 39.443 18.912 39.875 ;
     RECT  45.456 39.205 49.464 39.875 ;
     RECT  64.416 38.243 65.112 39.875 ;
     RECT  15.36 39.875 18.912 39.971 ;
     RECT  84.96 39.347 84.984 39.971 ;
     RECT  15.6 39.971 18.912 40.115 ;
     RECT  74.16 39.637 81.624 40.213 ;
     RECT  73.968 40.213 81.624 40.357 ;
     RECT  20.256 39.061 27.048 40.405 ;
     RECT  33.456 39.395 36.408 40.405 ;
     RECT  37.584 39.877 37.608 40.405 ;
     RECT  83.28 39.301 83.712 40.405 ;
     RECT  86.592 39.829 86.616 40.405 ;
     RECT  12.768 39.395 13.512 40.453 ;
     RECT  20.16 40.405 27.048 40.499 ;
     RECT  52.608 39.253 58.44 40.549 ;
     RECT  45.456 39.875 47.448 40.595 ;
     RECT  85.488 40.405 87.432 40.645 ;
     RECT  88.8 2.151 89.112 40.645 ;
     RECT  52.608 40.549 58.584 40.693 ;
     RECT  59.568 37.141 62.856 40.693 ;
     RECT  66.096 38.243 72.912 40.693 ;
     RECT  73.968 40.357 81.72 40.693 ;
     RECT  10.368 39.301 10.392 40.835 ;
     RECT  16.752 40.115 18.912 40.835 ;
     RECT  33.456 40.405 37.608 40.835 ;
     RECT  85.488 40.645 89.112 40.835 ;
     RECT  12.768 40.453 13.608 40.837 ;
     RECT  16.848 40.835 18.912 40.979 ;
     RECT  48.432 39.875 49.464 40.981 ;
     RECT  85.488 40.835 86.328 40.981 ;
     RECT  16.848 40.979 17.352 41.123 ;
     RECT  66.096 40.693 81.72 41.173 ;
     RECT  82.752 40.405 83.712 41.173 ;
     RECT  84.912 40.981 86.328 41.173 ;
     RECT  12.72 40.837 13.608 41.221 ;
     RECT  12.72 41.221 13.656 41.365 ;
     RECT  64.512 39.875 65.112 41.365 ;
     RECT  66.096 41.173 86.328 41.365 ;
     RECT  20.16 40.499 26.76 41.411 ;
     RECT  50.592 38.819 51.432 41.413 ;
     RECT  52.608 40.693 62.856 41.413 ;
     RECT  25.344 41.411 26.76 41.557 ;
     RECT  45.456 40.595 47.352 41.557 ;
     RECT  50.592 41.413 62.856 41.603 ;
     RECT  18.48 40.979 18.912 41.651 ;
     RECT  50.592 41.603 58.872 41.651 ;
     RECT  39.168 38.819 39.192 41.653 ;
     RECT  87.408 40.835 89.112 41.699 ;
     RECT  50.592 41.651 58.632 41.747 ;
     RECT  90.288 41.509 90.312 41.749 ;
     RECT  64.512 41.365 86.328 41.797 ;
     RECT  60 41.603 62.856 41.845 ;
     RECT  63.936 41.797 86.328 41.845 ;
     RECT  60 41.845 86.328 42.035 ;
     RECT  33.456 40.835 37.272 42.037 ;
     RECT  38.592 41.653 39.192 42.037 ;
     RECT  20.16 41.411 24.312 42.227 ;
     RECT  28.128 38.675 32.472 42.227 ;
     RECT  65.088 42.035 86.328 42.227 ;
     RECT  10.416 41.509 10.44 42.275 ;
     RECT  12.72 41.365 14.136 42.325 ;
     RECT  28.128 42.227 30.888 42.325 ;
     RECT  45.024 41.557 47.352 42.517 ;
     RECT  48.384 40.981 49.464 42.517 ;
     RECT  5.712 42.229 5.736 42.613 ;
     RECT  88.32 41.699 89.112 42.709 ;
     RECT  5.136 42.613 5.736 42.755 ;
     RECT  18.6 41.651 18.912 42.757 ;
     RECT  45.024 42.517 49.464 42.757 ;
     RECT  88.08 42.709 89.112 42.757 ;
     RECT  90.288 41.749 90.696 42.757 ;
     RECT  5.664 42.755 5.736 42.803 ;
     RECT  33.456 42.037 39.192 42.805 ;
     RECT  40.2 38.819 42.984 42.805 ;
     RECT  5.712 42.803 5.736 42.995 ;
     RECT  60 42.035 63.96 42.995 ;
     RECT  50.592 41.747 58.44 43.043 ;
     RECT  27.792 42.325 30.888 43.139 ;
     RECT  74.352 42.227 81.72 43.189 ;
     RECT  12.576 42.325 14.136 43.237 ;
     RECT  54.192 43.043 58.44 43.237 ;
     RECT  25.344 41.557 26.808 43.283 ;
     RECT  7.8 28.307 8.112 43.285 ;
     RECT  28.128 43.139 30.888 43.285 ;
     RECT  54.192 43.237 58.68 43.285 ;
     RECT  65.088 42.227 73.368 43.285 ;
     RECT  74.352 43.189 81.864 43.285 ;
     RECT  83.136 42.227 86.328 43.285 ;
     RECT  65.088 43.285 86.328 43.379 ;
     RECT  90.288 42.757 91.272 43.379 ;
     RECT  44.064 42.757 49.464 43.427 ;
     RECT  28.128 43.285 30.936 43.525 ;
     RECT  32.112 42.227 32.472 43.525 ;
     RECT  6.816 43.285 8.112 43.669 ;
     RECT  16.848 41.123 17.16 43.669 ;
     RECT  12.048 43.237 14.136 43.717 ;
     RECT  15.6 40.115 15.624 43.765 ;
     RECT  28.128 43.525 32.472 43.765 ;
     RECT  33.456 42.805 42.984 43.765 ;
     RECT  87.744 42.757 89.112 43.811 ;
     RECT  60.048 42.995 63.96 43.859 ;
     RECT  6.816 43.669 8.76 43.861 ;
     RECT  15.6 43.765 15.72 43.861 ;
     RECT  16.848 43.669 17.448 43.861 ;
     RECT  18.48 42.757 18.912 43.861 ;
     RECT  20.256 42.227 24.312 43.861 ;
     RECT  25.344 43.283 26.76 43.861 ;
     RECT  61.68 43.859 63.96 43.861 ;
     RECT  5.232 43.813 5.256 44.341 ;
     RECT  10.704 43.861 10.728 44.341 ;
     RECT  11.952 43.717 14.136 44.341 ;
     RECT  78 43.379 86.328 44.341 ;
     RECT  6.672 43.861 9.72 44.579 ;
     RECT  28.128 43.765 42.984 44.675 ;
     RECT  15.408 43.861 15.72 44.867 ;
     RECT  33.456 44.675 42.984 44.915 ;
     RECT  4.944 44.341 5.256 44.965 ;
     RECT  6.672 44.579 8.76 44.965 ;
     RECT  54.192 43.285 58.968 44.965 ;
     RECT  60.048 43.859 60.6 44.965 ;
     RECT  88.08 43.811 89.112 44.965 ;
     RECT  77.904 44.341 86.328 45.011 ;
     RECT  85.488 45.011 86.328 45.059 ;
     RECT  10.704 44.341 14.136 45.155 ;
     RECT  61.68 43.861 64.056 45.203 ;
     RECT  54.192 44.965 60.6 45.205 ;
     RECT  15.6 44.867 15.72 45.251 ;
     RECT  40.2 44.915 42.984 45.397 ;
     RECT  44.064 43.427 44.088 45.397 ;
     RECT  4.944 44.965 8.76 45.445 ;
     RECT  61.8 45.203 64.056 45.541 ;
     RECT  65.088 43.379 76.728 45.541 ;
     RECT  91.248 43.379 91.272 45.541 ;
     RECT  11.04 45.155 14.136 45.587 ;
     RECT  87.696 44.965 89.112 45.587 ;
     RECT  11.088 45.587 14.136 45.635 ;
     RECT  33.456 44.915 39.192 45.635 ;
     RECT  12.528 45.635 14.136 45.731 ;
     RECT  85.488 45.059 86.04 45.923 ;
     RECT  91.248 45.541 91.512 45.925 ;
     RECT  88.08 45.587 89.112 45.971 ;
     RECT  61.8 45.541 76.728 46.069 ;
     RECT  61.8 46.069 76.824 46.117 ;
     RECT  77.904 45.011 84.312 46.117 ;
     RECT  16.848 43.861 26.76 46.163 ;
     RECT  15.6 45.251 15.624 46.165 ;
     RECT  61.8 46.117 84.312 46.259 ;
     RECT  37.728 45.635 39.192 46.307 ;
     RECT  61.8 46.259 83.712 46.307 ;
     RECT  38.832 46.307 39.192 46.547 ;
     RECT  11.088 45.635 11.112 46.597 ;
     RECT  12.528 45.731 13.512 46.597 ;
     RECT  88.128 45.971 89.112 46.597 ;
     RECT  4.752 45.445 8.76 46.645 ;
     RECT  50.592 43.043 53.208 46.741 ;
     RECT  3.984 46.645 8.76 46.787 ;
     RECT  88.128 46.597 89.448 46.787 ;
     RECT  90.768 45.925 91.512 46.787 ;
     RECT  61.8 46.307 73.368 46.835 ;
     RECT  45.456 43.427 49.464 46.837 ;
     RECT  50.448 46.741 53.208 46.837 ;
     RECT  37.728 46.307 37.752 46.883 ;
     RECT  15.36 46.165 15.624 46.885 ;
     RECT  16.848 46.163 18.912 46.885 ;
     RECT  90.768 46.787 91.032 47.075 ;
     RECT  20.256 46.163 26.76 47.125 ;
     RECT  40.2 45.397 44.088 47.125 ;
     RECT  45.456 46.837 53.208 47.125 ;
     RECT  74.352 46.307 83.712 47.171 ;
     RECT  33.456 45.635 36.408 47.221 ;
     RECT  15.36 46.885 18.912 47.363 ;
     RECT  40.2 47.125 53.208 47.363 ;
     RECT  85.536 45.923 86.04 47.363 ;
     RECT  66.096 46.835 73.368 47.413 ;
     RECT  74.352 47.171 76.824 47.413 ;
     RECT  11.088 46.597 13.512 47.459 ;
     RECT  88.272 46.787 89.448 47.459 ;
     RECT  88.32 47.459 89.448 47.461 ;
     RECT  66.096 47.413 76.824 47.555 ;
     RECT  4.368 46.787 5.208 47.603 ;
     RECT  45.36 47.363 53.208 47.701 ;
     RECT  54.192 45.205 60.792 47.701 ;
     RECT  15.6 47.363 18.912 47.797 ;
     RECT  20.256 47.125 26.952 47.797 ;
     RECT  11.088 47.459 11.112 47.845 ;
     RECT  12.144 47.459 13.512 47.845 ;
     RECT  45.36 47.701 60.792 47.891 ;
     RECT  91.008 47.075 91.032 47.939 ;
     RECT  4.464 47.603 5.208 48.229 ;
     RECT  6.624 46.787 8.76 48.229 ;
     RECT  88.32 47.461 89.88 48.229 ;
     RECT  52.32 47.891 60.792 48.277 ;
     RECT  61.8 46.835 65.112 48.277 ;
     RECT  78 47.171 83.712 48.325 ;
     RECT  74.352 47.555 76.824 48.373 ;
     RECT  77.856 48.325 83.712 48.373 ;
     RECT  4.464 48.229 8.76 48.421 ;
     RECT  15.6 47.797 26.952 48.421 ;
     RECT  40.2 47.363 44.328 48.421 ;
     RECT  45.36 47.891 51.312 48.421 ;
     RECT  74.352 48.373 83.712 48.467 ;
     RECT  66.096 47.555 73.368 48.659 ;
     RECT  74.352 48.467 82.152 48.755 ;
     RECT  4.464 48.421 8.952 48.805 ;
     RECT  15.6 48.421 27.096 48.805 ;
     RECT  37.92 47.653 37.944 48.805 ;
     RECT  39.168 46.547 39.192 48.805 ;
     RECT  52.32 48.277 65.112 48.899 ;
     RECT  87.264 48.421 87.288 48.901 ;
     RECT  88.32 48.229 90.024 48.901 ;
     RECT  86.016 47.363 86.04 48.947 ;
     RECT  12.144 47.845 14.232 48.949 ;
     RECT  74.352 48.755 75.144 48.949 ;
     RECT  87.264 48.901 90.312 49.043 ;
     RECT  37.92 48.805 39.192 49.283 ;
     RECT  15.456 48.805 27.096 49.381 ;
     RECT  4.464 48.805 9.24 49.477 ;
     RECT  10.224 47.845 11.112 49.477 ;
     RECT  76.128 48.755 82.152 49.477 ;
     RECT  83.4 48.467 83.712 49.477 ;
     RECT  12.144 48.949 14.28 49.525 ;
     RECT  15.456 49.381 27.144 49.525 ;
     RECT  28.128 44.675 32.472 49.525 ;
     RECT  33.456 47.221 36.456 49.525 ;
     RECT  92.304 48.805 92.328 49.525 ;
     RECT  52.32 48.899 59.016 49.619 ;
     RECT  4.464 49.477 11.112 49.667 ;
     RECT  74.016 48.949 75.144 49.715 ;
     RECT  38.16 49.283 39.192 49.765 ;
     RECT  40.2 48.421 51.312 49.765 ;
     RECT  92.304 49.525 92.472 49.813 ;
     RECT  87.264 49.043 87.624 50.005 ;
     RECT  12.096 49.525 14.28 50.053 ;
     RECT  15.456 49.525 36.456 50.053 ;
     RECT  52.608 49.619 59.016 50.053 ;
     RECT  60.048 48.899 65.112 50.053 ;
     RECT  9.456 49.667 11.112 50.101 ;
     RECT  12.096 50.053 36.456 50.101 ;
     RECT  9.456 50.101 36.456 50.243 ;
     RECT  92.304 49.813 92.664 50.291 ;
     RECT  52.608 50.053 65.112 50.339 ;
     RECT  14.784 50.243 36.456 50.387 ;
     RECT  38.16 49.765 51.312 50.435 ;
     RECT  63.936 50.339 65.112 50.435 ;
     RECT  87.264 50.005 87.72 50.533 ;
     RECT  38.16 50.435 49.464 50.579 ;
     RECT  50.448 50.435 51.312 50.581 ;
     RECT  52.608 50.339 62.904 50.581 ;
     RECT  85.536 49.909 85.56 50.581 ;
     RECT  14.784 50.387 36.408 50.627 ;
     RECT  50.448 50.581 62.904 50.627 ;
     RECT  64.32 50.435 65.112 50.629 ;
     RECT  66.096 48.659 72.912 50.629 ;
     RECT  9.456 50.243 13.752 50.675 ;
     RECT  4.464 49.667 8.232 50.677 ;
     RECT  9.456 50.675 13.608 50.677 ;
     RECT  0.144 48.709 0.168 50.771 ;
     RECT  64.32 50.629 72.912 50.819 ;
     RECT  85.536 50.581 86.04 50.819 ;
     RECT  40.2 50.579 49.464 50.915 ;
     RECT  76.128 49.477 83.712 50.965 ;
     RECT  44.304 50.915 49.464 51.011 ;
     RECT  60.048 50.627 62.904 51.203 ;
     RECT  4.464 50.677 13.608 51.253 ;
     RECT  60.048 51.203 62.856 51.299 ;
     RECT  86.016 50.819 86.04 51.347 ;
     RECT  76.128 50.965 84.024 51.395 ;
     RECT  50.448 50.627 59.016 51.443 ;
     RECT  76.224 51.395 84.024 51.443 ;
     RECT  87.216 50.533 87.72 51.443 ;
     RECT  44.352 51.011 49.464 51.635 ;
     RECT  74.352 49.715 75.144 51.683 ;
     RECT  3.792 51.253 13.608 51.923 ;
     RECT  38.16 50.579 39.192 51.923 ;
     RECT  40.2 50.915 43.32 51.923 ;
     RECT  78 51.443 84.024 51.923 ;
     RECT  87.552 51.443 87.72 51.923 ;
     RECT  3.792 51.923 8.112 52.067 ;
     RECT  15.6 50.627 36.408 52.163 ;
     RECT  78 51.923 83.712 52.163 ;
     RECT  9.36 51.923 13.608 52.213 ;
     RECT  87.696 51.923 87.72 52.261 ;
     RECT  88.8 49.043 90.024 52.261 ;
     RECT  38.832 51.923 39.192 52.307 ;
     RECT  87.696 52.261 90.024 52.307 ;
     RECT  65.088 50.819 72.912 52.357 ;
     RECT  52.608 51.443 59.016 52.405 ;
     RECT  9.36 52.213 13.656 52.453 ;
     RECT  39.024 52.307 39.192 52.453 ;
     RECT  40.2 51.923 42.984 52.453 ;
     RECT  91.152 52.405 91.176 52.453 ;
     RECT  92.448 50.291 92.664 52.453 ;
     RECT  64.512 52.357 72.912 52.499 ;
     RECT  9.36 52.453 13.848 52.547 ;
     RECT  17.28 52.163 36.408 52.595 ;
     RECT  17.328 52.595 36.408 52.787 ;
     RECT  91.152 52.453 92.664 52.883 ;
     RECT  9.504 52.547 13.848 52.981 ;
     RECT  76.224 51.443 76.824 52.981 ;
     RECT  78 52.163 82.152 52.981 ;
     RECT  91.776 52.883 92.664 52.981 ;
     RECT  20.256 52.787 36.408 53.075 ;
     RECT  52.368 52.405 59.016 53.075 ;
     RECT  26.736 53.075 36.408 53.267 ;
     RECT  64.704 52.499 72.912 53.269 ;
     RECT  74.352 51.683 75.048 53.269 ;
     RECT  83.4 52.163 83.712 53.269 ;
     RECT  9.504 52.981 14.472 53.363 ;
     RECT  61.68 51.299 62.856 53.365 ;
     RECT  4.368 52.067 8.112 53.509 ;
     RECT  9.504 53.363 9.768 53.509 ;
     RECT  39.024 52.453 42.984 53.557 ;
     RECT  64.704 53.269 75.048 53.557 ;
     RECT  76.224 52.981 82.152 53.557 ;
     RECT  83.28 53.269 83.712 53.557 ;
     RECT  54.192 53.075 59.016 53.603 ;
     RECT  91.776 52.981 93.144 53.603 ;
     RECT  61.632 53.365 62.856 53.605 ;
     RECT  76.224 53.557 83.712 53.795 ;
     RECT  91.776 53.603 92.472 53.795 ;
     RECT  39.024 53.557 43.32 53.845 ;
     RECT  44.352 51.635 44.376 53.845 ;
     RECT  88.08 52.307 89.976 53.845 ;
     RECT  39.024 53.845 44.376 53.893 ;
     RECT  45.456 51.635 49.464 53.893 ;
     RECT  64.464 53.557 75.048 53.893 ;
     RECT  76.224 53.795 76.824 53.893 ;
     RECT  85.296 52.981 85.32 53.893 ;
     RECT  88.08 53.845 90.504 54.037 ;
     RECT  17.328 52.787 19.176 54.083 ;
     RECT  10.8 53.363 14.472 54.085 ;
     RECT  15.6 52.163 16.2 54.085 ;
     RECT  26.88 53.267 36.408 54.085 ;
     RECT  50.448 51.443 51.312 54.085 ;
     RECT  52.368 53.075 53.208 54.085 ;
     RECT  4.368 53.509 9.768 54.131 ;
     RECT  4.512 54.131 9.768 54.179 ;
     RECT  64.464 53.893 76.824 54.227 ;
     RECT  20.256 53.075 25.752 54.419 ;
     RECT  66.096 54.227 76.824 54.419 ;
     RECT  61.632 53.605 63.192 54.563 ;
     RECT  26.88 54.085 37.368 54.565 ;
     RECT  61.632 54.563 62.856 54.565 ;
     RECT  4.512 54.179 6.552 54.611 ;
     RECT  84.72 53.893 85.32 54.661 ;
     RECT  20.256 54.419 24.504 54.707 ;
     RECT  54.192 53.603 58.44 54.755 ;
     RECT  26.88 54.565 37.608 55.141 ;
     RECT  39.024 53.893 49.464 55.141 ;
     RECT  84.72 54.661 85.416 55.141 ;
     RECT  7.8 54.179 9.768 55.187 ;
     RECT  78 53.795 83.712 55.237 ;
     RECT  84.72 55.141 85.512 55.237 ;
     RECT  66.096 54.419 76.44 55.283 ;
     RECT  78 55.237 85.512 55.331 ;
     RECT  10.8 54.085 16.2 55.429 ;
     RECT  17.376 54.083 19.176 55.429 ;
     RECT  7.8 55.187 8.664 55.811 ;
     RECT  88.08 54.037 90.696 55.813 ;
     RECT  91.776 53.795 91.8 55.813 ;
     RECT  25.488 54.419 25.752 55.907 ;
     RECT  26.88 55.141 49.464 55.907 ;
     RECT  83.232 55.331 85.512 55.907 ;
     RECT  26.88 55.907 44.472 55.909 ;
     RECT  25.488 55.907 25.512 55.955 ;
     RECT  83.232 55.907 85.32 55.955 ;
     RECT  78 55.331 82.056 55.957 ;
     RECT  10.8 55.429 19.176 56.099 ;
     RECT  18 56.099 19.176 56.101 ;
     RECT  20.256 54.707 24.408 56.101 ;
     RECT  10.8 56.099 16.632 56.147 ;
     RECT  18 56.101 24.408 56.387 ;
     RECT  26.688 55.909 44.472 56.483 ;
     RECT  83.232 55.955 83.832 56.483 ;
     RECT  84.96 55.955 85.32 56.483 ;
     RECT  4.512 54.611 6.36 56.531 ;
     RECT  87.744 55.813 91.8 56.531 ;
     RECT  77.376 55.957 82.056 56.581 ;
     RECT  83.232 56.483 83.712 56.581 ;
     RECT  4.512 56.531 5.304 56.627 ;
     RECT  26.688 56.483 36.6 56.627 ;
     RECT  88.08 56.531 91.8 56.627 ;
     RECT  7.8 55.811 8.232 56.629 ;
     RECT  20.16 56.387 24.408 56.677 ;
     RECT  9.744 55.187 9.768 56.771 ;
     RECT  88.8 56.627 91.8 56.771 ;
     RECT  86.496 51.877 86.52 56.869 ;
     RECT  13.2 56.147 16.632 57.011 ;
     RECT  86.496 56.869 86.568 57.013 ;
     RECT  5.28 56.627 5.304 57.059 ;
     RECT  37.584 56.483 44.472 57.059 ;
     RECT  86.496 57.013 86.616 57.059 ;
     RECT  61.584 54.565 62.856 57.107 ;
     RECT  7.68 56.629 8.232 57.299 ;
     RECT  7.68 57.299 8.112 57.301 ;
     RECT  20.16 56.677 24.888 57.301 ;
     RECT  86.544 57.059 86.616 57.587 ;
     RECT  39.168 57.059 44.472 57.635 ;
     RECT  77.376 56.581 83.712 57.635 ;
     RECT  13.2 57.011 16.296 57.733 ;
     RECT  77.376 57.635 82.104 57.827 ;
     RECT  6.288 56.531 6.36 57.875 ;
     RECT  26.88 56.627 36.6 57.875 ;
     RECT  64.464 54.227 65.112 57.875 ;
     RECT  84.96 56.483 85.272 57.875 ;
     RECT  85.248 57.875 85.272 57.923 ;
     RECT  45.456 55.907 49.464 58.021 ;
     RECT  50.448 54.085 53.208 58.021 ;
     RECT  10.8 56.147 11.88 58.115 ;
     RECT  83.232 57.635 83.712 58.117 ;
     RECT  88.8 56.771 90.6 58.117 ;
     RECT  91.776 56.771 91.8 58.117 ;
     RECT  10.8 58.115 11.784 58.163 ;
     RECT  65.088 57.875 65.112 58.163 ;
     RECT  66.096 55.283 76.296 58.259 ;
     RECT  88.8 58.117 91.8 58.403 ;
     RECT  7.632 57.301 8.112 58.451 ;
     RECT  18 56.387 19.128 58.501 ;
     RECT  90.48 58.403 91.8 58.549 ;
     RECT  13.056 57.733 16.296 58.645 ;
     RECT  17.424 58.501 19.128 58.645 ;
     RECT  20.16 57.301 25.128 58.645 ;
     RECT  60.048 51.299 60.6 58.645 ;
     RECT  61.68 57.107 62.856 58.645 ;
     RECT  86.592 57.587 86.616 58.645 ;
     RECT  26.88 57.875 36.456 58.691 ;
     RECT  90.48 58.549 92.28 58.691 ;
     RECT  7.68 58.451 8.112 58.739 ;
     RECT  63.888 58.069 63.912 58.739 ;
     RECT  66.096 58.259 72.912 58.739 ;
     RECT  77.424 57.827 82.104 58.739 ;
     RECT  83.232 58.117 83.832 58.739 ;
     RECT  86.4 58.645 86.616 58.739 ;
     RECT  10.8 58.163 11.592 58.787 ;
     RECT  13.056 58.645 25.128 58.787 ;
     RECT  58.416 54.755 58.44 58.789 ;
     RECT  87.792 58.117 87.816 58.835 ;
     RECT  6.288 57.875 6.312 58.931 ;
     RECT  58.416 58.789 58.488 59.029 ;
     RECT  60.048 58.645 62.856 59.075 ;
     RECT  26.88 58.691 36.408 59.171 ;
     RECT  90.816 58.691 92.28 59.219 ;
     RECT  61.68 59.075 62.856 59.221 ;
     RECT  83.232 58.739 83.712 59.221 ;
     RECT  88.8 58.403 89.112 59.221 ;
     RECT  39.168 57.635 44.328 59.363 ;
     RECT  91.776 59.219 92.28 59.363 ;
     RECT  11.568 58.787 11.592 59.459 ;
     RECT  13.104 58.787 24.552 59.459 ;
     RECT  92.256 59.363 92.28 59.459 ;
     RECT  16.896 59.459 24.552 59.507 ;
     RECT  37.584 57.059 38.136 59.557 ;
     RECT  39.168 59.363 43.416 59.557 ;
     RECT  16.896 59.507 24.408 59.603 ;
     RECT  54.192 54.755 57.384 59.797 ;
     RECT  58.416 59.029 59.064 59.797 ;
     RECT  84.816 59.221 84.84 59.797 ;
     RECT  86.4 58.739 86.424 59.797 ;
     RECT  66.288 58.739 72.912 59.989 ;
     RECT  61.68 59.221 63.864 60.035 ;
     RECT  13.2 59.459 15.72 60.131 ;
     RECT  63.84 60.035 63.864 60.133 ;
     RECT  37.584 59.557 43.416 60.277 ;
     RECT  45.456 58.021 53.208 60.277 ;
     RECT  61.68 60.035 62.856 60.277 ;
     RECT  13.2 60.131 14.232 60.323 ;
     RECT  37.536 60.277 43.416 60.373 ;
     RECT  60.048 59.075 60.6 60.373 ;
     RECT  61.632 60.277 62.856 60.373 ;
     RECT  84.816 59.797 86.424 60.515 ;
     RECT  88.704 59.221 89.112 60.563 ;
     RECT  74.352 58.259 76.296 60.565 ;
     RECT  85.632 60.515 86.424 60.803 ;
     RECT  63.84 60.133 64.68 60.851 ;
     RECT  66.096 59.989 72.912 60.853 ;
     RECT  74.352 60.565 76.392 60.853 ;
     RECT  33.456 59.171 36.408 60.949 ;
     RECT  37.536 60.373 43.512 60.949 ;
     RECT  77.424 58.739 81.624 60.949 ;
     RECT  83.184 59.221 83.712 60.949 ;
     RECT  33.456 60.949 43.512 61.091 ;
     RECT  45.312 60.277 53.208 61.141 ;
     RECT  66.096 60.853 76.392 61.141 ;
     RECT  65.856 61.141 76.392 61.381 ;
     RECT  77.376 60.949 81.624 61.381 ;
     RECT  60.048 60.373 62.856 61.429 ;
     RECT  26.88 59.171 32.472 61.477 ;
     RECT  33.456 61.091 37.608 61.477 ;
     RECT  54.192 59.797 59.064 61.525 ;
     RECT  60.048 61.429 62.904 61.525 ;
     RECT  16.896 59.603 24.312 61.619 ;
     RECT  65.856 61.381 81.624 61.669 ;
     RECT  82.656 60.949 83.712 61.669 ;
     RECT  65.856 61.669 83.712 61.715 ;
     RECT  26.88 61.477 37.608 61.763 ;
     RECT  44.976 61.141 53.208 61.813 ;
     RECT  65.856 61.715 76.392 61.859 ;
     RECT  18.048 61.619 24.312 61.907 ;
     RECT  54.192 61.525 62.904 62.005 ;
     RECT  64.032 60.851 64.68 62.005 ;
     RECT  15.6 60.131 15.72 62.051 ;
     RECT  18.48 61.907 24.312 62.195 ;
     RECT  32.112 61.763 37.608 62.195 ;
     RECT  77.376 61.715 83.712 62.195 ;
     RECT  77.808 62.195 83.712 62.435 ;
     RECT  44.88 61.813 53.208 62.437 ;
     RECT  18.6 62.195 24.312 62.725 ;
     RECT  25.584 62.485 25.608 62.725 ;
     RECT  44.736 62.437 53.208 62.725 ;
     RECT  38.736 61.091 43.512 63.013 ;
     RECT  44.64 62.725 53.208 63.013 ;
     RECT  38.736 63.013 53.208 63.203 ;
     RECT  18.6 62.725 25.608 63.299 ;
     RECT  33.456 62.195 37.608 63.781 ;
     RECT  38.736 63.203 42.984 63.781 ;
     RECT  77.808 62.435 82.104 63.781 ;
     RECT  54.192 62.005 64.68 63.827 ;
     RECT  33.456 63.781 42.984 63.875 ;
     RECT  54.192 63.827 60.072 63.875 ;
     RECT  77.472 63.781 82.104 63.973 ;
     RECT  61.2 63.827 64.68 64.307 ;
     RECT  20.16 63.299 25.608 64.355 ;
     RECT  33.456 63.875 38.184 64.355 ;
     RECT  61.2 64.307 62.856 64.355 ;
     RECT  77.472 63.973 82.152 64.357 ;
     RECT  83.4 62.435 83.712 64.405 ;
     RECT  83.4 64.405 84.024 64.597 ;
     RECT  20.16 64.355 25.128 64.691 ;
     RECT  32.112 62.195 32.472 64.885 ;
     RECT  33.456 64.355 37.512 64.885 ;
     RECT  16.896 61.619 17.016 65.027 ;
     RECT  64.032 64.307 64.68 65.171 ;
     RECT  61.536 64.355 62.856 65.413 ;
     RECT  32.112 64.885 37.512 65.509 ;
     RECT  54.192 63.875 59.064 65.509 ;
     RECT  60.048 63.875 60.072 65.509 ;
     RECT  65.856 61.859 76.248 65.509 ;
     RECT  83.28 64.597 84.024 65.509 ;
     RECT  61.536 65.413 62.904 65.555 ;
     RECT  61.536 65.555 62.856 65.653 ;
     RECT  77.424 64.357 82.152 65.653 ;
     RECT  83.28 65.509 84.36 65.653 ;
     RECT  20.16 64.691 24.504 65.749 ;
     RECT  65.808 65.509 76.248 66.037 ;
     RECT  77.424 65.653 84.36 66.037 ;
     RECT  39.168 63.875 42.984 66.181 ;
     RECT  43.968 63.203 53.208 66.181 ;
     RECT  20.16 65.749 25.416 66.325 ;
     RECT  26.88 61.763 30.888 66.325 ;
     RECT  65.808 66.037 84.36 66.325 ;
     RECT  18.6 63.299 19.128 66.661 ;
     RECT  20.16 66.325 30.888 66.661 ;
     RECT  64.032 65.171 64.152 66.661 ;
     RECT  65.52 66.325 84.36 66.661 ;
     RECT  54.192 65.509 60.072 66.755 ;
     RECT  18.6 66.661 30.888 67.091 ;
     RECT  39.168 66.181 53.208 67.237 ;
     RECT  54.192 66.755 59.16 67.237 ;
     RECT  26.208 67.091 30.888 67.283 ;
     RECT  64.032 66.661 84.36 67.283 ;
     RECT  64.032 67.283 64.392 67.285 ;
     RECT  26.88 67.283 30.888 67.381 ;
     RECT  32.112 65.509 37.656 67.381 ;
     RECT  26.88 67.381 37.656 67.523 ;
     RECT  61.056 65.653 62.856 67.621 ;
     RECT  63.84 67.285 64.392 67.621 ;
     RECT  65.52 67.283 84.36 67.859 ;
     RECT  65.52 67.859 84.312 67.907 ;
     RECT  18.6 67.091 24.504 67.955 ;
     RECT  77.376 67.907 84.312 67.955 ;
     RECT  39.168 67.237 59.16 68.099 ;
     RECT  83.28 67.955 84.312 68.195 ;
     RECT  20.16 67.955 24.504 68.389 ;
     RECT  58.416 68.099 59.16 68.389 ;
     RECT  39.168 68.099 57.384 68.435 ;
     RECT  61.056 67.621 64.392 68.483 ;
     RECT  26.88 67.523 37.416 68.773 ;
     RECT  26.112 68.773 37.416 68.821 ;
     RECT  26.112 68.821 37.8 69.059 ;
     RECT  39.168 68.435 53.208 69.059 ;
     RECT  58.416 68.389 60.024 69.203 ;
     RECT  61.344 68.483 64.392 69.493 ;
     RECT  77.376 67.955 81.768 69.493 ;
     RECT  83.4 68.195 84.312 69.493 ;
     RECT  65.52 67.907 76.248 69.541 ;
     RECT  18.6 67.955 19.128 69.685 ;
     RECT  20.16 68.389 24.648 69.685 ;
     RECT  77.376 69.493 84.312 69.731 ;
     RECT  65.472 69.541 76.248 69.875 ;
     RECT  54.192 68.435 57.384 70.021 ;
     RECT  58.416 69.203 59.256 70.021 ;
     RECT  61.008 69.493 64.392 70.069 ;
     RECT  82.704 69.731 84.312 70.069 ;
     RECT  54.192 70.021 59.256 70.211 ;
     RECT  27.12 69.059 37.8 70.259 ;
     RECT  77.856 69.731 81.576 70.307 ;
     RECT  44.784 69.059 53.208 70.357 ;
     RECT  54.192 70.211 57.384 70.357 ;
     RECT  58.416 70.211 59.256 70.595 ;
     RECT  26.112 69.059 26.136 70.645 ;
     RECT  27.12 70.259 31.08 70.645 ;
     RECT  39.168 69.059 43.656 70.645 ;
     RECT  44.784 70.357 57.384 70.645 ;
     RECT  32.448 70.259 37.8 70.691 ;
     RECT  61.008 70.069 64.68 70.691 ;
     RECT  82.704 70.069 84.456 71.077 ;
     RECT  26.112 70.645 31.08 71.171 ;
     RECT  18.6 69.685 24.648 71.173 ;
     RECT  15.6 62.051 15.624 71.221 ;
     RECT  16.896 65.027 16.92 71.221 ;
     RECT  77.904 70.307 81.576 71.315 ;
     RECT  58.416 70.595 59.16 71.651 ;
     RECT  66.096 69.875 76.248 71.653 ;
     RECT  61.344 70.691 64.68 71.701 ;
     RECT  61.008 71.701 64.68 71.749 ;
     RECT  39.168 70.645 57.384 71.939 ;
     RECT  66.096 71.653 76.584 72.037 ;
     RECT  44.448 71.939 57.384 72.179 ;
     RECT  15.6 71.221 16.92 72.277 ;
     RECT  34.656 70.691 37.8 72.277 ;
     RECT  18.288 71.173 24.648 72.325 ;
     RECT  26.928 71.171 31.08 72.421 ;
     RECT  32.448 70.691 33.528 72.421 ;
     RECT  44.448 72.179 53.208 72.515 ;
     RECT  78 71.315 81.576 72.515 ;
     RECT  26.928 72.421 33.528 72.565 ;
     RECT  60.816 71.749 64.68 72.707 ;
     RECT  61.68 72.707 64.68 72.755 ;
     RECT  58.416 71.651 58.728 72.805 ;
     RECT  59.712 72.277 59.736 72.805 ;
     RECT  61.8 72.755 64.68 72.853 ;
     RECT  61.8 72.853 64.92 72.947 ;
     RECT  54.192 72.179 57.384 72.949 ;
     RECT  17.952 72.325 24.648 73.045 ;
     RECT  26.16 72.565 33.528 73.045 ;
     RECT  34.656 72.277 38.184 73.237 ;
     RECT  39.168 71.939 43.368 73.237 ;
     RECT  65.952 72.037 76.584 73.283 ;
     RECT  63.168 72.947 64.92 73.285 ;
     RECT  65.952 73.283 75.048 73.285 ;
     RECT  44.448 72.515 44.472 73.379 ;
     RECT  15.6 72.277 16.968 73.429 ;
     RECT  15.408 73.429 16.968 73.477 ;
     RECT  14.688 73.477 16.968 73.813 ;
     RECT  17.952 73.045 33.528 73.813 ;
     RECT  13.2 60.323 13.608 73.957 ;
     RECT  45.456 72.515 53.208 74.053 ;
     RECT  45.072 74.053 53.208 74.149 ;
     RECT  54.192 72.949 57.432 74.149 ;
     RECT  63.168 73.285 75.048 74.243 ;
     RECT  45.072 74.149 57.432 74.389 ;
     RECT  65.712 74.243 75.048 74.389 ;
     RECT  76.032 73.283 76.584 74.389 ;
     RECT  78 72.515 81.432 74.437 ;
     RECT  82.704 71.077 85.128 74.437 ;
     RECT  34.656 73.237 43.368 74.533 ;
     RECT  65.712 74.389 76.584 74.581 ;
     RECT  78 74.437 85.128 74.581 ;
     RECT  13.056 73.957 13.608 74.629 ;
     RECT  58.416 72.805 59.736 74.629 ;
     RECT  45.024 74.389 57.432 74.675 ;
     RECT  65.712 74.581 85.128 74.675 ;
     RECT  65.712 74.675 72.912 74.723 ;
     RECT  34.656 74.533 43.992 75.155 ;
     RECT  14.688 73.813 33.528 75.157 ;
     RECT  34.656 75.155 37.8 75.157 ;
     RECT  38.976 75.155 43.992 75.299 ;
     RECT  63.168 74.243 64.68 75.299 ;
     RECT  74.016 74.675 85.128 75.395 ;
     RECT  14.688 75.157 37.8 75.443 ;
     RECT  45.024 74.675 53.208 75.491 ;
     RECT  86.4 60.803 86.424 75.733 ;
     RECT  12.96 74.629 13.608 75.781 ;
     RECT  14.688 75.443 37.464 75.781 ;
     RECT  54.192 74.675 57.432 75.827 ;
     RECT  38.976 75.299 43.464 75.875 ;
     RECT  12.96 75.781 37.464 75.971 ;
     RECT  34.8 75.971 37.464 76.211 ;
     RECT  64.176 75.299 64.68 76.357 ;
     RECT  12.96 75.971 33.624 76.403 ;
     RECT  85.488 75.733 86.424 76.403 ;
     RECT  12.96 76.403 32.376 76.451 ;
     RECT  12.96 76.451 30.888 76.499 ;
     RECT  74.016 75.395 83.928 76.501 ;
     RECT  63.168 75.299 63.192 76.549 ;
     RECT  64.176 76.357 65.16 76.549 ;
     RECT  45.024 75.491 49.464 76.837 ;
     RECT  50.448 75.491 53.208 76.837 ;
     RECT  61.8 72.947 62.112 76.837 ;
     RECT  39.024 75.875 43.464 76.933 ;
     RECT  58.416 74.629 59.832 76.933 ;
     RECT  60.816 76.837 62.112 76.933 ;
     RECT  45.024 76.837 53.208 76.981 ;
     RECT  73.92 76.501 83.928 77.029 ;
     RECT  33.504 76.403 33.624 77.125 ;
     RECT  34.8 76.211 37.08 77.125 ;
     RECT  38.832 76.933 43.464 77.125 ;
     RECT  44.832 76.981 53.208 77.171 ;
     RECT  58.416 76.933 62.112 77.173 ;
     RECT  63.168 76.549 65.16 77.173 ;
     RECT  33.504 77.125 37.08 77.315 ;
     RECT  45.024 77.171 53.208 77.411 ;
     RECT  73.92 77.029 84.024 77.461 ;
     RECT  85.488 76.403 85.608 77.461 ;
     RECT  45.024 77.411 51.432 77.555 ;
     RECT  58.416 77.173 65.16 77.555 ;
     RECT  66.288 74.723 72.912 77.557 ;
     RECT  73.92 77.461 85.608 77.557 ;
     RECT  13.056 76.499 30.888 77.603 ;
     RECT  38.544 77.125 43.464 77.701 ;
     RECT  52.512 77.411 53.208 77.701 ;
     RECT  54.192 75.827 57.384 77.701 ;
     RECT  7.8 58.739 8.112 77.797 ;
     RECT  17.568 77.603 30.888 77.893 ;
     RECT  31.872 76.451 32.376 77.893 ;
     RECT  17.568 77.893 32.376 78.085 ;
     RECT  58.416 77.555 62.952 78.131 ;
     RECT  66.288 77.557 85.608 78.131 ;
     RECT  17.568 78.085 32.472 78.227 ;
     RECT  38.016 77.701 43.464 78.373 ;
     RECT  38.016 78.373 43.752 78.469 ;
     RECT  45.024 77.555 47.208 78.469 ;
     RECT  66.288 78.131 85.512 78.613 ;
     RECT  60.528 78.131 62.112 78.755 ;
     RECT  38.016 78.469 47.208 78.757 ;
     RECT  17.568 78.227 30.936 78.947 ;
     RECT  52.512 77.701 57.384 78.997 ;
     RECT  58.416 78.131 58.872 78.997 ;
     RECT  52.512 78.997 58.872 79.043 ;
     RECT  66.144 78.613 85.512 79.189 ;
     RECT  66.144 79.189 85.656 79.283 ;
     RECT  13.056 77.603 16.44 79.285 ;
     RECT  66.144 79.283 81.912 79.475 ;
     RECT  17.664 78.947 30.936 79.573 ;
     RECT  32.16 78.227 32.472 79.573 ;
     RECT  10.08 77.605 10.104 79.717 ;
     RECT  60.816 78.755 62.112 79.717 ;
     RECT  37.68 78.757 47.208 79.763 ;
     RECT  60.048 79.717 62.112 79.765 ;
     RECT  76.128 79.475 81.864 79.859 ;
     RECT  78 79.859 81.864 80.003 ;
     RECT  82.896 79.283 85.656 80.003 ;
     RECT  48.336 77.555 51.432 80.293 ;
     RECT  12.72 79.285 16.44 80.341 ;
     RECT  17.664 79.573 32.472 80.341 ;
     RECT  33.504 77.315 36.456 80.341 ;
     RECT  37.68 79.763 43.464 80.341 ;
     RECT  76.128 79.859 76.92 80.435 ;
     RECT  12.72 80.341 32.472 80.531 ;
     RECT  59.808 79.765 62.112 80.531 ;
     RECT  66.144 79.475 75.048 80.819 ;
     RECT  52.512 79.043 58.824 80.821 ;
     RECT  59.808 80.531 60.072 80.821 ;
     RECT  48.336 80.293 51.48 80.867 ;
     RECT  33.504 80.341 43.464 80.915 ;
     RECT  16.896 80.531 32.472 81.011 ;
     RECT  12.72 80.531 15.864 81.059 ;
     RECT  44.448 79.763 47.208 81.061 ;
     RECT  64.656 77.555 65.16 81.109 ;
     RECT  52.512 80.821 60.072 81.347 ;
     RECT  84.72 80.003 85.656 81.395 ;
     RECT  78 80.003 81.816 81.445 ;
     RECT  13.104 81.059 15.864 81.587 ;
     RECT  44.064 81.061 47.208 81.587 ;
     RECT  13.2 81.587 15.864 81.635 ;
     RECT  33.504 80.915 42.984 81.635 ;
     RECT  84.72 81.395 84.888 81.875 ;
     RECT  77.904 81.445 81.816 81.877 ;
     RECT  82.896 80.003 83.712 81.877 ;
     RECT  25.632 81.011 32.472 81.923 ;
     RECT  16.896 81.011 24.552 81.971 ;
     RECT  44.064 81.587 47.16 82.115 ;
     RECT  48.336 80.867 51.432 82.309 ;
     RECT  52.608 81.347 60.072 82.309 ;
     RECT  48.336 82.309 60.072 82.549 ;
     RECT  61.104 80.531 62.112 82.549 ;
     RECT  13.2 81.635 15.624 82.597 ;
     RECT  16.896 81.971 19.368 82.597 ;
     RECT  64.656 81.109 65.208 82.597 ;
     RECT  25.632 81.923 32.184 82.691 ;
     RECT  37.68 81.635 42.984 82.691 ;
     RECT  84.72 81.875 84.792 82.739 ;
     RECT  25.632 82.691 32.04 82.787 ;
     RECT  33.504 81.635 36.408 82.789 ;
     RECT  77.904 81.877 83.712 82.789 ;
     RECT  48.336 82.549 62.112 82.883 ;
     RECT  13.2 82.597 19.368 83.029 ;
     RECT  38.208 82.691 42.984 83.029 ;
     RECT  44.064 82.115 46.872 83.029 ;
     RECT  20.544 81.971 24.552 83.171 ;
     RECT  38.208 83.029 46.872 83.267 ;
     RECT  54.624 82.883 62.112 83.267 ;
     RECT  77.904 82.789 83.832 83.267 ;
     RECT  13.056 83.029 19.368 83.315 ;
     RECT  66.288 80.819 75.048 83.557 ;
     RECT  76.176 80.435 76.92 83.557 ;
     RECT  44.544 83.267 46.872 83.795 ;
     RECT  25.632 82.787 31.944 83.797 ;
     RECT  33.504 82.789 36.696 83.797 ;
     RECT  48.336 82.883 53.592 83.797 ;
     RECT  78 83.267 83.832 84.035 ;
     RECT  25.632 83.797 36.696 84.181 ;
     RECT  38.208 83.267 43.368 84.181 ;
     RECT  54.624 83.267 60.408 84.323 ;
     RECT  13.056 83.315 19.176 84.371 ;
     RECT  25.632 84.181 43.368 84.371 ;
     RECT  64.656 82.597 65.256 84.371 ;
     RECT  78 84.035 83.712 84.371 ;
     RECT  14.784 84.371 19.176 84.373 ;
     RECT  66.288 83.557 76.92 84.515 ;
     RECT  37.44 84.371 43.368 84.563 ;
     RECT  14.784 84.373 19.224 84.611 ;
     RECT  64.656 84.371 65.064 84.611 ;
     RECT  60.048 84.323 60.408 84.659 ;
     RECT  20.544 83.171 24.456 84.709 ;
     RECT  25.632 84.371 30.744 84.709 ;
     RECT  17.712 84.611 19.224 84.901 ;
     RECT  48.288 83.797 53.592 84.947 ;
     RECT  37.44 84.563 42.984 84.995 ;
     RECT  60.048 84.659 60.072 84.995 ;
     RECT  48.288 84.947 53.208 85.043 ;
     RECT  13.056 84.371 13.512 85.093 ;
     RECT  48.288 85.043 49.224 85.093 ;
     RECT  78 84.371 82.392 85.187 ;
     RECT  44.784 83.795 46.872 85.189 ;
     RECT  17.712 84.901 19.512 85.381 ;
     RECT  20.544 84.709 30.744 85.381 ;
     RECT  12.96 85.093 13.512 85.429 ;
     RECT  14.784 84.611 16.536 85.429 ;
     RECT  17.712 85.381 30.744 85.763 ;
     RECT  7.8 77.797 8.76 85.813 ;
     RECT  10.08 79.717 10.248 85.813 ;
     RECT  17.712 85.763 19.56 85.909 ;
     RECT  54.624 84.323 58.44 85.957 ;
     RECT  54.624 85.957 58.68 86.005 ;
     RECT  66.288 84.515 76.824 86.005 ;
     RECT  12.96 85.429 16.536 86.051 ;
     RECT  20.544 85.763 30.744 86.293 ;
     RECT  31.872 84.371 36.408 86.293 ;
     RECT  14.784 86.051 16.536 86.437 ;
     RECT  17.616 85.909 19.56 86.437 ;
     RECT  64.656 84.611 65.016 86.437 ;
     RECT  66.144 86.005 76.824 86.437 ;
     RECT  12.96 86.051 13.512 86.581 ;
     RECT  64.656 86.437 76.824 86.581 ;
     RECT  78 85.187 81.432 86.581 ;
     RECT  37.44 84.995 38.328 86.629 ;
     RECT  14.784 86.437 19.56 86.675 ;
     RECT  54.624 86.005 59.064 86.675 ;
     RECT  37.44 86.629 38.472 86.771 ;
     RECT  20.544 86.293 36.408 86.819 ;
     RECT  50.448 85.043 53.208 86.869 ;
     RECT  54.624 86.675 58.68 86.869 ;
     RECT  50.448 86.869 58.68 87.011 ;
     RECT  14.832 86.675 19.56 87.061 ;
     RECT  20.544 86.819 31.032 87.061 ;
     RECT  7.8 85.813 10.248 87.157 ;
     RECT  12.096 86.581 13.512 87.251 ;
     RECT  14.832 87.061 31.032 87.539 ;
     RECT  44.448 85.189 46.872 87.589 ;
     RECT  47.856 85.093 49.224 87.589 ;
     RECT  37.44 86.771 38.232 87.635 ;
     RECT  44.448 87.589 49.224 87.733 ;
     RECT  50.448 87.011 58.104 87.733 ;
     RECT  44.448 87.733 58.104 87.779 ;
     RECT  15.6 87.539 31.032 87.827 ;
     RECT  32.496 86.819 36.408 87.827 ;
     RECT  64.656 86.581 81.432 87.827 ;
     RECT  32.496 87.827 33.672 88.019 ;
     RECT  15.6 87.827 16.536 88.115 ;
     RECT  59.808 87.397 59.832 88.163 ;
     RECT  33.504 88.019 33.672 88.403 ;
     RECT  66.144 87.827 81.432 88.403 ;
     RECT  17.76 87.827 31.032 88.691 ;
     RECT  44.448 87.779 57.672 88.691 ;
     RECT  66.144 88.403 76.824 88.883 ;
     RECT  44.592 88.691 57.672 88.885 ;
     RECT  17.76 88.691 24.456 88.931 ;
     RECT  44.592 88.885 58.104 88.979 ;
     RECT  37.632 87.635 38.232 89.123 ;
     RECT  25.632 88.691 31.032 89.171 ;
     RECT  25.632 89.171 30.744 89.267 ;
     RECT  39.6 84.995 42.984 89.459 ;
     RECT  66.24 88.883 76.824 89.459 ;
     RECT  32.496 88.019 32.52 89.461 ;
     RECT  21.696 88.931 24.456 89.555 ;
     RECT  66.24 89.459 76.296 89.555 ;
     RECT  17.76 88.931 20.568 89.699 ;
     RECT  21.696 89.555 24.408 89.699 ;
     RECT  37.632 89.123 38.136 89.941 ;
     RECT  22.224 89.699 24.408 89.987 ;
     RECT  50.208 88.979 58.104 90.035 ;
     RECT  19.92 89.699 20.568 90.083 ;
     RECT  25.632 89.267 25.8 90.275 ;
     RECT  66.288 89.555 76.296 90.275 ;
     RECT  66.288 90.275 73.032 90.515 ;
     RECT  40.032 89.459 42.984 90.517 ;
     RECT  26.928 89.267 30.744 90.611 ;
     RECT  37.536 89.941 38.136 90.659 ;
     RECT  39.936 90.517 42.984 90.659 ;
     RECT  50.304 90.035 58.104 90.659 ;
     RECT  33.648 88.403 33.672 90.803 ;
     RECT  74.4 90.275 76.296 90.803 ;
     RECT  37.536 90.659 37.752 90.899 ;
     RECT  26.928 90.611 30.216 91.091 ;
     RECT  32.112 89.461 32.52 91.093 ;
     RECT  39.936 90.659 41.352 91.141 ;
     RECT  44.592 88.979 49.224 91.187 ;
     RECT  34.8 87.827 36.408 91.381 ;
     RECT  37.536 90.899 37.656 91.715 ;
     RECT  32.112 91.093 33.048 91.811 ;
     RECT  33.024 91.811 33.048 91.859 ;
     RECT  45.36 91.187 49.224 91.907 ;
     RECT  50.304 90.659 58.056 91.907 ;
     RECT  37.536 91.715 37.56 91.955 ;
     RECT  39.264 91.141 41.352 92.099 ;
     RECT  45.36 91.907 47.112 92.243 ;
     RECT  34.704 91.381 36.408 92.291 ;
     RECT  52.32 91.907 58.056 92.293 ;
     RECT  66.288 90.515 72.912 92.387 ;
     RECT  45.6 92.243 47.112 92.435 ;
     RECT  52.32 92.293 58.152 92.819 ;
     RECT  76.224 90.803 76.296 92.869 ;
     RECT  76.176 92.869 76.296 92.915 ;
     RECT  26.928 91.091 30.168 92.963 ;
     RECT  52.32 92.819 53.256 92.963 ;
     RECT  66.288 92.387 70.056 92.963 ;
     RECT  71.04 92.387 72.912 93.011 ;
     RECT  54.288 92.819 58.152 93.059 ;
     RECT  7.8 87.157 10.344 93.539 ;
     RECT  15.6 88.115 15.624 93.539 ;
     RECT  17.76 89.699 18.912 93.539 ;
     RECT  25.776 90.275 25.8 93.539 ;
     RECT  26.928 92.963 26.952 93.539 ;
     RECT  28.128 92.963 30.168 93.539 ;
     RECT  34.8 92.291 36.408 93.539 ;
     RECT  54.624 93.059 58.152 93.539 ;
     RECT  34.8 93.539 35.688 93.779 ;
     RECT  76.176 92.915 76.248 93.779 ;
     RECT  20.544 90.083 20.568 94.021 ;
     RECT  69.456 92.963 70.056 94.021 ;
     RECT  71.04 93.011 71.256 94.021 ;
     RECT  45.6 92.435 46.872 94.069 ;
     RECT  22.224 89.987 24.312 94.115 ;
     RECT  42.96 90.659 42.984 94.115 ;
     RECT  50.304 91.907 51.312 94.115 ;
     RECT  66.288 92.963 68.424 94.115 ;
     RECT  74.4 90.803 75.048 94.115 ;
     RECT  76.224 93.779 76.248 94.115 ;
     RECT  78 88.403 81.432 94.163 ;
     RECT  39.792 92.099 41.352 94.357 ;
     RECT  52.608 92.963 53.256 94.405 ;
     RECT  54.624 93.539 55.176 94.405 ;
     RECT  72.288 93.011 72.912 94.405 ;
     RECT  69.456 94.021 71.256 94.453 ;
     RECT  72.24 94.405 72.912 94.453 ;
     RECT  80.208 94.163 81.432 94.453 ;
     RECT  9.552 93.539 10.344 94.501 ;
     RECT  7.8 93.539 8.112 94.549 ;
     RECT  9.264 94.501 10.344 94.549 ;
     RECT  24 94.115 24.312 94.549 ;
     RECT  56.4 93.539 57.48 94.549 ;
     RECT  61.8 83.267 62.112 94.549 ;
     RECT  74.544 94.115 75.048 94.595 ;
     RECT  28.56 93.539 30.168 94.597 ;
     RECT  45.6 94.069 47.112 94.597 ;
     RECT  48.336 91.907 49.224 94.597 ;
     RECT  52.608 94.405 55.176 94.643 ;
     RECT  20.544 94.021 20.808 94.645 ;
     RECT  53.184 94.643 55.176 94.691 ;
     RECT  64.656 87.827 64.68 94.691 ;
     RECT  74.544 94.595 74.568 94.691 ;
     RECT  78 94.163 79.176 94.691 ;
     RECT  28.464 94.597 30.168 94.835 ;
     RECT  56.4 94.549 57.672 94.837 ;
     RECT  53.808 94.691 55.176 94.885 ;
     RECT  56.304 94.837 57.672 94.885 ;
     RECT  86.448 94.645 86.472 94.885 ;
     RECT  27.024 94.645 27.048 94.981 ;
     RECT  69.456 94.453 72.912 94.981 ;
     RECT  86.448 94.885 87.144 94.981 ;
     RECT  26.736 94.981 27.048 95.029 ;
     RECT  2.4 2.151 2.712 95.049 ;
     RECT  13.2 87.251 13.512 95.049 ;
     RECT  18.6 93.539 18.912 95.049 ;
     RECT  28.464 94.835 29.712 95.049 ;
     RECT  34.8 93.779 35.112 95.049 ;
     RECT  61.68 94.549 62.112 95.049 ;
     RECT  88.8 60.563 89.112 95.049 ;
     RECT  94.2 2.151 94.512 95.049 ;
     RECT  2.4 95.049 2.52 95.063 ;
     RECT  13.2 95.049 13.32 95.063 ;
     RECT  18.6 95.049 18.72 95.063 ;
     RECT  34.8 95.049 34.92 95.063 ;
     RECT  61.68 95.049 61.92 95.063 ;
     RECT  78 94.691 78.312 95.063 ;
     RECT  88.8 95.049 88.92 95.063 ;
     RECT  94.2 95.049 94.32 95.063 ;
     RECT  20.496 94.645 20.808 95.077 ;
     RECT  22.32 94.115 22.872 95.077 ;
     RECT  61.68 95.063 61.896 95.077 ;
     RECT  86.352 94.981 87.144 95.077 ;
     RECT  7.8 94.549 10.344 95.125 ;
     RECT  20.496 95.077 22.872 95.125 ;
     RECT  24 94.549 24.456 95.125 ;
     RECT  25.68 94.645 25.704 95.125 ;
     RECT  26.736 95.029 27.432 95.125 ;
     RECT  28.464 95.049 29.64 95.125 ;
     RECT  39.792 94.357 41.64 95.125 ;
     RECT  45.072 94.597 49.224 95.125 ;
     RECT  50.88 94.115 51.312 95.125 ;
     RECT  53.808 94.885 57.672 95.125 ;
     RECT  59.76 94.741 59.784 95.125 ;
     RECT  61.008 95.077 61.896 95.125 ;
     RECT  66.672 94.115 67.848 95.125 ;
     RECT  68.88 94.981 72.912 95.125 ;
     RECT  80.208 94.453 81.96 95.125 ;
     RECT  39.696 95.125 41.64 95.173 ;
     RECT  42.816 94.453 42.888 95.173 ;
     RECT  53.808 95.125 58.056 95.173 ;
     RECT  59.184 95.125 61.896 95.173 ;
     RECT  66.672 95.125 72.912 95.173 ;
     RECT  80.112 95.125 81.96 95.173 ;
     RECT  83.4 84.371 83.712 95.173 ;
     RECT  80.112 95.173 84.072 95.221 ;
     RECT  65.232 95.173 65.256 95.269 ;
     RECT  66.288 95.173 72.912 95.269 ;
     RECT  39.696 95.173 42.888 95.413 ;
     RECT  44.016 94.981 44.04 95.413 ;
     RECT  39.696 95.413 44.04 95.461 ;
     RECT  45.072 95.125 51.816 95.461 ;
     RECT  53.808 95.173 61.896 95.701 ;
     RECT  65.232 95.269 72.912 95.701 ;
     RECT  39.696 95.461 51.816 95.749 ;
     RECT  53.616 95.701 61.896 95.749 ;
     RECT  80.112 95.221 84.264 95.749 ;
     RECT  85.584 95.077 87.144 95.749 ;
     RECT  78.096 95.063 78.312 95.797 ;
     RECT  65.232 95.701 73.224 95.845 ;
     RECT  7.536 95.125 10.344 96.277 ;
     RECT  65.232 95.845 73.416 96.277 ;
     RECT  78.096 95.797 78.408 96.277 ;
     RECT  7.44 96.277 10.344 96.325 ;
     RECT  65.232 96.277 73.992 96.325 ;
     RECT  78.096 96.277 78.504 96.325 ;
     RECT  79.632 95.749 87.24 96.325 ;
     RECT  65.136 96.325 74.184 97.045 ;
     RECT  7.44 96.325 10.44 97.168 ;
     RECT  20.496 95.125 29.64 97.168 ;
     RECT  39.696 95.749 51.912 97.168 ;
     RECT  53.424 95.749 61.896 97.168 ;
     RECT  65.04 97.045 74.184 97.168 ;
     RECT  78.096 96.325 87.24 97.168 ;
  END
END ot_qkvd_fbuf8
END LIBRARY
